VERSION 5.8 ;
BUSBITCHARS "[]" ;
DIVIDERCHAR "/" ;
UNITS
    DATABASE MICRONS 1000 ;
END UNITS

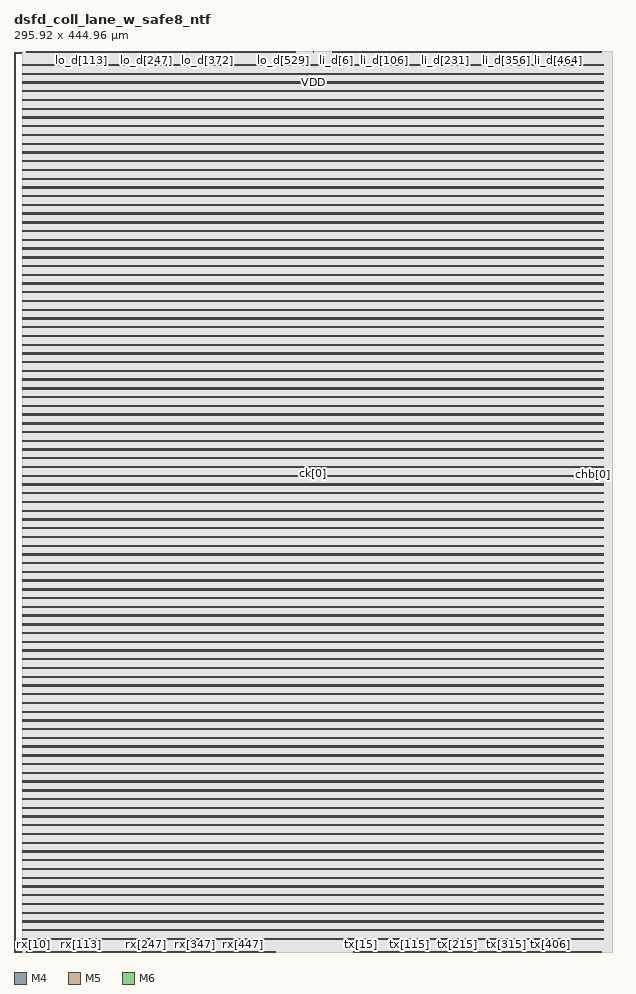
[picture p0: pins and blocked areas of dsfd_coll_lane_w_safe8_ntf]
MACRO dsfd_coll_lane_w_safe8_ntf
  FOREIGN dsfd_coll_lane_w_safe8_ntf 0 0 ;
  CLASS BLOCK ;
  SIZE 295.92 BY 444.96 ;
  PIN chb[0]
    DIRECTION INPUT ;
    USE SIGNAL ;
    PORT
      LAYER M4 ;
        RECT  295.836 236.016 295.92 236.04 ;
    END
  END chb[0]
  PIN ck[0]
    DIRECTION INPUT ;
    USE SIGNAL ;
    PORT
      LAYER M5 ;
        RECT  147.924 236.232 147.972 236.76 ;
    END
  END ck[0]
  PIN flt[0]
    DIRECTION OUTPUT ;
    USE SIGNAL ;
    PORT
      LAYER M4 ;
        RECT  295.836 234.576 295.92 234.6 ;
    END
  END flt[0]
  PIN flt[1]
    DIRECTION OUTPUT ;
    USE SIGNAL ;
    PORT
      LAYER M4 ;
        RECT  295.836 235.056 295.92 235.08 ;
    END
  END flt[1]
  PIN flt[2]
    DIRECTION OUTPUT ;
    USE SIGNAL ;
    PORT
      LAYER M4 ;
        RECT  295.836 235.536 295.92 235.56 ;
    END
  END flt[2]
  PIN li_d[0]
    DIRECTION OUTPUT ;
    USE SIGNAL ;
    PORT
      LAYER M5 ;
        RECT  157.92 444.876 157.944 444.96 ;
    END
  END li_d[0]
  PIN li_d[100]
    DIRECTION OUTPUT ;
    USE SIGNAL ;
    PORT
      LAYER M5 ;
        RECT  181.92 444.876 181.944 444.96 ;
    END
  END li_d[100]
  PIN li_d[101]
    DIRECTION OUTPUT ;
    USE SIGNAL ;
    PORT
      LAYER M5 ;
        RECT  182.16 444.876 182.184 444.96 ;
    END
  END li_d[101]
  PIN li_d[102]
    DIRECTION OUTPUT ;
    USE SIGNAL ;
    PORT
      LAYER M5 ;
        RECT  182.4 444.876 182.424 444.96 ;
    END
  END li_d[102]
  PIN li_d[103]
    DIRECTION OUTPUT ;
    USE SIGNAL ;
    PORT
      LAYER M5 ;
        RECT  182.64 444.876 182.664 444.96 ;
    END
  END li_d[103]
  PIN li_d[104]
    DIRECTION OUTPUT ;
    USE SIGNAL ;
    PORT
      LAYER M5 ;
        RECT  182.88 444.876 182.904 444.96 ;
    END
  END li_d[104]
  PIN li_d[105]
    DIRECTION OUTPUT ;
    USE SIGNAL ;
    PORT
      LAYER M5 ;
        RECT  183.12 444.876 183.144 444.96 ;
    END
  END li_d[105]
  PIN li_d[106]
    DIRECTION OUTPUT ;
    USE SIGNAL ;
    PORT
      LAYER M5 ;
        RECT  183.36 444.876 183.384 444.96 ;
    END
  END li_d[106]
  PIN li_d[107]
    DIRECTION OUTPUT ;
    USE SIGNAL ;
    PORT
      LAYER M5 ;
        RECT  183.6 444.876 183.624 444.96 ;
    END
  END li_d[107]
  PIN li_d[108]
    DIRECTION OUTPUT ;
    USE SIGNAL ;
    PORT
      LAYER M5 ;
        RECT  183.84 444.876 183.864 444.96 ;
    END
  END li_d[108]
  PIN li_d[109]
    DIRECTION OUTPUT ;
    USE SIGNAL ;
    PORT
      LAYER M5 ;
        RECT  184.08 444.876 184.104 444.96 ;
    END
  END li_d[109]
  PIN li_d[10]
    DIRECTION OUTPUT ;
    USE SIGNAL ;
    PORT
      LAYER M5 ;
        RECT  160.32 444.876 160.344 444.96 ;
    END
  END li_d[10]
  PIN li_d[110]
    DIRECTION OUTPUT ;
    USE SIGNAL ;
    PORT
      LAYER M5 ;
        RECT  184.32 444.876 184.344 444.96 ;
    END
  END li_d[110]
  PIN li_d[111]
    DIRECTION OUTPUT ;
    USE SIGNAL ;
    PORT
      LAYER M5 ;
        RECT  184.56 444.876 184.584 444.96 ;
    END
  END li_d[111]
  PIN li_d[112]
    DIRECTION OUTPUT ;
    USE SIGNAL ;
    PORT
      LAYER M5 ;
        RECT  184.8 444.876 184.824 444.96 ;
    END
  END li_d[112]
  PIN li_d[113]
    DIRECTION OUTPUT ;
    USE SIGNAL ;
    PORT
      LAYER M5 ;
        RECT  185.04 444.876 185.064 444.96 ;
    END
  END li_d[113]
  PIN li_d[114]
    DIRECTION OUTPUT ;
    USE SIGNAL ;
    PORT
      LAYER M5 ;
        RECT  185.28 444.876 185.304 444.96 ;
    END
  END li_d[114]
  PIN li_d[115]
    DIRECTION OUTPUT ;
    USE SIGNAL ;
    PORT
      LAYER M5 ;
        RECT  185.52 444.876 185.544 444.96 ;
    END
  END li_d[115]
  PIN li_d[116]
    DIRECTION OUTPUT ;
    USE SIGNAL ;
    PORT
      LAYER M5 ;
        RECT  185.76 444.876 185.784 444.96 ;
    END
  END li_d[116]
  PIN li_d[117]
    DIRECTION OUTPUT ;
    USE SIGNAL ;
    PORT
      LAYER M5 ;
        RECT  186 444.876 186.024 444.96 ;
    END
  END li_d[117]
  PIN li_d[118]
    DIRECTION OUTPUT ;
    USE SIGNAL ;
    PORT
      LAYER M5 ;
        RECT  186.24 444.876 186.264 444.96 ;
    END
  END li_d[118]
  PIN li_d[119]
    DIRECTION OUTPUT ;
    USE SIGNAL ;
    PORT
      LAYER M5 ;
        RECT  186.48 444.876 186.504 444.96 ;
    END
  END li_d[119]
  PIN li_d[11]
    DIRECTION OUTPUT ;
    USE SIGNAL ;
    PORT
      LAYER M5 ;
        RECT  160.56 444.876 160.584 444.96 ;
    END
  END li_d[11]
  PIN li_d[120]
    DIRECTION OUTPUT ;
    USE SIGNAL ;
    PORT
      LAYER M5 ;
        RECT  186.72 444.876 186.744 444.96 ;
    END
  END li_d[120]
  PIN li_d[121]
    DIRECTION OUTPUT ;
    USE SIGNAL ;
    PORT
      LAYER M5 ;
        RECT  186.96 444.876 186.984 444.96 ;
    END
  END li_d[121]
  PIN li_d[122]
    DIRECTION OUTPUT ;
    USE SIGNAL ;
    PORT
      LAYER M5 ;
        RECT  187.2 444.876 187.224 444.96 ;
    END
  END li_d[122]
  PIN li_d[123]
    DIRECTION OUTPUT ;
    USE SIGNAL ;
    PORT
      LAYER M5 ;
        RECT  187.44 444.876 187.464 444.96 ;
    END
  END li_d[123]
  PIN li_d[124]
    DIRECTION OUTPUT ;
    USE SIGNAL ;
    PORT
      LAYER M5 ;
        RECT  187.68 444.876 187.704 444.96 ;
    END
  END li_d[124]
  PIN li_d[125]
    DIRECTION OUTPUT ;
    USE SIGNAL ;
    PORT
      LAYER M5 ;
        RECT  187.92 444.876 187.944 444.96 ;
    END
  END li_d[125]
  PIN li_d[126]
    DIRECTION OUTPUT ;
    USE SIGNAL ;
    PORT
      LAYER M5 ;
        RECT  188.16 444.876 188.184 444.96 ;
    END
  END li_d[126]
  PIN li_d[127]
    DIRECTION OUTPUT ;
    USE SIGNAL ;
    PORT
      LAYER M5 ;
        RECT  188.4 444.876 188.424 444.96 ;
    END
  END li_d[127]
  PIN li_d[128]
    DIRECTION OUTPUT ;
    USE SIGNAL ;
    PORT
      LAYER M5 ;
        RECT  188.64 444.876 188.664 444.96 ;
    END
  END li_d[128]
  PIN li_d[129]
    DIRECTION OUTPUT ;
    USE SIGNAL ;
    PORT
      LAYER M5 ;
        RECT  188.88 444.876 188.904 444.96 ;
    END
  END li_d[129]
  PIN li_d[12]
    DIRECTION OUTPUT ;
    USE SIGNAL ;
    PORT
      LAYER M5 ;
        RECT  160.8 444.876 160.824 444.96 ;
    END
  END li_d[12]
  PIN li_d[130]
    DIRECTION OUTPUT ;
    USE SIGNAL ;
    PORT
      LAYER M5 ;
        RECT  189.12 444.876 189.144 444.96 ;
    END
  END li_d[130]
  PIN li_d[131]
    DIRECTION OUTPUT ;
    USE SIGNAL ;
    PORT
      LAYER M5 ;
        RECT  189.36 444.876 189.384 444.96 ;
    END
  END li_d[131]
  PIN li_d[132]
    DIRECTION OUTPUT ;
    USE SIGNAL ;
    PORT
      LAYER M5 ;
        RECT  189.6 444.876 189.624 444.96 ;
    END
  END li_d[132]
  PIN li_d[133]
    DIRECTION OUTPUT ;
    USE SIGNAL ;
    PORT
      LAYER M5 ;
        RECT  189.84 444.876 189.864 444.96 ;
    END
  END li_d[133]
  PIN li_d[134]
    DIRECTION OUTPUT ;
    USE SIGNAL ;
    PORT
      LAYER M5 ;
        RECT  190.08 444.876 190.104 444.96 ;
    END
  END li_d[134]
  PIN li_d[135]
    DIRECTION OUTPUT ;
    USE SIGNAL ;
    PORT
      LAYER M5 ;
        RECT  190.32 444.876 190.344 444.96 ;
    END
  END li_d[135]
  PIN li_d[136]
    DIRECTION OUTPUT ;
    USE SIGNAL ;
    PORT
      LAYER M5 ;
        RECT  190.56 444.876 190.584 444.96 ;
    END
  END li_d[136]
  PIN li_d[137]
    DIRECTION OUTPUT ;
    USE SIGNAL ;
    PORT
      LAYER M5 ;
        RECT  190.8 444.876 190.824 444.96 ;
    END
  END li_d[137]
  PIN li_d[138]
    DIRECTION OUTPUT ;
    USE SIGNAL ;
    PORT
      LAYER M5 ;
        RECT  191.04 444.876 191.064 444.96 ;
    END
  END li_d[138]
  PIN li_d[139]
    DIRECTION OUTPUT ;
    USE SIGNAL ;
    PORT
      LAYER M5 ;
        RECT  191.28 444.876 191.304 444.96 ;
    END
  END li_d[139]
  PIN li_d[13]
    DIRECTION OUTPUT ;
    USE SIGNAL ;
    PORT
      LAYER M5 ;
        RECT  161.04 444.876 161.064 444.96 ;
    END
  END li_d[13]
  PIN li_d[140]
    DIRECTION OUTPUT ;
    USE SIGNAL ;
    PORT
      LAYER M5 ;
        RECT  191.52 444.876 191.544 444.96 ;
    END
  END li_d[140]
  PIN li_d[141]
    DIRECTION OUTPUT ;
    USE SIGNAL ;
    PORT
      LAYER M5 ;
        RECT  191.76 444.876 191.784 444.96 ;
    END
  END li_d[141]
  PIN li_d[142]
    DIRECTION OUTPUT ;
    USE SIGNAL ;
    PORT
      LAYER M5 ;
        RECT  192 444.876 192.024 444.96 ;
    END
  END li_d[142]
  PIN li_d[143]
    DIRECTION OUTPUT ;
    USE SIGNAL ;
    PORT
      LAYER M5 ;
        RECT  192.24 444.876 192.264 444.96 ;
    END
  END li_d[143]
  PIN li_d[144]
    DIRECTION OUTPUT ;
    USE SIGNAL ;
    PORT
      LAYER M5 ;
        RECT  192.48 444.876 192.504 444.96 ;
    END
  END li_d[144]
  PIN li_d[145]
    DIRECTION OUTPUT ;
    USE SIGNAL ;
    PORT
      LAYER M5 ;
        RECT  192.72 444.876 192.744 444.96 ;
    END
  END li_d[145]
  PIN li_d[146]
    DIRECTION OUTPUT ;
    USE SIGNAL ;
    PORT
      LAYER M5 ;
        RECT  192.96 444.876 192.984 444.96 ;
    END
  END li_d[146]
  PIN li_d[147]
    DIRECTION OUTPUT ;
    USE SIGNAL ;
    PORT
      LAYER M5 ;
        RECT  193.2 444.876 193.224 444.96 ;
    END
  END li_d[147]
  PIN li_d[148]
    DIRECTION OUTPUT ;
    USE SIGNAL ;
    PORT
      LAYER M5 ;
        RECT  193.44 444.876 193.464 444.96 ;
    END
  END li_d[148]
  PIN li_d[149]
    DIRECTION OUTPUT ;
    USE SIGNAL ;
    PORT
      LAYER M5 ;
        RECT  193.68 444.876 193.704 444.96 ;
    END
  END li_d[149]
  PIN li_d[14]
    DIRECTION OUTPUT ;
    USE SIGNAL ;
    PORT
      LAYER M5 ;
        RECT  161.28 444.876 161.304 444.96 ;
    END
  END li_d[14]
  PIN li_d[150]
    DIRECTION OUTPUT ;
    USE SIGNAL ;
    PORT
      LAYER M5 ;
        RECT  193.92 444.876 193.944 444.96 ;
    END
  END li_d[150]
  PIN li_d[151]
    DIRECTION OUTPUT ;
    USE SIGNAL ;
    PORT
      LAYER M5 ;
        RECT  194.16 444.876 194.184 444.96 ;
    END
  END li_d[151]
  PIN li_d[152]
    DIRECTION OUTPUT ;
    USE SIGNAL ;
    PORT
      LAYER M5 ;
        RECT  194.4 444.876 194.424 444.96 ;
    END
  END li_d[152]
  PIN li_d[153]
    DIRECTION OUTPUT ;
    USE SIGNAL ;
    PORT
      LAYER M5 ;
        RECT  194.64 444.876 194.664 444.96 ;
    END
  END li_d[153]
  PIN li_d[154]
    DIRECTION OUTPUT ;
    USE SIGNAL ;
    PORT
      LAYER M5 ;
        RECT  194.88 444.876 194.904 444.96 ;
    END
  END li_d[154]
  PIN li_d[155]
    DIRECTION OUTPUT ;
    USE SIGNAL ;
    PORT
      LAYER M5 ;
        RECT  195.12 444.876 195.144 444.96 ;
    END
  END li_d[155]
  PIN li_d[156]
    DIRECTION OUTPUT ;
    USE SIGNAL ;
    PORT
      LAYER M5 ;
        RECT  195.36 444.876 195.384 444.96 ;
    END
  END li_d[156]
  PIN li_d[157]
    DIRECTION OUTPUT ;
    USE SIGNAL ;
    PORT
      LAYER M5 ;
        RECT  195.6 444.876 195.624 444.96 ;
    END
  END li_d[157]
  PIN li_d[158]
    DIRECTION OUTPUT ;
    USE SIGNAL ;
    PORT
      LAYER M5 ;
        RECT  195.84 444.876 195.864 444.96 ;
    END
  END li_d[158]
  PIN li_d[159]
    DIRECTION OUTPUT ;
    USE SIGNAL ;
    PORT
      LAYER M5 ;
        RECT  196.08 444.876 196.104 444.96 ;
    END
  END li_d[159]
  PIN li_d[15]
    DIRECTION OUTPUT ;
    USE SIGNAL ;
    PORT
      LAYER M5 ;
        RECT  161.52 444.876 161.544 444.96 ;
    END
  END li_d[15]
  PIN li_d[160]
    DIRECTION OUTPUT ;
    USE SIGNAL ;
    PORT
      LAYER M5 ;
        RECT  196.32 444.876 196.344 444.96 ;
    END
  END li_d[160]
  PIN li_d[161]
    DIRECTION OUTPUT ;
    USE SIGNAL ;
    PORT
      LAYER M5 ;
        RECT  196.56 444.876 196.584 444.96 ;
    END
  END li_d[161]
  PIN li_d[162]
    DIRECTION OUTPUT ;
    USE SIGNAL ;
    PORT
      LAYER M5 ;
        RECT  196.8 444.876 196.824 444.96 ;
    END
  END li_d[162]
  PIN li_d[163]
    DIRECTION OUTPUT ;
    USE SIGNAL ;
    PORT
      LAYER M5 ;
        RECT  197.04 444.876 197.064 444.96 ;
    END
  END li_d[163]
  PIN li_d[164]
    DIRECTION OUTPUT ;
    USE SIGNAL ;
    PORT
      LAYER M5 ;
        RECT  197.28 444.876 197.304 444.96 ;
    END
  END li_d[164]
  PIN li_d[165]
    DIRECTION OUTPUT ;
    USE SIGNAL ;
    PORT
      LAYER M5 ;
        RECT  197.52 444.876 197.544 444.96 ;
    END
  END li_d[165]
  PIN li_d[166]
    DIRECTION OUTPUT ;
    USE SIGNAL ;
    PORT
      LAYER M5 ;
        RECT  197.76 444.876 197.784 444.96 ;
    END
  END li_d[166]
  PIN li_d[167]
    DIRECTION OUTPUT ;
    USE SIGNAL ;
    PORT
      LAYER M5 ;
        RECT  198 444.876 198.024 444.96 ;
    END
  END li_d[167]
  PIN li_d[168]
    DIRECTION OUTPUT ;
    USE SIGNAL ;
    PORT
      LAYER M5 ;
        RECT  198.24 444.876 198.264 444.96 ;
    END
  END li_d[168]
  PIN li_d[169]
    DIRECTION OUTPUT ;
    USE SIGNAL ;
    PORT
      LAYER M5 ;
        RECT  198.48 444.876 198.504 444.96 ;
    END
  END li_d[169]
  PIN li_d[16]
    DIRECTION OUTPUT ;
    USE SIGNAL ;
    PORT
      LAYER M5 ;
        RECT  161.76 444.876 161.784 444.96 ;
    END
  END li_d[16]
  PIN li_d[170]
    DIRECTION OUTPUT ;
    USE SIGNAL ;
    PORT
      LAYER M5 ;
        RECT  198.72 444.876 198.744 444.96 ;
    END
  END li_d[170]
  PIN li_d[171]
    DIRECTION OUTPUT ;
    USE SIGNAL ;
    PORT
      LAYER M5 ;
        RECT  198.96 444.876 198.984 444.96 ;
    END
  END li_d[171]
  PIN li_d[172]
    DIRECTION OUTPUT ;
    USE SIGNAL ;
    PORT
      LAYER M5 ;
        RECT  199.2 444.876 199.224 444.96 ;
    END
  END li_d[172]
  PIN li_d[173]
    DIRECTION OUTPUT ;
    USE SIGNAL ;
    PORT
      LAYER M5 ;
        RECT  199.44 444.876 199.464 444.96 ;
    END
  END li_d[173]
  PIN li_d[174]
    DIRECTION OUTPUT ;
    USE SIGNAL ;
    PORT
      LAYER M5 ;
        RECT  199.68 444.876 199.704 444.96 ;
    END
  END li_d[174]
  PIN li_d[175]
    DIRECTION OUTPUT ;
    USE SIGNAL ;
    PORT
      LAYER M5 ;
        RECT  199.92 444.876 199.944 444.96 ;
    END
  END li_d[175]
  PIN li_d[176]
    DIRECTION OUTPUT ;
    USE SIGNAL ;
    PORT
      LAYER M5 ;
        RECT  200.16 444.876 200.184 444.96 ;
    END
  END li_d[176]
  PIN li_d[177]
    DIRECTION OUTPUT ;
    USE SIGNAL ;
    PORT
      LAYER M5 ;
        RECT  200.4 444.876 200.424 444.96 ;
    END
  END li_d[177]
  PIN li_d[178]
    DIRECTION OUTPUT ;
    USE SIGNAL ;
    PORT
      LAYER M5 ;
        RECT  200.64 444.876 200.664 444.96 ;
    END
  END li_d[178]
  PIN li_d[179]
    DIRECTION OUTPUT ;
    USE SIGNAL ;
    PORT
      LAYER M5 ;
        RECT  200.88 444.876 200.904 444.96 ;
    END
  END li_d[179]
  PIN li_d[17]
    DIRECTION OUTPUT ;
    USE SIGNAL ;
    PORT
      LAYER M5 ;
        RECT  162 444.876 162.024 444.96 ;
    END
  END li_d[17]
  PIN li_d[180]
    DIRECTION OUTPUT ;
    USE SIGNAL ;
    PORT
      LAYER M5 ;
        RECT  201.12 444.876 201.144 444.96 ;
    END
  END li_d[180]
  PIN li_d[181]
    DIRECTION OUTPUT ;
    USE SIGNAL ;
    PORT
      LAYER M5 ;
        RECT  201.36 444.876 201.384 444.96 ;
    END
  END li_d[181]
  PIN li_d[182]
    DIRECTION OUTPUT ;
    USE SIGNAL ;
    PORT
      LAYER M5 ;
        RECT  201.6 444.876 201.624 444.96 ;
    END
  END li_d[182]
  PIN li_d[183]
    DIRECTION OUTPUT ;
    USE SIGNAL ;
    PORT
      LAYER M5 ;
        RECT  201.84 444.876 201.864 444.96 ;
    END
  END li_d[183]
  PIN li_d[184]
    DIRECTION OUTPUT ;
    USE SIGNAL ;
    PORT
      LAYER M5 ;
        RECT  202.08 444.876 202.104 444.96 ;
    END
  END li_d[184]
  PIN li_d[185]
    DIRECTION OUTPUT ;
    USE SIGNAL ;
    PORT
      LAYER M5 ;
        RECT  202.32 444.876 202.344 444.96 ;
    END
  END li_d[185]
  PIN li_d[186]
    DIRECTION OUTPUT ;
    USE SIGNAL ;
    PORT
      LAYER M5 ;
        RECT  202.56 444.876 202.584 444.96 ;
    END
  END li_d[186]
  PIN li_d[187]
    DIRECTION OUTPUT ;
    USE SIGNAL ;
    PORT
      LAYER M5 ;
        RECT  202.8 444.876 202.824 444.96 ;
    END
  END li_d[187]
  PIN li_d[188]
    DIRECTION OUTPUT ;
    USE SIGNAL ;
    PORT
      LAYER M5 ;
        RECT  203.04 444.876 203.064 444.96 ;
    END
  END li_d[188]
  PIN li_d[189]
    DIRECTION OUTPUT ;
    USE SIGNAL ;
    PORT
      LAYER M5 ;
        RECT  203.28 444.876 203.304 444.96 ;
    END
  END li_d[189]
  PIN li_d[18]
    DIRECTION OUTPUT ;
    USE SIGNAL ;
    PORT
      LAYER M5 ;
        RECT  162.24 444.876 162.264 444.96 ;
    END
  END li_d[18]
  PIN li_d[190]
    DIRECTION OUTPUT ;
    USE SIGNAL ;
    PORT
      LAYER M5 ;
        RECT  203.52 444.876 203.544 444.96 ;
    END
  END li_d[190]
  PIN li_d[191]
    DIRECTION OUTPUT ;
    USE SIGNAL ;
    PORT
      LAYER M5 ;
        RECT  203.76 444.876 203.784 444.96 ;
    END
  END li_d[191]
  PIN li_d[192]
    DIRECTION OUTPUT ;
    USE SIGNAL ;
    PORT
      LAYER M5 ;
        RECT  204 444.876 204.024 444.96 ;
    END
  END li_d[192]
  PIN li_d[193]
    DIRECTION OUTPUT ;
    USE SIGNAL ;
    PORT
      LAYER M5 ;
        RECT  204.24 444.876 204.264 444.96 ;
    END
  END li_d[193]
  PIN li_d[194]
    DIRECTION OUTPUT ;
    USE SIGNAL ;
    PORT
      LAYER M5 ;
        RECT  204.48 444.876 204.504 444.96 ;
    END
  END li_d[194]
  PIN li_d[195]
    DIRECTION OUTPUT ;
    USE SIGNAL ;
    PORT
      LAYER M5 ;
        RECT  204.72 444.876 204.744 444.96 ;
    END
  END li_d[195]
  PIN li_d[196]
    DIRECTION OUTPUT ;
    USE SIGNAL ;
    PORT
      LAYER M5 ;
        RECT  204.96 444.876 204.984 444.96 ;
    END
  END li_d[196]
  PIN li_d[197]
    DIRECTION OUTPUT ;
    USE SIGNAL ;
    PORT
      LAYER M5 ;
        RECT  205.2 444.876 205.224 444.96 ;
    END
  END li_d[197]
  PIN li_d[198]
    DIRECTION OUTPUT ;
    USE SIGNAL ;
    PORT
      LAYER M5 ;
        RECT  205.44 444.876 205.464 444.96 ;
    END
  END li_d[198]
  PIN li_d[199]
    DIRECTION OUTPUT ;
    USE SIGNAL ;
    PORT
      LAYER M5 ;
        RECT  205.68 444.876 205.704 444.96 ;
    END
  END li_d[199]
  PIN li_d[19]
    DIRECTION OUTPUT ;
    USE SIGNAL ;
    PORT
      LAYER M5 ;
        RECT  162.48 444.876 162.504 444.96 ;
    END
  END li_d[19]
  PIN li_d[1]
    DIRECTION OUTPUT ;
    USE SIGNAL ;
    PORT
      LAYER M5 ;
        RECT  158.16 444.876 158.184 444.96 ;
    END
  END li_d[1]
  PIN li_d[200]
    DIRECTION OUTPUT ;
    USE SIGNAL ;
    PORT
      LAYER M5 ;
        RECT  205.92 444.876 205.944 444.96 ;
    END
  END li_d[200]
  PIN li_d[201]
    DIRECTION OUTPUT ;
    USE SIGNAL ;
    PORT
      LAYER M5 ;
        RECT  206.16 444.876 206.184 444.96 ;
    END
  END li_d[201]
  PIN li_d[202]
    DIRECTION OUTPUT ;
    USE SIGNAL ;
    PORT
      LAYER M5 ;
        RECT  206.4 444.876 206.424 444.96 ;
    END
  END li_d[202]
  PIN li_d[203]
    DIRECTION OUTPUT ;
    USE SIGNAL ;
    PORT
      LAYER M5 ;
        RECT  206.64 444.876 206.664 444.96 ;
    END
  END li_d[203]
  PIN li_d[204]
    DIRECTION OUTPUT ;
    USE SIGNAL ;
    PORT
      LAYER M5 ;
        RECT  206.88 444.876 206.904 444.96 ;
    END
  END li_d[204]
  PIN li_d[205]
    DIRECTION OUTPUT ;
    USE SIGNAL ;
    PORT
      LAYER M5 ;
        RECT  207.12 444.876 207.144 444.96 ;
    END
  END li_d[205]
  PIN li_d[206]
    DIRECTION OUTPUT ;
    USE SIGNAL ;
    PORT
      LAYER M5 ;
        RECT  207.36 444.876 207.384 444.96 ;
    END
  END li_d[206]
  PIN li_d[207]
    DIRECTION OUTPUT ;
    USE SIGNAL ;
    PORT
      LAYER M5 ;
        RECT  207.6 444.876 207.624 444.96 ;
    END
  END li_d[207]
  PIN li_d[208]
    DIRECTION OUTPUT ;
    USE SIGNAL ;
    PORT
      LAYER M5 ;
        RECT  207.84 444.876 207.864 444.96 ;
    END
  END li_d[208]
  PIN li_d[209]
    DIRECTION OUTPUT ;
    USE SIGNAL ;
    PORT
      LAYER M5 ;
        RECT  208.08 444.876 208.104 444.96 ;
    END
  END li_d[209]
  PIN li_d[20]
    DIRECTION OUTPUT ;
    USE SIGNAL ;
    PORT
      LAYER M5 ;
        RECT  162.72 444.876 162.744 444.96 ;
    END
  END li_d[20]
  PIN li_d[210]
    DIRECTION OUTPUT ;
    USE SIGNAL ;
    PORT
      LAYER M5 ;
        RECT  208.32 444.876 208.344 444.96 ;
    END
  END li_d[210]
  PIN li_d[211]
    DIRECTION OUTPUT ;
    USE SIGNAL ;
    PORT
      LAYER M5 ;
        RECT  208.56 444.876 208.584 444.96 ;
    END
  END li_d[211]
  PIN li_d[212]
    DIRECTION OUTPUT ;
    USE SIGNAL ;
    PORT
      LAYER M5 ;
        RECT  208.8 444.876 208.824 444.96 ;
    END
  END li_d[212]
  PIN li_d[213]
    DIRECTION OUTPUT ;
    USE SIGNAL ;
    PORT
      LAYER M5 ;
        RECT  209.04 444.876 209.064 444.96 ;
    END
  END li_d[213]
  PIN li_d[214]
    DIRECTION OUTPUT ;
    USE SIGNAL ;
    PORT
      LAYER M5 ;
        RECT  209.28 444.876 209.304 444.96 ;
    END
  END li_d[214]
  PIN li_d[215]
    DIRECTION OUTPUT ;
    USE SIGNAL ;
    PORT
      LAYER M5 ;
        RECT  209.52 444.876 209.544 444.96 ;
    END
  END li_d[215]
  PIN li_d[216]
    DIRECTION OUTPUT ;
    USE SIGNAL ;
    PORT
      LAYER M5 ;
        RECT  209.76 444.876 209.784 444.96 ;
    END
  END li_d[216]
  PIN li_d[217]
    DIRECTION OUTPUT ;
    USE SIGNAL ;
    PORT
      LAYER M5 ;
        RECT  210 444.876 210.024 444.96 ;
    END
  END li_d[217]
  PIN li_d[218]
    DIRECTION OUTPUT ;
    USE SIGNAL ;
    PORT
      LAYER M5 ;
        RECT  210.24 444.876 210.264 444.96 ;
    END
  END li_d[218]
  PIN li_d[219]
    DIRECTION OUTPUT ;
    USE SIGNAL ;
    PORT
      LAYER M5 ;
        RECT  210.48 444.876 210.504 444.96 ;
    END
  END li_d[219]
  PIN li_d[21]
    DIRECTION OUTPUT ;
    USE SIGNAL ;
    PORT
      LAYER M5 ;
        RECT  162.96 444.876 162.984 444.96 ;
    END
  END li_d[21]
  PIN li_d[220]
    DIRECTION OUTPUT ;
    USE SIGNAL ;
    PORT
      LAYER M5 ;
        RECT  210.72 444.876 210.744 444.96 ;
    END
  END li_d[220]
  PIN li_d[221]
    DIRECTION OUTPUT ;
    USE SIGNAL ;
    PORT
      LAYER M5 ;
        RECT  210.96 444.876 210.984 444.96 ;
    END
  END li_d[221]
  PIN li_d[222]
    DIRECTION OUTPUT ;
    USE SIGNAL ;
    PORT
      LAYER M5 ;
        RECT  211.2 444.876 211.224 444.96 ;
    END
  END li_d[222]
  PIN li_d[223]
    DIRECTION OUTPUT ;
    USE SIGNAL ;
    PORT
      LAYER M5 ;
        RECT  211.44 444.876 211.464 444.96 ;
    END
  END li_d[223]
  PIN li_d[224]
    DIRECTION OUTPUT ;
    USE SIGNAL ;
    PORT
      LAYER M5 ;
        RECT  211.68 444.876 211.704 444.96 ;
    END
  END li_d[224]
  PIN li_d[225]
    DIRECTION OUTPUT ;
    USE SIGNAL ;
    PORT
      LAYER M5 ;
        RECT  211.92 444.876 211.944 444.96 ;
    END
  END li_d[225]
  PIN li_d[226]
    DIRECTION OUTPUT ;
    USE SIGNAL ;
    PORT
      LAYER M5 ;
        RECT  212.16 444.876 212.184 444.96 ;
    END
  END li_d[226]
  PIN li_d[227]
    DIRECTION OUTPUT ;
    USE SIGNAL ;
    PORT
      LAYER M5 ;
        RECT  212.4 444.876 212.424 444.96 ;
    END
  END li_d[227]
  PIN li_d[228]
    DIRECTION OUTPUT ;
    USE SIGNAL ;
    PORT
      LAYER M5 ;
        RECT  212.64 444.876 212.664 444.96 ;
    END
  END li_d[228]
  PIN li_d[229]
    DIRECTION OUTPUT ;
    USE SIGNAL ;
    PORT
      LAYER M5 ;
        RECT  212.88 444.876 212.904 444.96 ;
    END
  END li_d[229]
  PIN li_d[22]
    DIRECTION OUTPUT ;
    USE SIGNAL ;
    PORT
      LAYER M5 ;
        RECT  163.2 444.876 163.224 444.96 ;
    END
  END li_d[22]
  PIN li_d[230]
    DIRECTION OUTPUT ;
    USE SIGNAL ;
    PORT
      LAYER M5 ;
        RECT  213.12 444.876 213.144 444.96 ;
    END
  END li_d[230]
  PIN li_d[231]
    DIRECTION OUTPUT ;
    USE SIGNAL ;
    PORT
      LAYER M5 ;
        RECT  213.36 444.876 213.384 444.96 ;
    END
  END li_d[231]
  PIN li_d[232]
    DIRECTION OUTPUT ;
    USE SIGNAL ;
    PORT
      LAYER M5 ;
        RECT  213.6 444.876 213.624 444.96 ;
    END
  END li_d[232]
  PIN li_d[233]
    DIRECTION OUTPUT ;
    USE SIGNAL ;
    PORT
      LAYER M5 ;
        RECT  213.84 444.876 213.864 444.96 ;
    END
  END li_d[233]
  PIN li_d[234]
    DIRECTION OUTPUT ;
    USE SIGNAL ;
    PORT
      LAYER M5 ;
        RECT  214.08 444.876 214.104 444.96 ;
    END
  END li_d[234]
  PIN li_d[235]
    DIRECTION OUTPUT ;
    USE SIGNAL ;
    PORT
      LAYER M5 ;
        RECT  214.32 444.876 214.344 444.96 ;
    END
  END li_d[235]
  PIN li_d[236]
    DIRECTION OUTPUT ;
    USE SIGNAL ;
    PORT
      LAYER M5 ;
        RECT  214.56 444.876 214.584 444.96 ;
    END
  END li_d[236]
  PIN li_d[237]
    DIRECTION OUTPUT ;
    USE SIGNAL ;
    PORT
      LAYER M5 ;
        RECT  214.8 444.876 214.824 444.96 ;
    END
  END li_d[237]
  PIN li_d[238]
    DIRECTION OUTPUT ;
    USE SIGNAL ;
    PORT
      LAYER M5 ;
        RECT  215.04 444.876 215.064 444.96 ;
    END
  END li_d[238]
  PIN li_d[239]
    DIRECTION OUTPUT ;
    USE SIGNAL ;
    PORT
      LAYER M5 ;
        RECT  215.28 444.876 215.304 444.96 ;
    END
  END li_d[239]
  PIN li_d[23]
    DIRECTION OUTPUT ;
    USE SIGNAL ;
    PORT
      LAYER M5 ;
        RECT  163.44 444.876 163.464 444.96 ;
    END
  END li_d[23]
  PIN li_d[240]
    DIRECTION OUTPUT ;
    USE SIGNAL ;
    PORT
      LAYER M5 ;
        RECT  215.52 444.876 215.544 444.96 ;
    END
  END li_d[240]
  PIN li_d[241]
    DIRECTION OUTPUT ;
    USE SIGNAL ;
    PORT
      LAYER M5 ;
        RECT  215.76 444.876 215.784 444.96 ;
    END
  END li_d[241]
  PIN li_d[242]
    DIRECTION OUTPUT ;
    USE SIGNAL ;
    PORT
      LAYER M5 ;
        RECT  216 444.876 216.024 444.96 ;
    END
  END li_d[242]
  PIN li_d[243]
    DIRECTION OUTPUT ;
    USE SIGNAL ;
    PORT
      LAYER M5 ;
        RECT  216.24 444.876 216.264 444.96 ;
    END
  END li_d[243]
  PIN li_d[244]
    DIRECTION OUTPUT ;
    USE SIGNAL ;
    PORT
      LAYER M5 ;
        RECT  216.48 444.876 216.504 444.96 ;
    END
  END li_d[244]
  PIN li_d[245]
    DIRECTION OUTPUT ;
    USE SIGNAL ;
    PORT
      LAYER M5 ;
        RECT  216.72 444.876 216.744 444.96 ;
    END
  END li_d[245]
  PIN li_d[246]
    DIRECTION OUTPUT ;
    USE SIGNAL ;
    PORT
      LAYER M5 ;
        RECT  216.96 444.876 216.984 444.96 ;
    END
  END li_d[246]
  PIN li_d[247]
    DIRECTION OUTPUT ;
    USE SIGNAL ;
    PORT
      LAYER M5 ;
        RECT  217.2 444.876 217.224 444.96 ;
    END
  END li_d[247]
  PIN li_d[248]
    DIRECTION OUTPUT ;
    USE SIGNAL ;
    PORT
      LAYER M5 ;
        RECT  217.44 444.876 217.464 444.96 ;
    END
  END li_d[248]
  PIN li_d[249]
    DIRECTION OUTPUT ;
    USE SIGNAL ;
    PORT
      LAYER M5 ;
        RECT  217.68 444.876 217.704 444.96 ;
    END
  END li_d[249]
  PIN li_d[24]
    DIRECTION OUTPUT ;
    USE SIGNAL ;
    PORT
      LAYER M5 ;
        RECT  163.68 444.876 163.704 444.96 ;
    END
  END li_d[24]
  PIN li_d[250]
    DIRECTION OUTPUT ;
    USE SIGNAL ;
    PORT
      LAYER M5 ;
        RECT  217.92 444.876 217.944 444.96 ;
    END
  END li_d[250]
  PIN li_d[251]
    DIRECTION OUTPUT ;
    USE SIGNAL ;
    PORT
      LAYER M5 ;
        RECT  218.16 444.876 218.184 444.96 ;
    END
  END li_d[251]
  PIN li_d[252]
    DIRECTION OUTPUT ;
    USE SIGNAL ;
    PORT
      LAYER M5 ;
        RECT  218.4 444.876 218.424 444.96 ;
    END
  END li_d[252]
  PIN li_d[253]
    DIRECTION OUTPUT ;
    USE SIGNAL ;
    PORT
      LAYER M5 ;
        RECT  218.64 444.876 218.664 444.96 ;
    END
  END li_d[253]
  PIN li_d[254]
    DIRECTION OUTPUT ;
    USE SIGNAL ;
    PORT
      LAYER M5 ;
        RECT  218.88 444.876 218.904 444.96 ;
    END
  END li_d[254]
  PIN li_d[255]
    DIRECTION OUTPUT ;
    USE SIGNAL ;
    PORT
      LAYER M5 ;
        RECT  219.12 444.876 219.144 444.96 ;
    END
  END li_d[255]
  PIN li_d[256]
    DIRECTION OUTPUT ;
    USE SIGNAL ;
    PORT
      LAYER M5 ;
        RECT  219.36 444.876 219.384 444.96 ;
    END
  END li_d[256]
  PIN li_d[257]
    DIRECTION OUTPUT ;
    USE SIGNAL ;
    PORT
      LAYER M5 ;
        RECT  219.6 444.876 219.624 444.96 ;
    END
  END li_d[257]
  PIN li_d[258]
    DIRECTION OUTPUT ;
    USE SIGNAL ;
    PORT
      LAYER M5 ;
        RECT  219.84 444.876 219.864 444.96 ;
    END
  END li_d[258]
  PIN li_d[259]
    DIRECTION OUTPUT ;
    USE SIGNAL ;
    PORT
      LAYER M5 ;
        RECT  220.08 444.876 220.104 444.96 ;
    END
  END li_d[259]
  PIN li_d[25]
    DIRECTION OUTPUT ;
    USE SIGNAL ;
    PORT
      LAYER M5 ;
        RECT  163.92 444.876 163.944 444.96 ;
    END
  END li_d[25]
  PIN li_d[260]
    DIRECTION OUTPUT ;
    USE SIGNAL ;
    PORT
      LAYER M5 ;
        RECT  220.32 444.876 220.344 444.96 ;
    END
  END li_d[260]
  PIN li_d[261]
    DIRECTION OUTPUT ;
    USE SIGNAL ;
    PORT
      LAYER M5 ;
        RECT  220.56 444.876 220.584 444.96 ;
    END
  END li_d[261]
  PIN li_d[262]
    DIRECTION OUTPUT ;
    USE SIGNAL ;
    PORT
      LAYER M5 ;
        RECT  220.8 444.876 220.824 444.96 ;
    END
  END li_d[262]
  PIN li_d[263]
    DIRECTION OUTPUT ;
    USE SIGNAL ;
    PORT
      LAYER M5 ;
        RECT  221.04 444.876 221.064 444.96 ;
    END
  END li_d[263]
  PIN li_d[264]
    DIRECTION OUTPUT ;
    USE SIGNAL ;
    PORT
      LAYER M5 ;
        RECT  221.28 444.876 221.304 444.96 ;
    END
  END li_d[264]
  PIN li_d[265]
    DIRECTION OUTPUT ;
    USE SIGNAL ;
    PORT
      LAYER M5 ;
        RECT  221.52 444.876 221.544 444.96 ;
    END
  END li_d[265]
  PIN li_d[266]
    DIRECTION OUTPUT ;
    USE SIGNAL ;
    PORT
      LAYER M5 ;
        RECT  221.76 444.876 221.784 444.96 ;
    END
  END li_d[266]
  PIN li_d[267]
    DIRECTION OUTPUT ;
    USE SIGNAL ;
    PORT
      LAYER M5 ;
        RECT  222 444.876 222.024 444.96 ;
    END
  END li_d[267]
  PIN li_d[268]
    DIRECTION OUTPUT ;
    USE SIGNAL ;
    PORT
      LAYER M5 ;
        RECT  222.24 444.876 222.264 444.96 ;
    END
  END li_d[268]
  PIN li_d[269]
    DIRECTION OUTPUT ;
    USE SIGNAL ;
    PORT
      LAYER M5 ;
        RECT  222.48 444.876 222.504 444.96 ;
    END
  END li_d[269]
  PIN li_d[26]
    DIRECTION OUTPUT ;
    USE SIGNAL ;
    PORT
      LAYER M5 ;
        RECT  164.16 444.876 164.184 444.96 ;
    END
  END li_d[26]
  PIN li_d[270]
    DIRECTION OUTPUT ;
    USE SIGNAL ;
    PORT
      LAYER M5 ;
        RECT  222.72 444.876 222.744 444.96 ;
    END
  END li_d[270]
  PIN li_d[271]
    DIRECTION OUTPUT ;
    USE SIGNAL ;
    PORT
      LAYER M5 ;
        RECT  222.96 444.876 222.984 444.96 ;
    END
  END li_d[271]
  PIN li_d[272]
    DIRECTION OUTPUT ;
    USE SIGNAL ;
    PORT
      LAYER M5 ;
        RECT  223.2 444.876 223.224 444.96 ;
    END
  END li_d[272]
  PIN li_d[273]
    DIRECTION OUTPUT ;
    USE SIGNAL ;
    PORT
      LAYER M5 ;
        RECT  223.44 444.876 223.464 444.96 ;
    END
  END li_d[273]
  PIN li_d[274]
    DIRECTION OUTPUT ;
    USE SIGNAL ;
    PORT
      LAYER M5 ;
        RECT  223.68 444.876 223.704 444.96 ;
    END
  END li_d[274]
  PIN li_d[275]
    DIRECTION OUTPUT ;
    USE SIGNAL ;
    PORT
      LAYER M5 ;
        RECT  223.92 444.876 223.944 444.96 ;
    END
  END li_d[275]
  PIN li_d[276]
    DIRECTION OUTPUT ;
    USE SIGNAL ;
    PORT
      LAYER M5 ;
        RECT  224.16 444.876 224.184 444.96 ;
    END
  END li_d[276]
  PIN li_d[277]
    DIRECTION OUTPUT ;
    USE SIGNAL ;
    PORT
      LAYER M5 ;
        RECT  224.4 444.876 224.424 444.96 ;
    END
  END li_d[277]
  PIN li_d[278]
    DIRECTION OUTPUT ;
    USE SIGNAL ;
    PORT
      LAYER M5 ;
        RECT  224.64 444.876 224.664 444.96 ;
    END
  END li_d[278]
  PIN li_d[279]
    DIRECTION OUTPUT ;
    USE SIGNAL ;
    PORT
      LAYER M5 ;
        RECT  224.88 444.876 224.904 444.96 ;
    END
  END li_d[279]
  PIN li_d[27]
    DIRECTION OUTPUT ;
    USE SIGNAL ;
    PORT
      LAYER M5 ;
        RECT  164.4 444.876 164.424 444.96 ;
    END
  END li_d[27]
  PIN li_d[280]
    DIRECTION OUTPUT ;
    USE SIGNAL ;
    PORT
      LAYER M5 ;
        RECT  225.12 444.876 225.144 444.96 ;
    END
  END li_d[280]
  PIN li_d[281]
    DIRECTION OUTPUT ;
    USE SIGNAL ;
    PORT
      LAYER M5 ;
        RECT  225.36 444.876 225.384 444.96 ;
    END
  END li_d[281]
  PIN li_d[282]
    DIRECTION OUTPUT ;
    USE SIGNAL ;
    PORT
      LAYER M5 ;
        RECT  225.6 444.876 225.624 444.96 ;
    END
  END li_d[282]
  PIN li_d[283]
    DIRECTION OUTPUT ;
    USE SIGNAL ;
    PORT
      LAYER M5 ;
        RECT  225.84 444.876 225.864 444.96 ;
    END
  END li_d[283]
  PIN li_d[284]
    DIRECTION OUTPUT ;
    USE SIGNAL ;
    PORT
      LAYER M5 ;
        RECT  226.08 444.876 226.104 444.96 ;
    END
  END li_d[284]
  PIN li_d[285]
    DIRECTION OUTPUT ;
    USE SIGNAL ;
    PORT
      LAYER M5 ;
        RECT  226.32 444.876 226.344 444.96 ;
    END
  END li_d[285]
  PIN li_d[286]
    DIRECTION OUTPUT ;
    USE SIGNAL ;
    PORT
      LAYER M5 ;
        RECT  226.56 444.876 226.584 444.96 ;
    END
  END li_d[286]
  PIN li_d[287]
    DIRECTION OUTPUT ;
    USE SIGNAL ;
    PORT
      LAYER M5 ;
        RECT  226.8 444.876 226.824 444.96 ;
    END
  END li_d[287]
  PIN li_d[288]
    DIRECTION OUTPUT ;
    USE SIGNAL ;
    PORT
      LAYER M5 ;
        RECT  227.04 444.876 227.064 444.96 ;
    END
  END li_d[288]
  PIN li_d[289]
    DIRECTION OUTPUT ;
    USE SIGNAL ;
    PORT
      LAYER M5 ;
        RECT  227.28 444.876 227.304 444.96 ;
    END
  END li_d[289]
  PIN li_d[28]
    DIRECTION OUTPUT ;
    USE SIGNAL ;
    PORT
      LAYER M5 ;
        RECT  164.64 444.876 164.664 444.96 ;
    END
  END li_d[28]
  PIN li_d[290]
    DIRECTION OUTPUT ;
    USE SIGNAL ;
    PORT
      LAYER M5 ;
        RECT  227.52 444.876 227.544 444.96 ;
    END
  END li_d[290]
  PIN li_d[291]
    DIRECTION OUTPUT ;
    USE SIGNAL ;
    PORT
      LAYER M5 ;
        RECT  227.76 444.876 227.784 444.96 ;
    END
  END li_d[291]
  PIN li_d[292]
    DIRECTION OUTPUT ;
    USE SIGNAL ;
    PORT
      LAYER M5 ;
        RECT  228 444.876 228.024 444.96 ;
    END
  END li_d[292]
  PIN li_d[293]
    DIRECTION OUTPUT ;
    USE SIGNAL ;
    PORT
      LAYER M5 ;
        RECT  228.24 444.876 228.264 444.96 ;
    END
  END li_d[293]
  PIN li_d[294]
    DIRECTION OUTPUT ;
    USE SIGNAL ;
    PORT
      LAYER M5 ;
        RECT  228.48 444.876 228.504 444.96 ;
    END
  END li_d[294]
  PIN li_d[295]
    DIRECTION OUTPUT ;
    USE SIGNAL ;
    PORT
      LAYER M5 ;
        RECT  228.72 444.876 228.744 444.96 ;
    END
  END li_d[295]
  PIN li_d[296]
    DIRECTION OUTPUT ;
    USE SIGNAL ;
    PORT
      LAYER M5 ;
        RECT  228.96 444.876 228.984 444.96 ;
    END
  END li_d[296]
  PIN li_d[297]
    DIRECTION OUTPUT ;
    USE SIGNAL ;
    PORT
      LAYER M5 ;
        RECT  229.2 444.876 229.224 444.96 ;
    END
  END li_d[297]
  PIN li_d[298]
    DIRECTION OUTPUT ;
    USE SIGNAL ;
    PORT
      LAYER M5 ;
        RECT  229.44 444.876 229.464 444.96 ;
    END
  END li_d[298]
  PIN li_d[299]
    DIRECTION OUTPUT ;
    USE SIGNAL ;
    PORT
      LAYER M5 ;
        RECT  229.68 444.876 229.704 444.96 ;
    END
  END li_d[299]
  PIN li_d[29]
    DIRECTION OUTPUT ;
    USE SIGNAL ;
    PORT
      LAYER M5 ;
        RECT  164.88 444.876 164.904 444.96 ;
    END
  END li_d[29]
  PIN li_d[2]
    DIRECTION OUTPUT ;
    USE SIGNAL ;
    PORT
      LAYER M5 ;
        RECT  158.4 444.876 158.424 444.96 ;
    END
  END li_d[2]
  PIN li_d[300]
    DIRECTION OUTPUT ;
    USE SIGNAL ;
    PORT
      LAYER M5 ;
        RECT  229.92 444.876 229.944 444.96 ;
    END
  END li_d[300]
  PIN li_d[301]
    DIRECTION OUTPUT ;
    USE SIGNAL ;
    PORT
      LAYER M5 ;
        RECT  230.16 444.876 230.184 444.96 ;
    END
  END li_d[301]
  PIN li_d[302]
    DIRECTION OUTPUT ;
    USE SIGNAL ;
    PORT
      LAYER M5 ;
        RECT  230.4 444.876 230.424 444.96 ;
    END
  END li_d[302]
  PIN li_d[303]
    DIRECTION OUTPUT ;
    USE SIGNAL ;
    PORT
      LAYER M5 ;
        RECT  230.64 444.876 230.664 444.96 ;
    END
  END li_d[303]
  PIN li_d[304]
    DIRECTION OUTPUT ;
    USE SIGNAL ;
    PORT
      LAYER M5 ;
        RECT  230.88 444.876 230.904 444.96 ;
    END
  END li_d[304]
  PIN li_d[305]
    DIRECTION OUTPUT ;
    USE SIGNAL ;
    PORT
      LAYER M5 ;
        RECT  231.12 444.876 231.144 444.96 ;
    END
  END li_d[305]
  PIN li_d[306]
    DIRECTION OUTPUT ;
    USE SIGNAL ;
    PORT
      LAYER M5 ;
        RECT  231.36 444.876 231.384 444.96 ;
    END
  END li_d[306]
  PIN li_d[307]
    DIRECTION OUTPUT ;
    USE SIGNAL ;
    PORT
      LAYER M5 ;
        RECT  231.6 444.876 231.624 444.96 ;
    END
  END li_d[307]
  PIN li_d[308]
    DIRECTION OUTPUT ;
    USE SIGNAL ;
    PORT
      LAYER M5 ;
        RECT  231.84 444.876 231.864 444.96 ;
    END
  END li_d[308]
  PIN li_d[309]
    DIRECTION OUTPUT ;
    USE SIGNAL ;
    PORT
      LAYER M5 ;
        RECT  232.08 444.876 232.104 444.96 ;
    END
  END li_d[309]
  PIN li_d[30]
    DIRECTION OUTPUT ;
    USE SIGNAL ;
    PORT
      LAYER M5 ;
        RECT  165.12 444.876 165.144 444.96 ;
    END
  END li_d[30]
  PIN li_d[310]
    DIRECTION OUTPUT ;
    USE SIGNAL ;
    PORT
      LAYER M5 ;
        RECT  232.32 444.876 232.344 444.96 ;
    END
  END li_d[310]
  PIN li_d[311]
    DIRECTION OUTPUT ;
    USE SIGNAL ;
    PORT
      LAYER M5 ;
        RECT  232.56 444.876 232.584 444.96 ;
    END
  END li_d[311]
  PIN li_d[312]
    DIRECTION OUTPUT ;
    USE SIGNAL ;
    PORT
      LAYER M5 ;
        RECT  232.8 444.876 232.824 444.96 ;
    END
  END li_d[312]
  PIN li_d[313]
    DIRECTION OUTPUT ;
    USE SIGNAL ;
    PORT
      LAYER M5 ;
        RECT  233.04 444.876 233.064 444.96 ;
    END
  END li_d[313]
  PIN li_d[314]
    DIRECTION OUTPUT ;
    USE SIGNAL ;
    PORT
      LAYER M5 ;
        RECT  233.28 444.876 233.304 444.96 ;
    END
  END li_d[314]
  PIN li_d[315]
    DIRECTION OUTPUT ;
    USE SIGNAL ;
    PORT
      LAYER M5 ;
        RECT  233.52 444.876 233.544 444.96 ;
    END
  END li_d[315]
  PIN li_d[316]
    DIRECTION OUTPUT ;
    USE SIGNAL ;
    PORT
      LAYER M5 ;
        RECT  233.76 444.876 233.784 444.96 ;
    END
  END li_d[316]
  PIN li_d[317]
    DIRECTION OUTPUT ;
    USE SIGNAL ;
    PORT
      LAYER M5 ;
        RECT  234 444.876 234.024 444.96 ;
    END
  END li_d[317]
  PIN li_d[318]
    DIRECTION OUTPUT ;
    USE SIGNAL ;
    PORT
      LAYER M5 ;
        RECT  234.24 444.876 234.264 444.96 ;
    END
  END li_d[318]
  PIN li_d[319]
    DIRECTION OUTPUT ;
    USE SIGNAL ;
    PORT
      LAYER M5 ;
        RECT  234.48 444.876 234.504 444.96 ;
    END
  END li_d[319]
  PIN li_d[31]
    DIRECTION OUTPUT ;
    USE SIGNAL ;
    PORT
      LAYER M5 ;
        RECT  165.36 444.876 165.384 444.96 ;
    END
  END li_d[31]
  PIN li_d[320]
    DIRECTION OUTPUT ;
    USE SIGNAL ;
    PORT
      LAYER M5 ;
        RECT  234.72 444.876 234.744 444.96 ;
    END
  END li_d[320]
  PIN li_d[321]
    DIRECTION OUTPUT ;
    USE SIGNAL ;
    PORT
      LAYER M5 ;
        RECT  234.96 444.876 234.984 444.96 ;
    END
  END li_d[321]
  PIN li_d[322]
    DIRECTION OUTPUT ;
    USE SIGNAL ;
    PORT
      LAYER M5 ;
        RECT  235.2 444.876 235.224 444.96 ;
    END
  END li_d[322]
  PIN li_d[323]
    DIRECTION OUTPUT ;
    USE SIGNAL ;
    PORT
      LAYER M5 ;
        RECT  235.44 444.876 235.464 444.96 ;
    END
  END li_d[323]
  PIN li_d[324]
    DIRECTION OUTPUT ;
    USE SIGNAL ;
    PORT
      LAYER M5 ;
        RECT  235.68 444.876 235.704 444.96 ;
    END
  END li_d[324]
  PIN li_d[325]
    DIRECTION OUTPUT ;
    USE SIGNAL ;
    PORT
      LAYER M5 ;
        RECT  235.92 444.876 235.944 444.96 ;
    END
  END li_d[325]
  PIN li_d[326]
    DIRECTION OUTPUT ;
    USE SIGNAL ;
    PORT
      LAYER M5 ;
        RECT  236.16 444.876 236.184 444.96 ;
    END
  END li_d[326]
  PIN li_d[327]
    DIRECTION OUTPUT ;
    USE SIGNAL ;
    PORT
      LAYER M5 ;
        RECT  236.4 444.876 236.424 444.96 ;
    END
  END li_d[327]
  PIN li_d[328]
    DIRECTION OUTPUT ;
    USE SIGNAL ;
    PORT
      LAYER M5 ;
        RECT  236.64 444.876 236.664 444.96 ;
    END
  END li_d[328]
  PIN li_d[329]
    DIRECTION OUTPUT ;
    USE SIGNAL ;
    PORT
      LAYER M5 ;
        RECT  236.88 444.876 236.904 444.96 ;
    END
  END li_d[329]
  PIN li_d[32]
    DIRECTION OUTPUT ;
    USE SIGNAL ;
    PORT
      LAYER M5 ;
        RECT  165.6 444.876 165.624 444.96 ;
    END
  END li_d[32]
  PIN li_d[330]
    DIRECTION OUTPUT ;
    USE SIGNAL ;
    PORT
      LAYER M5 ;
        RECT  237.12 444.876 237.144 444.96 ;
    END
  END li_d[330]
  PIN li_d[331]
    DIRECTION OUTPUT ;
    USE SIGNAL ;
    PORT
      LAYER M5 ;
        RECT  237.36 444.876 237.384 444.96 ;
    END
  END li_d[331]
  PIN li_d[332]
    DIRECTION OUTPUT ;
    USE SIGNAL ;
    PORT
      LAYER M5 ;
        RECT  237.6 444.876 237.624 444.96 ;
    END
  END li_d[332]
  PIN li_d[333]
    DIRECTION OUTPUT ;
    USE SIGNAL ;
    PORT
      LAYER M5 ;
        RECT  237.84 444.876 237.864 444.96 ;
    END
  END li_d[333]
  PIN li_d[334]
    DIRECTION OUTPUT ;
    USE SIGNAL ;
    PORT
      LAYER M5 ;
        RECT  238.08 444.876 238.104 444.96 ;
    END
  END li_d[334]
  PIN li_d[335]
    DIRECTION OUTPUT ;
    USE SIGNAL ;
    PORT
      LAYER M5 ;
        RECT  238.32 444.876 238.344 444.96 ;
    END
  END li_d[335]
  PIN li_d[336]
    DIRECTION OUTPUT ;
    USE SIGNAL ;
    PORT
      LAYER M5 ;
        RECT  238.56 444.876 238.584 444.96 ;
    END
  END li_d[336]
  PIN li_d[337]
    DIRECTION OUTPUT ;
    USE SIGNAL ;
    PORT
      LAYER M5 ;
        RECT  238.8 444.876 238.824 444.96 ;
    END
  END li_d[337]
  PIN li_d[338]
    DIRECTION OUTPUT ;
    USE SIGNAL ;
    PORT
      LAYER M5 ;
        RECT  239.04 444.876 239.064 444.96 ;
    END
  END li_d[338]
  PIN li_d[339]
    DIRECTION OUTPUT ;
    USE SIGNAL ;
    PORT
      LAYER M5 ;
        RECT  239.28 444.876 239.304 444.96 ;
    END
  END li_d[339]
  PIN li_d[33]
    DIRECTION OUTPUT ;
    USE SIGNAL ;
    PORT
      LAYER M5 ;
        RECT  165.84 444.876 165.864 444.96 ;
    END
  END li_d[33]
  PIN li_d[340]
    DIRECTION OUTPUT ;
    USE SIGNAL ;
    PORT
      LAYER M5 ;
        RECT  239.52 444.876 239.544 444.96 ;
    END
  END li_d[340]
  PIN li_d[341]
    DIRECTION OUTPUT ;
    USE SIGNAL ;
    PORT
      LAYER M5 ;
        RECT  239.76 444.876 239.784 444.96 ;
    END
  END li_d[341]
  PIN li_d[342]
    DIRECTION OUTPUT ;
    USE SIGNAL ;
    PORT
      LAYER M5 ;
        RECT  240 444.876 240.024 444.96 ;
    END
  END li_d[342]
  PIN li_d[343]
    DIRECTION OUTPUT ;
    USE SIGNAL ;
    PORT
      LAYER M5 ;
        RECT  240.24 444.876 240.264 444.96 ;
    END
  END li_d[343]
  PIN li_d[344]
    DIRECTION OUTPUT ;
    USE SIGNAL ;
    PORT
      LAYER M5 ;
        RECT  240.48 444.876 240.504 444.96 ;
    END
  END li_d[344]
  PIN li_d[345]
    DIRECTION OUTPUT ;
    USE SIGNAL ;
    PORT
      LAYER M5 ;
        RECT  240.72 444.876 240.744 444.96 ;
    END
  END li_d[345]
  PIN li_d[346]
    DIRECTION OUTPUT ;
    USE SIGNAL ;
    PORT
      LAYER M5 ;
        RECT  240.96 444.876 240.984 444.96 ;
    END
  END li_d[346]
  PIN li_d[347]
    DIRECTION OUTPUT ;
    USE SIGNAL ;
    PORT
      LAYER M5 ;
        RECT  241.2 444.876 241.224 444.96 ;
    END
  END li_d[347]
  PIN li_d[348]
    DIRECTION OUTPUT ;
    USE SIGNAL ;
    PORT
      LAYER M5 ;
        RECT  241.44 444.876 241.464 444.96 ;
    END
  END li_d[348]
  PIN li_d[349]
    DIRECTION OUTPUT ;
    USE SIGNAL ;
    PORT
      LAYER M5 ;
        RECT  241.68 444.876 241.704 444.96 ;
    END
  END li_d[349]
  PIN li_d[34]
    DIRECTION OUTPUT ;
    USE SIGNAL ;
    PORT
      LAYER M5 ;
        RECT  166.08 444.876 166.104 444.96 ;
    END
  END li_d[34]
  PIN li_d[350]
    DIRECTION OUTPUT ;
    USE SIGNAL ;
    PORT
      LAYER M5 ;
        RECT  241.92 444.876 241.944 444.96 ;
    END
  END li_d[350]
  PIN li_d[351]
    DIRECTION OUTPUT ;
    USE SIGNAL ;
    PORT
      LAYER M5 ;
        RECT  242.16 444.876 242.184 444.96 ;
    END
  END li_d[351]
  PIN li_d[352]
    DIRECTION OUTPUT ;
    USE SIGNAL ;
    PORT
      LAYER M5 ;
        RECT  242.4 444.876 242.424 444.96 ;
    END
  END li_d[352]
  PIN li_d[353]
    DIRECTION OUTPUT ;
    USE SIGNAL ;
    PORT
      LAYER M5 ;
        RECT  242.64 444.876 242.664 444.96 ;
    END
  END li_d[353]
  PIN li_d[354]
    DIRECTION OUTPUT ;
    USE SIGNAL ;
    PORT
      LAYER M5 ;
        RECT  242.88 444.876 242.904 444.96 ;
    END
  END li_d[354]
  PIN li_d[355]
    DIRECTION OUTPUT ;
    USE SIGNAL ;
    PORT
      LAYER M5 ;
        RECT  243.12 444.876 243.144 444.96 ;
    END
  END li_d[355]
  PIN li_d[356]
    DIRECTION OUTPUT ;
    USE SIGNAL ;
    PORT
      LAYER M5 ;
        RECT  243.36 444.876 243.384 444.96 ;
    END
  END li_d[356]
  PIN li_d[357]
    DIRECTION OUTPUT ;
    USE SIGNAL ;
    PORT
      LAYER M5 ;
        RECT  243.6 444.876 243.624 444.96 ;
    END
  END li_d[357]
  PIN li_d[358]
    DIRECTION OUTPUT ;
    USE SIGNAL ;
    PORT
      LAYER M5 ;
        RECT  243.84 444.876 243.864 444.96 ;
    END
  END li_d[358]
  PIN li_d[359]
    DIRECTION OUTPUT ;
    USE SIGNAL ;
    PORT
      LAYER M5 ;
        RECT  244.08 444.876 244.104 444.96 ;
    END
  END li_d[359]
  PIN li_d[35]
    DIRECTION OUTPUT ;
    USE SIGNAL ;
    PORT
      LAYER M5 ;
        RECT  166.32 444.876 166.344 444.96 ;
    END
  END li_d[35]
  PIN li_d[360]
    DIRECTION OUTPUT ;
    USE SIGNAL ;
    PORT
      LAYER M5 ;
        RECT  244.32 444.876 244.344 444.96 ;
    END
  END li_d[360]
  PIN li_d[361]
    DIRECTION OUTPUT ;
    USE SIGNAL ;
    PORT
      LAYER M5 ;
        RECT  244.56 444.876 244.584 444.96 ;
    END
  END li_d[361]
  PIN li_d[362]
    DIRECTION OUTPUT ;
    USE SIGNAL ;
    PORT
      LAYER M5 ;
        RECT  244.8 444.876 244.824 444.96 ;
    END
  END li_d[362]
  PIN li_d[363]
    DIRECTION OUTPUT ;
    USE SIGNAL ;
    PORT
      LAYER M5 ;
        RECT  245.04 444.876 245.064 444.96 ;
    END
  END li_d[363]
  PIN li_d[364]
    DIRECTION OUTPUT ;
    USE SIGNAL ;
    PORT
      LAYER M5 ;
        RECT  245.28 444.876 245.304 444.96 ;
    END
  END li_d[364]
  PIN li_d[365]
    DIRECTION OUTPUT ;
    USE SIGNAL ;
    PORT
      LAYER M5 ;
        RECT  245.52 444.876 245.544 444.96 ;
    END
  END li_d[365]
  PIN li_d[366]
    DIRECTION OUTPUT ;
    USE SIGNAL ;
    PORT
      LAYER M5 ;
        RECT  245.76 444.876 245.784 444.96 ;
    END
  END li_d[366]
  PIN li_d[367]
    DIRECTION OUTPUT ;
    USE SIGNAL ;
    PORT
      LAYER M5 ;
        RECT  246 444.876 246.024 444.96 ;
    END
  END li_d[367]
  PIN li_d[368]
    DIRECTION OUTPUT ;
    USE SIGNAL ;
    PORT
      LAYER M5 ;
        RECT  246.24 444.876 246.264 444.96 ;
    END
  END li_d[368]
  PIN li_d[369]
    DIRECTION OUTPUT ;
    USE SIGNAL ;
    PORT
      LAYER M5 ;
        RECT  246.48 444.876 246.504 444.96 ;
    END
  END li_d[369]
  PIN li_d[36]
    DIRECTION OUTPUT ;
    USE SIGNAL ;
    PORT
      LAYER M5 ;
        RECT  166.56 444.876 166.584 444.96 ;
    END
  END li_d[36]
  PIN li_d[370]
    DIRECTION OUTPUT ;
    USE SIGNAL ;
    PORT
      LAYER M5 ;
        RECT  246.72 444.876 246.744 444.96 ;
    END
  END li_d[370]
  PIN li_d[371]
    DIRECTION OUTPUT ;
    USE SIGNAL ;
    PORT
      LAYER M5 ;
        RECT  246.96 444.876 246.984 444.96 ;
    END
  END li_d[371]
  PIN li_d[372]
    DIRECTION OUTPUT ;
    USE SIGNAL ;
    PORT
      LAYER M5 ;
        RECT  247.2 444.876 247.224 444.96 ;
    END
  END li_d[372]
  PIN li_d[373]
    DIRECTION OUTPUT ;
    USE SIGNAL ;
    PORT
      LAYER M5 ;
        RECT  247.44 444.876 247.464 444.96 ;
    END
  END li_d[373]
  PIN li_d[374]
    DIRECTION OUTPUT ;
    USE SIGNAL ;
    PORT
      LAYER M5 ;
        RECT  247.68 444.876 247.704 444.96 ;
    END
  END li_d[374]
  PIN li_d[375]
    DIRECTION OUTPUT ;
    USE SIGNAL ;
    PORT
      LAYER M5 ;
        RECT  247.92 444.876 247.944 444.96 ;
    END
  END li_d[375]
  PIN li_d[376]
    DIRECTION OUTPUT ;
    USE SIGNAL ;
    PORT
      LAYER M5 ;
        RECT  248.16 444.876 248.184 444.96 ;
    END
  END li_d[376]
  PIN li_d[377]
    DIRECTION OUTPUT ;
    USE SIGNAL ;
    PORT
      LAYER M5 ;
        RECT  248.4 444.876 248.424 444.96 ;
    END
  END li_d[377]
  PIN li_d[378]
    DIRECTION OUTPUT ;
    USE SIGNAL ;
    PORT
      LAYER M5 ;
        RECT  248.64 444.876 248.664 444.96 ;
    END
  END li_d[378]
  PIN li_d[379]
    DIRECTION OUTPUT ;
    USE SIGNAL ;
    PORT
      LAYER M5 ;
        RECT  248.88 444.876 248.904 444.96 ;
    END
  END li_d[379]
  PIN li_d[37]
    DIRECTION OUTPUT ;
    USE SIGNAL ;
    PORT
      LAYER M5 ;
        RECT  166.8 444.876 166.824 444.96 ;
    END
  END li_d[37]
  PIN li_d[380]
    DIRECTION OUTPUT ;
    USE SIGNAL ;
    PORT
      LAYER M5 ;
        RECT  249.12 444.876 249.144 444.96 ;
    END
  END li_d[380]
  PIN li_d[381]
    DIRECTION OUTPUT ;
    USE SIGNAL ;
    PORT
      LAYER M5 ;
        RECT  249.36 444.876 249.384 444.96 ;
    END
  END li_d[381]
  PIN li_d[382]
    DIRECTION OUTPUT ;
    USE SIGNAL ;
    PORT
      LAYER M5 ;
        RECT  249.6 444.876 249.624 444.96 ;
    END
  END li_d[382]
  PIN li_d[383]
    DIRECTION OUTPUT ;
    USE SIGNAL ;
    PORT
      LAYER M5 ;
        RECT  249.84 444.876 249.864 444.96 ;
    END
  END li_d[383]
  PIN li_d[384]
    DIRECTION OUTPUT ;
    USE SIGNAL ;
    PORT
      LAYER M5 ;
        RECT  250.08 444.876 250.104 444.96 ;
    END
  END li_d[384]
  PIN li_d[385]
    DIRECTION OUTPUT ;
    USE SIGNAL ;
    PORT
      LAYER M5 ;
        RECT  250.32 444.876 250.344 444.96 ;
    END
  END li_d[385]
  PIN li_d[386]
    DIRECTION OUTPUT ;
    USE SIGNAL ;
    PORT
      LAYER M5 ;
        RECT  250.56 444.876 250.584 444.96 ;
    END
  END li_d[386]
  PIN li_d[387]
    DIRECTION OUTPUT ;
    USE SIGNAL ;
    PORT
      LAYER M5 ;
        RECT  250.8 444.876 250.824 444.96 ;
    END
  END li_d[387]
  PIN li_d[388]
    DIRECTION OUTPUT ;
    USE SIGNAL ;
    PORT
      LAYER M5 ;
        RECT  251.04 444.876 251.064 444.96 ;
    END
  END li_d[388]
  PIN li_d[389]
    DIRECTION OUTPUT ;
    USE SIGNAL ;
    PORT
      LAYER M5 ;
        RECT  251.28 444.876 251.304 444.96 ;
    END
  END li_d[389]
  PIN li_d[38]
    DIRECTION OUTPUT ;
    USE SIGNAL ;
    PORT
      LAYER M5 ;
        RECT  167.04 444.876 167.064 444.96 ;
    END
  END li_d[38]
  PIN li_d[390]
    DIRECTION OUTPUT ;
    USE SIGNAL ;
    PORT
      LAYER M5 ;
        RECT  251.52 444.876 251.544 444.96 ;
    END
  END li_d[390]
  PIN li_d[391]
    DIRECTION OUTPUT ;
    USE SIGNAL ;
    PORT
      LAYER M5 ;
        RECT  251.76 444.876 251.784 444.96 ;
    END
  END li_d[391]
  PIN li_d[392]
    DIRECTION OUTPUT ;
    USE SIGNAL ;
    PORT
      LAYER M5 ;
        RECT  252 444.876 252.024 444.96 ;
    END
  END li_d[392]
  PIN li_d[393]
    DIRECTION OUTPUT ;
    USE SIGNAL ;
    PORT
      LAYER M5 ;
        RECT  252.24 444.876 252.264 444.96 ;
    END
  END li_d[393]
  PIN li_d[394]
    DIRECTION OUTPUT ;
    USE SIGNAL ;
    PORT
      LAYER M5 ;
        RECT  252.48 444.876 252.504 444.96 ;
    END
  END li_d[394]
  PIN li_d[395]
    DIRECTION OUTPUT ;
    USE SIGNAL ;
    PORT
      LAYER M5 ;
        RECT  252.72 444.876 252.744 444.96 ;
    END
  END li_d[395]
  PIN li_d[396]
    DIRECTION OUTPUT ;
    USE SIGNAL ;
    PORT
      LAYER M5 ;
        RECT  252.96 444.876 252.984 444.96 ;
    END
  END li_d[396]
  PIN li_d[397]
    DIRECTION OUTPUT ;
    USE SIGNAL ;
    PORT
      LAYER M5 ;
        RECT  253.2 444.876 253.224 444.96 ;
    END
  END li_d[397]
  PIN li_d[398]
    DIRECTION OUTPUT ;
    USE SIGNAL ;
    PORT
      LAYER M5 ;
        RECT  253.44 444.876 253.464 444.96 ;
    END
  END li_d[398]
  PIN li_d[399]
    DIRECTION OUTPUT ;
    USE SIGNAL ;
    PORT
      LAYER M5 ;
        RECT  253.68 444.876 253.704 444.96 ;
    END
  END li_d[399]
  PIN li_d[39]
    DIRECTION OUTPUT ;
    USE SIGNAL ;
    PORT
      LAYER M5 ;
        RECT  167.28 444.876 167.304 444.96 ;
    END
  END li_d[39]
  PIN li_d[3]
    DIRECTION OUTPUT ;
    USE SIGNAL ;
    PORT
      LAYER M5 ;
        RECT  158.64 444.876 158.664 444.96 ;
    END
  END li_d[3]
  PIN li_d[400]
    DIRECTION OUTPUT ;
    USE SIGNAL ;
    PORT
      LAYER M5 ;
        RECT  253.92 444.876 253.944 444.96 ;
    END
  END li_d[400]
  PIN li_d[401]
    DIRECTION OUTPUT ;
    USE SIGNAL ;
    PORT
      LAYER M5 ;
        RECT  254.16 444.876 254.184 444.96 ;
    END
  END li_d[401]
  PIN li_d[402]
    DIRECTION OUTPUT ;
    USE SIGNAL ;
    PORT
      LAYER M5 ;
        RECT  254.4 444.876 254.424 444.96 ;
    END
  END li_d[402]
  PIN li_d[403]
    DIRECTION OUTPUT ;
    USE SIGNAL ;
    PORT
      LAYER M5 ;
        RECT  254.64 444.876 254.664 444.96 ;
    END
  END li_d[403]
  PIN li_d[404]
    DIRECTION OUTPUT ;
    USE SIGNAL ;
    PORT
      LAYER M5 ;
        RECT  254.88 444.876 254.904 444.96 ;
    END
  END li_d[404]
  PIN li_d[405]
    DIRECTION OUTPUT ;
    USE SIGNAL ;
    PORT
      LAYER M5 ;
        RECT  255.12 444.876 255.144 444.96 ;
    END
  END li_d[405]
  PIN li_d[406]
    DIRECTION OUTPUT ;
    USE SIGNAL ;
    PORT
      LAYER M5 ;
        RECT  255.36 444.876 255.384 444.96 ;
    END
  END li_d[406]
  PIN li_d[407]
    DIRECTION OUTPUT ;
    USE SIGNAL ;
    PORT
      LAYER M5 ;
        RECT  255.6 444.876 255.624 444.96 ;
    END
  END li_d[407]
  PIN li_d[408]
    DIRECTION OUTPUT ;
    USE SIGNAL ;
    PORT
      LAYER M5 ;
        RECT  255.84 444.876 255.864 444.96 ;
    END
  END li_d[408]
  PIN li_d[409]
    DIRECTION OUTPUT ;
    USE SIGNAL ;
    PORT
      LAYER M5 ;
        RECT  256.08 444.876 256.104 444.96 ;
    END
  END li_d[409]
  PIN li_d[40]
    DIRECTION OUTPUT ;
    USE SIGNAL ;
    PORT
      LAYER M5 ;
        RECT  167.52 444.876 167.544 444.96 ;
    END
  END li_d[40]
  PIN li_d[410]
    DIRECTION OUTPUT ;
    USE SIGNAL ;
    PORT
      LAYER M5 ;
        RECT  256.32 444.876 256.344 444.96 ;
    END
  END li_d[410]
  PIN li_d[411]
    DIRECTION OUTPUT ;
    USE SIGNAL ;
    PORT
      LAYER M5 ;
        RECT  256.56 444.876 256.584 444.96 ;
    END
  END li_d[411]
  PIN li_d[412]
    DIRECTION OUTPUT ;
    USE SIGNAL ;
    PORT
      LAYER M5 ;
        RECT  256.8 444.876 256.824 444.96 ;
    END
  END li_d[412]
  PIN li_d[413]
    DIRECTION OUTPUT ;
    USE SIGNAL ;
    PORT
      LAYER M5 ;
        RECT  257.04 444.876 257.064 444.96 ;
    END
  END li_d[413]
  PIN li_d[414]
    DIRECTION OUTPUT ;
    USE SIGNAL ;
    PORT
      LAYER M5 ;
        RECT  257.28 444.876 257.304 444.96 ;
    END
  END li_d[414]
  PIN li_d[415]
    DIRECTION OUTPUT ;
    USE SIGNAL ;
    PORT
      LAYER M5 ;
        RECT  257.52 444.876 257.544 444.96 ;
    END
  END li_d[415]
  PIN li_d[416]
    DIRECTION OUTPUT ;
    USE SIGNAL ;
    PORT
      LAYER M5 ;
        RECT  257.76 444.876 257.784 444.96 ;
    END
  END li_d[416]
  PIN li_d[417]
    DIRECTION OUTPUT ;
    USE SIGNAL ;
    PORT
      LAYER M5 ;
        RECT  258 444.876 258.024 444.96 ;
    END
  END li_d[417]
  PIN li_d[418]
    DIRECTION OUTPUT ;
    USE SIGNAL ;
    PORT
      LAYER M5 ;
        RECT  258.24 444.876 258.264 444.96 ;
    END
  END li_d[418]
  PIN li_d[419]
    DIRECTION OUTPUT ;
    USE SIGNAL ;
    PORT
      LAYER M5 ;
        RECT  258.48 444.876 258.504 444.96 ;
    END
  END li_d[419]
  PIN li_d[41]
    DIRECTION OUTPUT ;
    USE SIGNAL ;
    PORT
      LAYER M5 ;
        RECT  167.76 444.876 167.784 444.96 ;
    END
  END li_d[41]
  PIN li_d[420]
    DIRECTION OUTPUT ;
    USE SIGNAL ;
    PORT
      LAYER M5 ;
        RECT  258.72 444.876 258.744 444.96 ;
    END
  END li_d[420]
  PIN li_d[421]
    DIRECTION OUTPUT ;
    USE SIGNAL ;
    PORT
      LAYER M5 ;
        RECT  258.96 444.876 258.984 444.96 ;
    END
  END li_d[421]
  PIN li_d[422]
    DIRECTION OUTPUT ;
    USE SIGNAL ;
    PORT
      LAYER M5 ;
        RECT  259.2 444.876 259.224 444.96 ;
    END
  END li_d[422]
  PIN li_d[423]
    DIRECTION OUTPUT ;
    USE SIGNAL ;
    PORT
      LAYER M5 ;
        RECT  259.44 444.876 259.464 444.96 ;
    END
  END li_d[423]
  PIN li_d[424]
    DIRECTION OUTPUT ;
    USE SIGNAL ;
    PORT
      LAYER M5 ;
        RECT  259.68 444.876 259.704 444.96 ;
    END
  END li_d[424]
  PIN li_d[425]
    DIRECTION OUTPUT ;
    USE SIGNAL ;
    PORT
      LAYER M5 ;
        RECT  259.92 444.876 259.944 444.96 ;
    END
  END li_d[425]
  PIN li_d[426]
    DIRECTION OUTPUT ;
    USE SIGNAL ;
    PORT
      LAYER M5 ;
        RECT  260.16 444.876 260.184 444.96 ;
    END
  END li_d[426]
  PIN li_d[427]
    DIRECTION OUTPUT ;
    USE SIGNAL ;
    PORT
      LAYER M5 ;
        RECT  260.4 444.876 260.424 444.96 ;
    END
  END li_d[427]
  PIN li_d[428]
    DIRECTION OUTPUT ;
    USE SIGNAL ;
    PORT
      LAYER M5 ;
        RECT  260.64 444.876 260.664 444.96 ;
    END
  END li_d[428]
  PIN li_d[429]
    DIRECTION OUTPUT ;
    USE SIGNAL ;
    PORT
      LAYER M5 ;
        RECT  260.88 444.876 260.904 444.96 ;
    END
  END li_d[429]
  PIN li_d[42]
    DIRECTION OUTPUT ;
    USE SIGNAL ;
    PORT
      LAYER M5 ;
        RECT  168 444.876 168.024 444.96 ;
    END
  END li_d[42]
  PIN li_d[430]
    DIRECTION OUTPUT ;
    USE SIGNAL ;
    PORT
      LAYER M5 ;
        RECT  261.12 444.876 261.144 444.96 ;
    END
  END li_d[430]
  PIN li_d[431]
    DIRECTION OUTPUT ;
    USE SIGNAL ;
    PORT
      LAYER M5 ;
        RECT  261.36 444.876 261.384 444.96 ;
    END
  END li_d[431]
  PIN li_d[432]
    DIRECTION OUTPUT ;
    USE SIGNAL ;
    PORT
      LAYER M5 ;
        RECT  261.6 444.876 261.624 444.96 ;
    END
  END li_d[432]
  PIN li_d[433]
    DIRECTION OUTPUT ;
    USE SIGNAL ;
    PORT
      LAYER M5 ;
        RECT  261.84 444.876 261.864 444.96 ;
    END
  END li_d[433]
  PIN li_d[434]
    DIRECTION OUTPUT ;
    USE SIGNAL ;
    PORT
      LAYER M5 ;
        RECT  262.08 444.876 262.104 444.96 ;
    END
  END li_d[434]
  PIN li_d[435]
    DIRECTION OUTPUT ;
    USE SIGNAL ;
    PORT
      LAYER M5 ;
        RECT  262.32 444.876 262.344 444.96 ;
    END
  END li_d[435]
  PIN li_d[436]
    DIRECTION OUTPUT ;
    USE SIGNAL ;
    PORT
      LAYER M5 ;
        RECT  262.56 444.876 262.584 444.96 ;
    END
  END li_d[436]
  PIN li_d[437]
    DIRECTION OUTPUT ;
    USE SIGNAL ;
    PORT
      LAYER M5 ;
        RECT  262.8 444.876 262.824 444.96 ;
    END
  END li_d[437]
  PIN li_d[438]
    DIRECTION OUTPUT ;
    USE SIGNAL ;
    PORT
      LAYER M5 ;
        RECT  263.04 444.876 263.064 444.96 ;
    END
  END li_d[438]
  PIN li_d[439]
    DIRECTION OUTPUT ;
    USE SIGNAL ;
    PORT
      LAYER M5 ;
        RECT  263.28 444.876 263.304 444.96 ;
    END
  END li_d[439]
  PIN li_d[43]
    DIRECTION OUTPUT ;
    USE SIGNAL ;
    PORT
      LAYER M5 ;
        RECT  168.24 444.876 168.264 444.96 ;
    END
  END li_d[43]
  PIN li_d[440]
    DIRECTION OUTPUT ;
    USE SIGNAL ;
    PORT
      LAYER M5 ;
        RECT  263.52 444.876 263.544 444.96 ;
    END
  END li_d[440]
  PIN li_d[441]
    DIRECTION OUTPUT ;
    USE SIGNAL ;
    PORT
      LAYER M5 ;
        RECT  263.76 444.876 263.784 444.96 ;
    END
  END li_d[441]
  PIN li_d[442]
    DIRECTION OUTPUT ;
    USE SIGNAL ;
    PORT
      LAYER M5 ;
        RECT  264 444.876 264.024 444.96 ;
    END
  END li_d[442]
  PIN li_d[443]
    DIRECTION OUTPUT ;
    USE SIGNAL ;
    PORT
      LAYER M5 ;
        RECT  264.24 444.876 264.264 444.96 ;
    END
  END li_d[443]
  PIN li_d[444]
    DIRECTION OUTPUT ;
    USE SIGNAL ;
    PORT
      LAYER M5 ;
        RECT  264.48 444.876 264.504 444.96 ;
    END
  END li_d[444]
  PIN li_d[445]
    DIRECTION OUTPUT ;
    USE SIGNAL ;
    PORT
      LAYER M5 ;
        RECT  264.72 444.876 264.744 444.96 ;
    END
  END li_d[445]
  PIN li_d[446]
    DIRECTION OUTPUT ;
    USE SIGNAL ;
    PORT
      LAYER M5 ;
        RECT  264.96 444.876 264.984 444.96 ;
    END
  END li_d[446]
  PIN li_d[447]
    DIRECTION OUTPUT ;
    USE SIGNAL ;
    PORT
      LAYER M5 ;
        RECT  265.2 444.876 265.224 444.96 ;
    END
  END li_d[447]
  PIN li_d[448]
    DIRECTION OUTPUT ;
    USE SIGNAL ;
    PORT
      LAYER M5 ;
        RECT  265.44 444.876 265.464 444.96 ;
    END
  END li_d[448]
  PIN li_d[449]
    DIRECTION OUTPUT ;
    USE SIGNAL ;
    PORT
      LAYER M5 ;
        RECT  265.68 444.876 265.704 444.96 ;
    END
  END li_d[449]
  PIN li_d[44]
    DIRECTION OUTPUT ;
    USE SIGNAL ;
    PORT
      LAYER M5 ;
        RECT  168.48 444.876 168.504 444.96 ;
    END
  END li_d[44]
  PIN li_d[450]
    DIRECTION OUTPUT ;
    USE SIGNAL ;
    PORT
      LAYER M5 ;
        RECT  265.92 444.876 265.944 444.96 ;
    END
  END li_d[450]
  PIN li_d[451]
    DIRECTION OUTPUT ;
    USE SIGNAL ;
    PORT
      LAYER M5 ;
        RECT  266.16 444.876 266.184 444.96 ;
    END
  END li_d[451]
  PIN li_d[452]
    DIRECTION OUTPUT ;
    USE SIGNAL ;
    PORT
      LAYER M5 ;
        RECT  266.4 444.876 266.424 444.96 ;
    END
  END li_d[452]
  PIN li_d[453]
    DIRECTION OUTPUT ;
    USE SIGNAL ;
    PORT
      LAYER M5 ;
        RECT  266.64 444.876 266.664 444.96 ;
    END
  END li_d[453]
  PIN li_d[454]
    DIRECTION OUTPUT ;
    USE SIGNAL ;
    PORT
      LAYER M5 ;
        RECT  266.88 444.876 266.904 444.96 ;
    END
  END li_d[454]
  PIN li_d[455]
    DIRECTION OUTPUT ;
    USE SIGNAL ;
    PORT
      LAYER M5 ;
        RECT  267.12 444.876 267.144 444.96 ;
    END
  END li_d[455]
  PIN li_d[456]
    DIRECTION OUTPUT ;
    USE SIGNAL ;
    PORT
      LAYER M5 ;
        RECT  267.36 444.876 267.384 444.96 ;
    END
  END li_d[456]
  PIN li_d[457]
    DIRECTION OUTPUT ;
    USE SIGNAL ;
    PORT
      LAYER M5 ;
        RECT  267.6 444.876 267.624 444.96 ;
    END
  END li_d[457]
  PIN li_d[458]
    DIRECTION OUTPUT ;
    USE SIGNAL ;
    PORT
      LAYER M5 ;
        RECT  267.84 444.876 267.864 444.96 ;
    END
  END li_d[458]
  PIN li_d[459]
    DIRECTION OUTPUT ;
    USE SIGNAL ;
    PORT
      LAYER M5 ;
        RECT  268.08 444.876 268.104 444.96 ;
    END
  END li_d[459]
  PIN li_d[45]
    DIRECTION OUTPUT ;
    USE SIGNAL ;
    PORT
      LAYER M5 ;
        RECT  168.72 444.876 168.744 444.96 ;
    END
  END li_d[45]
  PIN li_d[460]
    DIRECTION OUTPUT ;
    USE SIGNAL ;
    PORT
      LAYER M5 ;
        RECT  268.32 444.876 268.344 444.96 ;
    END
  END li_d[460]
  PIN li_d[461]
    DIRECTION OUTPUT ;
    USE SIGNAL ;
    PORT
      LAYER M5 ;
        RECT  268.56 444.876 268.584 444.96 ;
    END
  END li_d[461]
  PIN li_d[462]
    DIRECTION OUTPUT ;
    USE SIGNAL ;
    PORT
      LAYER M5 ;
        RECT  268.8 444.876 268.824 444.96 ;
    END
  END li_d[462]
  PIN li_d[463]
    DIRECTION OUTPUT ;
    USE SIGNAL ;
    PORT
      LAYER M5 ;
        RECT  269.04 444.876 269.064 444.96 ;
    END
  END li_d[463]
  PIN li_d[464]
    DIRECTION OUTPUT ;
    USE SIGNAL ;
    PORT
      LAYER M5 ;
        RECT  269.28 444.876 269.304 444.96 ;
    END
  END li_d[464]
  PIN li_d[465]
    DIRECTION OUTPUT ;
    USE SIGNAL ;
    PORT
      LAYER M5 ;
        RECT  269.52 444.876 269.544 444.96 ;
    END
  END li_d[465]
  PIN li_d[466]
    DIRECTION OUTPUT ;
    USE SIGNAL ;
    PORT
      LAYER M5 ;
        RECT  269.76 444.876 269.784 444.96 ;
    END
  END li_d[466]
  PIN li_d[467]
    DIRECTION OUTPUT ;
    USE SIGNAL ;
    PORT
      LAYER M5 ;
        RECT  270 444.876 270.024 444.96 ;
    END
  END li_d[467]
  PIN li_d[468]
    DIRECTION OUTPUT ;
    USE SIGNAL ;
    PORT
      LAYER M5 ;
        RECT  270.24 444.876 270.264 444.96 ;
    END
  END li_d[468]
  PIN li_d[469]
    DIRECTION OUTPUT ;
    USE SIGNAL ;
    PORT
      LAYER M5 ;
        RECT  270.48 444.876 270.504 444.96 ;
    END
  END li_d[469]
  PIN li_d[46]
    DIRECTION OUTPUT ;
    USE SIGNAL ;
    PORT
      LAYER M5 ;
        RECT  168.96 444.876 168.984 444.96 ;
    END
  END li_d[46]
  PIN li_d[470]
    DIRECTION OUTPUT ;
    USE SIGNAL ;
    PORT
      LAYER M5 ;
        RECT  270.72 444.876 270.744 444.96 ;
    END
  END li_d[470]
  PIN li_d[471]
    DIRECTION OUTPUT ;
    USE SIGNAL ;
    PORT
      LAYER M5 ;
        RECT  270.96 444.876 270.984 444.96 ;
    END
  END li_d[471]
  PIN li_d[472]
    DIRECTION OUTPUT ;
    USE SIGNAL ;
    PORT
      LAYER M5 ;
        RECT  271.2 444.876 271.224 444.96 ;
    END
  END li_d[472]
  PIN li_d[473]
    DIRECTION OUTPUT ;
    USE SIGNAL ;
    PORT
      LAYER M5 ;
        RECT  271.44 444.876 271.464 444.96 ;
    END
  END li_d[473]
  PIN li_d[474]
    DIRECTION OUTPUT ;
    USE SIGNAL ;
    PORT
      LAYER M5 ;
        RECT  271.68 444.876 271.704 444.96 ;
    END
  END li_d[474]
  PIN li_d[475]
    DIRECTION OUTPUT ;
    USE SIGNAL ;
    PORT
      LAYER M5 ;
        RECT  271.92 444.876 271.944 444.96 ;
    END
  END li_d[475]
  PIN li_d[476]
    DIRECTION OUTPUT ;
    USE SIGNAL ;
    PORT
      LAYER M5 ;
        RECT  272.16 444.876 272.184 444.96 ;
    END
  END li_d[476]
  PIN li_d[477]
    DIRECTION OUTPUT ;
    USE SIGNAL ;
    PORT
      LAYER M5 ;
        RECT  272.4 444.876 272.424 444.96 ;
    END
  END li_d[477]
  PIN li_d[478]
    DIRECTION OUTPUT ;
    USE SIGNAL ;
    PORT
      LAYER M5 ;
        RECT  272.64 444.876 272.664 444.96 ;
    END
  END li_d[478]
  PIN li_d[479]
    DIRECTION OUTPUT ;
    USE SIGNAL ;
    PORT
      LAYER M5 ;
        RECT  272.88 444.876 272.904 444.96 ;
    END
  END li_d[479]
  PIN li_d[47]
    DIRECTION OUTPUT ;
    USE SIGNAL ;
    PORT
      LAYER M5 ;
        RECT  169.2 444.876 169.224 444.96 ;
    END
  END li_d[47]
  PIN li_d[480]
    DIRECTION OUTPUT ;
    USE SIGNAL ;
    PORT
      LAYER M5 ;
        RECT  273.12 444.876 273.144 444.96 ;
    END
  END li_d[480]
  PIN li_d[481]
    DIRECTION OUTPUT ;
    USE SIGNAL ;
    PORT
      LAYER M5 ;
        RECT  273.36 444.876 273.384 444.96 ;
    END
  END li_d[481]
  PIN li_d[482]
    DIRECTION OUTPUT ;
    USE SIGNAL ;
    PORT
      LAYER M5 ;
        RECT  273.6 444.876 273.624 444.96 ;
    END
  END li_d[482]
  PIN li_d[483]
    DIRECTION OUTPUT ;
    USE SIGNAL ;
    PORT
      LAYER M5 ;
        RECT  273.84 444.876 273.864 444.96 ;
    END
  END li_d[483]
  PIN li_d[484]
    DIRECTION OUTPUT ;
    USE SIGNAL ;
    PORT
      LAYER M5 ;
        RECT  274.08 444.876 274.104 444.96 ;
    END
  END li_d[484]
  PIN li_d[485]
    DIRECTION OUTPUT ;
    USE SIGNAL ;
    PORT
      LAYER M5 ;
        RECT  274.32 444.876 274.344 444.96 ;
    END
  END li_d[485]
  PIN li_d[486]
    DIRECTION OUTPUT ;
    USE SIGNAL ;
    PORT
      LAYER M5 ;
        RECT  274.56 444.876 274.584 444.96 ;
    END
  END li_d[486]
  PIN li_d[487]
    DIRECTION OUTPUT ;
    USE SIGNAL ;
    PORT
      LAYER M5 ;
        RECT  274.8 444.876 274.824 444.96 ;
    END
  END li_d[487]
  PIN li_d[488]
    DIRECTION OUTPUT ;
    USE SIGNAL ;
    PORT
      LAYER M5 ;
        RECT  275.04 444.876 275.064 444.96 ;
    END
  END li_d[488]
  PIN li_d[489]
    DIRECTION OUTPUT ;
    USE SIGNAL ;
    PORT
      LAYER M5 ;
        RECT  275.28 444.876 275.304 444.96 ;
    END
  END li_d[489]
  PIN li_d[48]
    DIRECTION OUTPUT ;
    USE SIGNAL ;
    PORT
      LAYER M5 ;
        RECT  169.44 444.876 169.464 444.96 ;
    END
  END li_d[48]
  PIN li_d[490]
    DIRECTION OUTPUT ;
    USE SIGNAL ;
    PORT
      LAYER M5 ;
        RECT  275.52 444.876 275.544 444.96 ;
    END
  END li_d[490]
  PIN li_d[491]
    DIRECTION OUTPUT ;
    USE SIGNAL ;
    PORT
      LAYER M5 ;
        RECT  275.76 444.876 275.784 444.96 ;
    END
  END li_d[491]
  PIN li_d[492]
    DIRECTION OUTPUT ;
    USE SIGNAL ;
    PORT
      LAYER M5 ;
        RECT  276 444.876 276.024 444.96 ;
    END
  END li_d[492]
  PIN li_d[493]
    DIRECTION OUTPUT ;
    USE SIGNAL ;
    PORT
      LAYER M5 ;
        RECT  276.24 444.876 276.264 444.96 ;
    END
  END li_d[493]
  PIN li_d[494]
    DIRECTION OUTPUT ;
    USE SIGNAL ;
    PORT
      LAYER M5 ;
        RECT  276.48 444.876 276.504 444.96 ;
    END
  END li_d[494]
  PIN li_d[495]
    DIRECTION OUTPUT ;
    USE SIGNAL ;
    PORT
      LAYER M5 ;
        RECT  276.72 444.876 276.744 444.96 ;
    END
  END li_d[495]
  PIN li_d[496]
    DIRECTION OUTPUT ;
    USE SIGNAL ;
    PORT
      LAYER M5 ;
        RECT  276.96 444.876 276.984 444.96 ;
    END
  END li_d[496]
  PIN li_d[497]
    DIRECTION OUTPUT ;
    USE SIGNAL ;
    PORT
      LAYER M5 ;
        RECT  277.2 444.876 277.224 444.96 ;
    END
  END li_d[497]
  PIN li_d[498]
    DIRECTION OUTPUT ;
    USE SIGNAL ;
    PORT
      LAYER M5 ;
        RECT  277.44 444.876 277.464 444.96 ;
    END
  END li_d[498]
  PIN li_d[499]
    DIRECTION OUTPUT ;
    USE SIGNAL ;
    PORT
      LAYER M5 ;
        RECT  277.68 444.876 277.704 444.96 ;
    END
  END li_d[499]
  PIN li_d[49]
    DIRECTION OUTPUT ;
    USE SIGNAL ;
    PORT
      LAYER M5 ;
        RECT  169.68 444.876 169.704 444.96 ;
    END
  END li_d[49]
  PIN li_d[4]
    DIRECTION OUTPUT ;
    USE SIGNAL ;
    PORT
      LAYER M5 ;
        RECT  158.88 444.876 158.904 444.96 ;
    END
  END li_d[4]
  PIN li_d[500]
    DIRECTION OUTPUT ;
    USE SIGNAL ;
    PORT
      LAYER M5 ;
        RECT  277.92 444.876 277.944 444.96 ;
    END
  END li_d[500]
  PIN li_d[501]
    DIRECTION OUTPUT ;
    USE SIGNAL ;
    PORT
      LAYER M5 ;
        RECT  278.16 444.876 278.184 444.96 ;
    END
  END li_d[501]
  PIN li_d[502]
    DIRECTION OUTPUT ;
    USE SIGNAL ;
    PORT
      LAYER M5 ;
        RECT  278.4 444.876 278.424 444.96 ;
    END
  END li_d[502]
  PIN li_d[503]
    DIRECTION OUTPUT ;
    USE SIGNAL ;
    PORT
      LAYER M5 ;
        RECT  278.64 444.876 278.664 444.96 ;
    END
  END li_d[503]
  PIN li_d[504]
    DIRECTION OUTPUT ;
    USE SIGNAL ;
    PORT
      LAYER M5 ;
        RECT  278.88 444.876 278.904 444.96 ;
    END
  END li_d[504]
  PIN li_d[505]
    DIRECTION OUTPUT ;
    USE SIGNAL ;
    PORT
      LAYER M5 ;
        RECT  279.12 444.876 279.144 444.96 ;
    END
  END li_d[505]
  PIN li_d[506]
    DIRECTION OUTPUT ;
    USE SIGNAL ;
    PORT
      LAYER M5 ;
        RECT  279.36 444.876 279.384 444.96 ;
    END
  END li_d[506]
  PIN li_d[507]
    DIRECTION OUTPUT ;
    USE SIGNAL ;
    PORT
      LAYER M5 ;
        RECT  279.6 444.876 279.624 444.96 ;
    END
  END li_d[507]
  PIN li_d[508]
    DIRECTION OUTPUT ;
    USE SIGNAL ;
    PORT
      LAYER M5 ;
        RECT  279.84 444.876 279.864 444.96 ;
    END
  END li_d[508]
  PIN li_d[509]
    DIRECTION OUTPUT ;
    USE SIGNAL ;
    PORT
      LAYER M5 ;
        RECT  280.08 444.876 280.104 444.96 ;
    END
  END li_d[509]
  PIN li_d[50]
    DIRECTION OUTPUT ;
    USE SIGNAL ;
    PORT
      LAYER M5 ;
        RECT  169.92 444.876 169.944 444.96 ;
    END
  END li_d[50]
  PIN li_d[510]
    DIRECTION OUTPUT ;
    USE SIGNAL ;
    PORT
      LAYER M5 ;
        RECT  280.32 444.876 280.344 444.96 ;
    END
  END li_d[510]
  PIN li_d[511]
    DIRECTION OUTPUT ;
    USE SIGNAL ;
    PORT
      LAYER M5 ;
        RECT  280.56 444.876 280.584 444.96 ;
    END
  END li_d[511]
  PIN li_d[512]
    DIRECTION OUTPUT ;
    USE SIGNAL ;
    PORT
      LAYER M5 ;
        RECT  280.8 444.876 280.824 444.96 ;
    END
  END li_d[512]
  PIN li_d[513]
    DIRECTION OUTPUT ;
    USE SIGNAL ;
    PORT
      LAYER M5 ;
        RECT  281.04 444.876 281.064 444.96 ;
    END
  END li_d[513]
  PIN li_d[514]
    DIRECTION OUTPUT ;
    USE SIGNAL ;
    PORT
      LAYER M5 ;
        RECT  281.28 444.876 281.304 444.96 ;
    END
  END li_d[514]
  PIN li_d[515]
    DIRECTION OUTPUT ;
    USE SIGNAL ;
    PORT
      LAYER M5 ;
        RECT  281.52 444.876 281.544 444.96 ;
    END
  END li_d[515]
  PIN li_d[516]
    DIRECTION OUTPUT ;
    USE SIGNAL ;
    PORT
      LAYER M5 ;
        RECT  281.76 444.876 281.784 444.96 ;
    END
  END li_d[516]
  PIN li_d[517]
    DIRECTION OUTPUT ;
    USE SIGNAL ;
    PORT
      LAYER M5 ;
        RECT  282 444.876 282.024 444.96 ;
    END
  END li_d[517]
  PIN li_d[518]
    DIRECTION OUTPUT ;
    USE SIGNAL ;
    PORT
      LAYER M5 ;
        RECT  282.24 444.876 282.264 444.96 ;
    END
  END li_d[518]
  PIN li_d[519]
    DIRECTION OUTPUT ;
    USE SIGNAL ;
    PORT
      LAYER M5 ;
        RECT  282.48 444.876 282.504 444.96 ;
    END
  END li_d[519]
  PIN li_d[51]
    DIRECTION OUTPUT ;
    USE SIGNAL ;
    PORT
      LAYER M5 ;
        RECT  170.16 444.876 170.184 444.96 ;
    END
  END li_d[51]
  PIN li_d[520]
    DIRECTION OUTPUT ;
    USE SIGNAL ;
    PORT
      LAYER M5 ;
        RECT  282.72 444.876 282.744 444.96 ;
    END
  END li_d[520]
  PIN li_d[521]
    DIRECTION OUTPUT ;
    USE SIGNAL ;
    PORT
      LAYER M5 ;
        RECT  282.96 444.876 282.984 444.96 ;
    END
  END li_d[521]
  PIN li_d[522]
    DIRECTION OUTPUT ;
    USE SIGNAL ;
    PORT
      LAYER M5 ;
        RECT  283.2 444.876 283.224 444.96 ;
    END
  END li_d[522]
  PIN li_d[523]
    DIRECTION OUTPUT ;
    USE SIGNAL ;
    PORT
      LAYER M5 ;
        RECT  283.44 444.876 283.464 444.96 ;
    END
  END li_d[523]
  PIN li_d[524]
    DIRECTION OUTPUT ;
    USE SIGNAL ;
    PORT
      LAYER M5 ;
        RECT  283.68 444.876 283.704 444.96 ;
    END
  END li_d[524]
  PIN li_d[525]
    DIRECTION OUTPUT ;
    USE SIGNAL ;
    PORT
      LAYER M5 ;
        RECT  283.92 444.876 283.944 444.96 ;
    END
  END li_d[525]
  PIN li_d[526]
    DIRECTION OUTPUT ;
    USE SIGNAL ;
    PORT
      LAYER M5 ;
        RECT  284.16 444.876 284.184 444.96 ;
    END
  END li_d[526]
  PIN li_d[527]
    DIRECTION OUTPUT ;
    USE SIGNAL ;
    PORT
      LAYER M5 ;
        RECT  284.4 444.876 284.424 444.96 ;
    END
  END li_d[527]
  PIN li_d[528]
    DIRECTION OUTPUT ;
    USE SIGNAL ;
    PORT
      LAYER M5 ;
        RECT  284.64 444.876 284.664 444.96 ;
    END
  END li_d[528]
  PIN li_d[529]
    DIRECTION OUTPUT ;
    USE SIGNAL ;
    PORT
      LAYER M5 ;
        RECT  284.88 444.876 284.904 444.96 ;
    END
  END li_d[529]
  PIN li_d[52]
    DIRECTION OUTPUT ;
    USE SIGNAL ;
    PORT
      LAYER M5 ;
        RECT  170.4 444.876 170.424 444.96 ;
    END
  END li_d[52]
  PIN li_d[530]
    DIRECTION OUTPUT ;
    USE SIGNAL ;
    PORT
      LAYER M5 ;
        RECT  285.12 444.876 285.144 444.96 ;
    END
  END li_d[530]
  PIN li_d[531]
    DIRECTION OUTPUT ;
    USE SIGNAL ;
    PORT
      LAYER M5 ;
        RECT  285.36 444.876 285.384 444.96 ;
    END
  END li_d[531]
  PIN li_d[532]
    DIRECTION OUTPUT ;
    USE SIGNAL ;
    PORT
      LAYER M5 ;
        RECT  285.6 444.876 285.624 444.96 ;
    END
  END li_d[532]
  PIN li_d[533]
    DIRECTION OUTPUT ;
    USE SIGNAL ;
    PORT
      LAYER M5 ;
        RECT  285.84 444.876 285.864 444.96 ;
    END
  END li_d[533]
  PIN li_d[534]
    DIRECTION OUTPUT ;
    USE SIGNAL ;
    PORT
      LAYER M5 ;
        RECT  286.08 444.876 286.104 444.96 ;
    END
  END li_d[534]
  PIN li_d[535]
    DIRECTION OUTPUT ;
    USE SIGNAL ;
    PORT
      LAYER M5 ;
        RECT  286.32 444.876 286.344 444.96 ;
    END
  END li_d[535]
  PIN li_d[536]
    DIRECTION OUTPUT ;
    USE SIGNAL ;
    PORT
      LAYER M5 ;
        RECT  286.56 444.876 286.584 444.96 ;
    END
  END li_d[536]
  PIN li_d[537]
    DIRECTION OUTPUT ;
    USE SIGNAL ;
    PORT
      LAYER M5 ;
        RECT  286.8 444.876 286.824 444.96 ;
    END
  END li_d[537]
  PIN li_d[538]
    DIRECTION OUTPUT ;
    USE SIGNAL ;
    PORT
      LAYER M5 ;
        RECT  287.04 444.876 287.064 444.96 ;
    END
  END li_d[538]
  PIN li_d[539]
    DIRECTION OUTPUT ;
    USE SIGNAL ;
    PORT
      LAYER M5 ;
        RECT  287.28 444.876 287.304 444.96 ;
    END
  END li_d[539]
  PIN li_d[53]
    DIRECTION OUTPUT ;
    USE SIGNAL ;
    PORT
      LAYER M5 ;
        RECT  170.64 444.876 170.664 444.96 ;
    END
  END li_d[53]
  PIN li_d[540]
    DIRECTION OUTPUT ;
    USE SIGNAL ;
    PORT
      LAYER M5 ;
        RECT  287.52 444.876 287.544 444.96 ;
    END
  END li_d[540]
  PIN li_d[541]
    DIRECTION OUTPUT ;
    USE SIGNAL ;
    PORT
      LAYER M5 ;
        RECT  287.76 444.876 287.784 444.96 ;
    END
  END li_d[541]
  PIN li_d[542]
    DIRECTION OUTPUT ;
    USE SIGNAL ;
    PORT
      LAYER M5 ;
        RECT  288 444.876 288.024 444.96 ;
    END
  END li_d[542]
  PIN li_d[543]
    DIRECTION OUTPUT ;
    USE SIGNAL ;
    PORT
      LAYER M5 ;
        RECT  288.24 444.876 288.264 444.96 ;
    END
  END li_d[543]
  PIN li_d[544]
    DIRECTION OUTPUT ;
    USE SIGNAL ;
    PORT
      LAYER M5 ;
        RECT  288.48 444.876 288.504 444.96 ;
    END
  END li_d[544]
  PIN li_d[545]
    DIRECTION OUTPUT ;
    USE SIGNAL ;
    PORT
      LAYER M5 ;
        RECT  288.72 444.876 288.744 444.96 ;
    END
  END li_d[545]
  PIN li_d[546]
    DIRECTION OUTPUT ;
    USE SIGNAL ;
    PORT
      LAYER M5 ;
        RECT  288.96 444.876 288.984 444.96 ;
    END
  END li_d[546]
  PIN li_d[547]
    DIRECTION OUTPUT ;
    USE SIGNAL ;
    PORT
      LAYER M5 ;
        RECT  289.2 444.876 289.224 444.96 ;
    END
  END li_d[547]
  PIN li_d[548]
    DIRECTION OUTPUT ;
    USE SIGNAL ;
    PORT
      LAYER M5 ;
        RECT  289.44 444.876 289.464 444.96 ;
    END
  END li_d[548]
  PIN li_d[549]
    DIRECTION OUTPUT ;
    USE SIGNAL ;
    PORT
      LAYER M5 ;
        RECT  289.68 444.876 289.704 444.96 ;
    END
  END li_d[549]
  PIN li_d[54]
    DIRECTION OUTPUT ;
    USE SIGNAL ;
    PORT
      LAYER M5 ;
        RECT  170.88 444.876 170.904 444.96 ;
    END
  END li_d[54]
  PIN li_d[550]
    DIRECTION OUTPUT ;
    USE SIGNAL ;
    PORT
      LAYER M5 ;
        RECT  289.92 444.876 289.944 444.96 ;
    END
  END li_d[550]
  PIN li_d[551]
    DIRECTION OUTPUT ;
    USE SIGNAL ;
    PORT
      LAYER M5 ;
        RECT  290.16 444.876 290.184 444.96 ;
    END
  END li_d[551]
  PIN li_d[552]
    DIRECTION OUTPUT ;
    USE SIGNAL ;
    PORT
      LAYER M5 ;
        RECT  290.4 444.876 290.424 444.96 ;
    END
  END li_d[552]
  PIN li_d[55]
    DIRECTION OUTPUT ;
    USE SIGNAL ;
    PORT
      LAYER M5 ;
        RECT  171.12 444.876 171.144 444.96 ;
    END
  END li_d[55]
  PIN li_d[56]
    DIRECTION OUTPUT ;
    USE SIGNAL ;
    PORT
      LAYER M5 ;
        RECT  171.36 444.876 171.384 444.96 ;
    END
  END li_d[56]
  PIN li_d[57]
    DIRECTION OUTPUT ;
    USE SIGNAL ;
    PORT
      LAYER M5 ;
        RECT  171.6 444.876 171.624 444.96 ;
    END
  END li_d[57]
  PIN li_d[58]
    DIRECTION OUTPUT ;
    USE SIGNAL ;
    PORT
      LAYER M5 ;
        RECT  171.84 444.876 171.864 444.96 ;
    END
  END li_d[58]
  PIN li_d[59]
    DIRECTION OUTPUT ;
    USE SIGNAL ;
    PORT
      LAYER M5 ;
        RECT  172.08 444.876 172.104 444.96 ;
    END
  END li_d[59]
  PIN li_d[5]
    DIRECTION OUTPUT ;
    USE SIGNAL ;
    PORT
      LAYER M5 ;
        RECT  159.12 444.876 159.144 444.96 ;
    END
  END li_d[5]
  PIN li_d[60]
    DIRECTION OUTPUT ;
    USE SIGNAL ;
    PORT
      LAYER M5 ;
        RECT  172.32 444.876 172.344 444.96 ;
    END
  END li_d[60]
  PIN li_d[61]
    DIRECTION OUTPUT ;
    USE SIGNAL ;
    PORT
      LAYER M5 ;
        RECT  172.56 444.876 172.584 444.96 ;
    END
  END li_d[61]
  PIN li_d[62]
    DIRECTION OUTPUT ;
    USE SIGNAL ;
    PORT
      LAYER M5 ;
        RECT  172.8 444.876 172.824 444.96 ;
    END
  END li_d[62]
  PIN li_d[63]
    DIRECTION OUTPUT ;
    USE SIGNAL ;
    PORT
      LAYER M5 ;
        RECT  173.04 444.876 173.064 444.96 ;
    END
  END li_d[63]
  PIN li_d[64]
    DIRECTION OUTPUT ;
    USE SIGNAL ;
    PORT
      LAYER M5 ;
        RECT  173.28 444.876 173.304 444.96 ;
    END
  END li_d[64]
  PIN li_d[65]
    DIRECTION OUTPUT ;
    USE SIGNAL ;
    PORT
      LAYER M5 ;
        RECT  173.52 444.876 173.544 444.96 ;
    END
  END li_d[65]
  PIN li_d[66]
    DIRECTION OUTPUT ;
    USE SIGNAL ;
    PORT
      LAYER M5 ;
        RECT  173.76 444.876 173.784 444.96 ;
    END
  END li_d[66]
  PIN li_d[67]
    DIRECTION OUTPUT ;
    USE SIGNAL ;
    PORT
      LAYER M5 ;
        RECT  174 444.876 174.024 444.96 ;
    END
  END li_d[67]
  PIN li_d[68]
    DIRECTION OUTPUT ;
    USE SIGNAL ;
    PORT
      LAYER M5 ;
        RECT  174.24 444.876 174.264 444.96 ;
    END
  END li_d[68]
  PIN li_d[69]
    DIRECTION OUTPUT ;
    USE SIGNAL ;
    PORT
      LAYER M5 ;
        RECT  174.48 444.876 174.504 444.96 ;
    END
  END li_d[69]
  PIN li_d[6]
    DIRECTION OUTPUT ;
    USE SIGNAL ;
    PORT
      LAYER M5 ;
        RECT  159.36 444.876 159.384 444.96 ;
    END
  END li_d[6]
  PIN li_d[70]
    DIRECTION OUTPUT ;
    USE SIGNAL ;
    PORT
      LAYER M5 ;
        RECT  174.72 444.876 174.744 444.96 ;
    END
  END li_d[70]
  PIN li_d[71]
    DIRECTION OUTPUT ;
    USE SIGNAL ;
    PORT
      LAYER M5 ;
        RECT  174.96 444.876 174.984 444.96 ;
    END
  END li_d[71]
  PIN li_d[72]
    DIRECTION OUTPUT ;
    USE SIGNAL ;
    PORT
      LAYER M5 ;
        RECT  175.2 444.876 175.224 444.96 ;
    END
  END li_d[72]
  PIN li_d[73]
    DIRECTION OUTPUT ;
    USE SIGNAL ;
    PORT
      LAYER M5 ;
        RECT  175.44 444.876 175.464 444.96 ;
    END
  END li_d[73]
  PIN li_d[74]
    DIRECTION OUTPUT ;
    USE SIGNAL ;
    PORT
      LAYER M5 ;
        RECT  175.68 444.876 175.704 444.96 ;
    END
  END li_d[74]
  PIN li_d[75]
    DIRECTION OUTPUT ;
    USE SIGNAL ;
    PORT
      LAYER M5 ;
        RECT  175.92 444.876 175.944 444.96 ;
    END
  END li_d[75]
  PIN li_d[76]
    DIRECTION OUTPUT ;
    USE SIGNAL ;
    PORT
      LAYER M5 ;
        RECT  176.16 444.876 176.184 444.96 ;
    END
  END li_d[76]
  PIN li_d[77]
    DIRECTION OUTPUT ;
    USE SIGNAL ;
    PORT
      LAYER M5 ;
        RECT  176.4 444.876 176.424 444.96 ;
    END
  END li_d[77]
  PIN li_d[78]
    DIRECTION OUTPUT ;
    USE SIGNAL ;
    PORT
      LAYER M5 ;
        RECT  176.64 444.876 176.664 444.96 ;
    END
  END li_d[78]
  PIN li_d[79]
    DIRECTION OUTPUT ;
    USE SIGNAL ;
    PORT
      LAYER M5 ;
        RECT  176.88 444.876 176.904 444.96 ;
    END
  END li_d[79]
  PIN li_d[7]
    DIRECTION OUTPUT ;
    USE SIGNAL ;
    PORT
      LAYER M5 ;
        RECT  159.6 444.876 159.624 444.96 ;
    END
  END li_d[7]
  PIN li_d[80]
    DIRECTION OUTPUT ;
    USE SIGNAL ;
    PORT
      LAYER M5 ;
        RECT  177.12 444.876 177.144 444.96 ;
    END
  END li_d[80]
  PIN li_d[81]
    DIRECTION OUTPUT ;
    USE SIGNAL ;
    PORT
      LAYER M5 ;
        RECT  177.36 444.876 177.384 444.96 ;
    END
  END li_d[81]
  PIN li_d[82]
    DIRECTION OUTPUT ;
    USE SIGNAL ;
    PORT
      LAYER M5 ;
        RECT  177.6 444.876 177.624 444.96 ;
    END
  END li_d[82]
  PIN li_d[83]
    DIRECTION OUTPUT ;
    USE SIGNAL ;
    PORT
      LAYER M5 ;
        RECT  177.84 444.876 177.864 444.96 ;
    END
  END li_d[83]
  PIN li_d[84]
    DIRECTION OUTPUT ;
    USE SIGNAL ;
    PORT
      LAYER M5 ;
        RECT  178.08 444.876 178.104 444.96 ;
    END
  END li_d[84]
  PIN li_d[85]
    DIRECTION OUTPUT ;
    USE SIGNAL ;
    PORT
      LAYER M5 ;
        RECT  178.32 444.876 178.344 444.96 ;
    END
  END li_d[85]
  PIN li_d[86]
    DIRECTION OUTPUT ;
    USE SIGNAL ;
    PORT
      LAYER M5 ;
        RECT  178.56 444.876 178.584 444.96 ;
    END
  END li_d[86]
  PIN li_d[87]
    DIRECTION OUTPUT ;
    USE SIGNAL ;
    PORT
      LAYER M5 ;
        RECT  178.8 444.876 178.824 444.96 ;
    END
  END li_d[87]
  PIN li_d[88]
    DIRECTION OUTPUT ;
    USE SIGNAL ;
    PORT
      LAYER M5 ;
        RECT  179.04 444.876 179.064 444.96 ;
    END
  END li_d[88]
  PIN li_d[89]
    DIRECTION OUTPUT ;
    USE SIGNAL ;
    PORT
      LAYER M5 ;
        RECT  179.28 444.876 179.304 444.96 ;
    END
  END li_d[89]
  PIN li_d[8]
    DIRECTION OUTPUT ;
    USE SIGNAL ;
    PORT
      LAYER M5 ;
        RECT  159.84 444.876 159.864 444.96 ;
    END
  END li_d[8]
  PIN li_d[90]
    DIRECTION OUTPUT ;
    USE SIGNAL ;
    PORT
      LAYER M5 ;
        RECT  179.52 444.876 179.544 444.96 ;
    END
  END li_d[90]
  PIN li_d[91]
    DIRECTION OUTPUT ;
    USE SIGNAL ;
    PORT
      LAYER M5 ;
        RECT  179.76 444.876 179.784 444.96 ;
    END
  END li_d[91]
  PIN li_d[92]
    DIRECTION OUTPUT ;
    USE SIGNAL ;
    PORT
      LAYER M5 ;
        RECT  180 444.876 180.024 444.96 ;
    END
  END li_d[92]
  PIN li_d[93]
    DIRECTION OUTPUT ;
    USE SIGNAL ;
    PORT
      LAYER M5 ;
        RECT  180.24 444.876 180.264 444.96 ;
    END
  END li_d[93]
  PIN li_d[94]
    DIRECTION OUTPUT ;
    USE SIGNAL ;
    PORT
      LAYER M5 ;
        RECT  180.48 444.876 180.504 444.96 ;
    END
  END li_d[94]
  PIN li_d[95]
    DIRECTION OUTPUT ;
    USE SIGNAL ;
    PORT
      LAYER M5 ;
        RECT  180.72 444.876 180.744 444.96 ;
    END
  END li_d[95]
  PIN li_d[96]
    DIRECTION OUTPUT ;
    USE SIGNAL ;
    PORT
      LAYER M5 ;
        RECT  180.96 444.876 180.984 444.96 ;
    END
  END li_d[96]
  PIN li_d[97]
    DIRECTION OUTPUT ;
    USE SIGNAL ;
    PORT
      LAYER M5 ;
        RECT  181.2 444.876 181.224 444.96 ;
    END
  END li_d[97]
  PIN li_d[98]
    DIRECTION OUTPUT ;
    USE SIGNAL ;
    PORT
      LAYER M5 ;
        RECT  181.44 444.876 181.464 444.96 ;
    END
  END li_d[98]
  PIN li_d[99]
    DIRECTION OUTPUT ;
    USE SIGNAL ;
    PORT
      LAYER M5 ;
        RECT  181.68 444.876 181.704 444.96 ;
    END
  END li_d[99]
  PIN li_d[9]
    DIRECTION OUTPUT ;
    USE SIGNAL ;
    PORT
      LAYER M5 ;
        RECT  160.08 444.876 160.104 444.96 ;
    END
  END li_d[9]
  PIN li_r[0]
    DIRECTION INPUT ;
    USE SIGNAL ;
    PORT
      LAYER M5 ;
        RECT  157.68 444.876 157.704 444.96 ;
    END
  END li_r[0]
  PIN li_v[0]
    DIRECTION OUTPUT ;
    USE SIGNAL ;
    PORT
      LAYER M5 ;
        RECT  157.44 444.876 157.464 444.96 ;
    END
  END li_v[0]
  PIN lo_d[0]
    DIRECTION INPUT ;
    USE SIGNAL ;
    PORT
      LAYER M5 ;
        RECT  6.144 444.876 6.168 444.96 ;
    END
  END lo_d[0]
  PIN lo_d[100]
    DIRECTION INPUT ;
    USE SIGNAL ;
    PORT
      LAYER M5 ;
        RECT  30.144 444.876 30.168 444.96 ;
    END
  END lo_d[100]
  PIN lo_d[101]
    DIRECTION INPUT ;
    USE SIGNAL ;
    PORT
      LAYER M5 ;
        RECT  30.384 444.876 30.408 444.96 ;
    END
  END lo_d[101]
  PIN lo_d[102]
    DIRECTION INPUT ;
    USE SIGNAL ;
    PORT
      LAYER M5 ;
        RECT  30.624 444.876 30.648 444.96 ;
    END
  END lo_d[102]
  PIN lo_d[103]
    DIRECTION INPUT ;
    USE SIGNAL ;
    PORT
      LAYER M5 ;
        RECT  30.864 444.876 30.888 444.96 ;
    END
  END lo_d[103]
  PIN lo_d[104]
    DIRECTION INPUT ;
    USE SIGNAL ;
    PORT
      LAYER M5 ;
        RECT  31.104 444.876 31.128 444.96 ;
    END
  END lo_d[104]
  PIN lo_d[105]
    DIRECTION INPUT ;
    USE SIGNAL ;
    PORT
      LAYER M5 ;
        RECT  31.344 444.876 31.368 444.96 ;
    END
  END lo_d[105]
  PIN lo_d[106]
    DIRECTION INPUT ;
    USE SIGNAL ;
    PORT
      LAYER M5 ;
        RECT  31.584 444.876 31.608 444.96 ;
    END
  END lo_d[106]
  PIN lo_d[107]
    DIRECTION INPUT ;
    USE SIGNAL ;
    PORT
      LAYER M5 ;
        RECT  31.824 444.876 31.848 444.96 ;
    END
  END lo_d[107]
  PIN lo_d[108]
    DIRECTION INPUT ;
    USE SIGNAL ;
    PORT
      LAYER M5 ;
        RECT  32.064 444.876 32.088 444.96 ;
    END
  END lo_d[108]
  PIN lo_d[109]
    DIRECTION INPUT ;
    USE SIGNAL ;
    PORT
      LAYER M5 ;
        RECT  32.304 444.876 32.328 444.96 ;
    END
  END lo_d[109]
  PIN lo_d[10]
    DIRECTION INPUT ;
    USE SIGNAL ;
    PORT
      LAYER M5 ;
        RECT  8.544 444.876 8.568 444.96 ;
    END
  END lo_d[10]
  PIN lo_d[110]
    DIRECTION INPUT ;
    USE SIGNAL ;
    PORT
      LAYER M5 ;
        RECT  32.544 444.876 32.568 444.96 ;
    END
  END lo_d[110]
  PIN lo_d[111]
    DIRECTION INPUT ;
    USE SIGNAL ;
    PORT
      LAYER M5 ;
        RECT  32.784 444.876 32.808 444.96 ;
    END
  END lo_d[111]
  PIN lo_d[112]
    DIRECTION INPUT ;
    USE SIGNAL ;
    PORT
      LAYER M5 ;
        RECT  33.024 444.876 33.048 444.96 ;
    END
  END lo_d[112]
  PIN lo_d[113]
    DIRECTION INPUT ;
    USE SIGNAL ;
    PORT
      LAYER M5 ;
        RECT  33.264 444.876 33.288 444.96 ;
    END
  END lo_d[113]
  PIN lo_d[114]
    DIRECTION INPUT ;
    USE SIGNAL ;
    PORT
      LAYER M5 ;
        RECT  33.504 444.876 33.528 444.96 ;
    END
  END lo_d[114]
  PIN lo_d[115]
    DIRECTION INPUT ;
    USE SIGNAL ;
    PORT
      LAYER M5 ;
        RECT  33.744 444.876 33.768 444.96 ;
    END
  END lo_d[115]
  PIN lo_d[116]
    DIRECTION INPUT ;
    USE SIGNAL ;
    PORT
      LAYER M5 ;
        RECT  33.984 444.876 34.008 444.96 ;
    END
  END lo_d[116]
  PIN lo_d[117]
    DIRECTION INPUT ;
    USE SIGNAL ;
    PORT
      LAYER M5 ;
        RECT  34.224 444.876 34.248 444.96 ;
    END
  END lo_d[117]
  PIN lo_d[118]
    DIRECTION INPUT ;
    USE SIGNAL ;
    PORT
      LAYER M5 ;
        RECT  34.464 444.876 34.488 444.96 ;
    END
  END lo_d[118]
  PIN lo_d[119]
    DIRECTION INPUT ;
    USE SIGNAL ;
    PORT
      LAYER M5 ;
        RECT  34.704 444.876 34.728 444.96 ;
    END
  END lo_d[119]
  PIN lo_d[11]
    DIRECTION INPUT ;
    USE SIGNAL ;
    PORT
      LAYER M5 ;
        RECT  8.784 444.876 8.808 444.96 ;
    END
  END lo_d[11]
  PIN lo_d[120]
    DIRECTION INPUT ;
    USE SIGNAL ;
    PORT
      LAYER M5 ;
        RECT  34.944 444.876 34.968 444.96 ;
    END
  END lo_d[120]
  PIN lo_d[121]
    DIRECTION INPUT ;
    USE SIGNAL ;
    PORT
      LAYER M5 ;
        RECT  35.184 444.876 35.208 444.96 ;
    END
  END lo_d[121]
  PIN lo_d[122]
    DIRECTION INPUT ;
    USE SIGNAL ;
    PORT
      LAYER M5 ;
        RECT  35.424 444.876 35.448 444.96 ;
    END
  END lo_d[122]
  PIN lo_d[123]
    DIRECTION INPUT ;
    USE SIGNAL ;
    PORT
      LAYER M5 ;
        RECT  35.664 444.876 35.688 444.96 ;
    END
  END lo_d[123]
  PIN lo_d[124]
    DIRECTION INPUT ;
    USE SIGNAL ;
    PORT
      LAYER M5 ;
        RECT  35.904 444.876 35.928 444.96 ;
    END
  END lo_d[124]
  PIN lo_d[125]
    DIRECTION INPUT ;
    USE SIGNAL ;
    PORT
      LAYER M5 ;
        RECT  36.144 444.876 36.168 444.96 ;
    END
  END lo_d[125]
  PIN lo_d[126]
    DIRECTION INPUT ;
    USE SIGNAL ;
    PORT
      LAYER M5 ;
        RECT  36.384 444.876 36.408 444.96 ;
    END
  END lo_d[126]
  PIN lo_d[127]
    DIRECTION INPUT ;
    USE SIGNAL ;
    PORT
      LAYER M5 ;
        RECT  36.624 444.876 36.648 444.96 ;
    END
  END lo_d[127]
  PIN lo_d[128]
    DIRECTION INPUT ;
    USE SIGNAL ;
    PORT
      LAYER M5 ;
        RECT  36.864 444.876 36.888 444.96 ;
    END
  END lo_d[128]
  PIN lo_d[129]
    DIRECTION INPUT ;
    USE SIGNAL ;
    PORT
      LAYER M5 ;
        RECT  37.104 444.876 37.128 444.96 ;
    END
  END lo_d[129]
  PIN lo_d[12]
    DIRECTION INPUT ;
    USE SIGNAL ;
    PORT
      LAYER M5 ;
        RECT  9.024 444.876 9.048 444.96 ;
    END
  END lo_d[12]
  PIN lo_d[130]
    DIRECTION INPUT ;
    USE SIGNAL ;
    PORT
      LAYER M5 ;
        RECT  37.344 444.876 37.368 444.96 ;
    END
  END lo_d[130]
  PIN lo_d[131]
    DIRECTION INPUT ;
    USE SIGNAL ;
    PORT
      LAYER M5 ;
        RECT  37.584 444.876 37.608 444.96 ;
    END
  END lo_d[131]
  PIN lo_d[132]
    DIRECTION INPUT ;
    USE SIGNAL ;
    PORT
      LAYER M5 ;
        RECT  37.824 444.876 37.848 444.96 ;
    END
  END lo_d[132]
  PIN lo_d[133]
    DIRECTION INPUT ;
    USE SIGNAL ;
    PORT
      LAYER M5 ;
        RECT  38.064 444.876 38.088 444.96 ;
    END
  END lo_d[133]
  PIN lo_d[134]
    DIRECTION INPUT ;
    USE SIGNAL ;
    PORT
      LAYER M5 ;
        RECT  38.304 444.876 38.328 444.96 ;
    END
  END lo_d[134]
  PIN lo_d[135]
    DIRECTION INPUT ;
    USE SIGNAL ;
    PORT
      LAYER M5 ;
        RECT  38.544 444.876 38.568 444.96 ;
    END
  END lo_d[135]
  PIN lo_d[136]
    DIRECTION INPUT ;
    USE SIGNAL ;
    PORT
      LAYER M5 ;
        RECT  38.784 444.876 38.808 444.96 ;
    END
  END lo_d[136]
  PIN lo_d[137]
    DIRECTION INPUT ;
    USE SIGNAL ;
    PORT
      LAYER M5 ;
        RECT  39.024 444.876 39.048 444.96 ;
    END
  END lo_d[137]
  PIN lo_d[138]
    DIRECTION INPUT ;
    USE SIGNAL ;
    PORT
      LAYER M5 ;
        RECT  39.264 444.876 39.288 444.96 ;
    END
  END lo_d[138]
  PIN lo_d[139]
    DIRECTION INPUT ;
    USE SIGNAL ;
    PORT
      LAYER M5 ;
        RECT  39.504 444.876 39.528 444.96 ;
    END
  END lo_d[139]
  PIN lo_d[13]
    DIRECTION INPUT ;
    USE SIGNAL ;
    PORT
      LAYER M5 ;
        RECT  9.264 444.876 9.288 444.96 ;
    END
  END lo_d[13]
  PIN lo_d[140]
    DIRECTION INPUT ;
    USE SIGNAL ;
    PORT
      LAYER M5 ;
        RECT  39.744 444.876 39.768 444.96 ;
    END
  END lo_d[140]
  PIN lo_d[141]
    DIRECTION INPUT ;
    USE SIGNAL ;
    PORT
      LAYER M5 ;
        RECT  39.984 444.876 40.008 444.96 ;
    END
  END lo_d[141]
  PIN lo_d[142]
    DIRECTION INPUT ;
    USE SIGNAL ;
    PORT
      LAYER M5 ;
        RECT  40.224 444.876 40.248 444.96 ;
    END
  END lo_d[142]
  PIN lo_d[143]
    DIRECTION INPUT ;
    USE SIGNAL ;
    PORT
      LAYER M5 ;
        RECT  40.464 444.876 40.488 444.96 ;
    END
  END lo_d[143]
  PIN lo_d[144]
    DIRECTION INPUT ;
    USE SIGNAL ;
    PORT
      LAYER M5 ;
        RECT  40.704 444.876 40.728 444.96 ;
    END
  END lo_d[144]
  PIN lo_d[145]
    DIRECTION INPUT ;
    USE SIGNAL ;
    PORT
      LAYER M5 ;
        RECT  40.944 444.876 40.968 444.96 ;
    END
  END lo_d[145]
  PIN lo_d[146]
    DIRECTION INPUT ;
    USE SIGNAL ;
    PORT
      LAYER M5 ;
        RECT  41.184 444.876 41.208 444.96 ;
    END
  END lo_d[146]
  PIN lo_d[147]
    DIRECTION INPUT ;
    USE SIGNAL ;
    PORT
      LAYER M5 ;
        RECT  41.424 444.876 41.448 444.96 ;
    END
  END lo_d[147]
  PIN lo_d[148]
    DIRECTION INPUT ;
    USE SIGNAL ;
    PORT
      LAYER M5 ;
        RECT  41.664 444.876 41.688 444.96 ;
    END
  END lo_d[148]
  PIN lo_d[149]
    DIRECTION INPUT ;
    USE SIGNAL ;
    PORT
      LAYER M5 ;
        RECT  41.904 444.876 41.928 444.96 ;
    END
  END lo_d[149]
  PIN lo_d[14]
    DIRECTION INPUT ;
    USE SIGNAL ;
    PORT
      LAYER M5 ;
        RECT  9.504 444.876 9.528 444.96 ;
    END
  END lo_d[14]
  PIN lo_d[150]
    DIRECTION INPUT ;
    USE SIGNAL ;
    PORT
      LAYER M5 ;
        RECT  42.144 444.876 42.168 444.96 ;
    END
  END lo_d[150]
  PIN lo_d[151]
    DIRECTION INPUT ;
    USE SIGNAL ;
    PORT
      LAYER M5 ;
        RECT  42.384 444.876 42.408 444.96 ;
    END
  END lo_d[151]
  PIN lo_d[152]
    DIRECTION INPUT ;
    USE SIGNAL ;
    PORT
      LAYER M5 ;
        RECT  42.624 444.876 42.648 444.96 ;
    END
  END lo_d[152]
  PIN lo_d[153]
    DIRECTION INPUT ;
    USE SIGNAL ;
    PORT
      LAYER M5 ;
        RECT  42.864 444.876 42.888 444.96 ;
    END
  END lo_d[153]
  PIN lo_d[154]
    DIRECTION INPUT ;
    USE SIGNAL ;
    PORT
      LAYER M5 ;
        RECT  43.104 444.876 43.128 444.96 ;
    END
  END lo_d[154]
  PIN lo_d[155]
    DIRECTION INPUT ;
    USE SIGNAL ;
    PORT
      LAYER M5 ;
        RECT  43.344 444.876 43.368 444.96 ;
    END
  END lo_d[155]
  PIN lo_d[156]
    DIRECTION INPUT ;
    USE SIGNAL ;
    PORT
      LAYER M5 ;
        RECT  43.584 444.876 43.608 444.96 ;
    END
  END lo_d[156]
  PIN lo_d[157]
    DIRECTION INPUT ;
    USE SIGNAL ;
    PORT
      LAYER M5 ;
        RECT  43.824 444.876 43.848 444.96 ;
    END
  END lo_d[157]
  PIN lo_d[158]
    DIRECTION INPUT ;
    USE SIGNAL ;
    PORT
      LAYER M5 ;
        RECT  44.064 444.876 44.088 444.96 ;
    END
  END lo_d[158]
  PIN lo_d[159]
    DIRECTION INPUT ;
    USE SIGNAL ;
    PORT
      LAYER M5 ;
        RECT  44.304 444.876 44.328 444.96 ;
    END
  END lo_d[159]
  PIN lo_d[15]
    DIRECTION INPUT ;
    USE SIGNAL ;
    PORT
      LAYER M5 ;
        RECT  9.744 444.876 9.768 444.96 ;
    END
  END lo_d[15]
  PIN lo_d[160]
    DIRECTION INPUT ;
    USE SIGNAL ;
    PORT
      LAYER M5 ;
        RECT  44.544 444.876 44.568 444.96 ;
    END
  END lo_d[160]
  PIN lo_d[161]
    DIRECTION INPUT ;
    USE SIGNAL ;
    PORT
      LAYER M5 ;
        RECT  44.784 444.876 44.808 444.96 ;
    END
  END lo_d[161]
  PIN lo_d[162]
    DIRECTION INPUT ;
    USE SIGNAL ;
    PORT
      LAYER M5 ;
        RECT  45.024 444.876 45.048 444.96 ;
    END
  END lo_d[162]
  PIN lo_d[163]
    DIRECTION INPUT ;
    USE SIGNAL ;
    PORT
      LAYER M5 ;
        RECT  45.264 444.876 45.288 444.96 ;
    END
  END lo_d[163]
  PIN lo_d[164]
    DIRECTION INPUT ;
    USE SIGNAL ;
    PORT
      LAYER M5 ;
        RECT  45.504 444.876 45.528 444.96 ;
    END
  END lo_d[164]
  PIN lo_d[165]
    DIRECTION INPUT ;
    USE SIGNAL ;
    PORT
      LAYER M5 ;
        RECT  45.744 444.876 45.768 444.96 ;
    END
  END lo_d[165]
  PIN lo_d[166]
    DIRECTION INPUT ;
    USE SIGNAL ;
    PORT
      LAYER M5 ;
        RECT  45.984 444.876 46.008 444.96 ;
    END
  END lo_d[166]
  PIN lo_d[167]
    DIRECTION INPUT ;
    USE SIGNAL ;
    PORT
      LAYER M5 ;
        RECT  46.224 444.876 46.248 444.96 ;
    END
  END lo_d[167]
  PIN lo_d[168]
    DIRECTION INPUT ;
    USE SIGNAL ;
    PORT
      LAYER M5 ;
        RECT  46.464 444.876 46.488 444.96 ;
    END
  END lo_d[168]
  PIN lo_d[169]
    DIRECTION INPUT ;
    USE SIGNAL ;
    PORT
      LAYER M5 ;
        RECT  46.704 444.876 46.728 444.96 ;
    END
  END lo_d[169]
  PIN lo_d[16]
    DIRECTION INPUT ;
    USE SIGNAL ;
    PORT
      LAYER M5 ;
        RECT  9.984 444.876 10.008 444.96 ;
    END
  END lo_d[16]
  PIN lo_d[170]
    DIRECTION INPUT ;
    USE SIGNAL ;
    PORT
      LAYER M5 ;
        RECT  46.944 444.876 46.968 444.96 ;
    END
  END lo_d[170]
  PIN lo_d[171]
    DIRECTION INPUT ;
    USE SIGNAL ;
    PORT
      LAYER M5 ;
        RECT  47.184 444.876 47.208 444.96 ;
    END
  END lo_d[171]
  PIN lo_d[172]
    DIRECTION INPUT ;
    USE SIGNAL ;
    PORT
      LAYER M5 ;
        RECT  47.424 444.876 47.448 444.96 ;
    END
  END lo_d[172]
  PIN lo_d[173]
    DIRECTION INPUT ;
    USE SIGNAL ;
    PORT
      LAYER M5 ;
        RECT  47.664 444.876 47.688 444.96 ;
    END
  END lo_d[173]
  PIN lo_d[174]
    DIRECTION INPUT ;
    USE SIGNAL ;
    PORT
      LAYER M5 ;
        RECT  47.904 444.876 47.928 444.96 ;
    END
  END lo_d[174]
  PIN lo_d[175]
    DIRECTION INPUT ;
    USE SIGNAL ;
    PORT
      LAYER M5 ;
        RECT  48.144 444.876 48.168 444.96 ;
    END
  END lo_d[175]
  PIN lo_d[176]
    DIRECTION INPUT ;
    USE SIGNAL ;
    PORT
      LAYER M5 ;
        RECT  48.384 444.876 48.408 444.96 ;
    END
  END lo_d[176]
  PIN lo_d[177]
    DIRECTION INPUT ;
    USE SIGNAL ;
    PORT
      LAYER M5 ;
        RECT  48.624 444.876 48.648 444.96 ;
    END
  END lo_d[177]
  PIN lo_d[178]
    DIRECTION INPUT ;
    USE SIGNAL ;
    PORT
      LAYER M5 ;
        RECT  48.864 444.876 48.888 444.96 ;
    END
  END lo_d[178]
  PIN lo_d[179]
    DIRECTION INPUT ;
    USE SIGNAL ;
    PORT
      LAYER M5 ;
        RECT  49.104 444.876 49.128 444.96 ;
    END
  END lo_d[179]
  PIN lo_d[17]
    DIRECTION INPUT ;
    USE SIGNAL ;
    PORT
      LAYER M5 ;
        RECT  10.224 444.876 10.248 444.96 ;
    END
  END lo_d[17]
  PIN lo_d[180]
    DIRECTION INPUT ;
    USE SIGNAL ;
    PORT
      LAYER M5 ;
        RECT  49.344 444.876 49.368 444.96 ;
    END
  END lo_d[180]
  PIN lo_d[181]
    DIRECTION INPUT ;
    USE SIGNAL ;
    PORT
      LAYER M5 ;
        RECT  49.584 444.876 49.608 444.96 ;
    END
  END lo_d[181]
  PIN lo_d[182]
    DIRECTION INPUT ;
    USE SIGNAL ;
    PORT
      LAYER M5 ;
        RECT  49.824 444.876 49.848 444.96 ;
    END
  END lo_d[182]
  PIN lo_d[183]
    DIRECTION INPUT ;
    USE SIGNAL ;
    PORT
      LAYER M5 ;
        RECT  50.064 444.876 50.088 444.96 ;
    END
  END lo_d[183]
  PIN lo_d[184]
    DIRECTION INPUT ;
    USE SIGNAL ;
    PORT
      LAYER M5 ;
        RECT  50.304 444.876 50.328 444.96 ;
    END
  END lo_d[184]
  PIN lo_d[185]
    DIRECTION INPUT ;
    USE SIGNAL ;
    PORT
      LAYER M5 ;
        RECT  50.544 444.876 50.568 444.96 ;
    END
  END lo_d[185]
  PIN lo_d[186]
    DIRECTION INPUT ;
    USE SIGNAL ;
    PORT
      LAYER M5 ;
        RECT  50.784 444.876 50.808 444.96 ;
    END
  END lo_d[186]
  PIN lo_d[187]
    DIRECTION INPUT ;
    USE SIGNAL ;
    PORT
      LAYER M5 ;
        RECT  51.024 444.876 51.048 444.96 ;
    END
  END lo_d[187]
  PIN lo_d[188]
    DIRECTION INPUT ;
    USE SIGNAL ;
    PORT
      LAYER M5 ;
        RECT  51.264 444.876 51.288 444.96 ;
    END
  END lo_d[188]
  PIN lo_d[189]
    DIRECTION INPUT ;
    USE SIGNAL ;
    PORT
      LAYER M5 ;
        RECT  51.504 444.876 51.528 444.96 ;
    END
  END lo_d[189]
  PIN lo_d[18]
    DIRECTION INPUT ;
    USE SIGNAL ;
    PORT
      LAYER M5 ;
        RECT  10.464 444.876 10.488 444.96 ;
    END
  END lo_d[18]
  PIN lo_d[190]
    DIRECTION INPUT ;
    USE SIGNAL ;
    PORT
      LAYER M5 ;
        RECT  51.744 444.876 51.768 444.96 ;
    END
  END lo_d[190]
  PIN lo_d[191]
    DIRECTION INPUT ;
    USE SIGNAL ;
    PORT
      LAYER M5 ;
        RECT  51.984 444.876 52.008 444.96 ;
    END
  END lo_d[191]
  PIN lo_d[192]
    DIRECTION INPUT ;
    USE SIGNAL ;
    PORT
      LAYER M5 ;
        RECT  52.224 444.876 52.248 444.96 ;
    END
  END lo_d[192]
  PIN lo_d[193]
    DIRECTION INPUT ;
    USE SIGNAL ;
    PORT
      LAYER M5 ;
        RECT  52.464 444.876 52.488 444.96 ;
    END
  END lo_d[193]
  PIN lo_d[194]
    DIRECTION INPUT ;
    USE SIGNAL ;
    PORT
      LAYER M5 ;
        RECT  52.704 444.876 52.728 444.96 ;
    END
  END lo_d[194]
  PIN lo_d[195]
    DIRECTION INPUT ;
    USE SIGNAL ;
    PORT
      LAYER M5 ;
        RECT  52.944 444.876 52.968 444.96 ;
    END
  END lo_d[195]
  PIN lo_d[196]
    DIRECTION INPUT ;
    USE SIGNAL ;
    PORT
      LAYER M5 ;
        RECT  53.184 444.876 53.208 444.96 ;
    END
  END lo_d[196]
  PIN lo_d[197]
    DIRECTION INPUT ;
    USE SIGNAL ;
    PORT
      LAYER M5 ;
        RECT  53.424 444.876 53.448 444.96 ;
    END
  END lo_d[197]
  PIN lo_d[198]
    DIRECTION INPUT ;
    USE SIGNAL ;
    PORT
      LAYER M5 ;
        RECT  53.664 444.876 53.688 444.96 ;
    END
  END lo_d[198]
  PIN lo_d[199]
    DIRECTION INPUT ;
    USE SIGNAL ;
    PORT
      LAYER M5 ;
        RECT  53.904 444.876 53.928 444.96 ;
    END
  END lo_d[199]
  PIN lo_d[19]
    DIRECTION INPUT ;
    USE SIGNAL ;
    PORT
      LAYER M5 ;
        RECT  10.704 444.876 10.728 444.96 ;
    END
  END lo_d[19]
  PIN lo_d[1]
    DIRECTION INPUT ;
    USE SIGNAL ;
    PORT
      LAYER M5 ;
        RECT  6.384 444.876 6.408 444.96 ;
    END
  END lo_d[1]
  PIN lo_d[200]
    DIRECTION INPUT ;
    USE SIGNAL ;
    PORT
      LAYER M5 ;
        RECT  54.144 444.876 54.168 444.96 ;
    END
  END lo_d[200]
  PIN lo_d[201]
    DIRECTION INPUT ;
    USE SIGNAL ;
    PORT
      LAYER M5 ;
        RECT  54.384 444.876 54.408 444.96 ;
    END
  END lo_d[201]
  PIN lo_d[202]
    DIRECTION INPUT ;
    USE SIGNAL ;
    PORT
      LAYER M5 ;
        RECT  54.624 444.876 54.648 444.96 ;
    END
  END lo_d[202]
  PIN lo_d[203]
    DIRECTION INPUT ;
    USE SIGNAL ;
    PORT
      LAYER M5 ;
        RECT  54.864 444.876 54.888 444.96 ;
    END
  END lo_d[203]
  PIN lo_d[204]
    DIRECTION INPUT ;
    USE SIGNAL ;
    PORT
      LAYER M5 ;
        RECT  55.104 444.876 55.128 444.96 ;
    END
  END lo_d[204]
  PIN lo_d[205]
    DIRECTION INPUT ;
    USE SIGNAL ;
    PORT
      LAYER M5 ;
        RECT  55.344 444.876 55.368 444.96 ;
    END
  END lo_d[205]
  PIN lo_d[206]
    DIRECTION INPUT ;
    USE SIGNAL ;
    PORT
      LAYER M5 ;
        RECT  55.584 444.876 55.608 444.96 ;
    END
  END lo_d[206]
  PIN lo_d[207]
    DIRECTION INPUT ;
    USE SIGNAL ;
    PORT
      LAYER M5 ;
        RECT  55.824 444.876 55.848 444.96 ;
    END
  END lo_d[207]
  PIN lo_d[208]
    DIRECTION INPUT ;
    USE SIGNAL ;
    PORT
      LAYER M5 ;
        RECT  56.064 444.876 56.088 444.96 ;
    END
  END lo_d[208]
  PIN lo_d[209]
    DIRECTION INPUT ;
    USE SIGNAL ;
    PORT
      LAYER M5 ;
        RECT  56.304 444.876 56.328 444.96 ;
    END
  END lo_d[209]
  PIN lo_d[20]
    DIRECTION INPUT ;
    USE SIGNAL ;
    PORT
      LAYER M5 ;
        RECT  10.944 444.876 10.968 444.96 ;
    END
  END lo_d[20]
  PIN lo_d[210]
    DIRECTION INPUT ;
    USE SIGNAL ;
    PORT
      LAYER M5 ;
        RECT  56.544 444.876 56.568 444.96 ;
    END
  END lo_d[210]
  PIN lo_d[211]
    DIRECTION INPUT ;
    USE SIGNAL ;
    PORT
      LAYER M5 ;
        RECT  56.784 444.876 56.808 444.96 ;
    END
  END lo_d[211]
  PIN lo_d[212]
    DIRECTION INPUT ;
    USE SIGNAL ;
    PORT
      LAYER M5 ;
        RECT  57.024 444.876 57.048 444.96 ;
    END
  END lo_d[212]
  PIN lo_d[213]
    DIRECTION INPUT ;
    USE SIGNAL ;
    PORT
      LAYER M5 ;
        RECT  57.264 444.876 57.288 444.96 ;
    END
  END lo_d[213]
  PIN lo_d[214]
    DIRECTION INPUT ;
    USE SIGNAL ;
    PORT
      LAYER M5 ;
        RECT  57.504 444.876 57.528 444.96 ;
    END
  END lo_d[214]
  PIN lo_d[215]
    DIRECTION INPUT ;
    USE SIGNAL ;
    PORT
      LAYER M5 ;
        RECT  57.744 444.876 57.768 444.96 ;
    END
  END lo_d[215]
  PIN lo_d[216]
    DIRECTION INPUT ;
    USE SIGNAL ;
    PORT
      LAYER M5 ;
        RECT  57.984 444.876 58.008 444.96 ;
    END
  END lo_d[216]
  PIN lo_d[217]
    DIRECTION INPUT ;
    USE SIGNAL ;
    PORT
      LAYER M5 ;
        RECT  58.224 444.876 58.248 444.96 ;
    END
  END lo_d[217]
  PIN lo_d[218]
    DIRECTION INPUT ;
    USE SIGNAL ;
    PORT
      LAYER M5 ;
        RECT  58.464 444.876 58.488 444.96 ;
    END
  END lo_d[218]
  PIN lo_d[219]
    DIRECTION INPUT ;
    USE SIGNAL ;
    PORT
      LAYER M5 ;
        RECT  58.704 444.876 58.728 444.96 ;
    END
  END lo_d[219]
  PIN lo_d[21]
    DIRECTION INPUT ;
    USE SIGNAL ;
    PORT
      LAYER M5 ;
        RECT  11.184 444.876 11.208 444.96 ;
    END
  END lo_d[21]
  PIN lo_d[220]
    DIRECTION INPUT ;
    USE SIGNAL ;
    PORT
      LAYER M5 ;
        RECT  58.944 444.876 58.968 444.96 ;
    END
  END lo_d[220]
  PIN lo_d[221]
    DIRECTION INPUT ;
    USE SIGNAL ;
    PORT
      LAYER M5 ;
        RECT  59.184 444.876 59.208 444.96 ;
    END
  END lo_d[221]
  PIN lo_d[222]
    DIRECTION INPUT ;
    USE SIGNAL ;
    PORT
      LAYER M5 ;
        RECT  59.424 444.876 59.448 444.96 ;
    END
  END lo_d[222]
  PIN lo_d[223]
    DIRECTION INPUT ;
    USE SIGNAL ;
    PORT
      LAYER M5 ;
        RECT  59.664 444.876 59.688 444.96 ;
    END
  END lo_d[223]
  PIN lo_d[224]
    DIRECTION INPUT ;
    USE SIGNAL ;
    PORT
      LAYER M5 ;
        RECT  59.904 444.876 59.928 444.96 ;
    END
  END lo_d[224]
  PIN lo_d[225]
    DIRECTION INPUT ;
    USE SIGNAL ;
    PORT
      LAYER M5 ;
        RECT  60.144 444.876 60.168 444.96 ;
    END
  END lo_d[225]
  PIN lo_d[226]
    DIRECTION INPUT ;
    USE SIGNAL ;
    PORT
      LAYER M5 ;
        RECT  60.384 444.876 60.408 444.96 ;
    END
  END lo_d[226]
  PIN lo_d[227]
    DIRECTION INPUT ;
    USE SIGNAL ;
    PORT
      LAYER M5 ;
        RECT  60.624 444.876 60.648 444.96 ;
    END
  END lo_d[227]
  PIN lo_d[228]
    DIRECTION INPUT ;
    USE SIGNAL ;
    PORT
      LAYER M5 ;
        RECT  60.864 444.876 60.888 444.96 ;
    END
  END lo_d[228]
  PIN lo_d[229]
    DIRECTION INPUT ;
    USE SIGNAL ;
    PORT
      LAYER M5 ;
        RECT  61.104 444.876 61.128 444.96 ;
    END
  END lo_d[229]
  PIN lo_d[22]
    DIRECTION INPUT ;
    USE SIGNAL ;
    PORT
      LAYER M5 ;
        RECT  11.424 444.876 11.448 444.96 ;
    END
  END lo_d[22]
  PIN lo_d[230]
    DIRECTION INPUT ;
    USE SIGNAL ;
    PORT
      LAYER M5 ;
        RECT  61.344 444.876 61.368 444.96 ;
    END
  END lo_d[230]
  PIN lo_d[231]
    DIRECTION INPUT ;
    USE SIGNAL ;
    PORT
      LAYER M5 ;
        RECT  61.584 444.876 61.608 444.96 ;
    END
  END lo_d[231]
  PIN lo_d[232]
    DIRECTION INPUT ;
    USE SIGNAL ;
    PORT
      LAYER M5 ;
        RECT  61.824 444.876 61.848 444.96 ;
    END
  END lo_d[232]
  PIN lo_d[233]
    DIRECTION INPUT ;
    USE SIGNAL ;
    PORT
      LAYER M5 ;
        RECT  62.064 444.876 62.088 444.96 ;
    END
  END lo_d[233]
  PIN lo_d[234]
    DIRECTION INPUT ;
    USE SIGNAL ;
    PORT
      LAYER M5 ;
        RECT  62.304 444.876 62.328 444.96 ;
    END
  END lo_d[234]
  PIN lo_d[235]
    DIRECTION INPUT ;
    USE SIGNAL ;
    PORT
      LAYER M5 ;
        RECT  62.544 444.876 62.568 444.96 ;
    END
  END lo_d[235]
  PIN lo_d[236]
    DIRECTION INPUT ;
    USE SIGNAL ;
    PORT
      LAYER M5 ;
        RECT  62.784 444.876 62.808 444.96 ;
    END
  END lo_d[236]
  PIN lo_d[237]
    DIRECTION INPUT ;
    USE SIGNAL ;
    PORT
      LAYER M5 ;
        RECT  63.024 444.876 63.048 444.96 ;
    END
  END lo_d[237]
  PIN lo_d[238]
    DIRECTION INPUT ;
    USE SIGNAL ;
    PORT
      LAYER M5 ;
        RECT  63.264 444.876 63.288 444.96 ;
    END
  END lo_d[238]
  PIN lo_d[239]
    DIRECTION INPUT ;
    USE SIGNAL ;
    PORT
      LAYER M5 ;
        RECT  63.504 444.876 63.528 444.96 ;
    END
  END lo_d[239]
  PIN lo_d[23]
    DIRECTION INPUT ;
    USE SIGNAL ;
    PORT
      LAYER M5 ;
        RECT  11.664 444.876 11.688 444.96 ;
    END
  END lo_d[23]
  PIN lo_d[240]
    DIRECTION INPUT ;
    USE SIGNAL ;
    PORT
      LAYER M5 ;
        RECT  63.744 444.876 63.768 444.96 ;
    END
  END lo_d[240]
  PIN lo_d[241]
    DIRECTION INPUT ;
    USE SIGNAL ;
    PORT
      LAYER M5 ;
        RECT  63.984 444.876 64.008 444.96 ;
    END
  END lo_d[241]
  PIN lo_d[242]
    DIRECTION INPUT ;
    USE SIGNAL ;
    PORT
      LAYER M5 ;
        RECT  64.224 444.876 64.248 444.96 ;
    END
  END lo_d[242]
  PIN lo_d[243]
    DIRECTION INPUT ;
    USE SIGNAL ;
    PORT
      LAYER M5 ;
        RECT  64.464 444.876 64.488 444.96 ;
    END
  END lo_d[243]
  PIN lo_d[244]
    DIRECTION INPUT ;
    USE SIGNAL ;
    PORT
      LAYER M5 ;
        RECT  64.704 444.876 64.728 444.96 ;
    END
  END lo_d[244]
  PIN lo_d[245]
    DIRECTION INPUT ;
    USE SIGNAL ;
    PORT
      LAYER M5 ;
        RECT  64.944 444.876 64.968 444.96 ;
    END
  END lo_d[245]
  PIN lo_d[246]
    DIRECTION INPUT ;
    USE SIGNAL ;
    PORT
      LAYER M5 ;
        RECT  65.184 444.876 65.208 444.96 ;
    END
  END lo_d[246]
  PIN lo_d[247]
    DIRECTION INPUT ;
    USE SIGNAL ;
    PORT
      LAYER M5 ;
        RECT  65.424 444.876 65.448 444.96 ;
    END
  END lo_d[247]
  PIN lo_d[248]
    DIRECTION INPUT ;
    USE SIGNAL ;
    PORT
      LAYER M5 ;
        RECT  65.664 444.876 65.688 444.96 ;
    END
  END lo_d[248]
  PIN lo_d[249]
    DIRECTION INPUT ;
    USE SIGNAL ;
    PORT
      LAYER M5 ;
        RECT  65.904 444.876 65.928 444.96 ;
    END
  END lo_d[249]
  PIN lo_d[24]
    DIRECTION INPUT ;
    USE SIGNAL ;
    PORT
      LAYER M5 ;
        RECT  11.904 444.876 11.928 444.96 ;
    END
  END lo_d[24]
  PIN lo_d[250]
    DIRECTION INPUT ;
    USE SIGNAL ;
    PORT
      LAYER M5 ;
        RECT  66.144 444.876 66.168 444.96 ;
    END
  END lo_d[250]
  PIN lo_d[251]
    DIRECTION INPUT ;
    USE SIGNAL ;
    PORT
      LAYER M5 ;
        RECT  66.384 444.876 66.408 444.96 ;
    END
  END lo_d[251]
  PIN lo_d[252]
    DIRECTION INPUT ;
    USE SIGNAL ;
    PORT
      LAYER M5 ;
        RECT  66.624 444.876 66.648 444.96 ;
    END
  END lo_d[252]
  PIN lo_d[253]
    DIRECTION INPUT ;
    USE SIGNAL ;
    PORT
      LAYER M5 ;
        RECT  66.864 444.876 66.888 444.96 ;
    END
  END lo_d[253]
  PIN lo_d[254]
    DIRECTION INPUT ;
    USE SIGNAL ;
    PORT
      LAYER M5 ;
        RECT  67.104 444.876 67.128 444.96 ;
    END
  END lo_d[254]
  PIN lo_d[255]
    DIRECTION INPUT ;
    USE SIGNAL ;
    PORT
      LAYER M5 ;
        RECT  67.344 444.876 67.368 444.96 ;
    END
  END lo_d[255]
  PIN lo_d[256]
    DIRECTION INPUT ;
    USE SIGNAL ;
    PORT
      LAYER M5 ;
        RECT  67.584 444.876 67.608 444.96 ;
    END
  END lo_d[256]
  PIN lo_d[257]
    DIRECTION INPUT ;
    USE SIGNAL ;
    PORT
      LAYER M5 ;
        RECT  67.824 444.876 67.848 444.96 ;
    END
  END lo_d[257]
  PIN lo_d[258]
    DIRECTION INPUT ;
    USE SIGNAL ;
    PORT
      LAYER M5 ;
        RECT  68.064 444.876 68.088 444.96 ;
    END
  END lo_d[258]
  PIN lo_d[259]
    DIRECTION INPUT ;
    USE SIGNAL ;
    PORT
      LAYER M5 ;
        RECT  68.304 444.876 68.328 444.96 ;
    END
  END lo_d[259]
  PIN lo_d[25]
    DIRECTION INPUT ;
    USE SIGNAL ;
    PORT
      LAYER M5 ;
        RECT  12.144 444.876 12.168 444.96 ;
    END
  END lo_d[25]
  PIN lo_d[260]
    DIRECTION INPUT ;
    USE SIGNAL ;
    PORT
      LAYER M5 ;
        RECT  68.544 444.876 68.568 444.96 ;
    END
  END lo_d[260]
  PIN lo_d[261]
    DIRECTION INPUT ;
    USE SIGNAL ;
    PORT
      LAYER M5 ;
        RECT  68.784 444.876 68.808 444.96 ;
    END
  END lo_d[261]
  PIN lo_d[262]
    DIRECTION INPUT ;
    USE SIGNAL ;
    PORT
      LAYER M5 ;
        RECT  69.024 444.876 69.048 444.96 ;
    END
  END lo_d[262]
  PIN lo_d[263]
    DIRECTION INPUT ;
    USE SIGNAL ;
    PORT
      LAYER M5 ;
        RECT  69.264 444.876 69.288 444.96 ;
    END
  END lo_d[263]
  PIN lo_d[264]
    DIRECTION INPUT ;
    USE SIGNAL ;
    PORT
      LAYER M5 ;
        RECT  69.504 444.876 69.528 444.96 ;
    END
  END lo_d[264]
  PIN lo_d[265]
    DIRECTION INPUT ;
    USE SIGNAL ;
    PORT
      LAYER M5 ;
        RECT  69.744 444.876 69.768 444.96 ;
    END
  END lo_d[265]
  PIN lo_d[266]
    DIRECTION INPUT ;
    USE SIGNAL ;
    PORT
      LAYER M5 ;
        RECT  69.984 444.876 70.008 444.96 ;
    END
  END lo_d[266]
  PIN lo_d[267]
    DIRECTION INPUT ;
    USE SIGNAL ;
    PORT
      LAYER M5 ;
        RECT  70.224 444.876 70.248 444.96 ;
    END
  END lo_d[267]
  PIN lo_d[268]
    DIRECTION INPUT ;
    USE SIGNAL ;
    PORT
      LAYER M5 ;
        RECT  70.464 444.876 70.488 444.96 ;
    END
  END lo_d[268]
  PIN lo_d[269]
    DIRECTION INPUT ;
    USE SIGNAL ;
    PORT
      LAYER M5 ;
        RECT  70.704 444.876 70.728 444.96 ;
    END
  END lo_d[269]
  PIN lo_d[26]
    DIRECTION INPUT ;
    USE SIGNAL ;
    PORT
      LAYER M5 ;
        RECT  12.384 444.876 12.408 444.96 ;
    END
  END lo_d[26]
  PIN lo_d[270]
    DIRECTION INPUT ;
    USE SIGNAL ;
    PORT
      LAYER M5 ;
        RECT  70.944 444.876 70.968 444.96 ;
    END
  END lo_d[270]
  PIN lo_d[271]
    DIRECTION INPUT ;
    USE SIGNAL ;
    PORT
      LAYER M5 ;
        RECT  71.184 444.876 71.208 444.96 ;
    END
  END lo_d[271]
  PIN lo_d[272]
    DIRECTION INPUT ;
    USE SIGNAL ;
    PORT
      LAYER M5 ;
        RECT  71.424 444.876 71.448 444.96 ;
    END
  END lo_d[272]
  PIN lo_d[273]
    DIRECTION INPUT ;
    USE SIGNAL ;
    PORT
      LAYER M5 ;
        RECT  71.664 444.876 71.688 444.96 ;
    END
  END lo_d[273]
  PIN lo_d[274]
    DIRECTION INPUT ;
    USE SIGNAL ;
    PORT
      LAYER M5 ;
        RECT  71.904 444.876 71.928 444.96 ;
    END
  END lo_d[274]
  PIN lo_d[275]
    DIRECTION INPUT ;
    USE SIGNAL ;
    PORT
      LAYER M5 ;
        RECT  72.144 444.876 72.168 444.96 ;
    END
  END lo_d[275]
  PIN lo_d[276]
    DIRECTION INPUT ;
    USE SIGNAL ;
    PORT
      LAYER M5 ;
        RECT  72.384 444.876 72.408 444.96 ;
    END
  END lo_d[276]
  PIN lo_d[277]
    DIRECTION INPUT ;
    USE SIGNAL ;
    PORT
      LAYER M5 ;
        RECT  72.624 444.876 72.648 444.96 ;
    END
  END lo_d[277]
  PIN lo_d[278]
    DIRECTION INPUT ;
    USE SIGNAL ;
    PORT
      LAYER M5 ;
        RECT  72.864 444.876 72.888 444.96 ;
    END
  END lo_d[278]
  PIN lo_d[279]
    DIRECTION INPUT ;
    USE SIGNAL ;
    PORT
      LAYER M5 ;
        RECT  73.104 444.876 73.128 444.96 ;
    END
  END lo_d[279]
  PIN lo_d[27]
    DIRECTION INPUT ;
    USE SIGNAL ;
    PORT
      LAYER M5 ;
        RECT  12.624 444.876 12.648 444.96 ;
    END
  END lo_d[27]
  PIN lo_d[280]
    DIRECTION INPUT ;
    USE SIGNAL ;
    PORT
      LAYER M5 ;
        RECT  73.344 444.876 73.368 444.96 ;
    END
  END lo_d[280]
  PIN lo_d[281]
    DIRECTION INPUT ;
    USE SIGNAL ;
    PORT
      LAYER M5 ;
        RECT  73.584 444.876 73.608 444.96 ;
    END
  END lo_d[281]
  PIN lo_d[282]
    DIRECTION INPUT ;
    USE SIGNAL ;
    PORT
      LAYER M5 ;
        RECT  73.824 444.876 73.848 444.96 ;
    END
  END lo_d[282]
  PIN lo_d[283]
    DIRECTION INPUT ;
    USE SIGNAL ;
    PORT
      LAYER M5 ;
        RECT  74.064 444.876 74.088 444.96 ;
    END
  END lo_d[283]
  PIN lo_d[284]
    DIRECTION INPUT ;
    USE SIGNAL ;
    PORT
      LAYER M5 ;
        RECT  74.304 444.876 74.328 444.96 ;
    END
  END lo_d[284]
  PIN lo_d[285]
    DIRECTION INPUT ;
    USE SIGNAL ;
    PORT
      LAYER M5 ;
        RECT  74.544 444.876 74.568 444.96 ;
    END
  END lo_d[285]
  PIN lo_d[286]
    DIRECTION INPUT ;
    USE SIGNAL ;
    PORT
      LAYER M5 ;
        RECT  74.784 444.876 74.808 444.96 ;
    END
  END lo_d[286]
  PIN lo_d[287]
    DIRECTION INPUT ;
    USE SIGNAL ;
    PORT
      LAYER M5 ;
        RECT  75.024 444.876 75.048 444.96 ;
    END
  END lo_d[287]
  PIN lo_d[288]
    DIRECTION INPUT ;
    USE SIGNAL ;
    PORT
      LAYER M5 ;
        RECT  75.264 444.876 75.288 444.96 ;
    END
  END lo_d[288]
  PIN lo_d[289]
    DIRECTION INPUT ;
    USE SIGNAL ;
    PORT
      LAYER M5 ;
        RECT  75.504 444.876 75.528 444.96 ;
    END
  END lo_d[289]
  PIN lo_d[28]
    DIRECTION INPUT ;
    USE SIGNAL ;
    PORT
      LAYER M5 ;
        RECT  12.864 444.876 12.888 444.96 ;
    END
  END lo_d[28]
  PIN lo_d[290]
    DIRECTION INPUT ;
    USE SIGNAL ;
    PORT
      LAYER M5 ;
        RECT  75.744 444.876 75.768 444.96 ;
    END
  END lo_d[290]
  PIN lo_d[291]
    DIRECTION INPUT ;
    USE SIGNAL ;
    PORT
      LAYER M5 ;
        RECT  75.984 444.876 76.008 444.96 ;
    END
  END lo_d[291]
  PIN lo_d[292]
    DIRECTION INPUT ;
    USE SIGNAL ;
    PORT
      LAYER M5 ;
        RECT  76.224 444.876 76.248 444.96 ;
    END
  END lo_d[292]
  PIN lo_d[293]
    DIRECTION INPUT ;
    USE SIGNAL ;
    PORT
      LAYER M5 ;
        RECT  76.464 444.876 76.488 444.96 ;
    END
  END lo_d[293]
  PIN lo_d[294]
    DIRECTION INPUT ;
    USE SIGNAL ;
    PORT
      LAYER M5 ;
        RECT  76.704 444.876 76.728 444.96 ;
    END
  END lo_d[294]
  PIN lo_d[295]
    DIRECTION INPUT ;
    USE SIGNAL ;
    PORT
      LAYER M5 ;
        RECT  76.944 444.876 76.968 444.96 ;
    END
  END lo_d[295]
  PIN lo_d[296]
    DIRECTION INPUT ;
    USE SIGNAL ;
    PORT
      LAYER M5 ;
        RECT  77.184 444.876 77.208 444.96 ;
    END
  END lo_d[296]
  PIN lo_d[297]
    DIRECTION INPUT ;
    USE SIGNAL ;
    PORT
      LAYER M5 ;
        RECT  77.424 444.876 77.448 444.96 ;
    END
  END lo_d[297]
  PIN lo_d[298]
    DIRECTION INPUT ;
    USE SIGNAL ;
    PORT
      LAYER M5 ;
        RECT  77.664 444.876 77.688 444.96 ;
    END
  END lo_d[298]
  PIN lo_d[299]
    DIRECTION INPUT ;
    USE SIGNAL ;
    PORT
      LAYER M5 ;
        RECT  77.904 444.876 77.928 444.96 ;
    END
  END lo_d[299]
  PIN lo_d[29]
    DIRECTION INPUT ;
    USE SIGNAL ;
    PORT
      LAYER M5 ;
        RECT  13.104 444.876 13.128 444.96 ;
    END
  END lo_d[29]
  PIN lo_d[2]
    DIRECTION INPUT ;
    USE SIGNAL ;
    PORT
      LAYER M5 ;
        RECT  6.624 444.876 6.648 444.96 ;
    END
  END lo_d[2]
  PIN lo_d[300]
    DIRECTION INPUT ;
    USE SIGNAL ;
    PORT
      LAYER M5 ;
        RECT  78.144 444.876 78.168 444.96 ;
    END
  END lo_d[300]
  PIN lo_d[301]
    DIRECTION INPUT ;
    USE SIGNAL ;
    PORT
      LAYER M5 ;
        RECT  78.384 444.876 78.408 444.96 ;
    END
  END lo_d[301]
  PIN lo_d[302]
    DIRECTION INPUT ;
    USE SIGNAL ;
    PORT
      LAYER M5 ;
        RECT  78.624 444.876 78.648 444.96 ;
    END
  END lo_d[302]
  PIN lo_d[303]
    DIRECTION INPUT ;
    USE SIGNAL ;
    PORT
      LAYER M5 ;
        RECT  78.864 444.876 78.888 444.96 ;
    END
  END lo_d[303]
  PIN lo_d[304]
    DIRECTION INPUT ;
    USE SIGNAL ;
    PORT
      LAYER M5 ;
        RECT  79.104 444.876 79.128 444.96 ;
    END
  END lo_d[304]
  PIN lo_d[305]
    DIRECTION INPUT ;
    USE SIGNAL ;
    PORT
      LAYER M5 ;
        RECT  79.344 444.876 79.368 444.96 ;
    END
  END lo_d[305]
  PIN lo_d[306]
    DIRECTION INPUT ;
    USE SIGNAL ;
    PORT
      LAYER M5 ;
        RECT  79.584 444.876 79.608 444.96 ;
    END
  END lo_d[306]
  PIN lo_d[307]
    DIRECTION INPUT ;
    USE SIGNAL ;
    PORT
      LAYER M5 ;
        RECT  79.824 444.876 79.848 444.96 ;
    END
  END lo_d[307]
  PIN lo_d[308]
    DIRECTION INPUT ;
    USE SIGNAL ;
    PORT
      LAYER M5 ;
        RECT  80.064 444.876 80.088 444.96 ;
    END
  END lo_d[308]
  PIN lo_d[309]
    DIRECTION INPUT ;
    USE SIGNAL ;
    PORT
      LAYER M5 ;
        RECT  80.304 444.876 80.328 444.96 ;
    END
  END lo_d[309]
  PIN lo_d[30]
    DIRECTION INPUT ;
    USE SIGNAL ;
    PORT
      LAYER M5 ;
        RECT  13.344 444.876 13.368 444.96 ;
    END
  END lo_d[30]
  PIN lo_d[310]
    DIRECTION INPUT ;
    USE SIGNAL ;
    PORT
      LAYER M5 ;
        RECT  80.544 444.876 80.568 444.96 ;
    END
  END lo_d[310]
  PIN lo_d[311]
    DIRECTION INPUT ;
    USE SIGNAL ;
    PORT
      LAYER M5 ;
        RECT  80.784 444.876 80.808 444.96 ;
    END
  END lo_d[311]
  PIN lo_d[312]
    DIRECTION INPUT ;
    USE SIGNAL ;
    PORT
      LAYER M5 ;
        RECT  81.024 444.876 81.048 444.96 ;
    END
  END lo_d[312]
  PIN lo_d[313]
    DIRECTION INPUT ;
    USE SIGNAL ;
    PORT
      LAYER M5 ;
        RECT  81.264 444.876 81.288 444.96 ;
    END
  END lo_d[313]
  PIN lo_d[314]
    DIRECTION INPUT ;
    USE SIGNAL ;
    PORT
      LAYER M5 ;
        RECT  81.504 444.876 81.528 444.96 ;
    END
  END lo_d[314]
  PIN lo_d[315]
    DIRECTION INPUT ;
    USE SIGNAL ;
    PORT
      LAYER M5 ;
        RECT  81.744 444.876 81.768 444.96 ;
    END
  END lo_d[315]
  PIN lo_d[316]
    DIRECTION INPUT ;
    USE SIGNAL ;
    PORT
      LAYER M5 ;
        RECT  81.984 444.876 82.008 444.96 ;
    END
  END lo_d[316]
  PIN lo_d[317]
    DIRECTION INPUT ;
    USE SIGNAL ;
    PORT
      LAYER M5 ;
        RECT  82.224 444.876 82.248 444.96 ;
    END
  END lo_d[317]
  PIN lo_d[318]
    DIRECTION INPUT ;
    USE SIGNAL ;
    PORT
      LAYER M5 ;
        RECT  82.464 444.876 82.488 444.96 ;
    END
  END lo_d[318]
  PIN lo_d[319]
    DIRECTION INPUT ;
    USE SIGNAL ;
    PORT
      LAYER M5 ;
        RECT  82.704 444.876 82.728 444.96 ;
    END
  END lo_d[319]
  PIN lo_d[31]
    DIRECTION INPUT ;
    USE SIGNAL ;
    PORT
      LAYER M5 ;
        RECT  13.584 444.876 13.608 444.96 ;
    END
  END lo_d[31]
  PIN lo_d[320]
    DIRECTION INPUT ;
    USE SIGNAL ;
    PORT
      LAYER M5 ;
        RECT  82.944 444.876 82.968 444.96 ;
    END
  END lo_d[320]
  PIN lo_d[321]
    DIRECTION INPUT ;
    USE SIGNAL ;
    PORT
      LAYER M5 ;
        RECT  83.184 444.876 83.208 444.96 ;
    END
  END lo_d[321]
  PIN lo_d[322]
    DIRECTION INPUT ;
    USE SIGNAL ;
    PORT
      LAYER M5 ;
        RECT  83.424 444.876 83.448 444.96 ;
    END
  END lo_d[322]
  PIN lo_d[323]
    DIRECTION INPUT ;
    USE SIGNAL ;
    PORT
      LAYER M5 ;
        RECT  83.664 444.876 83.688 444.96 ;
    END
  END lo_d[323]
  PIN lo_d[324]
    DIRECTION INPUT ;
    USE SIGNAL ;
    PORT
      LAYER M5 ;
        RECT  83.904 444.876 83.928 444.96 ;
    END
  END lo_d[324]
  PIN lo_d[325]
    DIRECTION INPUT ;
    USE SIGNAL ;
    PORT
      LAYER M5 ;
        RECT  84.144 444.876 84.168 444.96 ;
    END
  END lo_d[325]
  PIN lo_d[326]
    DIRECTION INPUT ;
    USE SIGNAL ;
    PORT
      LAYER M5 ;
        RECT  84.384 444.876 84.408 444.96 ;
    END
  END lo_d[326]
  PIN lo_d[327]
    DIRECTION INPUT ;
    USE SIGNAL ;
    PORT
      LAYER M5 ;
        RECT  84.624 444.876 84.648 444.96 ;
    END
  END lo_d[327]
  PIN lo_d[328]
    DIRECTION INPUT ;
    USE SIGNAL ;
    PORT
      LAYER M5 ;
        RECT  84.864 444.876 84.888 444.96 ;
    END
  END lo_d[328]
  PIN lo_d[329]
    DIRECTION INPUT ;
    USE SIGNAL ;
    PORT
      LAYER M5 ;
        RECT  85.104 444.876 85.128 444.96 ;
    END
  END lo_d[329]
  PIN lo_d[32]
    DIRECTION INPUT ;
    USE SIGNAL ;
    PORT
      LAYER M5 ;
        RECT  13.824 444.876 13.848 444.96 ;
    END
  END lo_d[32]
  PIN lo_d[330]
    DIRECTION INPUT ;
    USE SIGNAL ;
    PORT
      LAYER M5 ;
        RECT  85.344 444.876 85.368 444.96 ;
    END
  END lo_d[330]
  PIN lo_d[331]
    DIRECTION INPUT ;
    USE SIGNAL ;
    PORT
      LAYER M5 ;
        RECT  85.584 444.876 85.608 444.96 ;
    END
  END lo_d[331]
  PIN lo_d[332]
    DIRECTION INPUT ;
    USE SIGNAL ;
    PORT
      LAYER M5 ;
        RECT  85.824 444.876 85.848 444.96 ;
    END
  END lo_d[332]
  PIN lo_d[333]
    DIRECTION INPUT ;
    USE SIGNAL ;
    PORT
      LAYER M5 ;
        RECT  86.064 444.876 86.088 444.96 ;
    END
  END lo_d[333]
  PIN lo_d[334]
    DIRECTION INPUT ;
    USE SIGNAL ;
    PORT
      LAYER M5 ;
        RECT  86.304 444.876 86.328 444.96 ;
    END
  END lo_d[334]
  PIN lo_d[335]
    DIRECTION INPUT ;
    USE SIGNAL ;
    PORT
      LAYER M5 ;
        RECT  86.544 444.876 86.568 444.96 ;
    END
  END lo_d[335]
  PIN lo_d[336]
    DIRECTION INPUT ;
    USE SIGNAL ;
    PORT
      LAYER M5 ;
        RECT  86.784 444.876 86.808 444.96 ;
    END
  END lo_d[336]
  PIN lo_d[337]
    DIRECTION INPUT ;
    USE SIGNAL ;
    PORT
      LAYER M5 ;
        RECT  87.024 444.876 87.048 444.96 ;
    END
  END lo_d[337]
  PIN lo_d[338]
    DIRECTION INPUT ;
    USE SIGNAL ;
    PORT
      LAYER M5 ;
        RECT  87.264 444.876 87.288 444.96 ;
    END
  END lo_d[338]
  PIN lo_d[339]
    DIRECTION INPUT ;
    USE SIGNAL ;
    PORT
      LAYER M5 ;
        RECT  87.504 444.876 87.528 444.96 ;
    END
  END lo_d[339]
  PIN lo_d[33]
    DIRECTION INPUT ;
    USE SIGNAL ;
    PORT
      LAYER M5 ;
        RECT  14.064 444.876 14.088 444.96 ;
    END
  END lo_d[33]
  PIN lo_d[340]
    DIRECTION INPUT ;
    USE SIGNAL ;
    PORT
      LAYER M5 ;
        RECT  87.744 444.876 87.768 444.96 ;
    END
  END lo_d[340]
  PIN lo_d[341]
    DIRECTION INPUT ;
    USE SIGNAL ;
    PORT
      LAYER M5 ;
        RECT  87.984 444.876 88.008 444.96 ;
    END
  END lo_d[341]
  PIN lo_d[342]
    DIRECTION INPUT ;
    USE SIGNAL ;
    PORT
      LAYER M5 ;
        RECT  88.224 444.876 88.248 444.96 ;
    END
  END lo_d[342]
  PIN lo_d[343]
    DIRECTION INPUT ;
    USE SIGNAL ;
    PORT
      LAYER M5 ;
        RECT  88.464 444.876 88.488 444.96 ;
    END
  END lo_d[343]
  PIN lo_d[344]
    DIRECTION INPUT ;
    USE SIGNAL ;
    PORT
      LAYER M5 ;
        RECT  88.704 444.876 88.728 444.96 ;
    END
  END lo_d[344]
  PIN lo_d[345]
    DIRECTION INPUT ;
    USE SIGNAL ;
    PORT
      LAYER M5 ;
        RECT  88.944 444.876 88.968 444.96 ;
    END
  END lo_d[345]
  PIN lo_d[346]
    DIRECTION INPUT ;
    USE SIGNAL ;
    PORT
      LAYER M5 ;
        RECT  89.184 444.876 89.208 444.96 ;
    END
  END lo_d[346]
  PIN lo_d[347]
    DIRECTION INPUT ;
    USE SIGNAL ;
    PORT
      LAYER M5 ;
        RECT  89.424 444.876 89.448 444.96 ;
    END
  END lo_d[347]
  PIN lo_d[348]
    DIRECTION INPUT ;
    USE SIGNAL ;
    PORT
      LAYER M5 ;
        RECT  89.664 444.876 89.688 444.96 ;
    END
  END lo_d[348]
  PIN lo_d[349]
    DIRECTION INPUT ;
    USE SIGNAL ;
    PORT
      LAYER M5 ;
        RECT  89.904 444.876 89.928 444.96 ;
    END
  END lo_d[349]
  PIN lo_d[34]
    DIRECTION INPUT ;
    USE SIGNAL ;
    PORT
      LAYER M5 ;
        RECT  14.304 444.876 14.328 444.96 ;
    END
  END lo_d[34]
  PIN lo_d[350]
    DIRECTION INPUT ;
    USE SIGNAL ;
    PORT
      LAYER M5 ;
        RECT  90.144 444.876 90.168 444.96 ;
    END
  END lo_d[350]
  PIN lo_d[351]
    DIRECTION INPUT ;
    USE SIGNAL ;
    PORT
      LAYER M5 ;
        RECT  90.384 444.876 90.408 444.96 ;
    END
  END lo_d[351]
  PIN lo_d[352]
    DIRECTION INPUT ;
    USE SIGNAL ;
    PORT
      LAYER M5 ;
        RECT  90.624 444.876 90.648 444.96 ;
    END
  END lo_d[352]
  PIN lo_d[353]
    DIRECTION INPUT ;
    USE SIGNAL ;
    PORT
      LAYER M5 ;
        RECT  90.864 444.876 90.888 444.96 ;
    END
  END lo_d[353]
  PIN lo_d[354]
    DIRECTION INPUT ;
    USE SIGNAL ;
    PORT
      LAYER M5 ;
        RECT  91.104 444.876 91.128 444.96 ;
    END
  END lo_d[354]
  PIN lo_d[355]
    DIRECTION INPUT ;
    USE SIGNAL ;
    PORT
      LAYER M5 ;
        RECT  91.344 444.876 91.368 444.96 ;
    END
  END lo_d[355]
  PIN lo_d[356]
    DIRECTION INPUT ;
    USE SIGNAL ;
    PORT
      LAYER M5 ;
        RECT  91.584 444.876 91.608 444.96 ;
    END
  END lo_d[356]
  PIN lo_d[357]
    DIRECTION INPUT ;
    USE SIGNAL ;
    PORT
      LAYER M5 ;
        RECT  91.824 444.876 91.848 444.96 ;
    END
  END lo_d[357]
  PIN lo_d[358]
    DIRECTION INPUT ;
    USE SIGNAL ;
    PORT
      LAYER M5 ;
        RECT  92.064 444.876 92.088 444.96 ;
    END
  END lo_d[358]
  PIN lo_d[359]
    DIRECTION INPUT ;
    USE SIGNAL ;
    PORT
      LAYER M5 ;
        RECT  92.304 444.876 92.328 444.96 ;
    END
  END lo_d[359]
  PIN lo_d[35]
    DIRECTION INPUT ;
    USE SIGNAL ;
    PORT
      LAYER M5 ;
        RECT  14.544 444.876 14.568 444.96 ;
    END
  END lo_d[35]
  PIN lo_d[360]
    DIRECTION INPUT ;
    USE SIGNAL ;
    PORT
      LAYER M5 ;
        RECT  92.544 444.876 92.568 444.96 ;
    END
  END lo_d[360]
  PIN lo_d[361]
    DIRECTION INPUT ;
    USE SIGNAL ;
    PORT
      LAYER M5 ;
        RECT  92.784 444.876 92.808 444.96 ;
    END
  END lo_d[361]
  PIN lo_d[362]
    DIRECTION INPUT ;
    USE SIGNAL ;
    PORT
      LAYER M5 ;
        RECT  93.024 444.876 93.048 444.96 ;
    END
  END lo_d[362]
  PIN lo_d[363]
    DIRECTION INPUT ;
    USE SIGNAL ;
    PORT
      LAYER M5 ;
        RECT  93.264 444.876 93.288 444.96 ;
    END
  END lo_d[363]
  PIN lo_d[364]
    DIRECTION INPUT ;
    USE SIGNAL ;
    PORT
      LAYER M5 ;
        RECT  93.504 444.876 93.528 444.96 ;
    END
  END lo_d[364]
  PIN lo_d[365]
    DIRECTION INPUT ;
    USE SIGNAL ;
    PORT
      LAYER M5 ;
        RECT  93.744 444.876 93.768 444.96 ;
    END
  END lo_d[365]
  PIN lo_d[366]
    DIRECTION INPUT ;
    USE SIGNAL ;
    PORT
      LAYER M5 ;
        RECT  93.984 444.876 94.008 444.96 ;
    END
  END lo_d[366]
  PIN lo_d[367]
    DIRECTION INPUT ;
    USE SIGNAL ;
    PORT
      LAYER M5 ;
        RECT  94.224 444.876 94.248 444.96 ;
    END
  END lo_d[367]
  PIN lo_d[368]
    DIRECTION INPUT ;
    USE SIGNAL ;
    PORT
      LAYER M5 ;
        RECT  94.464 444.876 94.488 444.96 ;
    END
  END lo_d[368]
  PIN lo_d[369]
    DIRECTION INPUT ;
    USE SIGNAL ;
    PORT
      LAYER M5 ;
        RECT  94.704 444.876 94.728 444.96 ;
    END
  END lo_d[369]
  PIN lo_d[36]
    DIRECTION INPUT ;
    USE SIGNAL ;
    PORT
      LAYER M5 ;
        RECT  14.784 444.876 14.808 444.96 ;
    END
  END lo_d[36]
  PIN lo_d[370]
    DIRECTION INPUT ;
    USE SIGNAL ;
    PORT
      LAYER M5 ;
        RECT  94.944 444.876 94.968 444.96 ;
    END
  END lo_d[370]
  PIN lo_d[371]
    DIRECTION INPUT ;
    USE SIGNAL ;
    PORT
      LAYER M5 ;
        RECT  95.184 444.876 95.208 444.96 ;
    END
  END lo_d[371]
  PIN lo_d[372]
    DIRECTION INPUT ;
    USE SIGNAL ;
    PORT
      LAYER M5 ;
        RECT  95.424 444.876 95.448 444.96 ;
    END
  END lo_d[372]
  PIN lo_d[373]
    DIRECTION INPUT ;
    USE SIGNAL ;
    PORT
      LAYER M5 ;
        RECT  95.664 444.876 95.688 444.96 ;
    END
  END lo_d[373]
  PIN lo_d[374]
    DIRECTION INPUT ;
    USE SIGNAL ;
    PORT
      LAYER M5 ;
        RECT  95.904 444.876 95.928 444.96 ;
    END
  END lo_d[374]
  PIN lo_d[375]
    DIRECTION INPUT ;
    USE SIGNAL ;
    PORT
      LAYER M5 ;
        RECT  96.144 444.876 96.168 444.96 ;
    END
  END lo_d[375]
  PIN lo_d[376]
    DIRECTION INPUT ;
    USE SIGNAL ;
    PORT
      LAYER M5 ;
        RECT  96.384 444.876 96.408 444.96 ;
    END
  END lo_d[376]
  PIN lo_d[377]
    DIRECTION INPUT ;
    USE SIGNAL ;
    PORT
      LAYER M5 ;
        RECT  96.624 444.876 96.648 444.96 ;
    END
  END lo_d[377]
  PIN lo_d[378]
    DIRECTION INPUT ;
    USE SIGNAL ;
    PORT
      LAYER M5 ;
        RECT  96.864 444.876 96.888 444.96 ;
    END
  END lo_d[378]
  PIN lo_d[379]
    DIRECTION INPUT ;
    USE SIGNAL ;
    PORT
      LAYER M5 ;
        RECT  97.104 444.876 97.128 444.96 ;
    END
  END lo_d[379]
  PIN lo_d[37]
    DIRECTION INPUT ;
    USE SIGNAL ;
    PORT
      LAYER M5 ;
        RECT  15.024 444.876 15.048 444.96 ;
    END
  END lo_d[37]
  PIN lo_d[380]
    DIRECTION INPUT ;
    USE SIGNAL ;
    PORT
      LAYER M5 ;
        RECT  97.344 444.876 97.368 444.96 ;
    END
  END lo_d[380]
  PIN lo_d[381]
    DIRECTION INPUT ;
    USE SIGNAL ;
    PORT
      LAYER M5 ;
        RECT  97.584 444.876 97.608 444.96 ;
    END
  END lo_d[381]
  PIN lo_d[382]
    DIRECTION INPUT ;
    USE SIGNAL ;
    PORT
      LAYER M5 ;
        RECT  97.824 444.876 97.848 444.96 ;
    END
  END lo_d[382]
  PIN lo_d[383]
    DIRECTION INPUT ;
    USE SIGNAL ;
    PORT
      LAYER M5 ;
        RECT  98.064 444.876 98.088 444.96 ;
    END
  END lo_d[383]
  PIN lo_d[384]
    DIRECTION INPUT ;
    USE SIGNAL ;
    PORT
      LAYER M5 ;
        RECT  98.304 444.876 98.328 444.96 ;
    END
  END lo_d[384]
  PIN lo_d[385]
    DIRECTION INPUT ;
    USE SIGNAL ;
    PORT
      LAYER M5 ;
        RECT  98.544 444.876 98.568 444.96 ;
    END
  END lo_d[385]
  PIN lo_d[386]
    DIRECTION INPUT ;
    USE SIGNAL ;
    PORT
      LAYER M5 ;
        RECT  98.784 444.876 98.808 444.96 ;
    END
  END lo_d[386]
  PIN lo_d[387]
    DIRECTION INPUT ;
    USE SIGNAL ;
    PORT
      LAYER M5 ;
        RECT  99.024 444.876 99.048 444.96 ;
    END
  END lo_d[387]
  PIN lo_d[388]
    DIRECTION INPUT ;
    USE SIGNAL ;
    PORT
      LAYER M5 ;
        RECT  99.264 444.876 99.288 444.96 ;
    END
  END lo_d[388]
  PIN lo_d[389]
    DIRECTION INPUT ;
    USE SIGNAL ;
    PORT
      LAYER M5 ;
        RECT  99.504 444.876 99.528 444.96 ;
    END
  END lo_d[389]
  PIN lo_d[38]
    DIRECTION INPUT ;
    USE SIGNAL ;
    PORT
      LAYER M5 ;
        RECT  15.264 444.876 15.288 444.96 ;
    END
  END lo_d[38]
  PIN lo_d[390]
    DIRECTION INPUT ;
    USE SIGNAL ;
    PORT
      LAYER M5 ;
        RECT  99.744 444.876 99.768 444.96 ;
    END
  END lo_d[390]
  PIN lo_d[391]
    DIRECTION INPUT ;
    USE SIGNAL ;
    PORT
      LAYER M5 ;
        RECT  99.984 444.876 100.008 444.96 ;
    END
  END lo_d[391]
  PIN lo_d[392]
    DIRECTION INPUT ;
    USE SIGNAL ;
    PORT
      LAYER M5 ;
        RECT  100.224 444.876 100.248 444.96 ;
    END
  END lo_d[392]
  PIN lo_d[393]
    DIRECTION INPUT ;
    USE SIGNAL ;
    PORT
      LAYER M5 ;
        RECT  100.464 444.876 100.488 444.96 ;
    END
  END lo_d[393]
  PIN lo_d[394]
    DIRECTION INPUT ;
    USE SIGNAL ;
    PORT
      LAYER M5 ;
        RECT  100.704 444.876 100.728 444.96 ;
    END
  END lo_d[394]
  PIN lo_d[395]
    DIRECTION INPUT ;
    USE SIGNAL ;
    PORT
      LAYER M5 ;
        RECT  100.944 444.876 100.968 444.96 ;
    END
  END lo_d[395]
  PIN lo_d[396]
    DIRECTION INPUT ;
    USE SIGNAL ;
    PORT
      LAYER M5 ;
        RECT  101.184 444.876 101.208 444.96 ;
    END
  END lo_d[396]
  PIN lo_d[397]
    DIRECTION INPUT ;
    USE SIGNAL ;
    PORT
      LAYER M5 ;
        RECT  101.424 444.876 101.448 444.96 ;
    END
  END lo_d[397]
  PIN lo_d[398]
    DIRECTION INPUT ;
    USE SIGNAL ;
    PORT
      LAYER M5 ;
        RECT  101.664 444.876 101.688 444.96 ;
    END
  END lo_d[398]
  PIN lo_d[399]
    DIRECTION INPUT ;
    USE SIGNAL ;
    PORT
      LAYER M5 ;
        RECT  101.904 444.876 101.928 444.96 ;
    END
  END lo_d[399]
  PIN lo_d[39]
    DIRECTION INPUT ;
    USE SIGNAL ;
    PORT
      LAYER M5 ;
        RECT  15.504 444.876 15.528 444.96 ;
    END
  END lo_d[39]
  PIN lo_d[3]
    DIRECTION INPUT ;
    USE SIGNAL ;
    PORT
      LAYER M5 ;
        RECT  6.864 444.876 6.888 444.96 ;
    END
  END lo_d[3]
  PIN lo_d[400]
    DIRECTION INPUT ;
    USE SIGNAL ;
    PORT
      LAYER M5 ;
        RECT  102.144 444.876 102.168 444.96 ;
    END
  END lo_d[400]
  PIN lo_d[401]
    DIRECTION INPUT ;
    USE SIGNAL ;
    PORT
      LAYER M5 ;
        RECT  102.384 444.876 102.408 444.96 ;
    END
  END lo_d[401]
  PIN lo_d[402]
    DIRECTION INPUT ;
    USE SIGNAL ;
    PORT
      LAYER M5 ;
        RECT  102.624 444.876 102.648 444.96 ;
    END
  END lo_d[402]
  PIN lo_d[403]
    DIRECTION INPUT ;
    USE SIGNAL ;
    PORT
      LAYER M5 ;
        RECT  102.864 444.876 102.888 444.96 ;
    END
  END lo_d[403]
  PIN lo_d[404]
    DIRECTION INPUT ;
    USE SIGNAL ;
    PORT
      LAYER M5 ;
        RECT  103.104 444.876 103.128 444.96 ;
    END
  END lo_d[404]
  PIN lo_d[405]
    DIRECTION INPUT ;
    USE SIGNAL ;
    PORT
      LAYER M5 ;
        RECT  103.344 444.876 103.368 444.96 ;
    END
  END lo_d[405]
  PIN lo_d[406]
    DIRECTION INPUT ;
    USE SIGNAL ;
    PORT
      LAYER M5 ;
        RECT  103.584 444.876 103.608 444.96 ;
    END
  END lo_d[406]
  PIN lo_d[407]
    DIRECTION INPUT ;
    USE SIGNAL ;
    PORT
      LAYER M5 ;
        RECT  103.824 444.876 103.848 444.96 ;
    END
  END lo_d[407]
  PIN lo_d[408]
    DIRECTION INPUT ;
    USE SIGNAL ;
    PORT
      LAYER M5 ;
        RECT  104.064 444.876 104.088 444.96 ;
    END
  END lo_d[408]
  PIN lo_d[409]
    DIRECTION INPUT ;
    USE SIGNAL ;
    PORT
      LAYER M5 ;
        RECT  104.304 444.876 104.328 444.96 ;
    END
  END lo_d[409]
  PIN lo_d[40]
    DIRECTION INPUT ;
    USE SIGNAL ;
    PORT
      LAYER M5 ;
        RECT  15.744 444.876 15.768 444.96 ;
    END
  END lo_d[40]
  PIN lo_d[410]
    DIRECTION INPUT ;
    USE SIGNAL ;
    PORT
      LAYER M5 ;
        RECT  104.544 444.876 104.568 444.96 ;
    END
  END lo_d[410]
  PIN lo_d[411]
    DIRECTION INPUT ;
    USE SIGNAL ;
    PORT
      LAYER M5 ;
        RECT  104.784 444.876 104.808 444.96 ;
    END
  END lo_d[411]
  PIN lo_d[412]
    DIRECTION INPUT ;
    USE SIGNAL ;
    PORT
      LAYER M5 ;
        RECT  105.024 444.876 105.048 444.96 ;
    END
  END lo_d[412]
  PIN lo_d[413]
    DIRECTION INPUT ;
    USE SIGNAL ;
    PORT
      LAYER M5 ;
        RECT  105.264 444.876 105.288 444.96 ;
    END
  END lo_d[413]
  PIN lo_d[414]
    DIRECTION INPUT ;
    USE SIGNAL ;
    PORT
      LAYER M5 ;
        RECT  105.504 444.876 105.528 444.96 ;
    END
  END lo_d[414]
  PIN lo_d[415]
    DIRECTION INPUT ;
    USE SIGNAL ;
    PORT
      LAYER M5 ;
        RECT  105.744 444.876 105.768 444.96 ;
    END
  END lo_d[415]
  PIN lo_d[416]
    DIRECTION INPUT ;
    USE SIGNAL ;
    PORT
      LAYER M5 ;
        RECT  105.984 444.876 106.008 444.96 ;
    END
  END lo_d[416]
  PIN lo_d[417]
    DIRECTION INPUT ;
    USE SIGNAL ;
    PORT
      LAYER M5 ;
        RECT  106.224 444.876 106.248 444.96 ;
    END
  END lo_d[417]
  PIN lo_d[418]
    DIRECTION INPUT ;
    USE SIGNAL ;
    PORT
      LAYER M5 ;
        RECT  106.464 444.876 106.488 444.96 ;
    END
  END lo_d[418]
  PIN lo_d[419]
    DIRECTION INPUT ;
    USE SIGNAL ;
    PORT
      LAYER M5 ;
        RECT  106.704 444.876 106.728 444.96 ;
    END
  END lo_d[419]
  PIN lo_d[41]
    DIRECTION INPUT ;
    USE SIGNAL ;
    PORT
      LAYER M5 ;
        RECT  15.984 444.876 16.008 444.96 ;
    END
  END lo_d[41]
  PIN lo_d[420]
    DIRECTION INPUT ;
    USE SIGNAL ;
    PORT
      LAYER M5 ;
        RECT  106.944 444.876 106.968 444.96 ;
    END
  END lo_d[420]
  PIN lo_d[421]
    DIRECTION INPUT ;
    USE SIGNAL ;
    PORT
      LAYER M5 ;
        RECT  107.184 444.876 107.208 444.96 ;
    END
  END lo_d[421]
  PIN lo_d[422]
    DIRECTION INPUT ;
    USE SIGNAL ;
    PORT
      LAYER M5 ;
        RECT  107.424 444.876 107.448 444.96 ;
    END
  END lo_d[422]
  PIN lo_d[423]
    DIRECTION INPUT ;
    USE SIGNAL ;
    PORT
      LAYER M5 ;
        RECT  107.664 444.876 107.688 444.96 ;
    END
  END lo_d[423]
  PIN lo_d[424]
    DIRECTION INPUT ;
    USE SIGNAL ;
    PORT
      LAYER M5 ;
        RECT  107.904 444.876 107.928 444.96 ;
    END
  END lo_d[424]
  PIN lo_d[425]
    DIRECTION INPUT ;
    USE SIGNAL ;
    PORT
      LAYER M5 ;
        RECT  108.144 444.876 108.168 444.96 ;
    END
  END lo_d[425]
  PIN lo_d[426]
    DIRECTION INPUT ;
    USE SIGNAL ;
    PORT
      LAYER M5 ;
        RECT  108.384 444.876 108.408 444.96 ;
    END
  END lo_d[426]
  PIN lo_d[427]
    DIRECTION INPUT ;
    USE SIGNAL ;
    PORT
      LAYER M5 ;
        RECT  108.624 444.876 108.648 444.96 ;
    END
  END lo_d[427]
  PIN lo_d[428]
    DIRECTION INPUT ;
    USE SIGNAL ;
    PORT
      LAYER M5 ;
        RECT  108.864 444.876 108.888 444.96 ;
    END
  END lo_d[428]
  PIN lo_d[429]
    DIRECTION INPUT ;
    USE SIGNAL ;
    PORT
      LAYER M5 ;
        RECT  109.104 444.876 109.128 444.96 ;
    END
  END lo_d[429]
  PIN lo_d[42]
    DIRECTION INPUT ;
    USE SIGNAL ;
    PORT
      LAYER M5 ;
        RECT  16.224 444.876 16.248 444.96 ;
    END
  END lo_d[42]
  PIN lo_d[430]
    DIRECTION INPUT ;
    USE SIGNAL ;
    PORT
      LAYER M5 ;
        RECT  109.344 444.876 109.368 444.96 ;
    END
  END lo_d[430]
  PIN lo_d[431]
    DIRECTION INPUT ;
    USE SIGNAL ;
    PORT
      LAYER M5 ;
        RECT  109.584 444.876 109.608 444.96 ;
    END
  END lo_d[431]
  PIN lo_d[432]
    DIRECTION INPUT ;
    USE SIGNAL ;
    PORT
      LAYER M5 ;
        RECT  109.824 444.876 109.848 444.96 ;
    END
  END lo_d[432]
  PIN lo_d[433]
    DIRECTION INPUT ;
    USE SIGNAL ;
    PORT
      LAYER M5 ;
        RECT  110.064 444.876 110.088 444.96 ;
    END
  END lo_d[433]
  PIN lo_d[434]
    DIRECTION INPUT ;
    USE SIGNAL ;
    PORT
      LAYER M5 ;
        RECT  110.304 444.876 110.328 444.96 ;
    END
  END lo_d[434]
  PIN lo_d[435]
    DIRECTION INPUT ;
    USE SIGNAL ;
    PORT
      LAYER M5 ;
        RECT  110.544 444.876 110.568 444.96 ;
    END
  END lo_d[435]
  PIN lo_d[436]
    DIRECTION INPUT ;
    USE SIGNAL ;
    PORT
      LAYER M5 ;
        RECT  110.784 444.876 110.808 444.96 ;
    END
  END lo_d[436]
  PIN lo_d[437]
    DIRECTION INPUT ;
    USE SIGNAL ;
    PORT
      LAYER M5 ;
        RECT  111.024 444.876 111.048 444.96 ;
    END
  END lo_d[437]
  PIN lo_d[438]
    DIRECTION INPUT ;
    USE SIGNAL ;
    PORT
      LAYER M5 ;
        RECT  111.264 444.876 111.288 444.96 ;
    END
  END lo_d[438]
  PIN lo_d[439]
    DIRECTION INPUT ;
    USE SIGNAL ;
    PORT
      LAYER M5 ;
        RECT  111.504 444.876 111.528 444.96 ;
    END
  END lo_d[439]
  PIN lo_d[43]
    DIRECTION INPUT ;
    USE SIGNAL ;
    PORT
      LAYER M5 ;
        RECT  16.464 444.876 16.488 444.96 ;
    END
  END lo_d[43]
  PIN lo_d[440]
    DIRECTION INPUT ;
    USE SIGNAL ;
    PORT
      LAYER M5 ;
        RECT  111.744 444.876 111.768 444.96 ;
    END
  END lo_d[440]
  PIN lo_d[441]
    DIRECTION INPUT ;
    USE SIGNAL ;
    PORT
      LAYER M5 ;
        RECT  111.984 444.876 112.008 444.96 ;
    END
  END lo_d[441]
  PIN lo_d[442]
    DIRECTION INPUT ;
    USE SIGNAL ;
    PORT
      LAYER M5 ;
        RECT  112.224 444.876 112.248 444.96 ;
    END
  END lo_d[442]
  PIN lo_d[443]
    DIRECTION INPUT ;
    USE SIGNAL ;
    PORT
      LAYER M5 ;
        RECT  112.464 444.876 112.488 444.96 ;
    END
  END lo_d[443]
  PIN lo_d[444]
    DIRECTION INPUT ;
    USE SIGNAL ;
    PORT
      LAYER M5 ;
        RECT  112.704 444.876 112.728 444.96 ;
    END
  END lo_d[444]
  PIN lo_d[445]
    DIRECTION INPUT ;
    USE SIGNAL ;
    PORT
      LAYER M5 ;
        RECT  112.944 444.876 112.968 444.96 ;
    END
  END lo_d[445]
  PIN lo_d[446]
    DIRECTION INPUT ;
    USE SIGNAL ;
    PORT
      LAYER M5 ;
        RECT  113.184 444.876 113.208 444.96 ;
    END
  END lo_d[446]
  PIN lo_d[447]
    DIRECTION INPUT ;
    USE SIGNAL ;
    PORT
      LAYER M5 ;
        RECT  113.424 444.876 113.448 444.96 ;
    END
  END lo_d[447]
  PIN lo_d[448]
    DIRECTION INPUT ;
    USE SIGNAL ;
    PORT
      LAYER M5 ;
        RECT  113.664 444.876 113.688 444.96 ;
    END
  END lo_d[448]
  PIN lo_d[449]
    DIRECTION INPUT ;
    USE SIGNAL ;
    PORT
      LAYER M5 ;
        RECT  113.904 444.876 113.928 444.96 ;
    END
  END lo_d[449]
  PIN lo_d[44]
    DIRECTION INPUT ;
    USE SIGNAL ;
    PORT
      LAYER M5 ;
        RECT  16.704 444.876 16.728 444.96 ;
    END
  END lo_d[44]
  PIN lo_d[450]
    DIRECTION INPUT ;
    USE SIGNAL ;
    PORT
      LAYER M5 ;
        RECT  114.144 444.876 114.168 444.96 ;
    END
  END lo_d[450]
  PIN lo_d[451]
    DIRECTION INPUT ;
    USE SIGNAL ;
    PORT
      LAYER M5 ;
        RECT  114.384 444.876 114.408 444.96 ;
    END
  END lo_d[451]
  PIN lo_d[452]
    DIRECTION INPUT ;
    USE SIGNAL ;
    PORT
      LAYER M5 ;
        RECT  114.624 444.876 114.648 444.96 ;
    END
  END lo_d[452]
  PIN lo_d[453]
    DIRECTION INPUT ;
    USE SIGNAL ;
    PORT
      LAYER M5 ;
        RECT  114.864 444.876 114.888 444.96 ;
    END
  END lo_d[453]
  PIN lo_d[454]
    DIRECTION INPUT ;
    USE SIGNAL ;
    PORT
      LAYER M5 ;
        RECT  115.104 444.876 115.128 444.96 ;
    END
  END lo_d[454]
  PIN lo_d[455]
    DIRECTION INPUT ;
    USE SIGNAL ;
    PORT
      LAYER M5 ;
        RECT  115.344 444.876 115.368 444.96 ;
    END
  END lo_d[455]
  PIN lo_d[456]
    DIRECTION INPUT ;
    USE SIGNAL ;
    PORT
      LAYER M5 ;
        RECT  115.584 444.876 115.608 444.96 ;
    END
  END lo_d[456]
  PIN lo_d[457]
    DIRECTION INPUT ;
    USE SIGNAL ;
    PORT
      LAYER M5 ;
        RECT  115.824 444.876 115.848 444.96 ;
    END
  END lo_d[457]
  PIN lo_d[458]
    DIRECTION INPUT ;
    USE SIGNAL ;
    PORT
      LAYER M5 ;
        RECT  116.064 444.876 116.088 444.96 ;
    END
  END lo_d[458]
  PIN lo_d[459]
    DIRECTION INPUT ;
    USE SIGNAL ;
    PORT
      LAYER M5 ;
        RECT  116.304 444.876 116.328 444.96 ;
    END
  END lo_d[459]
  PIN lo_d[45]
    DIRECTION INPUT ;
    USE SIGNAL ;
    PORT
      LAYER M5 ;
        RECT  16.944 444.876 16.968 444.96 ;
    END
  END lo_d[45]
  PIN lo_d[460]
    DIRECTION INPUT ;
    USE SIGNAL ;
    PORT
      LAYER M5 ;
        RECT  116.544 444.876 116.568 444.96 ;
    END
  END lo_d[460]
  PIN lo_d[461]
    DIRECTION INPUT ;
    USE SIGNAL ;
    PORT
      LAYER M5 ;
        RECT  116.784 444.876 116.808 444.96 ;
    END
  END lo_d[461]
  PIN lo_d[462]
    DIRECTION INPUT ;
    USE SIGNAL ;
    PORT
      LAYER M5 ;
        RECT  117.024 444.876 117.048 444.96 ;
    END
  END lo_d[462]
  PIN lo_d[463]
    DIRECTION INPUT ;
    USE SIGNAL ;
    PORT
      LAYER M5 ;
        RECT  117.264 444.876 117.288 444.96 ;
    END
  END lo_d[463]
  PIN lo_d[464]
    DIRECTION INPUT ;
    USE SIGNAL ;
    PORT
      LAYER M5 ;
        RECT  117.504 444.876 117.528 444.96 ;
    END
  END lo_d[464]
  PIN lo_d[465]
    DIRECTION INPUT ;
    USE SIGNAL ;
    PORT
      LAYER M5 ;
        RECT  117.744 444.876 117.768 444.96 ;
    END
  END lo_d[465]
  PIN lo_d[466]
    DIRECTION INPUT ;
    USE SIGNAL ;
    PORT
      LAYER M5 ;
        RECT  117.984 444.876 118.008 444.96 ;
    END
  END lo_d[466]
  PIN lo_d[467]
    DIRECTION INPUT ;
    USE SIGNAL ;
    PORT
      LAYER M5 ;
        RECT  118.224 444.876 118.248 444.96 ;
    END
  END lo_d[467]
  PIN lo_d[468]
    DIRECTION INPUT ;
    USE SIGNAL ;
    PORT
      LAYER M5 ;
        RECT  118.464 444.876 118.488 444.96 ;
    END
  END lo_d[468]
  PIN lo_d[469]
    DIRECTION INPUT ;
    USE SIGNAL ;
    PORT
      LAYER M5 ;
        RECT  118.704 444.876 118.728 444.96 ;
    END
  END lo_d[469]
  PIN lo_d[46]
    DIRECTION INPUT ;
    USE SIGNAL ;
    PORT
      LAYER M5 ;
        RECT  17.184 444.876 17.208 444.96 ;
    END
  END lo_d[46]
  PIN lo_d[470]
    DIRECTION INPUT ;
    USE SIGNAL ;
    PORT
      LAYER M5 ;
        RECT  118.944 444.876 118.968 444.96 ;
    END
  END lo_d[470]
  PIN lo_d[471]
    DIRECTION INPUT ;
    USE SIGNAL ;
    PORT
      LAYER M5 ;
        RECT  119.184 444.876 119.208 444.96 ;
    END
  END lo_d[471]
  PIN lo_d[472]
    DIRECTION INPUT ;
    USE SIGNAL ;
    PORT
      LAYER M5 ;
        RECT  119.424 444.876 119.448 444.96 ;
    END
  END lo_d[472]
  PIN lo_d[473]
    DIRECTION INPUT ;
    USE SIGNAL ;
    PORT
      LAYER M5 ;
        RECT  119.664 444.876 119.688 444.96 ;
    END
  END lo_d[473]
  PIN lo_d[474]
    DIRECTION INPUT ;
    USE SIGNAL ;
    PORT
      LAYER M5 ;
        RECT  119.904 444.876 119.928 444.96 ;
    END
  END lo_d[474]
  PIN lo_d[475]
    DIRECTION INPUT ;
    USE SIGNAL ;
    PORT
      LAYER M5 ;
        RECT  120.144 444.876 120.168 444.96 ;
    END
  END lo_d[475]
  PIN lo_d[476]
    DIRECTION INPUT ;
    USE SIGNAL ;
    PORT
      LAYER M5 ;
        RECT  120.384 444.876 120.408 444.96 ;
    END
  END lo_d[476]
  PIN lo_d[477]
    DIRECTION INPUT ;
    USE SIGNAL ;
    PORT
      LAYER M5 ;
        RECT  120.624 444.876 120.648 444.96 ;
    END
  END lo_d[477]
  PIN lo_d[478]
    DIRECTION INPUT ;
    USE SIGNAL ;
    PORT
      LAYER M5 ;
        RECT  120.864 444.876 120.888 444.96 ;
    END
  END lo_d[478]
  PIN lo_d[479]
    DIRECTION INPUT ;
    USE SIGNAL ;
    PORT
      LAYER M5 ;
        RECT  121.104 444.876 121.128 444.96 ;
    END
  END lo_d[479]
  PIN lo_d[47]
    DIRECTION INPUT ;
    USE SIGNAL ;
    PORT
      LAYER M5 ;
        RECT  17.424 444.876 17.448 444.96 ;
    END
  END lo_d[47]
  PIN lo_d[480]
    DIRECTION INPUT ;
    USE SIGNAL ;
    PORT
      LAYER M5 ;
        RECT  121.344 444.876 121.368 444.96 ;
    END
  END lo_d[480]
  PIN lo_d[481]
    DIRECTION INPUT ;
    USE SIGNAL ;
    PORT
      LAYER M5 ;
        RECT  121.584 444.876 121.608 444.96 ;
    END
  END lo_d[481]
  PIN lo_d[482]
    DIRECTION INPUT ;
    USE SIGNAL ;
    PORT
      LAYER M5 ;
        RECT  121.824 444.876 121.848 444.96 ;
    END
  END lo_d[482]
  PIN lo_d[483]
    DIRECTION INPUT ;
    USE SIGNAL ;
    PORT
      LAYER M5 ;
        RECT  122.064 444.876 122.088 444.96 ;
    END
  END lo_d[483]
  PIN lo_d[484]
    DIRECTION INPUT ;
    USE SIGNAL ;
    PORT
      LAYER M5 ;
        RECT  122.304 444.876 122.328 444.96 ;
    END
  END lo_d[484]
  PIN lo_d[485]
    DIRECTION INPUT ;
    USE SIGNAL ;
    PORT
      LAYER M5 ;
        RECT  122.544 444.876 122.568 444.96 ;
    END
  END lo_d[485]
  PIN lo_d[486]
    DIRECTION INPUT ;
    USE SIGNAL ;
    PORT
      LAYER M5 ;
        RECT  122.784 444.876 122.808 444.96 ;
    END
  END lo_d[486]
  PIN lo_d[487]
    DIRECTION INPUT ;
    USE SIGNAL ;
    PORT
      LAYER M5 ;
        RECT  123.024 444.876 123.048 444.96 ;
    END
  END lo_d[487]
  PIN lo_d[488]
    DIRECTION INPUT ;
    USE SIGNAL ;
    PORT
      LAYER M5 ;
        RECT  123.264 444.876 123.288 444.96 ;
    END
  END lo_d[488]
  PIN lo_d[489]
    DIRECTION INPUT ;
    USE SIGNAL ;
    PORT
      LAYER M5 ;
        RECT  123.504 444.876 123.528 444.96 ;
    END
  END lo_d[489]
  PIN lo_d[48]
    DIRECTION INPUT ;
    USE SIGNAL ;
    PORT
      LAYER M5 ;
        RECT  17.664 444.876 17.688 444.96 ;
    END
  END lo_d[48]
  PIN lo_d[490]
    DIRECTION INPUT ;
    USE SIGNAL ;
    PORT
      LAYER M5 ;
        RECT  123.744 444.876 123.768 444.96 ;
    END
  END lo_d[490]
  PIN lo_d[491]
    DIRECTION INPUT ;
    USE SIGNAL ;
    PORT
      LAYER M5 ;
        RECT  123.984 444.876 124.008 444.96 ;
    END
  END lo_d[491]
  PIN lo_d[492]
    DIRECTION INPUT ;
    USE SIGNAL ;
    PORT
      LAYER M5 ;
        RECT  124.224 444.876 124.248 444.96 ;
    END
  END lo_d[492]
  PIN lo_d[493]
    DIRECTION INPUT ;
    USE SIGNAL ;
    PORT
      LAYER M5 ;
        RECT  124.464 444.876 124.488 444.96 ;
    END
  END lo_d[493]
  PIN lo_d[494]
    DIRECTION INPUT ;
    USE SIGNAL ;
    PORT
      LAYER M5 ;
        RECT  124.704 444.876 124.728 444.96 ;
    END
  END lo_d[494]
  PIN lo_d[495]
    DIRECTION INPUT ;
    USE SIGNAL ;
    PORT
      LAYER M5 ;
        RECT  124.944 444.876 124.968 444.96 ;
    END
  END lo_d[495]
  PIN lo_d[496]
    DIRECTION INPUT ;
    USE SIGNAL ;
    PORT
      LAYER M5 ;
        RECT  125.184 444.876 125.208 444.96 ;
    END
  END lo_d[496]
  PIN lo_d[497]
    DIRECTION INPUT ;
    USE SIGNAL ;
    PORT
      LAYER M5 ;
        RECT  125.424 444.876 125.448 444.96 ;
    END
  END lo_d[497]
  PIN lo_d[498]
    DIRECTION INPUT ;
    USE SIGNAL ;
    PORT
      LAYER M5 ;
        RECT  125.664 444.876 125.688 444.96 ;
    END
  END lo_d[498]
  PIN lo_d[499]
    DIRECTION INPUT ;
    USE SIGNAL ;
    PORT
      LAYER M5 ;
        RECT  125.904 444.876 125.928 444.96 ;
    END
  END lo_d[499]
  PIN lo_d[49]
    DIRECTION INPUT ;
    USE SIGNAL ;
    PORT
      LAYER M5 ;
        RECT  17.904 444.876 17.928 444.96 ;
    END
  END lo_d[49]
  PIN lo_d[4]
    DIRECTION INPUT ;
    USE SIGNAL ;
    PORT
      LAYER M5 ;
        RECT  7.104 444.876 7.128 444.96 ;
    END
  END lo_d[4]
  PIN lo_d[500]
    DIRECTION INPUT ;
    USE SIGNAL ;
    PORT
      LAYER M5 ;
        RECT  126.144 444.876 126.168 444.96 ;
    END
  END lo_d[500]
  PIN lo_d[501]
    DIRECTION INPUT ;
    USE SIGNAL ;
    PORT
      LAYER M5 ;
        RECT  126.384 444.876 126.408 444.96 ;
    END
  END lo_d[501]
  PIN lo_d[502]
    DIRECTION INPUT ;
    USE SIGNAL ;
    PORT
      LAYER M5 ;
        RECT  126.624 444.876 126.648 444.96 ;
    END
  END lo_d[502]
  PIN lo_d[503]
    DIRECTION INPUT ;
    USE SIGNAL ;
    PORT
      LAYER M5 ;
        RECT  126.864 444.876 126.888 444.96 ;
    END
  END lo_d[503]
  PIN lo_d[504]
    DIRECTION INPUT ;
    USE SIGNAL ;
    PORT
      LAYER M5 ;
        RECT  127.104 444.876 127.128 444.96 ;
    END
  END lo_d[504]
  PIN lo_d[505]
    DIRECTION INPUT ;
    USE SIGNAL ;
    PORT
      LAYER M5 ;
        RECT  127.344 444.876 127.368 444.96 ;
    END
  END lo_d[505]
  PIN lo_d[506]
    DIRECTION INPUT ;
    USE SIGNAL ;
    PORT
      LAYER M5 ;
        RECT  127.584 444.876 127.608 444.96 ;
    END
  END lo_d[506]
  PIN lo_d[507]
    DIRECTION INPUT ;
    USE SIGNAL ;
    PORT
      LAYER M5 ;
        RECT  127.824 444.876 127.848 444.96 ;
    END
  END lo_d[507]
  PIN lo_d[508]
    DIRECTION INPUT ;
    USE SIGNAL ;
    PORT
      LAYER M5 ;
        RECT  128.064 444.876 128.088 444.96 ;
    END
  END lo_d[508]
  PIN lo_d[509]
    DIRECTION INPUT ;
    USE SIGNAL ;
    PORT
      LAYER M5 ;
        RECT  128.304 444.876 128.328 444.96 ;
    END
  END lo_d[509]
  PIN lo_d[50]
    DIRECTION INPUT ;
    USE SIGNAL ;
    PORT
      LAYER M5 ;
        RECT  18.144 444.876 18.168 444.96 ;
    END
  END lo_d[50]
  PIN lo_d[510]
    DIRECTION INPUT ;
    USE SIGNAL ;
    PORT
      LAYER M5 ;
        RECT  128.544 444.876 128.568 444.96 ;
    END
  END lo_d[510]
  PIN lo_d[511]
    DIRECTION INPUT ;
    USE SIGNAL ;
    PORT
      LAYER M5 ;
        RECT  128.784 444.876 128.808 444.96 ;
    END
  END lo_d[511]
  PIN lo_d[512]
    DIRECTION INPUT ;
    USE SIGNAL ;
    PORT
      LAYER M5 ;
        RECT  129.024 444.876 129.048 444.96 ;
    END
  END lo_d[512]
  PIN lo_d[513]
    DIRECTION INPUT ;
    USE SIGNAL ;
    PORT
      LAYER M5 ;
        RECT  129.264 444.876 129.288 444.96 ;
    END
  END lo_d[513]
  PIN lo_d[514]
    DIRECTION INPUT ;
    USE SIGNAL ;
    PORT
      LAYER M5 ;
        RECT  129.504 444.876 129.528 444.96 ;
    END
  END lo_d[514]
  PIN lo_d[515]
    DIRECTION INPUT ;
    USE SIGNAL ;
    PORT
      LAYER M5 ;
        RECT  129.744 444.876 129.768 444.96 ;
    END
  END lo_d[515]
  PIN lo_d[516]
    DIRECTION INPUT ;
    USE SIGNAL ;
    PORT
      LAYER M5 ;
        RECT  129.984 444.876 130.008 444.96 ;
    END
  END lo_d[516]
  PIN lo_d[517]
    DIRECTION INPUT ;
    USE SIGNAL ;
    PORT
      LAYER M5 ;
        RECT  130.224 444.876 130.248 444.96 ;
    END
  END lo_d[517]
  PIN lo_d[518]
    DIRECTION INPUT ;
    USE SIGNAL ;
    PORT
      LAYER M5 ;
        RECT  130.464 444.876 130.488 444.96 ;
    END
  END lo_d[518]
  PIN lo_d[519]
    DIRECTION INPUT ;
    USE SIGNAL ;
    PORT
      LAYER M5 ;
        RECT  130.704 444.876 130.728 444.96 ;
    END
  END lo_d[519]
  PIN lo_d[51]
    DIRECTION INPUT ;
    USE SIGNAL ;
    PORT
      LAYER M5 ;
        RECT  18.384 444.876 18.408 444.96 ;
    END
  END lo_d[51]
  PIN lo_d[520]
    DIRECTION INPUT ;
    USE SIGNAL ;
    PORT
      LAYER M5 ;
        RECT  130.944 444.876 130.968 444.96 ;
    END
  END lo_d[520]
  PIN lo_d[521]
    DIRECTION INPUT ;
    USE SIGNAL ;
    PORT
      LAYER M5 ;
        RECT  131.184 444.876 131.208 444.96 ;
    END
  END lo_d[521]
  PIN lo_d[522]
    DIRECTION INPUT ;
    USE SIGNAL ;
    PORT
      LAYER M5 ;
        RECT  131.424 444.876 131.448 444.96 ;
    END
  END lo_d[522]
  PIN lo_d[523]
    DIRECTION INPUT ;
    USE SIGNAL ;
    PORT
      LAYER M5 ;
        RECT  131.664 444.876 131.688 444.96 ;
    END
  END lo_d[523]
  PIN lo_d[524]
    DIRECTION INPUT ;
    USE SIGNAL ;
    PORT
      LAYER M5 ;
        RECT  131.904 444.876 131.928 444.96 ;
    END
  END lo_d[524]
  PIN lo_d[525]
    DIRECTION INPUT ;
    USE SIGNAL ;
    PORT
      LAYER M5 ;
        RECT  132.144 444.876 132.168 444.96 ;
    END
  END lo_d[525]
  PIN lo_d[526]
    DIRECTION INPUT ;
    USE SIGNAL ;
    PORT
      LAYER M5 ;
        RECT  132.384 444.876 132.408 444.96 ;
    END
  END lo_d[526]
  PIN lo_d[527]
    DIRECTION INPUT ;
    USE SIGNAL ;
    PORT
      LAYER M5 ;
        RECT  132.624 444.876 132.648 444.96 ;
    END
  END lo_d[527]
  PIN lo_d[528]
    DIRECTION INPUT ;
    USE SIGNAL ;
    PORT
      LAYER M5 ;
        RECT  132.864 444.876 132.888 444.96 ;
    END
  END lo_d[528]
  PIN lo_d[529]
    DIRECTION INPUT ;
    USE SIGNAL ;
    PORT
      LAYER M5 ;
        RECT  133.104 444.876 133.128 444.96 ;
    END
  END lo_d[529]
  PIN lo_d[52]
    DIRECTION INPUT ;
    USE SIGNAL ;
    PORT
      LAYER M5 ;
        RECT  18.624 444.876 18.648 444.96 ;
    END
  END lo_d[52]
  PIN lo_d[530]
    DIRECTION INPUT ;
    USE SIGNAL ;
    PORT
      LAYER M5 ;
        RECT  133.344 444.876 133.368 444.96 ;
    END
  END lo_d[530]
  PIN lo_d[531]
    DIRECTION INPUT ;
    USE SIGNAL ;
    PORT
      LAYER M5 ;
        RECT  133.584 444.876 133.608 444.96 ;
    END
  END lo_d[531]
  PIN lo_d[532]
    DIRECTION INPUT ;
    USE SIGNAL ;
    PORT
      LAYER M5 ;
        RECT  133.824 444.876 133.848 444.96 ;
    END
  END lo_d[532]
  PIN lo_d[533]
    DIRECTION INPUT ;
    USE SIGNAL ;
    PORT
      LAYER M5 ;
        RECT  134.064 444.876 134.088 444.96 ;
    END
  END lo_d[533]
  PIN lo_d[534]
    DIRECTION INPUT ;
    USE SIGNAL ;
    PORT
      LAYER M5 ;
        RECT  134.304 444.876 134.328 444.96 ;
    END
  END lo_d[534]
  PIN lo_d[535]
    DIRECTION INPUT ;
    USE SIGNAL ;
    PORT
      LAYER M5 ;
        RECT  134.544 444.876 134.568 444.96 ;
    END
  END lo_d[535]
  PIN lo_d[536]
    DIRECTION INPUT ;
    USE SIGNAL ;
    PORT
      LAYER M5 ;
        RECT  134.784 444.876 134.808 444.96 ;
    END
  END lo_d[536]
  PIN lo_d[537]
    DIRECTION INPUT ;
    USE SIGNAL ;
    PORT
      LAYER M5 ;
        RECT  135.024 444.876 135.048 444.96 ;
    END
  END lo_d[537]
  PIN lo_d[538]
    DIRECTION INPUT ;
    USE SIGNAL ;
    PORT
      LAYER M5 ;
        RECT  135.264 444.876 135.288 444.96 ;
    END
  END lo_d[538]
  PIN lo_d[539]
    DIRECTION INPUT ;
    USE SIGNAL ;
    PORT
      LAYER M5 ;
        RECT  135.504 444.876 135.528 444.96 ;
    END
  END lo_d[539]
  PIN lo_d[53]
    DIRECTION INPUT ;
    USE SIGNAL ;
    PORT
      LAYER M5 ;
        RECT  18.864 444.876 18.888 444.96 ;
    END
  END lo_d[53]
  PIN lo_d[540]
    DIRECTION INPUT ;
    USE SIGNAL ;
    PORT
      LAYER M5 ;
        RECT  135.744 444.876 135.768 444.96 ;
    END
  END lo_d[540]
  PIN lo_d[541]
    DIRECTION INPUT ;
    USE SIGNAL ;
    PORT
      LAYER M5 ;
        RECT  135.984 444.876 136.008 444.96 ;
    END
  END lo_d[541]
  PIN lo_d[542]
    DIRECTION INPUT ;
    USE SIGNAL ;
    PORT
      LAYER M5 ;
        RECT  136.224 444.876 136.248 444.96 ;
    END
  END lo_d[542]
  PIN lo_d[543]
    DIRECTION INPUT ;
    USE SIGNAL ;
    PORT
      LAYER M5 ;
        RECT  136.464 444.876 136.488 444.96 ;
    END
  END lo_d[543]
  PIN lo_d[544]
    DIRECTION INPUT ;
    USE SIGNAL ;
    PORT
      LAYER M5 ;
        RECT  136.704 444.876 136.728 444.96 ;
    END
  END lo_d[544]
  PIN lo_d[545]
    DIRECTION INPUT ;
    USE SIGNAL ;
    PORT
      LAYER M5 ;
        RECT  136.944 444.876 136.968 444.96 ;
    END
  END lo_d[545]
  PIN lo_d[546]
    DIRECTION INPUT ;
    USE SIGNAL ;
    PORT
      LAYER M5 ;
        RECT  137.184 444.876 137.208 444.96 ;
    END
  END lo_d[546]
  PIN lo_d[547]
    DIRECTION INPUT ;
    USE SIGNAL ;
    PORT
      LAYER M5 ;
        RECT  137.424 444.876 137.448 444.96 ;
    END
  END lo_d[547]
  PIN lo_d[548]
    DIRECTION INPUT ;
    USE SIGNAL ;
    PORT
      LAYER M5 ;
        RECT  137.664 444.876 137.688 444.96 ;
    END
  END lo_d[548]
  PIN lo_d[549]
    DIRECTION INPUT ;
    USE SIGNAL ;
    PORT
      LAYER M5 ;
        RECT  137.904 444.876 137.928 444.96 ;
    END
  END lo_d[549]
  PIN lo_d[54]
    DIRECTION INPUT ;
    USE SIGNAL ;
    PORT
      LAYER M5 ;
        RECT  19.104 444.876 19.128 444.96 ;
    END
  END lo_d[54]
  PIN lo_d[550]
    DIRECTION INPUT ;
    USE SIGNAL ;
    PORT
      LAYER M5 ;
        RECT  138.144 444.876 138.168 444.96 ;
    END
  END lo_d[550]
  PIN lo_d[551]
    DIRECTION INPUT ;
    USE SIGNAL ;
    PORT
      LAYER M5 ;
        RECT  138.384 444.876 138.408 444.96 ;
    END
  END lo_d[551]
  PIN lo_d[552]
    DIRECTION INPUT ;
    USE SIGNAL ;
    PORT
      LAYER M5 ;
        RECT  138.624 444.876 138.648 444.96 ;
    END
  END lo_d[552]
  PIN lo_d[55]
    DIRECTION INPUT ;
    USE SIGNAL ;
    PORT
      LAYER M5 ;
        RECT  19.344 444.876 19.368 444.96 ;
    END
  END lo_d[55]
  PIN lo_d[56]
    DIRECTION INPUT ;
    USE SIGNAL ;
    PORT
      LAYER M5 ;
        RECT  19.584 444.876 19.608 444.96 ;
    END
  END lo_d[56]
  PIN lo_d[57]
    DIRECTION INPUT ;
    USE SIGNAL ;
    PORT
      LAYER M5 ;
        RECT  19.824 444.876 19.848 444.96 ;
    END
  END lo_d[57]
  PIN lo_d[58]
    DIRECTION INPUT ;
    USE SIGNAL ;
    PORT
      LAYER M5 ;
        RECT  20.064 444.876 20.088 444.96 ;
    END
  END lo_d[58]
  PIN lo_d[59]
    DIRECTION INPUT ;
    USE SIGNAL ;
    PORT
      LAYER M5 ;
        RECT  20.304 444.876 20.328 444.96 ;
    END
  END lo_d[59]
  PIN lo_d[5]
    DIRECTION INPUT ;
    USE SIGNAL ;
    PORT
      LAYER M5 ;
        RECT  7.344 444.876 7.368 444.96 ;
    END
  END lo_d[5]
  PIN lo_d[60]
    DIRECTION INPUT ;
    USE SIGNAL ;
    PORT
      LAYER M5 ;
        RECT  20.544 444.876 20.568 444.96 ;
    END
  END lo_d[60]
  PIN lo_d[61]
    DIRECTION INPUT ;
    USE SIGNAL ;
    PORT
      LAYER M5 ;
        RECT  20.784 444.876 20.808 444.96 ;
    END
  END lo_d[61]
  PIN lo_d[62]
    DIRECTION INPUT ;
    USE SIGNAL ;
    PORT
      LAYER M5 ;
        RECT  21.024 444.876 21.048 444.96 ;
    END
  END lo_d[62]
  PIN lo_d[63]
    DIRECTION INPUT ;
    USE SIGNAL ;
    PORT
      LAYER M5 ;
        RECT  21.264 444.876 21.288 444.96 ;
    END
  END lo_d[63]
  PIN lo_d[64]
    DIRECTION INPUT ;
    USE SIGNAL ;
    PORT
      LAYER M5 ;
        RECT  21.504 444.876 21.528 444.96 ;
    END
  END lo_d[64]
  PIN lo_d[65]
    DIRECTION INPUT ;
    USE SIGNAL ;
    PORT
      LAYER M5 ;
        RECT  21.744 444.876 21.768 444.96 ;
    END
  END lo_d[65]
  PIN lo_d[66]
    DIRECTION INPUT ;
    USE SIGNAL ;
    PORT
      LAYER M5 ;
        RECT  21.984 444.876 22.008 444.96 ;
    END
  END lo_d[66]
  PIN lo_d[67]
    DIRECTION INPUT ;
    USE SIGNAL ;
    PORT
      LAYER M5 ;
        RECT  22.224 444.876 22.248 444.96 ;
    END
  END lo_d[67]
  PIN lo_d[68]
    DIRECTION INPUT ;
    USE SIGNAL ;
    PORT
      LAYER M5 ;
        RECT  22.464 444.876 22.488 444.96 ;
    END
  END lo_d[68]
  PIN lo_d[69]
    DIRECTION INPUT ;
    USE SIGNAL ;
    PORT
      LAYER M5 ;
        RECT  22.704 444.876 22.728 444.96 ;
    END
  END lo_d[69]
  PIN lo_d[6]
    DIRECTION INPUT ;
    USE SIGNAL ;
    PORT
      LAYER M5 ;
        RECT  7.584 444.876 7.608 444.96 ;
    END
  END lo_d[6]
  PIN lo_d[70]
    DIRECTION INPUT ;
    USE SIGNAL ;
    PORT
      LAYER M5 ;
        RECT  22.944 444.876 22.968 444.96 ;
    END
  END lo_d[70]
  PIN lo_d[71]
    DIRECTION INPUT ;
    USE SIGNAL ;
    PORT
      LAYER M5 ;
        RECT  23.184 444.876 23.208 444.96 ;
    END
  END lo_d[71]
  PIN lo_d[72]
    DIRECTION INPUT ;
    USE SIGNAL ;
    PORT
      LAYER M5 ;
        RECT  23.424 444.876 23.448 444.96 ;
    END
  END lo_d[72]
  PIN lo_d[73]
    DIRECTION INPUT ;
    USE SIGNAL ;
    PORT
      LAYER M5 ;
        RECT  23.664 444.876 23.688 444.96 ;
    END
  END lo_d[73]
  PIN lo_d[74]
    DIRECTION INPUT ;
    USE SIGNAL ;
    PORT
      LAYER M5 ;
        RECT  23.904 444.876 23.928 444.96 ;
    END
  END lo_d[74]
  PIN lo_d[75]
    DIRECTION INPUT ;
    USE SIGNAL ;
    PORT
      LAYER M5 ;
        RECT  24.144 444.876 24.168 444.96 ;
    END
  END lo_d[75]
  PIN lo_d[76]
    DIRECTION INPUT ;
    USE SIGNAL ;
    PORT
      LAYER M5 ;
        RECT  24.384 444.876 24.408 444.96 ;
    END
  END lo_d[76]
  PIN lo_d[77]
    DIRECTION INPUT ;
    USE SIGNAL ;
    PORT
      LAYER M5 ;
        RECT  24.624 444.876 24.648 444.96 ;
    END
  END lo_d[77]
  PIN lo_d[78]
    DIRECTION INPUT ;
    USE SIGNAL ;
    PORT
      LAYER M5 ;
        RECT  24.864 444.876 24.888 444.96 ;
    END
  END lo_d[78]
  PIN lo_d[79]
    DIRECTION INPUT ;
    USE SIGNAL ;
    PORT
      LAYER M5 ;
        RECT  25.104 444.876 25.128 444.96 ;
    END
  END lo_d[79]
  PIN lo_d[7]
    DIRECTION INPUT ;
    USE SIGNAL ;
    PORT
      LAYER M5 ;
        RECT  7.824 444.876 7.848 444.96 ;
    END
  END lo_d[7]
  PIN lo_d[80]
    DIRECTION INPUT ;
    USE SIGNAL ;
    PORT
      LAYER M5 ;
        RECT  25.344 444.876 25.368 444.96 ;
    END
  END lo_d[80]
  PIN lo_d[81]
    DIRECTION INPUT ;
    USE SIGNAL ;
    PORT
      LAYER M5 ;
        RECT  25.584 444.876 25.608 444.96 ;
    END
  END lo_d[81]
  PIN lo_d[82]
    DIRECTION INPUT ;
    USE SIGNAL ;
    PORT
      LAYER M5 ;
        RECT  25.824 444.876 25.848 444.96 ;
    END
  END lo_d[82]
  PIN lo_d[83]
    DIRECTION INPUT ;
    USE SIGNAL ;
    PORT
      LAYER M5 ;
        RECT  26.064 444.876 26.088 444.96 ;
    END
  END lo_d[83]
  PIN lo_d[84]
    DIRECTION INPUT ;
    USE SIGNAL ;
    PORT
      LAYER M5 ;
        RECT  26.304 444.876 26.328 444.96 ;
    END
  END lo_d[84]
  PIN lo_d[85]
    DIRECTION INPUT ;
    USE SIGNAL ;
    PORT
      LAYER M5 ;
        RECT  26.544 444.876 26.568 444.96 ;
    END
  END lo_d[85]
  PIN lo_d[86]
    DIRECTION INPUT ;
    USE SIGNAL ;
    PORT
      LAYER M5 ;
        RECT  26.784 444.876 26.808 444.96 ;
    END
  END lo_d[86]
  PIN lo_d[87]
    DIRECTION INPUT ;
    USE SIGNAL ;
    PORT
      LAYER M5 ;
        RECT  27.024 444.876 27.048 444.96 ;
    END
  END lo_d[87]
  PIN lo_d[88]
    DIRECTION INPUT ;
    USE SIGNAL ;
    PORT
      LAYER M5 ;
        RECT  27.264 444.876 27.288 444.96 ;
    END
  END lo_d[88]
  PIN lo_d[89]
    DIRECTION INPUT ;
    USE SIGNAL ;
    PORT
      LAYER M5 ;
        RECT  27.504 444.876 27.528 444.96 ;
    END
  END lo_d[89]
  PIN lo_d[8]
    DIRECTION INPUT ;
    USE SIGNAL ;
    PORT
      LAYER M5 ;
        RECT  8.064 444.876 8.088 444.96 ;
    END
  END lo_d[8]
  PIN lo_d[90]
    DIRECTION INPUT ;
    USE SIGNAL ;
    PORT
      LAYER M5 ;
        RECT  27.744 444.876 27.768 444.96 ;
    END
  END lo_d[90]
  PIN lo_d[91]
    DIRECTION INPUT ;
    USE SIGNAL ;
    PORT
      LAYER M5 ;
        RECT  27.984 444.876 28.008 444.96 ;
    END
  END lo_d[91]
  PIN lo_d[92]
    DIRECTION INPUT ;
    USE SIGNAL ;
    PORT
      LAYER M5 ;
        RECT  28.224 444.876 28.248 444.96 ;
    END
  END lo_d[92]
  PIN lo_d[93]
    DIRECTION INPUT ;
    USE SIGNAL ;
    PORT
      LAYER M5 ;
        RECT  28.464 444.876 28.488 444.96 ;
    END
  END lo_d[93]
  PIN lo_d[94]
    DIRECTION INPUT ;
    USE SIGNAL ;
    PORT
      LAYER M5 ;
        RECT  28.704 444.876 28.728 444.96 ;
    END
  END lo_d[94]
  PIN lo_d[95]
    DIRECTION INPUT ;
    USE SIGNAL ;
    PORT
      LAYER M5 ;
        RECT  28.944 444.876 28.968 444.96 ;
    END
  END lo_d[95]
  PIN lo_d[96]
    DIRECTION INPUT ;
    USE SIGNAL ;
    PORT
      LAYER M5 ;
        RECT  29.184 444.876 29.208 444.96 ;
    END
  END lo_d[96]
  PIN lo_d[97]
    DIRECTION INPUT ;
    USE SIGNAL ;
    PORT
      LAYER M5 ;
        RECT  29.424 444.876 29.448 444.96 ;
    END
  END lo_d[97]
  PIN lo_d[98]
    DIRECTION INPUT ;
    USE SIGNAL ;
    PORT
      LAYER M5 ;
        RECT  29.664 444.876 29.688 444.96 ;
    END
  END lo_d[98]
  PIN lo_d[99]
    DIRECTION INPUT ;
    USE SIGNAL ;
    PORT
      LAYER M5 ;
        RECT  29.904 444.876 29.928 444.96 ;
    END
  END lo_d[99]
  PIN lo_d[9]
    DIRECTION INPUT ;
    USE SIGNAL ;
    PORT
      LAYER M5 ;
        RECT  8.304 444.876 8.328 444.96 ;
    END
  END lo_d[9]
  PIN lo_r[0]
    DIRECTION OUTPUT ;
    USE SIGNAL ;
    PORT
      LAYER M5 ;
        RECT  139.104 444.876 139.128 444.96 ;
    END
  END lo_r[0]
  PIN lo_v[0]
    DIRECTION INPUT ;
    USE SIGNAL ;
    PORT
      LAYER M5 ;
        RECT  138.864 444.876 138.888 444.96 ;
    END
  END lo_v[0]
  PIN rs[0]
    DIRECTION INPUT ;
    USE SIGNAL ;
    PORT
      LAYER M4 ;
        RECT  295.836 236.496 295.92 236.52 ;
    END
  END rs[0]
  PIN rx[0]
    DIRECTION INPUT ;
    USE SIGNAL ;
    PORT
      LAYER M5 ;
        RECT  147.936 444.876 147.96 444.96 ;
    END
  END rx[0]
  PIN rx[100]
    DIRECTION INPUT ;
    USE SIGNAL ;
    PORT
      LAYER M5 ;
        RECT  30.144 0 30.168 0.084 ;
    END
  END rx[100]
  PIN rx[101]
    DIRECTION INPUT ;
    USE SIGNAL ;
    PORT
      LAYER M5 ;
        RECT  30.384 0 30.408 0.084 ;
    END
  END rx[101]
  PIN rx[102]
    DIRECTION INPUT ;
    USE SIGNAL ;
    PORT
      LAYER M5 ;
        RECT  30.624 0 30.648 0.084 ;
    END
  END rx[102]
  PIN rx[103]
    DIRECTION INPUT ;
    USE SIGNAL ;
    PORT
      LAYER M5 ;
        RECT  30.864 0 30.888 0.084 ;
    END
  END rx[103]
  PIN rx[104]
    DIRECTION INPUT ;
    USE SIGNAL ;
    PORT
      LAYER M5 ;
        RECT  31.104 0 31.128 0.084 ;
    END
  END rx[104]
  PIN rx[105]
    DIRECTION INPUT ;
    USE SIGNAL ;
    PORT
      LAYER M5 ;
        RECT  31.344 0 31.368 0.084 ;
    END
  END rx[105]
  PIN rx[106]
    DIRECTION INPUT ;
    USE SIGNAL ;
    PORT
      LAYER M5 ;
        RECT  31.584 0 31.608 0.084 ;
    END
  END rx[106]
  PIN rx[107]
    DIRECTION INPUT ;
    USE SIGNAL ;
    PORT
      LAYER M5 ;
        RECT  31.824 0 31.848 0.084 ;
    END
  END rx[107]
  PIN rx[108]
    DIRECTION INPUT ;
    USE SIGNAL ;
    PORT
      LAYER M5 ;
        RECT  32.064 0 32.088 0.084 ;
    END
  END rx[108]
  PIN rx[109]
    DIRECTION INPUT ;
    USE SIGNAL ;
    PORT
      LAYER M5 ;
        RECT  32.304 0 32.328 0.084 ;
    END
  END rx[109]
  PIN rx[10]
    DIRECTION INPUT ;
    USE SIGNAL ;
    PORT
      LAYER M5 ;
        RECT  8.544 0 8.568 0.084 ;
    END
  END rx[10]
  PIN rx[110]
    DIRECTION INPUT ;
    USE SIGNAL ;
    PORT
      LAYER M5 ;
        RECT  32.544 0 32.568 0.084 ;
    END
  END rx[110]
  PIN rx[111]
    DIRECTION INPUT ;
    USE SIGNAL ;
    PORT
      LAYER M5 ;
        RECT  32.784 0 32.808 0.084 ;
    END
  END rx[111]
  PIN rx[112]
    DIRECTION INPUT ;
    USE SIGNAL ;
    PORT
      LAYER M5 ;
        RECT  33.024 0 33.048 0.084 ;
    END
  END rx[112]
  PIN rx[113]
    DIRECTION INPUT ;
    USE SIGNAL ;
    PORT
      LAYER M5 ;
        RECT  33.264 0 33.288 0.084 ;
    END
  END rx[113]
  PIN rx[114]
    DIRECTION INPUT ;
    USE SIGNAL ;
    PORT
      LAYER M5 ;
        RECT  33.504 0 33.528 0.084 ;
    END
  END rx[114]
  PIN rx[115]
    DIRECTION INPUT ;
    USE SIGNAL ;
    PORT
      LAYER M5 ;
        RECT  33.744 0 33.768 0.084 ;
    END
  END rx[115]
  PIN rx[116]
    DIRECTION INPUT ;
    USE SIGNAL ;
    PORT
      LAYER M5 ;
        RECT  33.984 0 34.008 0.084 ;
    END
  END rx[116]
  PIN rx[117]
    DIRECTION INPUT ;
    USE SIGNAL ;
    PORT
      LAYER M5 ;
        RECT  34.224 0 34.248 0.084 ;
    END
  END rx[117]
  PIN rx[118]
    DIRECTION INPUT ;
    USE SIGNAL ;
    PORT
      LAYER M5 ;
        RECT  34.464 0 34.488 0.084 ;
    END
  END rx[118]
  PIN rx[119]
    DIRECTION INPUT ;
    USE SIGNAL ;
    PORT
      LAYER M5 ;
        RECT  34.704 0 34.728 0.084 ;
    END
  END rx[119]
  PIN rx[11]
    DIRECTION INPUT ;
    USE SIGNAL ;
    PORT
      LAYER M5 ;
        RECT  8.784 0 8.808 0.084 ;
    END
  END rx[11]
  PIN rx[120]
    DIRECTION INPUT ;
    USE SIGNAL ;
    PORT
      LAYER M5 ;
        RECT  34.944 0 34.968 0.084 ;
    END
  END rx[120]
  PIN rx[121]
    DIRECTION INPUT ;
    USE SIGNAL ;
    PORT
      LAYER M5 ;
        RECT  35.184 0 35.208 0.084 ;
    END
  END rx[121]
  PIN rx[122]
    DIRECTION INPUT ;
    USE SIGNAL ;
    PORT
      LAYER M5 ;
        RECT  35.424 0 35.448 0.084 ;
    END
  END rx[122]
  PIN rx[123]
    DIRECTION INPUT ;
    USE SIGNAL ;
    PORT
      LAYER M5 ;
        RECT  35.664 0 35.688 0.084 ;
    END
  END rx[123]
  PIN rx[124]
    DIRECTION INPUT ;
    USE SIGNAL ;
    PORT
      LAYER M5 ;
        RECT  35.904 0 35.928 0.084 ;
    END
  END rx[124]
  PIN rx[125]
    DIRECTION INPUT ;
    USE SIGNAL ;
    PORT
      LAYER M5 ;
        RECT  36.144 0 36.168 0.084 ;
    END
  END rx[125]
  PIN rx[126]
    DIRECTION INPUT ;
    USE SIGNAL ;
    PORT
      LAYER M5 ;
        RECT  36.384 0 36.408 0.084 ;
    END
  END rx[126]
  PIN rx[127]
    DIRECTION INPUT ;
    USE SIGNAL ;
    PORT
      LAYER M5 ;
        RECT  36.624 0 36.648 0.084 ;
    END
  END rx[127]
  PIN rx[128]
    DIRECTION INPUT ;
    USE SIGNAL ;
    PORT
      LAYER M5 ;
        RECT  36.864 0 36.888 0.084 ;
    END
  END rx[128]
  PIN rx[129]
    DIRECTION INPUT ;
    USE SIGNAL ;
    PORT
      LAYER M5 ;
        RECT  37.104 0 37.128 0.084 ;
    END
  END rx[129]
  PIN rx[12]
    DIRECTION INPUT ;
    USE SIGNAL ;
    PORT
      LAYER M5 ;
        RECT  9.024 0 9.048 0.084 ;
    END
  END rx[12]
  PIN rx[130]
    DIRECTION INPUT ;
    USE SIGNAL ;
    PORT
      LAYER M5 ;
        RECT  37.344 0 37.368 0.084 ;
    END
  END rx[130]
  PIN rx[131]
    DIRECTION INPUT ;
    USE SIGNAL ;
    PORT
      LAYER M5 ;
        RECT  37.584 0 37.608 0.084 ;
    END
  END rx[131]
  PIN rx[132]
    DIRECTION INPUT ;
    USE SIGNAL ;
    PORT
      LAYER M5 ;
        RECT  37.824 0 37.848 0.084 ;
    END
  END rx[132]
  PIN rx[133]
    DIRECTION INPUT ;
    USE SIGNAL ;
    PORT
      LAYER M5 ;
        RECT  38.064 0 38.088 0.084 ;
    END
  END rx[133]
  PIN rx[134]
    DIRECTION INPUT ;
    USE SIGNAL ;
    PORT
      LAYER M5 ;
        RECT  38.304 0 38.328 0.084 ;
    END
  END rx[134]
  PIN rx[135]
    DIRECTION INPUT ;
    USE SIGNAL ;
    PORT
      LAYER M5 ;
        RECT  38.544 0 38.568 0.084 ;
    END
  END rx[135]
  PIN rx[136]
    DIRECTION INPUT ;
    USE SIGNAL ;
    PORT
      LAYER M5 ;
        RECT  38.784 0 38.808 0.084 ;
    END
  END rx[136]
  PIN rx[137]
    DIRECTION INPUT ;
    USE SIGNAL ;
    PORT
      LAYER M5 ;
        RECT  39.024 0 39.048 0.084 ;
    END
  END rx[137]
  PIN rx[138]
    DIRECTION INPUT ;
    USE SIGNAL ;
    PORT
      LAYER M5 ;
        RECT  39.264 0 39.288 0.084 ;
    END
  END rx[138]
  PIN rx[139]
    DIRECTION INPUT ;
    USE SIGNAL ;
    PORT
      LAYER M5 ;
        RECT  39.504 0 39.528 0.084 ;
    END
  END rx[139]
  PIN rx[13]
    DIRECTION INPUT ;
    USE SIGNAL ;
    PORT
      LAYER M5 ;
        RECT  9.264 0 9.288 0.084 ;
    END
  END rx[13]
  PIN rx[140]
    DIRECTION INPUT ;
    USE SIGNAL ;
    PORT
      LAYER M5 ;
        RECT  39.744 0 39.768 0.084 ;
    END
  END rx[140]
  PIN rx[141]
    DIRECTION INPUT ;
    USE SIGNAL ;
    PORT
      LAYER M5 ;
        RECT  39.984 0 40.008 0.084 ;
    END
  END rx[141]
  PIN rx[142]
    DIRECTION INPUT ;
    USE SIGNAL ;
    PORT
      LAYER M5 ;
        RECT  40.224 0 40.248 0.084 ;
    END
  END rx[142]
  PIN rx[143]
    DIRECTION INPUT ;
    USE SIGNAL ;
    PORT
      LAYER M5 ;
        RECT  40.464 0 40.488 0.084 ;
    END
  END rx[143]
  PIN rx[144]
    DIRECTION INPUT ;
    USE SIGNAL ;
    PORT
      LAYER M5 ;
        RECT  40.704 0 40.728 0.084 ;
    END
  END rx[144]
  PIN rx[145]
    DIRECTION INPUT ;
    USE SIGNAL ;
    PORT
      LAYER M5 ;
        RECT  40.944 0 40.968 0.084 ;
    END
  END rx[145]
  PIN rx[146]
    DIRECTION INPUT ;
    USE SIGNAL ;
    PORT
      LAYER M5 ;
        RECT  41.184 0 41.208 0.084 ;
    END
  END rx[146]
  PIN rx[147]
    DIRECTION INPUT ;
    USE SIGNAL ;
    PORT
      LAYER M5 ;
        RECT  41.424 0 41.448 0.084 ;
    END
  END rx[147]
  PIN rx[148]
    DIRECTION INPUT ;
    USE SIGNAL ;
    PORT
      LAYER M5 ;
        RECT  41.664 0 41.688 0.084 ;
    END
  END rx[148]
  PIN rx[149]
    DIRECTION INPUT ;
    USE SIGNAL ;
    PORT
      LAYER M5 ;
        RECT  41.904 0 41.928 0.084 ;
    END
  END rx[149]
  PIN rx[14]
    DIRECTION INPUT ;
    USE SIGNAL ;
    PORT
      LAYER M5 ;
        RECT  9.504 0 9.528 0.084 ;
    END
  END rx[14]
  PIN rx[150]
    DIRECTION INPUT ;
    USE SIGNAL ;
    PORT
      LAYER M5 ;
        RECT  42.144 0 42.168 0.084 ;
    END
  END rx[150]
  PIN rx[151]
    DIRECTION INPUT ;
    USE SIGNAL ;
    PORT
      LAYER M5 ;
        RECT  42.384 0 42.408 0.084 ;
    END
  END rx[151]
  PIN rx[152]
    DIRECTION INPUT ;
    USE SIGNAL ;
    PORT
      LAYER M5 ;
        RECT  42.624 0 42.648 0.084 ;
    END
  END rx[152]
  PIN rx[153]
    DIRECTION INPUT ;
    USE SIGNAL ;
    PORT
      LAYER M5 ;
        RECT  42.864 0 42.888 0.084 ;
    END
  END rx[153]
  PIN rx[154]
    DIRECTION INPUT ;
    USE SIGNAL ;
    PORT
      LAYER M5 ;
        RECT  43.104 0 43.128 0.084 ;
    END
  END rx[154]
  PIN rx[155]
    DIRECTION INPUT ;
    USE SIGNAL ;
    PORT
      LAYER M5 ;
        RECT  43.344 0 43.368 0.084 ;
    END
  END rx[155]
  PIN rx[156]
    DIRECTION INPUT ;
    USE SIGNAL ;
    PORT
      LAYER M5 ;
        RECT  43.584 0 43.608 0.084 ;
    END
  END rx[156]
  PIN rx[157]
    DIRECTION INPUT ;
    USE SIGNAL ;
    PORT
      LAYER M5 ;
        RECT  43.824 0 43.848 0.084 ;
    END
  END rx[157]
  PIN rx[158]
    DIRECTION INPUT ;
    USE SIGNAL ;
    PORT
      LAYER M5 ;
        RECT  44.064 0 44.088 0.084 ;
    END
  END rx[158]
  PIN rx[159]
    DIRECTION INPUT ;
    USE SIGNAL ;
    PORT
      LAYER M5 ;
        RECT  44.304 0 44.328 0.084 ;
    END
  END rx[159]
  PIN rx[15]
    DIRECTION INPUT ;
    USE SIGNAL ;
    PORT
      LAYER M5 ;
        RECT  9.744 0 9.768 0.084 ;
    END
  END rx[15]
  PIN rx[160]
    DIRECTION INPUT ;
    USE SIGNAL ;
    PORT
      LAYER M5 ;
        RECT  44.544 0 44.568 0.084 ;
    END
  END rx[160]
  PIN rx[161]
    DIRECTION INPUT ;
    USE SIGNAL ;
    PORT
      LAYER M5 ;
        RECT  44.784 0 44.808 0.084 ;
    END
  END rx[161]
  PIN rx[162]
    DIRECTION INPUT ;
    USE SIGNAL ;
    PORT
      LAYER M5 ;
        RECT  45.024 0 45.048 0.084 ;
    END
  END rx[162]
  PIN rx[163]
    DIRECTION INPUT ;
    USE SIGNAL ;
    PORT
      LAYER M5 ;
        RECT  45.264 0 45.288 0.084 ;
    END
  END rx[163]
  PIN rx[164]
    DIRECTION INPUT ;
    USE SIGNAL ;
    PORT
      LAYER M5 ;
        RECT  45.504 0 45.528 0.084 ;
    END
  END rx[164]
  PIN rx[165]
    DIRECTION INPUT ;
    USE SIGNAL ;
    PORT
      LAYER M5 ;
        RECT  45.744 0 45.768 0.084 ;
    END
  END rx[165]
  PIN rx[166]
    DIRECTION INPUT ;
    USE SIGNAL ;
    PORT
      LAYER M5 ;
        RECT  45.984 0 46.008 0.084 ;
    END
  END rx[166]
  PIN rx[167]
    DIRECTION INPUT ;
    USE SIGNAL ;
    PORT
      LAYER M5 ;
        RECT  46.224 0 46.248 0.084 ;
    END
  END rx[167]
  PIN rx[168]
    DIRECTION INPUT ;
    USE SIGNAL ;
    PORT
      LAYER M5 ;
        RECT  46.464 0 46.488 0.084 ;
    END
  END rx[168]
  PIN rx[169]
    DIRECTION INPUT ;
    USE SIGNAL ;
    PORT
      LAYER M5 ;
        RECT  46.704 0 46.728 0.084 ;
    END
  END rx[169]
  PIN rx[16]
    DIRECTION INPUT ;
    USE SIGNAL ;
    PORT
      LAYER M5 ;
        RECT  9.984 0 10.008 0.084 ;
    END
  END rx[16]
  PIN rx[170]
    DIRECTION INPUT ;
    USE SIGNAL ;
    PORT
      LAYER M5 ;
        RECT  46.944 0 46.968 0.084 ;
    END
  END rx[170]
  PIN rx[171]
    DIRECTION INPUT ;
    USE SIGNAL ;
    PORT
      LAYER M5 ;
        RECT  47.184 0 47.208 0.084 ;
    END
  END rx[171]
  PIN rx[172]
    DIRECTION INPUT ;
    USE SIGNAL ;
    PORT
      LAYER M5 ;
        RECT  47.424 0 47.448 0.084 ;
    END
  END rx[172]
  PIN rx[173]
    DIRECTION INPUT ;
    USE SIGNAL ;
    PORT
      LAYER M5 ;
        RECT  47.664 0 47.688 0.084 ;
    END
  END rx[173]
  PIN rx[174]
    DIRECTION INPUT ;
    USE SIGNAL ;
    PORT
      LAYER M5 ;
        RECT  47.904 0 47.928 0.084 ;
    END
  END rx[174]
  PIN rx[175]
    DIRECTION INPUT ;
    USE SIGNAL ;
    PORT
      LAYER M5 ;
        RECT  48.144 0 48.168 0.084 ;
    END
  END rx[175]
  PIN rx[176]
    DIRECTION INPUT ;
    USE SIGNAL ;
    PORT
      LAYER M5 ;
        RECT  48.384 0 48.408 0.084 ;
    END
  END rx[176]
  PIN rx[177]
    DIRECTION INPUT ;
    USE SIGNAL ;
    PORT
      LAYER M5 ;
        RECT  48.624 0 48.648 0.084 ;
    END
  END rx[177]
  PIN rx[178]
    DIRECTION INPUT ;
    USE SIGNAL ;
    PORT
      LAYER M5 ;
        RECT  48.864 0 48.888 0.084 ;
    END
  END rx[178]
  PIN rx[179]
    DIRECTION INPUT ;
    USE SIGNAL ;
    PORT
      LAYER M5 ;
        RECT  49.104 0 49.128 0.084 ;
    END
  END rx[179]
  PIN rx[17]
    DIRECTION INPUT ;
    USE SIGNAL ;
    PORT
      LAYER M5 ;
        RECT  10.224 0 10.248 0.084 ;
    END
  END rx[17]
  PIN rx[180]
    DIRECTION INPUT ;
    USE SIGNAL ;
    PORT
      LAYER M5 ;
        RECT  49.344 0 49.368 0.084 ;
    END
  END rx[180]
  PIN rx[181]
    DIRECTION INPUT ;
    USE SIGNAL ;
    PORT
      LAYER M5 ;
        RECT  49.584 0 49.608 0.084 ;
    END
  END rx[181]
  PIN rx[182]
    DIRECTION INPUT ;
    USE SIGNAL ;
    PORT
      LAYER M5 ;
        RECT  49.824 0 49.848 0.084 ;
    END
  END rx[182]
  PIN rx[183]
    DIRECTION INPUT ;
    USE SIGNAL ;
    PORT
      LAYER M5 ;
        RECT  50.064 0 50.088 0.084 ;
    END
  END rx[183]
  PIN rx[184]
    DIRECTION INPUT ;
    USE SIGNAL ;
    PORT
      LAYER M5 ;
        RECT  50.304 0 50.328 0.084 ;
    END
  END rx[184]
  PIN rx[185]
    DIRECTION INPUT ;
    USE SIGNAL ;
    PORT
      LAYER M5 ;
        RECT  50.544 0 50.568 0.084 ;
    END
  END rx[185]
  PIN rx[186]
    DIRECTION INPUT ;
    USE SIGNAL ;
    PORT
      LAYER M5 ;
        RECT  50.784 0 50.808 0.084 ;
    END
  END rx[186]
  PIN rx[187]
    DIRECTION INPUT ;
    USE SIGNAL ;
    PORT
      LAYER M5 ;
        RECT  51.024 0 51.048 0.084 ;
    END
  END rx[187]
  PIN rx[188]
    DIRECTION INPUT ;
    USE SIGNAL ;
    PORT
      LAYER M5 ;
        RECT  51.264 0 51.288 0.084 ;
    END
  END rx[188]
  PIN rx[189]
    DIRECTION INPUT ;
    USE SIGNAL ;
    PORT
      LAYER M5 ;
        RECT  51.504 0 51.528 0.084 ;
    END
  END rx[189]
  PIN rx[18]
    DIRECTION INPUT ;
    USE SIGNAL ;
    PORT
      LAYER M5 ;
        RECT  10.464 0 10.488 0.084 ;
    END
  END rx[18]
  PIN rx[190]
    DIRECTION INPUT ;
    USE SIGNAL ;
    PORT
      LAYER M5 ;
        RECT  51.744 0 51.768 0.084 ;
    END
  END rx[190]
  PIN rx[191]
    DIRECTION INPUT ;
    USE SIGNAL ;
    PORT
      LAYER M5 ;
        RECT  51.984 0 52.008 0.084 ;
    END
  END rx[191]
  PIN rx[192]
    DIRECTION INPUT ;
    USE SIGNAL ;
    PORT
      LAYER M5 ;
        RECT  52.224 0 52.248 0.084 ;
    END
  END rx[192]
  PIN rx[193]
    DIRECTION INPUT ;
    USE SIGNAL ;
    PORT
      LAYER M5 ;
        RECT  52.464 0 52.488 0.084 ;
    END
  END rx[193]
  PIN rx[194]
    DIRECTION INPUT ;
    USE SIGNAL ;
    PORT
      LAYER M5 ;
        RECT  52.704 0 52.728 0.084 ;
    END
  END rx[194]
  PIN rx[195]
    DIRECTION INPUT ;
    USE SIGNAL ;
    PORT
      LAYER M5 ;
        RECT  52.944 0 52.968 0.084 ;
    END
  END rx[195]
  PIN rx[196]
    DIRECTION INPUT ;
    USE SIGNAL ;
    PORT
      LAYER M5 ;
        RECT  53.184 0 53.208 0.084 ;
    END
  END rx[196]
  PIN rx[197]
    DIRECTION INPUT ;
    USE SIGNAL ;
    PORT
      LAYER M5 ;
        RECT  53.424 0 53.448 0.084 ;
    END
  END rx[197]
  PIN rx[198]
    DIRECTION INPUT ;
    USE SIGNAL ;
    PORT
      LAYER M5 ;
        RECT  53.664 0 53.688 0.084 ;
    END
  END rx[198]
  PIN rx[199]
    DIRECTION INPUT ;
    USE SIGNAL ;
    PORT
      LAYER M5 ;
        RECT  53.904 0 53.928 0.084 ;
    END
  END rx[199]
  PIN rx[19]
    DIRECTION INPUT ;
    USE SIGNAL ;
    PORT
      LAYER M5 ;
        RECT  10.704 0 10.728 0.084 ;
    END
  END rx[19]
  PIN rx[1]
    DIRECTION INPUT ;
    USE SIGNAL ;
    PORT
      LAYER M5 ;
        RECT  6.384 0 6.408 0.084 ;
    END
  END rx[1]
  PIN rx[200]
    DIRECTION INPUT ;
    USE SIGNAL ;
    PORT
      LAYER M5 ;
        RECT  54.144 0 54.168 0.084 ;
    END
  END rx[200]
  PIN rx[201]
    DIRECTION INPUT ;
    USE SIGNAL ;
    PORT
      LAYER M5 ;
        RECT  54.384 0 54.408 0.084 ;
    END
  END rx[201]
  PIN rx[202]
    DIRECTION INPUT ;
    USE SIGNAL ;
    PORT
      LAYER M5 ;
        RECT  54.624 0 54.648 0.084 ;
    END
  END rx[202]
  PIN rx[203]
    DIRECTION INPUT ;
    USE SIGNAL ;
    PORT
      LAYER M5 ;
        RECT  54.864 0 54.888 0.084 ;
    END
  END rx[203]
  PIN rx[204]
    DIRECTION INPUT ;
    USE SIGNAL ;
    PORT
      LAYER M5 ;
        RECT  55.104 0 55.128 0.084 ;
    END
  END rx[204]
  PIN rx[205]
    DIRECTION INPUT ;
    USE SIGNAL ;
    PORT
      LAYER M5 ;
        RECT  55.344 0 55.368 0.084 ;
    END
  END rx[205]
  PIN rx[206]
    DIRECTION INPUT ;
    USE SIGNAL ;
    PORT
      LAYER M5 ;
        RECT  55.584 0 55.608 0.084 ;
    END
  END rx[206]
  PIN rx[207]
    DIRECTION INPUT ;
    USE SIGNAL ;
    PORT
      LAYER M5 ;
        RECT  55.824 0 55.848 0.084 ;
    END
  END rx[207]
  PIN rx[208]
    DIRECTION INPUT ;
    USE SIGNAL ;
    PORT
      LAYER M5 ;
        RECT  56.064 0 56.088 0.084 ;
    END
  END rx[208]
  PIN rx[209]
    DIRECTION INPUT ;
    USE SIGNAL ;
    PORT
      LAYER M5 ;
        RECT  56.304 0 56.328 0.084 ;
    END
  END rx[209]
  PIN rx[20]
    DIRECTION INPUT ;
    USE SIGNAL ;
    PORT
      LAYER M5 ;
        RECT  10.944 0 10.968 0.084 ;
    END
  END rx[20]
  PIN rx[210]
    DIRECTION INPUT ;
    USE SIGNAL ;
    PORT
      LAYER M5 ;
        RECT  56.544 0 56.568 0.084 ;
    END
  END rx[210]
  PIN rx[211]
    DIRECTION INPUT ;
    USE SIGNAL ;
    PORT
      LAYER M5 ;
        RECT  56.784 0 56.808 0.084 ;
    END
  END rx[211]
  PIN rx[212]
    DIRECTION INPUT ;
    USE SIGNAL ;
    PORT
      LAYER M5 ;
        RECT  57.024 0 57.048 0.084 ;
    END
  END rx[212]
  PIN rx[213]
    DIRECTION INPUT ;
    USE SIGNAL ;
    PORT
      LAYER M5 ;
        RECT  57.264 0 57.288 0.084 ;
    END
  END rx[213]
  PIN rx[214]
    DIRECTION INPUT ;
    USE SIGNAL ;
    PORT
      LAYER M5 ;
        RECT  57.504 0 57.528 0.084 ;
    END
  END rx[214]
  PIN rx[215]
    DIRECTION INPUT ;
    USE SIGNAL ;
    PORT
      LAYER M5 ;
        RECT  57.744 0 57.768 0.084 ;
    END
  END rx[215]
  PIN rx[216]
    DIRECTION INPUT ;
    USE SIGNAL ;
    PORT
      LAYER M5 ;
        RECT  57.984 0 58.008 0.084 ;
    END
  END rx[216]
  PIN rx[217]
    DIRECTION INPUT ;
    USE SIGNAL ;
    PORT
      LAYER M5 ;
        RECT  58.224 0 58.248 0.084 ;
    END
  END rx[217]
  PIN rx[218]
    DIRECTION INPUT ;
    USE SIGNAL ;
    PORT
      LAYER M5 ;
        RECT  58.464 0 58.488 0.084 ;
    END
  END rx[218]
  PIN rx[219]
    DIRECTION INPUT ;
    USE SIGNAL ;
    PORT
      LAYER M5 ;
        RECT  58.704 0 58.728 0.084 ;
    END
  END rx[219]
  PIN rx[21]
    DIRECTION INPUT ;
    USE SIGNAL ;
    PORT
      LAYER M5 ;
        RECT  11.184 0 11.208 0.084 ;
    END
  END rx[21]
  PIN rx[220]
    DIRECTION INPUT ;
    USE SIGNAL ;
    PORT
      LAYER M5 ;
        RECT  58.944 0 58.968 0.084 ;
    END
  END rx[220]
  PIN rx[221]
    DIRECTION INPUT ;
    USE SIGNAL ;
    PORT
      LAYER M5 ;
        RECT  59.184 0 59.208 0.084 ;
    END
  END rx[221]
  PIN rx[222]
    DIRECTION INPUT ;
    USE SIGNAL ;
    PORT
      LAYER M5 ;
        RECT  59.424 0 59.448 0.084 ;
    END
  END rx[222]
  PIN rx[223]
    DIRECTION INPUT ;
    USE SIGNAL ;
    PORT
      LAYER M5 ;
        RECT  59.664 0 59.688 0.084 ;
    END
  END rx[223]
  PIN rx[224]
    DIRECTION INPUT ;
    USE SIGNAL ;
    PORT
      LAYER M5 ;
        RECT  59.904 0 59.928 0.084 ;
    END
  END rx[224]
  PIN rx[225]
    DIRECTION INPUT ;
    USE SIGNAL ;
    PORT
      LAYER M5 ;
        RECT  60.144 0 60.168 0.084 ;
    END
  END rx[225]
  PIN rx[226]
    DIRECTION INPUT ;
    USE SIGNAL ;
    PORT
      LAYER M5 ;
        RECT  60.384 0 60.408 0.084 ;
    END
  END rx[226]
  PIN rx[227]
    DIRECTION INPUT ;
    USE SIGNAL ;
    PORT
      LAYER M5 ;
        RECT  60.624 0 60.648 0.084 ;
    END
  END rx[227]
  PIN rx[228]
    DIRECTION INPUT ;
    USE SIGNAL ;
    PORT
      LAYER M5 ;
        RECT  60.864 0 60.888 0.084 ;
    END
  END rx[228]
  PIN rx[229]
    DIRECTION INPUT ;
    USE SIGNAL ;
    PORT
      LAYER M5 ;
        RECT  61.104 0 61.128 0.084 ;
    END
  END rx[229]
  PIN rx[22]
    DIRECTION INPUT ;
    USE SIGNAL ;
    PORT
      LAYER M5 ;
        RECT  11.424 0 11.448 0.084 ;
    END
  END rx[22]
  PIN rx[230]
    DIRECTION INPUT ;
    USE SIGNAL ;
    PORT
      LAYER M5 ;
        RECT  61.344 0 61.368 0.084 ;
    END
  END rx[230]
  PIN rx[231]
    DIRECTION INPUT ;
    USE SIGNAL ;
    PORT
      LAYER M5 ;
        RECT  61.584 0 61.608 0.084 ;
    END
  END rx[231]
  PIN rx[232]
    DIRECTION INPUT ;
    USE SIGNAL ;
    PORT
      LAYER M5 ;
        RECT  61.824 0 61.848 0.084 ;
    END
  END rx[232]
  PIN rx[233]
    DIRECTION INPUT ;
    USE SIGNAL ;
    PORT
      LAYER M5 ;
        RECT  62.064 0 62.088 0.084 ;
    END
  END rx[233]
  PIN rx[234]
    DIRECTION INPUT ;
    USE SIGNAL ;
    PORT
      LAYER M5 ;
        RECT  62.304 0 62.328 0.084 ;
    END
  END rx[234]
  PIN rx[235]
    DIRECTION INPUT ;
    USE SIGNAL ;
    PORT
      LAYER M5 ;
        RECT  62.544 0 62.568 0.084 ;
    END
  END rx[235]
  PIN rx[236]
    DIRECTION INPUT ;
    USE SIGNAL ;
    PORT
      LAYER M5 ;
        RECT  62.784 0 62.808 0.084 ;
    END
  END rx[236]
  PIN rx[237]
    DIRECTION INPUT ;
    USE SIGNAL ;
    PORT
      LAYER M5 ;
        RECT  63.024 0 63.048 0.084 ;
    END
  END rx[237]
  PIN rx[238]
    DIRECTION INPUT ;
    USE SIGNAL ;
    PORT
      LAYER M5 ;
        RECT  63.264 0 63.288 0.084 ;
    END
  END rx[238]
  PIN rx[239]
    DIRECTION INPUT ;
    USE SIGNAL ;
    PORT
      LAYER M5 ;
        RECT  63.504 0 63.528 0.084 ;
    END
  END rx[239]
  PIN rx[23]
    DIRECTION INPUT ;
    USE SIGNAL ;
    PORT
      LAYER M5 ;
        RECT  11.664 0 11.688 0.084 ;
    END
  END rx[23]
  PIN rx[240]
    DIRECTION INPUT ;
    USE SIGNAL ;
    PORT
      LAYER M5 ;
        RECT  63.744 0 63.768 0.084 ;
    END
  END rx[240]
  PIN rx[241]
    DIRECTION INPUT ;
    USE SIGNAL ;
    PORT
      LAYER M5 ;
        RECT  63.984 0 64.008 0.084 ;
    END
  END rx[241]
  PIN rx[242]
    DIRECTION INPUT ;
    USE SIGNAL ;
    PORT
      LAYER M5 ;
        RECT  64.224 0 64.248 0.084 ;
    END
  END rx[242]
  PIN rx[243]
    DIRECTION INPUT ;
    USE SIGNAL ;
    PORT
      LAYER M5 ;
        RECT  64.464 0 64.488 0.084 ;
    END
  END rx[243]
  PIN rx[244]
    DIRECTION INPUT ;
    USE SIGNAL ;
    PORT
      LAYER M5 ;
        RECT  64.704 0 64.728 0.084 ;
    END
  END rx[244]
  PIN rx[245]
    DIRECTION INPUT ;
    USE SIGNAL ;
    PORT
      LAYER M5 ;
        RECT  64.944 0 64.968 0.084 ;
    END
  END rx[245]
  PIN rx[246]
    DIRECTION INPUT ;
    USE SIGNAL ;
    PORT
      LAYER M5 ;
        RECT  65.184 0 65.208 0.084 ;
    END
  END rx[246]
  PIN rx[247]
    DIRECTION INPUT ;
    USE SIGNAL ;
    PORT
      LAYER M5 ;
        RECT  65.424 0 65.448 0.084 ;
    END
  END rx[247]
  PIN rx[248]
    DIRECTION INPUT ;
    USE SIGNAL ;
    PORT
      LAYER M5 ;
        RECT  65.664 0 65.688 0.084 ;
    END
  END rx[248]
  PIN rx[249]
    DIRECTION INPUT ;
    USE SIGNAL ;
    PORT
      LAYER M5 ;
        RECT  65.904 0 65.928 0.084 ;
    END
  END rx[249]
  PIN rx[24]
    DIRECTION INPUT ;
    USE SIGNAL ;
    PORT
      LAYER M5 ;
        RECT  11.904 0 11.928 0.084 ;
    END
  END rx[24]
  PIN rx[250]
    DIRECTION INPUT ;
    USE SIGNAL ;
    PORT
      LAYER M5 ;
        RECT  66.144 0 66.168 0.084 ;
    END
  END rx[250]
  PIN rx[251]
    DIRECTION INPUT ;
    USE SIGNAL ;
    PORT
      LAYER M5 ;
        RECT  66.384 0 66.408 0.084 ;
    END
  END rx[251]
  PIN rx[252]
    DIRECTION INPUT ;
    USE SIGNAL ;
    PORT
      LAYER M5 ;
        RECT  66.624 0 66.648 0.084 ;
    END
  END rx[252]
  PIN rx[253]
    DIRECTION INPUT ;
    USE SIGNAL ;
    PORT
      LAYER M5 ;
        RECT  66.864 0 66.888 0.084 ;
    END
  END rx[253]
  PIN rx[254]
    DIRECTION INPUT ;
    USE SIGNAL ;
    PORT
      LAYER M5 ;
        RECT  67.104 0 67.128 0.084 ;
    END
  END rx[254]
  PIN rx[255]
    DIRECTION INPUT ;
    USE SIGNAL ;
    PORT
      LAYER M5 ;
        RECT  67.344 0 67.368 0.084 ;
    END
  END rx[255]
  PIN rx[256]
    DIRECTION INPUT ;
    USE SIGNAL ;
    PORT
      LAYER M5 ;
        RECT  67.584 0 67.608 0.084 ;
    END
  END rx[256]
  PIN rx[257]
    DIRECTION INPUT ;
    USE SIGNAL ;
    PORT
      LAYER M5 ;
        RECT  67.824 0 67.848 0.084 ;
    END
  END rx[257]
  PIN rx[258]
    DIRECTION INPUT ;
    USE SIGNAL ;
    PORT
      LAYER M5 ;
        RECT  68.064 0 68.088 0.084 ;
    END
  END rx[258]
  PIN rx[259]
    DIRECTION INPUT ;
    USE SIGNAL ;
    PORT
      LAYER M5 ;
        RECT  68.304 0 68.328 0.084 ;
    END
  END rx[259]
  PIN rx[25]
    DIRECTION INPUT ;
    USE SIGNAL ;
    PORT
      LAYER M5 ;
        RECT  12.144 0 12.168 0.084 ;
    END
  END rx[25]
  PIN rx[260]
    DIRECTION INPUT ;
    USE SIGNAL ;
    PORT
      LAYER M5 ;
        RECT  68.544 0 68.568 0.084 ;
    END
  END rx[260]
  PIN rx[261]
    DIRECTION INPUT ;
    USE SIGNAL ;
    PORT
      LAYER M5 ;
        RECT  68.784 0 68.808 0.084 ;
    END
  END rx[261]
  PIN rx[262]
    DIRECTION INPUT ;
    USE SIGNAL ;
    PORT
      LAYER M5 ;
        RECT  69.024 0 69.048 0.084 ;
    END
  END rx[262]
  PIN rx[263]
    DIRECTION INPUT ;
    USE SIGNAL ;
    PORT
      LAYER M5 ;
        RECT  69.264 0 69.288 0.084 ;
    END
  END rx[263]
  PIN rx[264]
    DIRECTION INPUT ;
    USE SIGNAL ;
    PORT
      LAYER M5 ;
        RECT  69.504 0 69.528 0.084 ;
    END
  END rx[264]
  PIN rx[265]
    DIRECTION INPUT ;
    USE SIGNAL ;
    PORT
      LAYER M5 ;
        RECT  69.744 0 69.768 0.084 ;
    END
  END rx[265]
  PIN rx[266]
    DIRECTION INPUT ;
    USE SIGNAL ;
    PORT
      LAYER M5 ;
        RECT  69.984 0 70.008 0.084 ;
    END
  END rx[266]
  PIN rx[267]
    DIRECTION INPUT ;
    USE SIGNAL ;
    PORT
      LAYER M5 ;
        RECT  70.224 0 70.248 0.084 ;
    END
  END rx[267]
  PIN rx[268]
    DIRECTION INPUT ;
    USE SIGNAL ;
    PORT
      LAYER M5 ;
        RECT  70.464 0 70.488 0.084 ;
    END
  END rx[268]
  PIN rx[269]
    DIRECTION INPUT ;
    USE SIGNAL ;
    PORT
      LAYER M5 ;
        RECT  70.704 0 70.728 0.084 ;
    END
  END rx[269]
  PIN rx[26]
    DIRECTION INPUT ;
    USE SIGNAL ;
    PORT
      LAYER M5 ;
        RECT  12.384 0 12.408 0.084 ;
    END
  END rx[26]
  PIN rx[270]
    DIRECTION INPUT ;
    USE SIGNAL ;
    PORT
      LAYER M5 ;
        RECT  70.944 0 70.968 0.084 ;
    END
  END rx[270]
  PIN rx[271]
    DIRECTION INPUT ;
    USE SIGNAL ;
    PORT
      LAYER M5 ;
        RECT  71.184 0 71.208 0.084 ;
    END
  END rx[271]
  PIN rx[272]
    DIRECTION INPUT ;
    USE SIGNAL ;
    PORT
      LAYER M5 ;
        RECT  71.424 0 71.448 0.084 ;
    END
  END rx[272]
  PIN rx[273]
    DIRECTION INPUT ;
    USE SIGNAL ;
    PORT
      LAYER M5 ;
        RECT  71.664 0 71.688 0.084 ;
    END
  END rx[273]
  PIN rx[274]
    DIRECTION INPUT ;
    USE SIGNAL ;
    PORT
      LAYER M5 ;
        RECT  71.904 0 71.928 0.084 ;
    END
  END rx[274]
  PIN rx[275]
    DIRECTION INPUT ;
    USE SIGNAL ;
    PORT
      LAYER M5 ;
        RECT  72.144 0 72.168 0.084 ;
    END
  END rx[275]
  PIN rx[276]
    DIRECTION INPUT ;
    USE SIGNAL ;
    PORT
      LAYER M5 ;
        RECT  72.384 0 72.408 0.084 ;
    END
  END rx[276]
  PIN rx[277]
    DIRECTION INPUT ;
    USE SIGNAL ;
    PORT
      LAYER M5 ;
        RECT  72.624 0 72.648 0.084 ;
    END
  END rx[277]
  PIN rx[278]
    DIRECTION INPUT ;
    USE SIGNAL ;
    PORT
      LAYER M5 ;
        RECT  72.864 0 72.888 0.084 ;
    END
  END rx[278]
  PIN rx[279]
    DIRECTION INPUT ;
    USE SIGNAL ;
    PORT
      LAYER M5 ;
        RECT  73.104 0 73.128 0.084 ;
    END
  END rx[279]
  PIN rx[27]
    DIRECTION INPUT ;
    USE SIGNAL ;
    PORT
      LAYER M5 ;
        RECT  12.624 0 12.648 0.084 ;
    END
  END rx[27]
  PIN rx[280]
    DIRECTION INPUT ;
    USE SIGNAL ;
    PORT
      LAYER M5 ;
        RECT  73.344 0 73.368 0.084 ;
    END
  END rx[280]
  PIN rx[281]
    DIRECTION INPUT ;
    USE SIGNAL ;
    PORT
      LAYER M5 ;
        RECT  73.584 0 73.608 0.084 ;
    END
  END rx[281]
  PIN rx[282]
    DIRECTION INPUT ;
    USE SIGNAL ;
    PORT
      LAYER M5 ;
        RECT  73.824 0 73.848 0.084 ;
    END
  END rx[282]
  PIN rx[283]
    DIRECTION INPUT ;
    USE SIGNAL ;
    PORT
      LAYER M5 ;
        RECT  74.064 0 74.088 0.084 ;
    END
  END rx[283]
  PIN rx[284]
    DIRECTION INPUT ;
    USE SIGNAL ;
    PORT
      LAYER M5 ;
        RECT  74.304 0 74.328 0.084 ;
    END
  END rx[284]
  PIN rx[285]
    DIRECTION INPUT ;
    USE SIGNAL ;
    PORT
      LAYER M5 ;
        RECT  74.544 0 74.568 0.084 ;
    END
  END rx[285]
  PIN rx[286]
    DIRECTION INPUT ;
    USE SIGNAL ;
    PORT
      LAYER M5 ;
        RECT  74.784 0 74.808 0.084 ;
    END
  END rx[286]
  PIN rx[287]
    DIRECTION INPUT ;
    USE SIGNAL ;
    PORT
      LAYER M5 ;
        RECT  75.024 0 75.048 0.084 ;
    END
  END rx[287]
  PIN rx[288]
    DIRECTION INPUT ;
    USE SIGNAL ;
    PORT
      LAYER M5 ;
        RECT  75.264 0 75.288 0.084 ;
    END
  END rx[288]
  PIN rx[289]
    DIRECTION INPUT ;
    USE SIGNAL ;
    PORT
      LAYER M5 ;
        RECT  75.504 0 75.528 0.084 ;
    END
  END rx[289]
  PIN rx[28]
    DIRECTION INPUT ;
    USE SIGNAL ;
    PORT
      LAYER M5 ;
        RECT  12.864 0 12.888 0.084 ;
    END
  END rx[28]
  PIN rx[290]
    DIRECTION INPUT ;
    USE SIGNAL ;
    PORT
      LAYER M5 ;
        RECT  75.744 0 75.768 0.084 ;
    END
  END rx[290]
  PIN rx[291]
    DIRECTION INPUT ;
    USE SIGNAL ;
    PORT
      LAYER M5 ;
        RECT  75.984 0 76.008 0.084 ;
    END
  END rx[291]
  PIN rx[292]
    DIRECTION INPUT ;
    USE SIGNAL ;
    PORT
      LAYER M5 ;
        RECT  76.224 0 76.248 0.084 ;
    END
  END rx[292]
  PIN rx[293]
    DIRECTION INPUT ;
    USE SIGNAL ;
    PORT
      LAYER M5 ;
        RECT  76.464 0 76.488 0.084 ;
    END
  END rx[293]
  PIN rx[294]
    DIRECTION INPUT ;
    USE SIGNAL ;
    PORT
      LAYER M5 ;
        RECT  76.704 0 76.728 0.084 ;
    END
  END rx[294]
  PIN rx[295]
    DIRECTION INPUT ;
    USE SIGNAL ;
    PORT
      LAYER M5 ;
        RECT  76.944 0 76.968 0.084 ;
    END
  END rx[295]
  PIN rx[296]
    DIRECTION INPUT ;
    USE SIGNAL ;
    PORT
      LAYER M5 ;
        RECT  77.184 0 77.208 0.084 ;
    END
  END rx[296]
  PIN rx[297]
    DIRECTION INPUT ;
    USE SIGNAL ;
    PORT
      LAYER M5 ;
        RECT  77.424 0 77.448 0.084 ;
    END
  END rx[297]
  PIN rx[298]
    DIRECTION INPUT ;
    USE SIGNAL ;
    PORT
      LAYER M5 ;
        RECT  77.664 0 77.688 0.084 ;
    END
  END rx[298]
  PIN rx[299]
    DIRECTION INPUT ;
    USE SIGNAL ;
    PORT
      LAYER M5 ;
        RECT  77.904 0 77.928 0.084 ;
    END
  END rx[299]
  PIN rx[29]
    DIRECTION INPUT ;
    USE SIGNAL ;
    PORT
      LAYER M5 ;
        RECT  13.104 0 13.128 0.084 ;
    END
  END rx[29]
  PIN rx[2]
    DIRECTION INPUT ;
    USE SIGNAL ;
    PORT
      LAYER M5 ;
        RECT  6.624 0 6.648 0.084 ;
    END
  END rx[2]
  PIN rx[300]
    DIRECTION INPUT ;
    USE SIGNAL ;
    PORT
      LAYER M5 ;
        RECT  78.144 0 78.168 0.084 ;
    END
  END rx[300]
  PIN rx[301]
    DIRECTION INPUT ;
    USE SIGNAL ;
    PORT
      LAYER M5 ;
        RECT  78.384 0 78.408 0.084 ;
    END
  END rx[301]
  PIN rx[302]
    DIRECTION INPUT ;
    USE SIGNAL ;
    PORT
      LAYER M5 ;
        RECT  78.624 0 78.648 0.084 ;
    END
  END rx[302]
  PIN rx[303]
    DIRECTION INPUT ;
    USE SIGNAL ;
    PORT
      LAYER M5 ;
        RECT  78.864 0 78.888 0.084 ;
    END
  END rx[303]
  PIN rx[304]
    DIRECTION INPUT ;
    USE SIGNAL ;
    PORT
      LAYER M5 ;
        RECT  79.104 0 79.128 0.084 ;
    END
  END rx[304]
  PIN rx[305]
    DIRECTION INPUT ;
    USE SIGNAL ;
    PORT
      LAYER M5 ;
        RECT  79.344 0 79.368 0.084 ;
    END
  END rx[305]
  PIN rx[306]
    DIRECTION INPUT ;
    USE SIGNAL ;
    PORT
      LAYER M5 ;
        RECT  79.584 0 79.608 0.084 ;
    END
  END rx[306]
  PIN rx[307]
    DIRECTION INPUT ;
    USE SIGNAL ;
    PORT
      LAYER M5 ;
        RECT  79.824 0 79.848 0.084 ;
    END
  END rx[307]
  PIN rx[308]
    DIRECTION INPUT ;
    USE SIGNAL ;
    PORT
      LAYER M5 ;
        RECT  80.064 0 80.088 0.084 ;
    END
  END rx[308]
  PIN rx[309]
    DIRECTION INPUT ;
    USE SIGNAL ;
    PORT
      LAYER M5 ;
        RECT  80.304 0 80.328 0.084 ;
    END
  END rx[309]
  PIN rx[30]
    DIRECTION INPUT ;
    USE SIGNAL ;
    PORT
      LAYER M5 ;
        RECT  13.344 0 13.368 0.084 ;
    END
  END rx[30]
  PIN rx[310]
    DIRECTION INPUT ;
    USE SIGNAL ;
    PORT
      LAYER M5 ;
        RECT  80.544 0 80.568 0.084 ;
    END
  END rx[310]
  PIN rx[311]
    DIRECTION INPUT ;
    USE SIGNAL ;
    PORT
      LAYER M5 ;
        RECT  80.784 0 80.808 0.084 ;
    END
  END rx[311]
  PIN rx[312]
    DIRECTION INPUT ;
    USE SIGNAL ;
    PORT
      LAYER M5 ;
        RECT  81.024 0 81.048 0.084 ;
    END
  END rx[312]
  PIN rx[313]
    DIRECTION INPUT ;
    USE SIGNAL ;
    PORT
      LAYER M5 ;
        RECT  81.264 0 81.288 0.084 ;
    END
  END rx[313]
  PIN rx[314]
    DIRECTION INPUT ;
    USE SIGNAL ;
    PORT
      LAYER M5 ;
        RECT  81.504 0 81.528 0.084 ;
    END
  END rx[314]
  PIN rx[315]
    DIRECTION INPUT ;
    USE SIGNAL ;
    PORT
      LAYER M5 ;
        RECT  81.744 0 81.768 0.084 ;
    END
  END rx[315]
  PIN rx[316]
    DIRECTION INPUT ;
    USE SIGNAL ;
    PORT
      LAYER M5 ;
        RECT  81.984 0 82.008 0.084 ;
    END
  END rx[316]
  PIN rx[317]
    DIRECTION INPUT ;
    USE SIGNAL ;
    PORT
      LAYER M5 ;
        RECT  82.224 0 82.248 0.084 ;
    END
  END rx[317]
  PIN rx[318]
    DIRECTION INPUT ;
    USE SIGNAL ;
    PORT
      LAYER M5 ;
        RECT  82.464 0 82.488 0.084 ;
    END
  END rx[318]
  PIN rx[319]
    DIRECTION INPUT ;
    USE SIGNAL ;
    PORT
      LAYER M5 ;
        RECT  82.704 0 82.728 0.084 ;
    END
  END rx[319]
  PIN rx[31]
    DIRECTION INPUT ;
    USE SIGNAL ;
    PORT
      LAYER M5 ;
        RECT  13.584 0 13.608 0.084 ;
    END
  END rx[31]
  PIN rx[320]
    DIRECTION INPUT ;
    USE SIGNAL ;
    PORT
      LAYER M5 ;
        RECT  82.944 0 82.968 0.084 ;
    END
  END rx[320]
  PIN rx[321]
    DIRECTION INPUT ;
    USE SIGNAL ;
    PORT
      LAYER M5 ;
        RECT  83.184 0 83.208 0.084 ;
    END
  END rx[321]
  PIN rx[322]
    DIRECTION INPUT ;
    USE SIGNAL ;
    PORT
      LAYER M5 ;
        RECT  83.424 0 83.448 0.084 ;
    END
  END rx[322]
  PIN rx[323]
    DIRECTION INPUT ;
    USE SIGNAL ;
    PORT
      LAYER M5 ;
        RECT  83.664 0 83.688 0.084 ;
    END
  END rx[323]
  PIN rx[324]
    DIRECTION INPUT ;
    USE SIGNAL ;
    PORT
      LAYER M5 ;
        RECT  83.904 0 83.928 0.084 ;
    END
  END rx[324]
  PIN rx[325]
    DIRECTION INPUT ;
    USE SIGNAL ;
    PORT
      LAYER M5 ;
        RECT  84.144 0 84.168 0.084 ;
    END
  END rx[325]
  PIN rx[326]
    DIRECTION INPUT ;
    USE SIGNAL ;
    PORT
      LAYER M5 ;
        RECT  84.384 0 84.408 0.084 ;
    END
  END rx[326]
  PIN rx[327]
    DIRECTION INPUT ;
    USE SIGNAL ;
    PORT
      LAYER M5 ;
        RECT  84.624 0 84.648 0.084 ;
    END
  END rx[327]
  PIN rx[328]
    DIRECTION INPUT ;
    USE SIGNAL ;
    PORT
      LAYER M5 ;
        RECT  84.864 0 84.888 0.084 ;
    END
  END rx[328]
  PIN rx[329]
    DIRECTION INPUT ;
    USE SIGNAL ;
    PORT
      LAYER M5 ;
        RECT  85.104 0 85.128 0.084 ;
    END
  END rx[329]
  PIN rx[32]
    DIRECTION INPUT ;
    USE SIGNAL ;
    PORT
      LAYER M5 ;
        RECT  13.824 0 13.848 0.084 ;
    END
  END rx[32]
  PIN rx[330]
    DIRECTION INPUT ;
    USE SIGNAL ;
    PORT
      LAYER M5 ;
        RECT  85.344 0 85.368 0.084 ;
    END
  END rx[330]
  PIN rx[331]
    DIRECTION INPUT ;
    USE SIGNAL ;
    PORT
      LAYER M5 ;
        RECT  85.584 0 85.608 0.084 ;
    END
  END rx[331]
  PIN rx[332]
    DIRECTION INPUT ;
    USE SIGNAL ;
    PORT
      LAYER M5 ;
        RECT  85.824 0 85.848 0.084 ;
    END
  END rx[332]
  PIN rx[333]
    DIRECTION INPUT ;
    USE SIGNAL ;
    PORT
      LAYER M5 ;
        RECT  86.064 0 86.088 0.084 ;
    END
  END rx[333]
  PIN rx[334]
    DIRECTION INPUT ;
    USE SIGNAL ;
    PORT
      LAYER M5 ;
        RECT  86.304 0 86.328 0.084 ;
    END
  END rx[334]
  PIN rx[335]
    DIRECTION INPUT ;
    USE SIGNAL ;
    PORT
      LAYER M5 ;
        RECT  86.544 0 86.568 0.084 ;
    END
  END rx[335]
  PIN rx[336]
    DIRECTION INPUT ;
    USE SIGNAL ;
    PORT
      LAYER M5 ;
        RECT  86.784 0 86.808 0.084 ;
    END
  END rx[336]
  PIN rx[337]
    DIRECTION INPUT ;
    USE SIGNAL ;
    PORT
      LAYER M5 ;
        RECT  87.024 0 87.048 0.084 ;
    END
  END rx[337]
  PIN rx[338]
    DIRECTION INPUT ;
    USE SIGNAL ;
    PORT
      LAYER M5 ;
        RECT  87.264 0 87.288 0.084 ;
    END
  END rx[338]
  PIN rx[339]
    DIRECTION INPUT ;
    USE SIGNAL ;
    PORT
      LAYER M5 ;
        RECT  87.504 0 87.528 0.084 ;
    END
  END rx[339]
  PIN rx[33]
    DIRECTION INPUT ;
    USE SIGNAL ;
    PORT
      LAYER M5 ;
        RECT  14.064 0 14.088 0.084 ;
    END
  END rx[33]
  PIN rx[340]
    DIRECTION INPUT ;
    USE SIGNAL ;
    PORT
      LAYER M5 ;
        RECT  87.744 0 87.768 0.084 ;
    END
  END rx[340]
  PIN rx[341]
    DIRECTION INPUT ;
    USE SIGNAL ;
    PORT
      LAYER M5 ;
        RECT  87.984 0 88.008 0.084 ;
    END
  END rx[341]
  PIN rx[342]
    DIRECTION INPUT ;
    USE SIGNAL ;
    PORT
      LAYER M5 ;
        RECT  88.224 0 88.248 0.084 ;
    END
  END rx[342]
  PIN rx[343]
    DIRECTION INPUT ;
    USE SIGNAL ;
    PORT
      LAYER M5 ;
        RECT  88.464 0 88.488 0.084 ;
    END
  END rx[343]
  PIN rx[344]
    DIRECTION INPUT ;
    USE SIGNAL ;
    PORT
      LAYER M5 ;
        RECT  88.704 0 88.728 0.084 ;
    END
  END rx[344]
  PIN rx[345]
    DIRECTION INPUT ;
    USE SIGNAL ;
    PORT
      LAYER M5 ;
        RECT  88.944 0 88.968 0.084 ;
    END
  END rx[345]
  PIN rx[346]
    DIRECTION INPUT ;
    USE SIGNAL ;
    PORT
      LAYER M5 ;
        RECT  89.184 0 89.208 0.084 ;
    END
  END rx[346]
  PIN rx[347]
    DIRECTION INPUT ;
    USE SIGNAL ;
    PORT
      LAYER M5 ;
        RECT  89.424 0 89.448 0.084 ;
    END
  END rx[347]
  PIN rx[348]
    DIRECTION INPUT ;
    USE SIGNAL ;
    PORT
      LAYER M5 ;
        RECT  89.664 0 89.688 0.084 ;
    END
  END rx[348]
  PIN rx[349]
    DIRECTION INPUT ;
    USE SIGNAL ;
    PORT
      LAYER M5 ;
        RECT  89.904 0 89.928 0.084 ;
    END
  END rx[349]
  PIN rx[34]
    DIRECTION INPUT ;
    USE SIGNAL ;
    PORT
      LAYER M5 ;
        RECT  14.304 0 14.328 0.084 ;
    END
  END rx[34]
  PIN rx[350]
    DIRECTION INPUT ;
    USE SIGNAL ;
    PORT
      LAYER M5 ;
        RECT  90.144 0 90.168 0.084 ;
    END
  END rx[350]
  PIN rx[351]
    DIRECTION INPUT ;
    USE SIGNAL ;
    PORT
      LAYER M5 ;
        RECT  90.384 0 90.408 0.084 ;
    END
  END rx[351]
  PIN rx[352]
    DIRECTION INPUT ;
    USE SIGNAL ;
    PORT
      LAYER M5 ;
        RECT  90.624 0 90.648 0.084 ;
    END
  END rx[352]
  PIN rx[353]
    DIRECTION INPUT ;
    USE SIGNAL ;
    PORT
      LAYER M5 ;
        RECT  90.864 0 90.888 0.084 ;
    END
  END rx[353]
  PIN rx[354]
    DIRECTION INPUT ;
    USE SIGNAL ;
    PORT
      LAYER M5 ;
        RECT  91.104 0 91.128 0.084 ;
    END
  END rx[354]
  PIN rx[355]
    DIRECTION INPUT ;
    USE SIGNAL ;
    PORT
      LAYER M5 ;
        RECT  91.344 0 91.368 0.084 ;
    END
  END rx[355]
  PIN rx[356]
    DIRECTION INPUT ;
    USE SIGNAL ;
    PORT
      LAYER M5 ;
        RECT  91.584 0 91.608 0.084 ;
    END
  END rx[356]
  PIN rx[357]
    DIRECTION INPUT ;
    USE SIGNAL ;
    PORT
      LAYER M5 ;
        RECT  91.824 0 91.848 0.084 ;
    END
  END rx[357]
  PIN rx[358]
    DIRECTION INPUT ;
    USE SIGNAL ;
    PORT
      LAYER M5 ;
        RECT  92.064 0 92.088 0.084 ;
    END
  END rx[358]
  PIN rx[359]
    DIRECTION INPUT ;
    USE SIGNAL ;
    PORT
      LAYER M5 ;
        RECT  92.304 0 92.328 0.084 ;
    END
  END rx[359]
  PIN rx[35]
    DIRECTION INPUT ;
    USE SIGNAL ;
    PORT
      LAYER M5 ;
        RECT  14.544 0 14.568 0.084 ;
    END
  END rx[35]
  PIN rx[360]
    DIRECTION INPUT ;
    USE SIGNAL ;
    PORT
      LAYER M5 ;
        RECT  92.544 0 92.568 0.084 ;
    END
  END rx[360]
  PIN rx[361]
    DIRECTION INPUT ;
    USE SIGNAL ;
    PORT
      LAYER M5 ;
        RECT  92.784 0 92.808 0.084 ;
    END
  END rx[361]
  PIN rx[362]
    DIRECTION INPUT ;
    USE SIGNAL ;
    PORT
      LAYER M5 ;
        RECT  93.024 0 93.048 0.084 ;
    END
  END rx[362]
  PIN rx[363]
    DIRECTION INPUT ;
    USE SIGNAL ;
    PORT
      LAYER M5 ;
        RECT  93.264 0 93.288 0.084 ;
    END
  END rx[363]
  PIN rx[364]
    DIRECTION INPUT ;
    USE SIGNAL ;
    PORT
      LAYER M5 ;
        RECT  93.504 0 93.528 0.084 ;
    END
  END rx[364]
  PIN rx[365]
    DIRECTION INPUT ;
    USE SIGNAL ;
    PORT
      LAYER M5 ;
        RECT  93.744 0 93.768 0.084 ;
    END
  END rx[365]
  PIN rx[366]
    DIRECTION INPUT ;
    USE SIGNAL ;
    PORT
      LAYER M5 ;
        RECT  93.984 0 94.008 0.084 ;
    END
  END rx[366]
  PIN rx[367]
    DIRECTION INPUT ;
    USE SIGNAL ;
    PORT
      LAYER M5 ;
        RECT  94.224 0 94.248 0.084 ;
    END
  END rx[367]
  PIN rx[368]
    DIRECTION INPUT ;
    USE SIGNAL ;
    PORT
      LAYER M5 ;
        RECT  94.464 0 94.488 0.084 ;
    END
  END rx[368]
  PIN rx[369]
    DIRECTION INPUT ;
    USE SIGNAL ;
    PORT
      LAYER M5 ;
        RECT  94.704 0 94.728 0.084 ;
    END
  END rx[369]
  PIN rx[36]
    DIRECTION INPUT ;
    USE SIGNAL ;
    PORT
      LAYER M5 ;
        RECT  14.784 0 14.808 0.084 ;
    END
  END rx[36]
  PIN rx[370]
    DIRECTION INPUT ;
    USE SIGNAL ;
    PORT
      LAYER M5 ;
        RECT  94.944 0 94.968 0.084 ;
    END
  END rx[370]
  PIN rx[371]
    DIRECTION INPUT ;
    USE SIGNAL ;
    PORT
      LAYER M5 ;
        RECT  95.184 0 95.208 0.084 ;
    END
  END rx[371]
  PIN rx[372]
    DIRECTION INPUT ;
    USE SIGNAL ;
    PORT
      LAYER M5 ;
        RECT  95.424 0 95.448 0.084 ;
    END
  END rx[372]
  PIN rx[373]
    DIRECTION INPUT ;
    USE SIGNAL ;
    PORT
      LAYER M5 ;
        RECT  95.664 0 95.688 0.084 ;
    END
  END rx[373]
  PIN rx[374]
    DIRECTION INPUT ;
    USE SIGNAL ;
    PORT
      LAYER M5 ;
        RECT  95.904 0 95.928 0.084 ;
    END
  END rx[374]
  PIN rx[375]
    DIRECTION INPUT ;
    USE SIGNAL ;
    PORT
      LAYER M5 ;
        RECT  96.144 0 96.168 0.084 ;
    END
  END rx[375]
  PIN rx[376]
    DIRECTION INPUT ;
    USE SIGNAL ;
    PORT
      LAYER M5 ;
        RECT  96.384 0 96.408 0.084 ;
    END
  END rx[376]
  PIN rx[377]
    DIRECTION INPUT ;
    USE SIGNAL ;
    PORT
      LAYER M5 ;
        RECT  96.624 0 96.648 0.084 ;
    END
  END rx[377]
  PIN rx[378]
    DIRECTION INPUT ;
    USE SIGNAL ;
    PORT
      LAYER M5 ;
        RECT  96.864 0 96.888 0.084 ;
    END
  END rx[378]
  PIN rx[379]
    DIRECTION INPUT ;
    USE SIGNAL ;
    PORT
      LAYER M5 ;
        RECT  97.104 0 97.128 0.084 ;
    END
  END rx[379]
  PIN rx[37]
    DIRECTION INPUT ;
    USE SIGNAL ;
    PORT
      LAYER M5 ;
        RECT  15.024 0 15.048 0.084 ;
    END
  END rx[37]
  PIN rx[380]
    DIRECTION INPUT ;
    USE SIGNAL ;
    PORT
      LAYER M5 ;
        RECT  97.344 0 97.368 0.084 ;
    END
  END rx[380]
  PIN rx[381]
    DIRECTION INPUT ;
    USE SIGNAL ;
    PORT
      LAYER M5 ;
        RECT  97.584 0 97.608 0.084 ;
    END
  END rx[381]
  PIN rx[382]
    DIRECTION INPUT ;
    USE SIGNAL ;
    PORT
      LAYER M5 ;
        RECT  97.824 0 97.848 0.084 ;
    END
  END rx[382]
  PIN rx[383]
    DIRECTION INPUT ;
    USE SIGNAL ;
    PORT
      LAYER M5 ;
        RECT  98.064 0 98.088 0.084 ;
    END
  END rx[383]
  PIN rx[384]
    DIRECTION INPUT ;
    USE SIGNAL ;
    PORT
      LAYER M5 ;
        RECT  98.304 0 98.328 0.084 ;
    END
  END rx[384]
  PIN rx[385]
    DIRECTION INPUT ;
    USE SIGNAL ;
    PORT
      LAYER M5 ;
        RECT  98.544 0 98.568 0.084 ;
    END
  END rx[385]
  PIN rx[386]
    DIRECTION INPUT ;
    USE SIGNAL ;
    PORT
      LAYER M5 ;
        RECT  98.784 0 98.808 0.084 ;
    END
  END rx[386]
  PIN rx[387]
    DIRECTION INPUT ;
    USE SIGNAL ;
    PORT
      LAYER M5 ;
        RECT  99.024 0 99.048 0.084 ;
    END
  END rx[387]
  PIN rx[388]
    DIRECTION INPUT ;
    USE SIGNAL ;
    PORT
      LAYER M5 ;
        RECT  99.264 0 99.288 0.084 ;
    END
  END rx[388]
  PIN rx[389]
    DIRECTION INPUT ;
    USE SIGNAL ;
    PORT
      LAYER M5 ;
        RECT  99.504 0 99.528 0.084 ;
    END
  END rx[389]
  PIN rx[38]
    DIRECTION INPUT ;
    USE SIGNAL ;
    PORT
      LAYER M5 ;
        RECT  15.264 0 15.288 0.084 ;
    END
  END rx[38]
  PIN rx[390]
    DIRECTION INPUT ;
    USE SIGNAL ;
    PORT
      LAYER M5 ;
        RECT  99.744 0 99.768 0.084 ;
    END
  END rx[390]
  PIN rx[391]
    DIRECTION INPUT ;
    USE SIGNAL ;
    PORT
      LAYER M5 ;
        RECT  99.984 0 100.008 0.084 ;
    END
  END rx[391]
  PIN rx[392]
    DIRECTION INPUT ;
    USE SIGNAL ;
    PORT
      LAYER M5 ;
        RECT  100.224 0 100.248 0.084 ;
    END
  END rx[392]
  PIN rx[393]
    DIRECTION INPUT ;
    USE SIGNAL ;
    PORT
      LAYER M5 ;
        RECT  100.464 0 100.488 0.084 ;
    END
  END rx[393]
  PIN rx[394]
    DIRECTION INPUT ;
    USE SIGNAL ;
    PORT
      LAYER M5 ;
        RECT  100.704 0 100.728 0.084 ;
    END
  END rx[394]
  PIN rx[395]
    DIRECTION INPUT ;
    USE SIGNAL ;
    PORT
      LAYER M5 ;
        RECT  100.944 0 100.968 0.084 ;
    END
  END rx[395]
  PIN rx[396]
    DIRECTION INPUT ;
    USE SIGNAL ;
    PORT
      LAYER M5 ;
        RECT  101.184 0 101.208 0.084 ;
    END
  END rx[396]
  PIN rx[397]
    DIRECTION INPUT ;
    USE SIGNAL ;
    PORT
      LAYER M5 ;
        RECT  101.424 0 101.448 0.084 ;
    END
  END rx[397]
  PIN rx[398]
    DIRECTION INPUT ;
    USE SIGNAL ;
    PORT
      LAYER M5 ;
        RECT  101.664 0 101.688 0.084 ;
    END
  END rx[398]
  PIN rx[399]
    DIRECTION INPUT ;
    USE SIGNAL ;
    PORT
      LAYER M5 ;
        RECT  101.904 0 101.928 0.084 ;
    END
  END rx[399]
  PIN rx[39]
    DIRECTION INPUT ;
    USE SIGNAL ;
    PORT
      LAYER M5 ;
        RECT  15.504 0 15.528 0.084 ;
    END
  END rx[39]
  PIN rx[3]
    DIRECTION INPUT ;
    USE SIGNAL ;
    PORT
      LAYER M5 ;
        RECT  6.864 0 6.888 0.084 ;
    END
  END rx[3]
  PIN rx[400]
    DIRECTION INPUT ;
    USE SIGNAL ;
    PORT
      LAYER M5 ;
        RECT  102.144 0 102.168 0.084 ;
    END
  END rx[400]
  PIN rx[401]
    DIRECTION INPUT ;
    USE SIGNAL ;
    PORT
      LAYER M5 ;
        RECT  102.384 0 102.408 0.084 ;
    END
  END rx[401]
  PIN rx[402]
    DIRECTION INPUT ;
    USE SIGNAL ;
    PORT
      LAYER M5 ;
        RECT  102.624 0 102.648 0.084 ;
    END
  END rx[402]
  PIN rx[403]
    DIRECTION INPUT ;
    USE SIGNAL ;
    PORT
      LAYER M5 ;
        RECT  102.864 0 102.888 0.084 ;
    END
  END rx[403]
  PIN rx[404]
    DIRECTION INPUT ;
    USE SIGNAL ;
    PORT
      LAYER M5 ;
        RECT  103.104 0 103.128 0.084 ;
    END
  END rx[404]
  PIN rx[405]
    DIRECTION INPUT ;
    USE SIGNAL ;
    PORT
      LAYER M5 ;
        RECT  103.344 0 103.368 0.084 ;
    END
  END rx[405]
  PIN rx[406]
    DIRECTION INPUT ;
    USE SIGNAL ;
    PORT
      LAYER M5 ;
        RECT  103.584 0 103.608 0.084 ;
    END
  END rx[406]
  PIN rx[407]
    DIRECTION INPUT ;
    USE SIGNAL ;
    PORT
      LAYER M5 ;
        RECT  103.824 0 103.848 0.084 ;
    END
  END rx[407]
  PIN rx[408]
    DIRECTION INPUT ;
    USE SIGNAL ;
    PORT
      LAYER M5 ;
        RECT  104.064 0 104.088 0.084 ;
    END
  END rx[408]
  PIN rx[409]
    DIRECTION INPUT ;
    USE SIGNAL ;
    PORT
      LAYER M5 ;
        RECT  104.304 0 104.328 0.084 ;
    END
  END rx[409]
  PIN rx[40]
    DIRECTION INPUT ;
    USE SIGNAL ;
    PORT
      LAYER M5 ;
        RECT  15.744 0 15.768 0.084 ;
    END
  END rx[40]
  PIN rx[410]
    DIRECTION INPUT ;
    USE SIGNAL ;
    PORT
      LAYER M5 ;
        RECT  104.544 0 104.568 0.084 ;
    END
  END rx[410]
  PIN rx[411]
    DIRECTION INPUT ;
    USE SIGNAL ;
    PORT
      LAYER M5 ;
        RECT  104.784 0 104.808 0.084 ;
    END
  END rx[411]
  PIN rx[412]
    DIRECTION INPUT ;
    USE SIGNAL ;
    PORT
      LAYER M5 ;
        RECT  105.024 0 105.048 0.084 ;
    END
  END rx[412]
  PIN rx[413]
    DIRECTION INPUT ;
    USE SIGNAL ;
    PORT
      LAYER M5 ;
        RECT  105.264 0 105.288 0.084 ;
    END
  END rx[413]
  PIN rx[414]
    DIRECTION INPUT ;
    USE SIGNAL ;
    PORT
      LAYER M5 ;
        RECT  105.504 0 105.528 0.084 ;
    END
  END rx[414]
  PIN rx[415]
    DIRECTION INPUT ;
    USE SIGNAL ;
    PORT
      LAYER M5 ;
        RECT  105.744 0 105.768 0.084 ;
    END
  END rx[415]
  PIN rx[416]
    DIRECTION INPUT ;
    USE SIGNAL ;
    PORT
      LAYER M5 ;
        RECT  105.984 0 106.008 0.084 ;
    END
  END rx[416]
  PIN rx[417]
    DIRECTION INPUT ;
    USE SIGNAL ;
    PORT
      LAYER M5 ;
        RECT  106.224 0 106.248 0.084 ;
    END
  END rx[417]
  PIN rx[418]
    DIRECTION INPUT ;
    USE SIGNAL ;
    PORT
      LAYER M5 ;
        RECT  106.464 0 106.488 0.084 ;
    END
  END rx[418]
  PIN rx[419]
    DIRECTION INPUT ;
    USE SIGNAL ;
    PORT
      LAYER M5 ;
        RECT  106.704 0 106.728 0.084 ;
    END
  END rx[419]
  PIN rx[41]
    DIRECTION INPUT ;
    USE SIGNAL ;
    PORT
      LAYER M5 ;
        RECT  15.984 0 16.008 0.084 ;
    END
  END rx[41]
  PIN rx[420]
    DIRECTION INPUT ;
    USE SIGNAL ;
    PORT
      LAYER M5 ;
        RECT  106.944 0 106.968 0.084 ;
    END
  END rx[420]
  PIN rx[421]
    DIRECTION INPUT ;
    USE SIGNAL ;
    PORT
      LAYER M5 ;
        RECT  107.184 0 107.208 0.084 ;
    END
  END rx[421]
  PIN rx[422]
    DIRECTION INPUT ;
    USE SIGNAL ;
    PORT
      LAYER M5 ;
        RECT  107.424 0 107.448 0.084 ;
    END
  END rx[422]
  PIN rx[423]
    DIRECTION INPUT ;
    USE SIGNAL ;
    PORT
      LAYER M5 ;
        RECT  107.664 0 107.688 0.084 ;
    END
  END rx[423]
  PIN rx[424]
    DIRECTION INPUT ;
    USE SIGNAL ;
    PORT
      LAYER M5 ;
        RECT  107.904 0 107.928 0.084 ;
    END
  END rx[424]
  PIN rx[425]
    DIRECTION INPUT ;
    USE SIGNAL ;
    PORT
      LAYER M5 ;
        RECT  108.144 0 108.168 0.084 ;
    END
  END rx[425]
  PIN rx[426]
    DIRECTION INPUT ;
    USE SIGNAL ;
    PORT
      LAYER M5 ;
        RECT  108.384 0 108.408 0.084 ;
    END
  END rx[426]
  PIN rx[427]
    DIRECTION INPUT ;
    USE SIGNAL ;
    PORT
      LAYER M5 ;
        RECT  108.624 0 108.648 0.084 ;
    END
  END rx[427]
  PIN rx[428]
    DIRECTION INPUT ;
    USE SIGNAL ;
    PORT
      LAYER M5 ;
        RECT  108.864 0 108.888 0.084 ;
    END
  END rx[428]
  PIN rx[429]
    DIRECTION INPUT ;
    USE SIGNAL ;
    PORT
      LAYER M5 ;
        RECT  109.104 0 109.128 0.084 ;
    END
  END rx[429]
  PIN rx[42]
    DIRECTION INPUT ;
    USE SIGNAL ;
    PORT
      LAYER M5 ;
        RECT  16.224 0 16.248 0.084 ;
    END
  END rx[42]
  PIN rx[430]
    DIRECTION INPUT ;
    USE SIGNAL ;
    PORT
      LAYER M5 ;
        RECT  109.344 0 109.368 0.084 ;
    END
  END rx[430]
  PIN rx[431]
    DIRECTION INPUT ;
    USE SIGNAL ;
    PORT
      LAYER M5 ;
        RECT  109.584 0 109.608 0.084 ;
    END
  END rx[431]
  PIN rx[432]
    DIRECTION INPUT ;
    USE SIGNAL ;
    PORT
      LAYER M5 ;
        RECT  109.824 0 109.848 0.084 ;
    END
  END rx[432]
  PIN rx[433]
    DIRECTION INPUT ;
    USE SIGNAL ;
    PORT
      LAYER M5 ;
        RECT  110.064 0 110.088 0.084 ;
    END
  END rx[433]
  PIN rx[434]
    DIRECTION INPUT ;
    USE SIGNAL ;
    PORT
      LAYER M5 ;
        RECT  110.304 0 110.328 0.084 ;
    END
  END rx[434]
  PIN rx[435]
    DIRECTION INPUT ;
    USE SIGNAL ;
    PORT
      LAYER M5 ;
        RECT  110.544 0 110.568 0.084 ;
    END
  END rx[435]
  PIN rx[436]
    DIRECTION INPUT ;
    USE SIGNAL ;
    PORT
      LAYER M5 ;
        RECT  110.784 0 110.808 0.084 ;
    END
  END rx[436]
  PIN rx[437]
    DIRECTION INPUT ;
    USE SIGNAL ;
    PORT
      LAYER M5 ;
        RECT  111.024 0 111.048 0.084 ;
    END
  END rx[437]
  PIN rx[438]
    DIRECTION INPUT ;
    USE SIGNAL ;
    PORT
      LAYER M5 ;
        RECT  111.264 0 111.288 0.084 ;
    END
  END rx[438]
  PIN rx[439]
    DIRECTION INPUT ;
    USE SIGNAL ;
    PORT
      LAYER M5 ;
        RECT  111.504 0 111.528 0.084 ;
    END
  END rx[439]
  PIN rx[43]
    DIRECTION INPUT ;
    USE SIGNAL ;
    PORT
      LAYER M5 ;
        RECT  16.464 0 16.488 0.084 ;
    END
  END rx[43]
  PIN rx[440]
    DIRECTION INPUT ;
    USE SIGNAL ;
    PORT
      LAYER M5 ;
        RECT  111.744 0 111.768 0.084 ;
    END
  END rx[440]
  PIN rx[441]
    DIRECTION INPUT ;
    USE SIGNAL ;
    PORT
      LAYER M5 ;
        RECT  111.984 0 112.008 0.084 ;
    END
  END rx[441]
  PIN rx[442]
    DIRECTION INPUT ;
    USE SIGNAL ;
    PORT
      LAYER M5 ;
        RECT  112.224 0 112.248 0.084 ;
    END
  END rx[442]
  PIN rx[443]
    DIRECTION INPUT ;
    USE SIGNAL ;
    PORT
      LAYER M5 ;
        RECT  112.464 0 112.488 0.084 ;
    END
  END rx[443]
  PIN rx[444]
    DIRECTION INPUT ;
    USE SIGNAL ;
    PORT
      LAYER M5 ;
        RECT  112.704 0 112.728 0.084 ;
    END
  END rx[444]
  PIN rx[445]
    DIRECTION INPUT ;
    USE SIGNAL ;
    PORT
      LAYER M5 ;
        RECT  112.944 0 112.968 0.084 ;
    END
  END rx[445]
  PIN rx[446]
    DIRECTION INPUT ;
    USE SIGNAL ;
    PORT
      LAYER M5 ;
        RECT  113.184 0 113.208 0.084 ;
    END
  END rx[446]
  PIN rx[447]
    DIRECTION INPUT ;
    USE SIGNAL ;
    PORT
      LAYER M5 ;
        RECT  113.424 0 113.448 0.084 ;
    END
  END rx[447]
  PIN rx[448]
    DIRECTION INPUT ;
    USE SIGNAL ;
    PORT
      LAYER M5 ;
        RECT  113.664 0 113.688 0.084 ;
    END
  END rx[448]
  PIN rx[449]
    DIRECTION INPUT ;
    USE SIGNAL ;
    PORT
      LAYER M5 ;
        RECT  113.904 0 113.928 0.084 ;
    END
  END rx[449]
  PIN rx[44]
    DIRECTION INPUT ;
    USE SIGNAL ;
    PORT
      LAYER M5 ;
        RECT  16.704 0 16.728 0.084 ;
    END
  END rx[44]
  PIN rx[450]
    DIRECTION INPUT ;
    USE SIGNAL ;
    PORT
      LAYER M5 ;
        RECT  114.144 0 114.168 0.084 ;
    END
  END rx[450]
  PIN rx[451]
    DIRECTION INPUT ;
    USE SIGNAL ;
    PORT
      LAYER M5 ;
        RECT  114.384 0 114.408 0.084 ;
    END
  END rx[451]
  PIN rx[452]
    DIRECTION INPUT ;
    USE SIGNAL ;
    PORT
      LAYER M5 ;
        RECT  114.624 0 114.648 0.084 ;
    END
  END rx[452]
  PIN rx[453]
    DIRECTION INPUT ;
    USE SIGNAL ;
    PORT
      LAYER M5 ;
        RECT  114.864 0 114.888 0.084 ;
    END
  END rx[453]
  PIN rx[454]
    DIRECTION INPUT ;
    USE SIGNAL ;
    PORT
      LAYER M5 ;
        RECT  115.104 0 115.128 0.084 ;
    END
  END rx[454]
  PIN rx[455]
    DIRECTION INPUT ;
    USE SIGNAL ;
    PORT
      LAYER M5 ;
        RECT  115.344 0 115.368 0.084 ;
    END
  END rx[455]
  PIN rx[456]
    DIRECTION INPUT ;
    USE SIGNAL ;
    PORT
      LAYER M5 ;
        RECT  115.584 0 115.608 0.084 ;
    END
  END rx[456]
  PIN rx[457]
    DIRECTION INPUT ;
    USE SIGNAL ;
    PORT
      LAYER M5 ;
        RECT  115.824 0 115.848 0.084 ;
    END
  END rx[457]
  PIN rx[458]
    DIRECTION INPUT ;
    USE SIGNAL ;
    PORT
      LAYER M5 ;
        RECT  116.064 0 116.088 0.084 ;
    END
  END rx[458]
  PIN rx[459]
    DIRECTION INPUT ;
    USE SIGNAL ;
    PORT
      LAYER M5 ;
        RECT  116.304 0 116.328 0.084 ;
    END
  END rx[459]
  PIN rx[45]
    DIRECTION INPUT ;
    USE SIGNAL ;
    PORT
      LAYER M5 ;
        RECT  16.944 0 16.968 0.084 ;
    END
  END rx[45]
  PIN rx[460]
    DIRECTION INPUT ;
    USE SIGNAL ;
    PORT
      LAYER M5 ;
        RECT  116.544 0 116.568 0.084 ;
    END
  END rx[460]
  PIN rx[461]
    DIRECTION INPUT ;
    USE SIGNAL ;
    PORT
      LAYER M5 ;
        RECT  116.784 0 116.808 0.084 ;
    END
  END rx[461]
  PIN rx[462]
    DIRECTION INPUT ;
    USE SIGNAL ;
    PORT
      LAYER M5 ;
        RECT  117.024 0 117.048 0.084 ;
    END
  END rx[462]
  PIN rx[463]
    DIRECTION INPUT ;
    USE SIGNAL ;
    PORT
      LAYER M5 ;
        RECT  117.264 0 117.288 0.084 ;
    END
  END rx[463]
  PIN rx[464]
    DIRECTION INPUT ;
    USE SIGNAL ;
    PORT
      LAYER M5 ;
        RECT  117.504 0 117.528 0.084 ;
    END
  END rx[464]
  PIN rx[465]
    DIRECTION INPUT ;
    USE SIGNAL ;
    PORT
      LAYER M5 ;
        RECT  117.744 0 117.768 0.084 ;
    END
  END rx[465]
  PIN rx[466]
    DIRECTION INPUT ;
    USE SIGNAL ;
    PORT
      LAYER M5 ;
        RECT  117.984 0 118.008 0.084 ;
    END
  END rx[466]
  PIN rx[467]
    DIRECTION INPUT ;
    USE SIGNAL ;
    PORT
      LAYER M5 ;
        RECT  118.224 0 118.248 0.084 ;
    END
  END rx[467]
  PIN rx[468]
    DIRECTION INPUT ;
    USE SIGNAL ;
    PORT
      LAYER M5 ;
        RECT  118.464 0 118.488 0.084 ;
    END
  END rx[468]
  PIN rx[469]
    DIRECTION INPUT ;
    USE SIGNAL ;
    PORT
      LAYER M5 ;
        RECT  118.704 0 118.728 0.084 ;
    END
  END rx[469]
  PIN rx[46]
    DIRECTION INPUT ;
    USE SIGNAL ;
    PORT
      LAYER M5 ;
        RECT  17.184 0 17.208 0.084 ;
    END
  END rx[46]
  PIN rx[470]
    DIRECTION INPUT ;
    USE SIGNAL ;
    PORT
      LAYER M5 ;
        RECT  118.944 0 118.968 0.084 ;
    END
  END rx[470]
  PIN rx[471]
    DIRECTION INPUT ;
    USE SIGNAL ;
    PORT
      LAYER M5 ;
        RECT  119.184 0 119.208 0.084 ;
    END
  END rx[471]
  PIN rx[472]
    DIRECTION INPUT ;
    USE SIGNAL ;
    PORT
      LAYER M5 ;
        RECT  119.424 0 119.448 0.084 ;
    END
  END rx[472]
  PIN rx[473]
    DIRECTION INPUT ;
    USE SIGNAL ;
    PORT
      LAYER M5 ;
        RECT  119.664 0 119.688 0.084 ;
    END
  END rx[473]
  PIN rx[474]
    DIRECTION INPUT ;
    USE SIGNAL ;
    PORT
      LAYER M5 ;
        RECT  119.904 0 119.928 0.084 ;
    END
  END rx[474]
  PIN rx[475]
    DIRECTION INPUT ;
    USE SIGNAL ;
    PORT
      LAYER M5 ;
        RECT  120.144 0 120.168 0.084 ;
    END
  END rx[475]
  PIN rx[476]
    DIRECTION INPUT ;
    USE SIGNAL ;
    PORT
      LAYER M5 ;
        RECT  120.384 0 120.408 0.084 ;
    END
  END rx[476]
  PIN rx[477]
    DIRECTION INPUT ;
    USE SIGNAL ;
    PORT
      LAYER M5 ;
        RECT  120.624 0 120.648 0.084 ;
    END
  END rx[477]
  PIN rx[478]
    DIRECTION INPUT ;
    USE SIGNAL ;
    PORT
      LAYER M5 ;
        RECT  120.864 0 120.888 0.084 ;
    END
  END rx[478]
  PIN rx[479]
    DIRECTION INPUT ;
    USE SIGNAL ;
    PORT
      LAYER M5 ;
        RECT  121.104 0 121.128 0.084 ;
    END
  END rx[479]
  PIN rx[47]
    DIRECTION INPUT ;
    USE SIGNAL ;
    PORT
      LAYER M5 ;
        RECT  17.424 0 17.448 0.084 ;
    END
  END rx[47]
  PIN rx[480]
    DIRECTION INPUT ;
    USE SIGNAL ;
    PORT
      LAYER M5 ;
        RECT  121.344 0 121.368 0.084 ;
    END
  END rx[480]
  PIN rx[481]
    DIRECTION INPUT ;
    USE SIGNAL ;
    PORT
      LAYER M5 ;
        RECT  121.584 0 121.608 0.084 ;
    END
  END rx[481]
  PIN rx[482]
    DIRECTION INPUT ;
    USE SIGNAL ;
    PORT
      LAYER M5 ;
        RECT  121.824 0 121.848 0.084 ;
    END
  END rx[482]
  PIN rx[483]
    DIRECTION INPUT ;
    USE SIGNAL ;
    PORT
      LAYER M5 ;
        RECT  122.064 0 122.088 0.084 ;
    END
  END rx[483]
  PIN rx[484]
    DIRECTION INPUT ;
    USE SIGNAL ;
    PORT
      LAYER M5 ;
        RECT  122.304 0 122.328 0.084 ;
    END
  END rx[484]
  PIN rx[485]
    DIRECTION INPUT ;
    USE SIGNAL ;
    PORT
      LAYER M5 ;
        RECT  122.544 0 122.568 0.084 ;
    END
  END rx[485]
  PIN rx[486]
    DIRECTION INPUT ;
    USE SIGNAL ;
    PORT
      LAYER M5 ;
        RECT  122.784 0 122.808 0.084 ;
    END
  END rx[486]
  PIN rx[487]
    DIRECTION INPUT ;
    USE SIGNAL ;
    PORT
      LAYER M5 ;
        RECT  123.024 0 123.048 0.084 ;
    END
  END rx[487]
  PIN rx[488]
    DIRECTION INPUT ;
    USE SIGNAL ;
    PORT
      LAYER M5 ;
        RECT  123.264 0 123.288 0.084 ;
    END
  END rx[488]
  PIN rx[489]
    DIRECTION INPUT ;
    USE SIGNAL ;
    PORT
      LAYER M5 ;
        RECT  123.504 0 123.528 0.084 ;
    END
  END rx[489]
  PIN rx[48]
    DIRECTION INPUT ;
    USE SIGNAL ;
    PORT
      LAYER M5 ;
        RECT  17.664 0 17.688 0.084 ;
    END
  END rx[48]
  PIN rx[490]
    DIRECTION INPUT ;
    USE SIGNAL ;
    PORT
      LAYER M5 ;
        RECT  123.744 0 123.768 0.084 ;
    END
  END rx[490]
  PIN rx[491]
    DIRECTION INPUT ;
    USE SIGNAL ;
    PORT
      LAYER M5 ;
        RECT  123.984 0 124.008 0.084 ;
    END
  END rx[491]
  PIN rx[492]
    DIRECTION INPUT ;
    USE SIGNAL ;
    PORT
      LAYER M5 ;
        RECT  124.224 0 124.248 0.084 ;
    END
  END rx[492]
  PIN rx[493]
    DIRECTION INPUT ;
    USE SIGNAL ;
    PORT
      LAYER M5 ;
        RECT  124.464 0 124.488 0.084 ;
    END
  END rx[493]
  PIN rx[494]
    DIRECTION INPUT ;
    USE SIGNAL ;
    PORT
      LAYER M5 ;
        RECT  124.704 0 124.728 0.084 ;
    END
  END rx[494]
  PIN rx[495]
    DIRECTION INPUT ;
    USE SIGNAL ;
    PORT
      LAYER M5 ;
        RECT  124.944 0 124.968 0.084 ;
    END
  END rx[495]
  PIN rx[496]
    DIRECTION INPUT ;
    USE SIGNAL ;
    PORT
      LAYER M5 ;
        RECT  125.184 0 125.208 0.084 ;
    END
  END rx[496]
  PIN rx[497]
    DIRECTION INPUT ;
    USE SIGNAL ;
    PORT
      LAYER M5 ;
        RECT  125.424 0 125.448 0.084 ;
    END
  END rx[497]
  PIN rx[498]
    DIRECTION INPUT ;
    USE SIGNAL ;
    PORT
      LAYER M5 ;
        RECT  125.664 0 125.688 0.084 ;
    END
  END rx[498]
  PIN rx[499]
    DIRECTION INPUT ;
    USE SIGNAL ;
    PORT
      LAYER M5 ;
        RECT  125.904 0 125.928 0.084 ;
    END
  END rx[499]
  PIN rx[49]
    DIRECTION INPUT ;
    USE SIGNAL ;
    PORT
      LAYER M5 ;
        RECT  17.904 0 17.928 0.084 ;
    END
  END rx[49]
  PIN rx[4]
    DIRECTION INPUT ;
    USE SIGNAL ;
    PORT
      LAYER M5 ;
        RECT  7.104 0 7.128 0.084 ;
    END
  END rx[4]
  PIN rx[500]
    DIRECTION INPUT ;
    USE SIGNAL ;
    PORT
      LAYER M5 ;
        RECT  126.144 0 126.168 0.084 ;
    END
  END rx[500]
  PIN rx[501]
    DIRECTION INPUT ;
    USE SIGNAL ;
    PORT
      LAYER M5 ;
        RECT  126.384 0 126.408 0.084 ;
    END
  END rx[501]
  PIN rx[502]
    DIRECTION INPUT ;
    USE SIGNAL ;
    PORT
      LAYER M5 ;
        RECT  126.624 0 126.648 0.084 ;
    END
  END rx[502]
  PIN rx[503]
    DIRECTION INPUT ;
    USE SIGNAL ;
    PORT
      LAYER M5 ;
        RECT  126.864 0 126.888 0.084 ;
    END
  END rx[503]
  PIN rx[504]
    DIRECTION INPUT ;
    USE SIGNAL ;
    PORT
      LAYER M5 ;
        RECT  127.104 0 127.128 0.084 ;
    END
  END rx[504]
  PIN rx[505]
    DIRECTION INPUT ;
    USE SIGNAL ;
    PORT
      LAYER M5 ;
        RECT  127.344 0 127.368 0.084 ;
    END
  END rx[505]
  PIN rx[506]
    DIRECTION INPUT ;
    USE SIGNAL ;
    PORT
      LAYER M5 ;
        RECT  127.584 0 127.608 0.084 ;
    END
  END rx[506]
  PIN rx[507]
    DIRECTION INPUT ;
    USE SIGNAL ;
    PORT
      LAYER M5 ;
        RECT  127.824 0 127.848 0.084 ;
    END
  END rx[507]
  PIN rx[508]
    DIRECTION INPUT ;
    USE SIGNAL ;
    PORT
      LAYER M5 ;
        RECT  128.064 0 128.088 0.084 ;
    END
  END rx[508]
  PIN rx[509]
    DIRECTION INPUT ;
    USE SIGNAL ;
    PORT
      LAYER M5 ;
        RECT  128.304 0 128.328 0.084 ;
    END
  END rx[509]
  PIN rx[50]
    DIRECTION INPUT ;
    USE SIGNAL ;
    PORT
      LAYER M5 ;
        RECT  18.144 0 18.168 0.084 ;
    END
  END rx[50]
  PIN rx[510]
    DIRECTION INPUT ;
    USE SIGNAL ;
    PORT
      LAYER M5 ;
        RECT  128.544 0 128.568 0.084 ;
    END
  END rx[510]
  PIN rx[511]
    DIRECTION INPUT ;
    USE SIGNAL ;
    PORT
      LAYER M5 ;
        RECT  128.784 0 128.808 0.084 ;
    END
  END rx[511]
  PIN rx[512]
    DIRECTION INPUT ;
    USE SIGNAL ;
    PORT
      LAYER M5 ;
        RECT  129.024 0 129.048 0.084 ;
    END
  END rx[512]
  PIN rx[513]
    DIRECTION INPUT ;
    USE SIGNAL ;
    PORT
      LAYER M5 ;
        RECT  129.504 0 129.528 0.084 ;
    END
  END rx[513]
  PIN rx[514]
    DIRECTION INPUT ;
    USE SIGNAL ;
    PORT
      LAYER M5 ;
        RECT  129.264 0 129.288 0.084 ;
    END
  END rx[514]
  PIN rx[51]
    DIRECTION INPUT ;
    USE SIGNAL ;
    PORT
      LAYER M5 ;
        RECT  18.384 0 18.408 0.084 ;
    END
  END rx[51]
  PIN rx[52]
    DIRECTION INPUT ;
    USE SIGNAL ;
    PORT
      LAYER M5 ;
        RECT  18.624 0 18.648 0.084 ;
    END
  END rx[52]
  PIN rx[53]
    DIRECTION INPUT ;
    USE SIGNAL ;
    PORT
      LAYER M5 ;
        RECT  18.864 0 18.888 0.084 ;
    END
  END rx[53]
  PIN rx[54]
    DIRECTION INPUT ;
    USE SIGNAL ;
    PORT
      LAYER M5 ;
        RECT  19.104 0 19.128 0.084 ;
    END
  END rx[54]
  PIN rx[55]
    DIRECTION INPUT ;
    USE SIGNAL ;
    PORT
      LAYER M5 ;
        RECT  19.344 0 19.368 0.084 ;
    END
  END rx[55]
  PIN rx[56]
    DIRECTION INPUT ;
    USE SIGNAL ;
    PORT
      LAYER M5 ;
        RECT  19.584 0 19.608 0.084 ;
    END
  END rx[56]
  PIN rx[57]
    DIRECTION INPUT ;
    USE SIGNAL ;
    PORT
      LAYER M5 ;
        RECT  19.824 0 19.848 0.084 ;
    END
  END rx[57]
  PIN rx[58]
    DIRECTION INPUT ;
    USE SIGNAL ;
    PORT
      LAYER M5 ;
        RECT  20.064 0 20.088 0.084 ;
    END
  END rx[58]
  PIN rx[59]
    DIRECTION INPUT ;
    USE SIGNAL ;
    PORT
      LAYER M5 ;
        RECT  20.304 0 20.328 0.084 ;
    END
  END rx[59]
  PIN rx[5]
    DIRECTION INPUT ;
    USE SIGNAL ;
    PORT
      LAYER M5 ;
        RECT  7.344 0 7.368 0.084 ;
    END
  END rx[5]
  PIN rx[60]
    DIRECTION INPUT ;
    USE SIGNAL ;
    PORT
      LAYER M5 ;
        RECT  20.544 0 20.568 0.084 ;
    END
  END rx[60]
  PIN rx[61]
    DIRECTION INPUT ;
    USE SIGNAL ;
    PORT
      LAYER M5 ;
        RECT  20.784 0 20.808 0.084 ;
    END
  END rx[61]
  PIN rx[62]
    DIRECTION INPUT ;
    USE SIGNAL ;
    PORT
      LAYER M5 ;
        RECT  21.024 0 21.048 0.084 ;
    END
  END rx[62]
  PIN rx[63]
    DIRECTION INPUT ;
    USE SIGNAL ;
    PORT
      LAYER M5 ;
        RECT  21.264 0 21.288 0.084 ;
    END
  END rx[63]
  PIN rx[64]
    DIRECTION INPUT ;
    USE SIGNAL ;
    PORT
      LAYER M5 ;
        RECT  21.504 0 21.528 0.084 ;
    END
  END rx[64]
  PIN rx[65]
    DIRECTION INPUT ;
    USE SIGNAL ;
    PORT
      LAYER M5 ;
        RECT  21.744 0 21.768 0.084 ;
    END
  END rx[65]
  PIN rx[66]
    DIRECTION INPUT ;
    USE SIGNAL ;
    PORT
      LAYER M5 ;
        RECT  21.984 0 22.008 0.084 ;
    END
  END rx[66]
  PIN rx[67]
    DIRECTION INPUT ;
    USE SIGNAL ;
    PORT
      LAYER M5 ;
        RECT  22.224 0 22.248 0.084 ;
    END
  END rx[67]
  PIN rx[68]
    DIRECTION INPUT ;
    USE SIGNAL ;
    PORT
      LAYER M5 ;
        RECT  22.464 0 22.488 0.084 ;
    END
  END rx[68]
  PIN rx[69]
    DIRECTION INPUT ;
    USE SIGNAL ;
    PORT
      LAYER M5 ;
        RECT  22.704 0 22.728 0.084 ;
    END
  END rx[69]
  PIN rx[6]
    DIRECTION INPUT ;
    USE SIGNAL ;
    PORT
      LAYER M5 ;
        RECT  7.584 0 7.608 0.084 ;
    END
  END rx[6]
  PIN rx[70]
    DIRECTION INPUT ;
    USE SIGNAL ;
    PORT
      LAYER M5 ;
        RECT  22.944 0 22.968 0.084 ;
    END
  END rx[70]
  PIN rx[71]
    DIRECTION INPUT ;
    USE SIGNAL ;
    PORT
      LAYER M5 ;
        RECT  23.184 0 23.208 0.084 ;
    END
  END rx[71]
  PIN rx[72]
    DIRECTION INPUT ;
    USE SIGNAL ;
    PORT
      LAYER M5 ;
        RECT  23.424 0 23.448 0.084 ;
    END
  END rx[72]
  PIN rx[73]
    DIRECTION INPUT ;
    USE SIGNAL ;
    PORT
      LAYER M5 ;
        RECT  23.664 0 23.688 0.084 ;
    END
  END rx[73]
  PIN rx[74]
    DIRECTION INPUT ;
    USE SIGNAL ;
    PORT
      LAYER M5 ;
        RECT  23.904 0 23.928 0.084 ;
    END
  END rx[74]
  PIN rx[75]
    DIRECTION INPUT ;
    USE SIGNAL ;
    PORT
      LAYER M5 ;
        RECT  24.144 0 24.168 0.084 ;
    END
  END rx[75]
  PIN rx[76]
    DIRECTION INPUT ;
    USE SIGNAL ;
    PORT
      LAYER M5 ;
        RECT  24.384 0 24.408 0.084 ;
    END
  END rx[76]
  PIN rx[77]
    DIRECTION INPUT ;
    USE SIGNAL ;
    PORT
      LAYER M5 ;
        RECT  24.624 0 24.648 0.084 ;
    END
  END rx[77]
  PIN rx[78]
    DIRECTION INPUT ;
    USE SIGNAL ;
    PORT
      LAYER M5 ;
        RECT  24.864 0 24.888 0.084 ;
    END
  END rx[78]
  PIN rx[79]
    DIRECTION INPUT ;
    USE SIGNAL ;
    PORT
      LAYER M5 ;
        RECT  25.104 0 25.128 0.084 ;
    END
  END rx[79]
  PIN rx[7]
    DIRECTION INPUT ;
    USE SIGNAL ;
    PORT
      LAYER M5 ;
        RECT  7.824 0 7.848 0.084 ;
    END
  END rx[7]
  PIN rx[80]
    DIRECTION INPUT ;
    USE SIGNAL ;
    PORT
      LAYER M5 ;
        RECT  25.344 0 25.368 0.084 ;
    END
  END rx[80]
  PIN rx[81]
    DIRECTION INPUT ;
    USE SIGNAL ;
    PORT
      LAYER M5 ;
        RECT  25.584 0 25.608 0.084 ;
    END
  END rx[81]
  PIN rx[82]
    DIRECTION INPUT ;
    USE SIGNAL ;
    PORT
      LAYER M5 ;
        RECT  25.824 0 25.848 0.084 ;
    END
  END rx[82]
  PIN rx[83]
    DIRECTION INPUT ;
    USE SIGNAL ;
    PORT
      LAYER M5 ;
        RECT  26.064 0 26.088 0.084 ;
    END
  END rx[83]
  PIN rx[84]
    DIRECTION INPUT ;
    USE SIGNAL ;
    PORT
      LAYER M5 ;
        RECT  26.304 0 26.328 0.084 ;
    END
  END rx[84]
  PIN rx[85]
    DIRECTION INPUT ;
    USE SIGNAL ;
    PORT
      LAYER M5 ;
        RECT  26.544 0 26.568 0.084 ;
    END
  END rx[85]
  PIN rx[86]
    DIRECTION INPUT ;
    USE SIGNAL ;
    PORT
      LAYER M5 ;
        RECT  26.784 0 26.808 0.084 ;
    END
  END rx[86]
  PIN rx[87]
    DIRECTION INPUT ;
    USE SIGNAL ;
    PORT
      LAYER M5 ;
        RECT  27.024 0 27.048 0.084 ;
    END
  END rx[87]
  PIN rx[88]
    DIRECTION INPUT ;
    USE SIGNAL ;
    PORT
      LAYER M5 ;
        RECT  27.264 0 27.288 0.084 ;
    END
  END rx[88]
  PIN rx[89]
    DIRECTION INPUT ;
    USE SIGNAL ;
    PORT
      LAYER M5 ;
        RECT  27.504 0 27.528 0.084 ;
    END
  END rx[89]
  PIN rx[8]
    DIRECTION INPUT ;
    USE SIGNAL ;
    PORT
      LAYER M5 ;
        RECT  8.064 0 8.088 0.084 ;
    END
  END rx[8]
  PIN rx[90]
    DIRECTION INPUT ;
    USE SIGNAL ;
    PORT
      LAYER M5 ;
        RECT  27.744 0 27.768 0.084 ;
    END
  END rx[90]
  PIN rx[91]
    DIRECTION INPUT ;
    USE SIGNAL ;
    PORT
      LAYER M5 ;
        RECT  27.984 0 28.008 0.084 ;
    END
  END rx[91]
  PIN rx[92]
    DIRECTION INPUT ;
    USE SIGNAL ;
    PORT
      LAYER M5 ;
        RECT  28.224 0 28.248 0.084 ;
    END
  END rx[92]
  PIN rx[93]
    DIRECTION INPUT ;
    USE SIGNAL ;
    PORT
      LAYER M5 ;
        RECT  28.464 0 28.488 0.084 ;
    END
  END rx[93]
  PIN rx[94]
    DIRECTION INPUT ;
    USE SIGNAL ;
    PORT
      LAYER M5 ;
        RECT  28.704 0 28.728 0.084 ;
    END
  END rx[94]
  PIN rx[95]
    DIRECTION INPUT ;
    USE SIGNAL ;
    PORT
      LAYER M5 ;
        RECT  28.944 0 28.968 0.084 ;
    END
  END rx[95]
  PIN rx[96]
    DIRECTION INPUT ;
    USE SIGNAL ;
    PORT
      LAYER M5 ;
        RECT  29.184 0 29.208 0.084 ;
    END
  END rx[96]
  PIN rx[97]
    DIRECTION INPUT ;
    USE SIGNAL ;
    PORT
      LAYER M5 ;
        RECT  29.424 0 29.448 0.084 ;
    END
  END rx[97]
  PIN rx[98]
    DIRECTION INPUT ;
    USE SIGNAL ;
    PORT
      LAYER M5 ;
        RECT  29.664 0 29.688 0.084 ;
    END
  END rx[98]
  PIN rx[99]
    DIRECTION INPUT ;
    USE SIGNAL ;
    PORT
      LAYER M5 ;
        RECT  29.904 0 29.928 0.084 ;
    END
  END rx[99]
  PIN rx[9]
    DIRECTION INPUT ;
    USE SIGNAL ;
    PORT
      LAYER M5 ;
        RECT  8.304 0 8.328 0.084 ;
    END
  END rx[9]
  PIN tx[0]
    DIRECTION OUTPUT ;
    USE SIGNAL ;
    PORT
      LAYER M5 ;
        RECT  167.76 0 167.784 0.084 ;
    END
  END tx[0]
  PIN tx[100]
    DIRECTION OUTPUT ;
    USE SIGNAL ;
    PORT
      LAYER M5 ;
        RECT  191.76 0 191.784 0.084 ;
    END
  END tx[100]
  PIN tx[101]
    DIRECTION OUTPUT ;
    USE SIGNAL ;
    PORT
      LAYER M5 ;
        RECT  192 0 192.024 0.084 ;
    END
  END tx[101]
  PIN tx[102]
    DIRECTION OUTPUT ;
    USE SIGNAL ;
    PORT
      LAYER M5 ;
        RECT  192.24 0 192.264 0.084 ;
    END
  END tx[102]
  PIN tx[103]
    DIRECTION OUTPUT ;
    USE SIGNAL ;
    PORT
      LAYER M5 ;
        RECT  192.48 0 192.504 0.084 ;
    END
  END tx[103]
  PIN tx[104]
    DIRECTION OUTPUT ;
    USE SIGNAL ;
    PORT
      LAYER M5 ;
        RECT  192.72 0 192.744 0.084 ;
    END
  END tx[104]
  PIN tx[105]
    DIRECTION OUTPUT ;
    USE SIGNAL ;
    PORT
      LAYER M5 ;
        RECT  192.96 0 192.984 0.084 ;
    END
  END tx[105]
  PIN tx[106]
    DIRECTION OUTPUT ;
    USE SIGNAL ;
    PORT
      LAYER M5 ;
        RECT  193.2 0 193.224 0.084 ;
    END
  END tx[106]
  PIN tx[107]
    DIRECTION OUTPUT ;
    USE SIGNAL ;
    PORT
      LAYER M5 ;
        RECT  193.44 0 193.464 0.084 ;
    END
  END tx[107]
  PIN tx[108]
    DIRECTION OUTPUT ;
    USE SIGNAL ;
    PORT
      LAYER M5 ;
        RECT  193.68 0 193.704 0.084 ;
    END
  END tx[108]
  PIN tx[109]
    DIRECTION OUTPUT ;
    USE SIGNAL ;
    PORT
      LAYER M5 ;
        RECT  193.92 0 193.944 0.084 ;
    END
  END tx[109]
  PIN tx[10]
    DIRECTION OUTPUT ;
    USE SIGNAL ;
    PORT
      LAYER M5 ;
        RECT  170.16 0 170.184 0.084 ;
    END
  END tx[10]
  PIN tx[110]
    DIRECTION OUTPUT ;
    USE SIGNAL ;
    PORT
      LAYER M5 ;
        RECT  194.16 0 194.184 0.084 ;
    END
  END tx[110]
  PIN tx[111]
    DIRECTION OUTPUT ;
    USE SIGNAL ;
    PORT
      LAYER M5 ;
        RECT  194.4 0 194.424 0.084 ;
    END
  END tx[111]
  PIN tx[112]
    DIRECTION OUTPUT ;
    USE SIGNAL ;
    PORT
      LAYER M5 ;
        RECT  194.64 0 194.664 0.084 ;
    END
  END tx[112]
  PIN tx[113]
    DIRECTION OUTPUT ;
    USE SIGNAL ;
    PORT
      LAYER M5 ;
        RECT  194.88 0 194.904 0.084 ;
    END
  END tx[113]
  PIN tx[114]
    DIRECTION OUTPUT ;
    USE SIGNAL ;
    PORT
      LAYER M5 ;
        RECT  195.12 0 195.144 0.084 ;
    END
  END tx[114]
  PIN tx[115]
    DIRECTION OUTPUT ;
    USE SIGNAL ;
    PORT
      LAYER M5 ;
        RECT  195.36 0 195.384 0.084 ;
    END
  END tx[115]
  PIN tx[116]
    DIRECTION OUTPUT ;
    USE SIGNAL ;
    PORT
      LAYER M5 ;
        RECT  195.6 0 195.624 0.084 ;
    END
  END tx[116]
  PIN tx[117]
    DIRECTION OUTPUT ;
    USE SIGNAL ;
    PORT
      LAYER M5 ;
        RECT  195.84 0 195.864 0.084 ;
    END
  END tx[117]
  PIN tx[118]
    DIRECTION OUTPUT ;
    USE SIGNAL ;
    PORT
      LAYER M5 ;
        RECT  196.08 0 196.104 0.084 ;
    END
  END tx[118]
  PIN tx[119]
    DIRECTION OUTPUT ;
    USE SIGNAL ;
    PORT
      LAYER M5 ;
        RECT  196.32 0 196.344 0.084 ;
    END
  END tx[119]
  PIN tx[11]
    DIRECTION OUTPUT ;
    USE SIGNAL ;
    PORT
      LAYER M5 ;
        RECT  170.4 0 170.424 0.084 ;
    END
  END tx[11]
  PIN tx[120]
    DIRECTION OUTPUT ;
    USE SIGNAL ;
    PORT
      LAYER M5 ;
        RECT  196.56 0 196.584 0.084 ;
    END
  END tx[120]
  PIN tx[121]
    DIRECTION OUTPUT ;
    USE SIGNAL ;
    PORT
      LAYER M5 ;
        RECT  196.8 0 196.824 0.084 ;
    END
  END tx[121]
  PIN tx[122]
    DIRECTION OUTPUT ;
    USE SIGNAL ;
    PORT
      LAYER M5 ;
        RECT  197.04 0 197.064 0.084 ;
    END
  END tx[122]
  PIN tx[123]
    DIRECTION OUTPUT ;
    USE SIGNAL ;
    PORT
      LAYER M5 ;
        RECT  197.28 0 197.304 0.084 ;
    END
  END tx[123]
  PIN tx[124]
    DIRECTION OUTPUT ;
    USE SIGNAL ;
    PORT
      LAYER M5 ;
        RECT  197.52 0 197.544 0.084 ;
    END
  END tx[124]
  PIN tx[125]
    DIRECTION OUTPUT ;
    USE SIGNAL ;
    PORT
      LAYER M5 ;
        RECT  197.76 0 197.784 0.084 ;
    END
  END tx[125]
  PIN tx[126]
    DIRECTION OUTPUT ;
    USE SIGNAL ;
    PORT
      LAYER M5 ;
        RECT  198 0 198.024 0.084 ;
    END
  END tx[126]
  PIN tx[127]
    DIRECTION OUTPUT ;
    USE SIGNAL ;
    PORT
      LAYER M5 ;
        RECT  198.24 0 198.264 0.084 ;
    END
  END tx[127]
  PIN tx[128]
    DIRECTION OUTPUT ;
    USE SIGNAL ;
    PORT
      LAYER M5 ;
        RECT  198.48 0 198.504 0.084 ;
    END
  END tx[128]
  PIN tx[129]
    DIRECTION OUTPUT ;
    USE SIGNAL ;
    PORT
      LAYER M5 ;
        RECT  198.72 0 198.744 0.084 ;
    END
  END tx[129]
  PIN tx[12]
    DIRECTION OUTPUT ;
    USE SIGNAL ;
    PORT
      LAYER M5 ;
        RECT  170.64 0 170.664 0.084 ;
    END
  END tx[12]
  PIN tx[130]
    DIRECTION OUTPUT ;
    USE SIGNAL ;
    PORT
      LAYER M5 ;
        RECT  198.96 0 198.984 0.084 ;
    END
  END tx[130]
  PIN tx[131]
    DIRECTION OUTPUT ;
    USE SIGNAL ;
    PORT
      LAYER M5 ;
        RECT  199.2 0 199.224 0.084 ;
    END
  END tx[131]
  PIN tx[132]
    DIRECTION OUTPUT ;
    USE SIGNAL ;
    PORT
      LAYER M5 ;
        RECT  199.44 0 199.464 0.084 ;
    END
  END tx[132]
  PIN tx[133]
    DIRECTION OUTPUT ;
    USE SIGNAL ;
    PORT
      LAYER M5 ;
        RECT  199.68 0 199.704 0.084 ;
    END
  END tx[133]
  PIN tx[134]
    DIRECTION OUTPUT ;
    USE SIGNAL ;
    PORT
      LAYER M5 ;
        RECT  199.92 0 199.944 0.084 ;
    END
  END tx[134]
  PIN tx[135]
    DIRECTION OUTPUT ;
    USE SIGNAL ;
    PORT
      LAYER M5 ;
        RECT  200.16 0 200.184 0.084 ;
    END
  END tx[135]
  PIN tx[136]
    DIRECTION OUTPUT ;
    USE SIGNAL ;
    PORT
      LAYER M5 ;
        RECT  200.4 0 200.424 0.084 ;
    END
  END tx[136]
  PIN tx[137]
    DIRECTION OUTPUT ;
    USE SIGNAL ;
    PORT
      LAYER M5 ;
        RECT  200.64 0 200.664 0.084 ;
    END
  END tx[137]
  PIN tx[138]
    DIRECTION OUTPUT ;
    USE SIGNAL ;
    PORT
      LAYER M5 ;
        RECT  200.88 0 200.904 0.084 ;
    END
  END tx[138]
  PIN tx[139]
    DIRECTION OUTPUT ;
    USE SIGNAL ;
    PORT
      LAYER M5 ;
        RECT  201.12 0 201.144 0.084 ;
    END
  END tx[139]
  PIN tx[13]
    DIRECTION OUTPUT ;
    USE SIGNAL ;
    PORT
      LAYER M5 ;
        RECT  170.88 0 170.904 0.084 ;
    END
  END tx[13]
  PIN tx[140]
    DIRECTION OUTPUT ;
    USE SIGNAL ;
    PORT
      LAYER M5 ;
        RECT  201.36 0 201.384 0.084 ;
    END
  END tx[140]
  PIN tx[141]
    DIRECTION OUTPUT ;
    USE SIGNAL ;
    PORT
      LAYER M5 ;
        RECT  201.6 0 201.624 0.084 ;
    END
  END tx[141]
  PIN tx[142]
    DIRECTION OUTPUT ;
    USE SIGNAL ;
    PORT
      LAYER M5 ;
        RECT  201.84 0 201.864 0.084 ;
    END
  END tx[142]
  PIN tx[143]
    DIRECTION OUTPUT ;
    USE SIGNAL ;
    PORT
      LAYER M5 ;
        RECT  202.08 0 202.104 0.084 ;
    END
  END tx[143]
  PIN tx[144]
    DIRECTION OUTPUT ;
    USE SIGNAL ;
    PORT
      LAYER M5 ;
        RECT  202.32 0 202.344 0.084 ;
    END
  END tx[144]
  PIN tx[145]
    DIRECTION OUTPUT ;
    USE SIGNAL ;
    PORT
      LAYER M5 ;
        RECT  202.56 0 202.584 0.084 ;
    END
  END tx[145]
  PIN tx[146]
    DIRECTION OUTPUT ;
    USE SIGNAL ;
    PORT
      LAYER M5 ;
        RECT  202.8 0 202.824 0.084 ;
    END
  END tx[146]
  PIN tx[147]
    DIRECTION OUTPUT ;
    USE SIGNAL ;
    PORT
      LAYER M5 ;
        RECT  203.04 0 203.064 0.084 ;
    END
  END tx[147]
  PIN tx[148]
    DIRECTION OUTPUT ;
    USE SIGNAL ;
    PORT
      LAYER M5 ;
        RECT  203.28 0 203.304 0.084 ;
    END
  END tx[148]
  PIN tx[149]
    DIRECTION OUTPUT ;
    USE SIGNAL ;
    PORT
      LAYER M5 ;
        RECT  203.52 0 203.544 0.084 ;
    END
  END tx[149]
  PIN tx[14]
    DIRECTION OUTPUT ;
    USE SIGNAL ;
    PORT
      LAYER M5 ;
        RECT  171.12 0 171.144 0.084 ;
    END
  END tx[14]
  PIN tx[150]
    DIRECTION OUTPUT ;
    USE SIGNAL ;
    PORT
      LAYER M5 ;
        RECT  203.76 0 203.784 0.084 ;
    END
  END tx[150]
  PIN tx[151]
    DIRECTION OUTPUT ;
    USE SIGNAL ;
    PORT
      LAYER M5 ;
        RECT  204 0 204.024 0.084 ;
    END
  END tx[151]
  PIN tx[152]
    DIRECTION OUTPUT ;
    USE SIGNAL ;
    PORT
      LAYER M5 ;
        RECT  204.24 0 204.264 0.084 ;
    END
  END tx[152]
  PIN tx[153]
    DIRECTION OUTPUT ;
    USE SIGNAL ;
    PORT
      LAYER M5 ;
        RECT  204.48 0 204.504 0.084 ;
    END
  END tx[153]
  PIN tx[154]
    DIRECTION OUTPUT ;
    USE SIGNAL ;
    PORT
      LAYER M5 ;
        RECT  204.72 0 204.744 0.084 ;
    END
  END tx[154]
  PIN tx[155]
    DIRECTION OUTPUT ;
    USE SIGNAL ;
    PORT
      LAYER M5 ;
        RECT  204.96 0 204.984 0.084 ;
    END
  END tx[155]
  PIN tx[156]
    DIRECTION OUTPUT ;
    USE SIGNAL ;
    PORT
      LAYER M5 ;
        RECT  205.2 0 205.224 0.084 ;
    END
  END tx[156]
  PIN tx[157]
    DIRECTION OUTPUT ;
    USE SIGNAL ;
    PORT
      LAYER M5 ;
        RECT  205.44 0 205.464 0.084 ;
    END
  END tx[157]
  PIN tx[158]
    DIRECTION OUTPUT ;
    USE SIGNAL ;
    PORT
      LAYER M5 ;
        RECT  205.68 0 205.704 0.084 ;
    END
  END tx[158]
  PIN tx[159]
    DIRECTION OUTPUT ;
    USE SIGNAL ;
    PORT
      LAYER M5 ;
        RECT  205.92 0 205.944 0.084 ;
    END
  END tx[159]
  PIN tx[15]
    DIRECTION OUTPUT ;
    USE SIGNAL ;
    PORT
      LAYER M5 ;
        RECT  171.36 0 171.384 0.084 ;
    END
  END tx[15]
  PIN tx[160]
    DIRECTION OUTPUT ;
    USE SIGNAL ;
    PORT
      LAYER M5 ;
        RECT  206.16 0 206.184 0.084 ;
    END
  END tx[160]
  PIN tx[161]
    DIRECTION OUTPUT ;
    USE SIGNAL ;
    PORT
      LAYER M5 ;
        RECT  206.4 0 206.424 0.084 ;
    END
  END tx[161]
  PIN tx[162]
    DIRECTION OUTPUT ;
    USE SIGNAL ;
    PORT
      LAYER M5 ;
        RECT  206.64 0 206.664 0.084 ;
    END
  END tx[162]
  PIN tx[163]
    DIRECTION OUTPUT ;
    USE SIGNAL ;
    PORT
      LAYER M5 ;
        RECT  206.88 0 206.904 0.084 ;
    END
  END tx[163]
  PIN tx[164]
    DIRECTION OUTPUT ;
    USE SIGNAL ;
    PORT
      LAYER M5 ;
        RECT  207.12 0 207.144 0.084 ;
    END
  END tx[164]
  PIN tx[165]
    DIRECTION OUTPUT ;
    USE SIGNAL ;
    PORT
      LAYER M5 ;
        RECT  207.36 0 207.384 0.084 ;
    END
  END tx[165]
  PIN tx[166]
    DIRECTION OUTPUT ;
    USE SIGNAL ;
    PORT
      LAYER M5 ;
        RECT  207.6 0 207.624 0.084 ;
    END
  END tx[166]
  PIN tx[167]
    DIRECTION OUTPUT ;
    USE SIGNAL ;
    PORT
      LAYER M5 ;
        RECT  207.84 0 207.864 0.084 ;
    END
  END tx[167]
  PIN tx[168]
    DIRECTION OUTPUT ;
    USE SIGNAL ;
    PORT
      LAYER M5 ;
        RECT  208.08 0 208.104 0.084 ;
    END
  END tx[168]
  PIN tx[169]
    DIRECTION OUTPUT ;
    USE SIGNAL ;
    PORT
      LAYER M5 ;
        RECT  208.32 0 208.344 0.084 ;
    END
  END tx[169]
  PIN tx[16]
    DIRECTION OUTPUT ;
    USE SIGNAL ;
    PORT
      LAYER M5 ;
        RECT  171.6 0 171.624 0.084 ;
    END
  END tx[16]
  PIN tx[170]
    DIRECTION OUTPUT ;
    USE SIGNAL ;
    PORT
      LAYER M5 ;
        RECT  208.56 0 208.584 0.084 ;
    END
  END tx[170]
  PIN tx[171]
    DIRECTION OUTPUT ;
    USE SIGNAL ;
    PORT
      LAYER M5 ;
        RECT  208.8 0 208.824 0.084 ;
    END
  END tx[171]
  PIN tx[172]
    DIRECTION OUTPUT ;
    USE SIGNAL ;
    PORT
      LAYER M5 ;
        RECT  209.04 0 209.064 0.084 ;
    END
  END tx[172]
  PIN tx[173]
    DIRECTION OUTPUT ;
    USE SIGNAL ;
    PORT
      LAYER M5 ;
        RECT  209.28 0 209.304 0.084 ;
    END
  END tx[173]
  PIN tx[174]
    DIRECTION OUTPUT ;
    USE SIGNAL ;
    PORT
      LAYER M5 ;
        RECT  209.52 0 209.544 0.084 ;
    END
  END tx[174]
  PIN tx[175]
    DIRECTION OUTPUT ;
    USE SIGNAL ;
    PORT
      LAYER M5 ;
        RECT  209.76 0 209.784 0.084 ;
    END
  END tx[175]
  PIN tx[176]
    DIRECTION OUTPUT ;
    USE SIGNAL ;
    PORT
      LAYER M5 ;
        RECT  210 0 210.024 0.084 ;
    END
  END tx[176]
  PIN tx[177]
    DIRECTION OUTPUT ;
    USE SIGNAL ;
    PORT
      LAYER M5 ;
        RECT  210.24 0 210.264 0.084 ;
    END
  END tx[177]
  PIN tx[178]
    DIRECTION OUTPUT ;
    USE SIGNAL ;
    PORT
      LAYER M5 ;
        RECT  210.48 0 210.504 0.084 ;
    END
  END tx[178]
  PIN tx[179]
    DIRECTION OUTPUT ;
    USE SIGNAL ;
    PORT
      LAYER M5 ;
        RECT  210.72 0 210.744 0.084 ;
    END
  END tx[179]
  PIN tx[17]
    DIRECTION OUTPUT ;
    USE SIGNAL ;
    PORT
      LAYER M5 ;
        RECT  171.84 0 171.864 0.084 ;
    END
  END tx[17]
  PIN tx[180]
    DIRECTION OUTPUT ;
    USE SIGNAL ;
    PORT
      LAYER M5 ;
        RECT  210.96 0 210.984 0.084 ;
    END
  END tx[180]
  PIN tx[181]
    DIRECTION OUTPUT ;
    USE SIGNAL ;
    PORT
      LAYER M5 ;
        RECT  211.2 0 211.224 0.084 ;
    END
  END tx[181]
  PIN tx[182]
    DIRECTION OUTPUT ;
    USE SIGNAL ;
    PORT
      LAYER M5 ;
        RECT  211.44 0 211.464 0.084 ;
    END
  END tx[182]
  PIN tx[183]
    DIRECTION OUTPUT ;
    USE SIGNAL ;
    PORT
      LAYER M5 ;
        RECT  211.68 0 211.704 0.084 ;
    END
  END tx[183]
  PIN tx[184]
    DIRECTION OUTPUT ;
    USE SIGNAL ;
    PORT
      LAYER M5 ;
        RECT  211.92 0 211.944 0.084 ;
    END
  END tx[184]
  PIN tx[185]
    DIRECTION OUTPUT ;
    USE SIGNAL ;
    PORT
      LAYER M5 ;
        RECT  212.16 0 212.184 0.084 ;
    END
  END tx[185]
  PIN tx[186]
    DIRECTION OUTPUT ;
    USE SIGNAL ;
    PORT
      LAYER M5 ;
        RECT  212.4 0 212.424 0.084 ;
    END
  END tx[186]
  PIN tx[187]
    DIRECTION OUTPUT ;
    USE SIGNAL ;
    PORT
      LAYER M5 ;
        RECT  212.64 0 212.664 0.084 ;
    END
  END tx[187]
  PIN tx[188]
    DIRECTION OUTPUT ;
    USE SIGNAL ;
    PORT
      LAYER M5 ;
        RECT  212.88 0 212.904 0.084 ;
    END
  END tx[188]
  PIN tx[189]
    DIRECTION OUTPUT ;
    USE SIGNAL ;
    PORT
      LAYER M5 ;
        RECT  213.12 0 213.144 0.084 ;
    END
  END tx[189]
  PIN tx[18]
    DIRECTION OUTPUT ;
    USE SIGNAL ;
    PORT
      LAYER M5 ;
        RECT  172.08 0 172.104 0.084 ;
    END
  END tx[18]
  PIN tx[190]
    DIRECTION OUTPUT ;
    USE SIGNAL ;
    PORT
      LAYER M5 ;
        RECT  213.36 0 213.384 0.084 ;
    END
  END tx[190]
  PIN tx[191]
    DIRECTION OUTPUT ;
    USE SIGNAL ;
    PORT
      LAYER M5 ;
        RECT  213.6 0 213.624 0.084 ;
    END
  END tx[191]
  PIN tx[192]
    DIRECTION OUTPUT ;
    USE SIGNAL ;
    PORT
      LAYER M5 ;
        RECT  213.84 0 213.864 0.084 ;
    END
  END tx[192]
  PIN tx[193]
    DIRECTION OUTPUT ;
    USE SIGNAL ;
    PORT
      LAYER M5 ;
        RECT  214.08 0 214.104 0.084 ;
    END
  END tx[193]
  PIN tx[194]
    DIRECTION OUTPUT ;
    USE SIGNAL ;
    PORT
      LAYER M5 ;
        RECT  214.32 0 214.344 0.084 ;
    END
  END tx[194]
  PIN tx[195]
    DIRECTION OUTPUT ;
    USE SIGNAL ;
    PORT
      LAYER M5 ;
        RECT  214.56 0 214.584 0.084 ;
    END
  END tx[195]
  PIN tx[196]
    DIRECTION OUTPUT ;
    USE SIGNAL ;
    PORT
      LAYER M5 ;
        RECT  214.8 0 214.824 0.084 ;
    END
  END tx[196]
  PIN tx[197]
    DIRECTION OUTPUT ;
    USE SIGNAL ;
    PORT
      LAYER M5 ;
        RECT  215.04 0 215.064 0.084 ;
    END
  END tx[197]
  PIN tx[198]
    DIRECTION OUTPUT ;
    USE SIGNAL ;
    PORT
      LAYER M5 ;
        RECT  215.28 0 215.304 0.084 ;
    END
  END tx[198]
  PIN tx[199]
    DIRECTION OUTPUT ;
    USE SIGNAL ;
    PORT
      LAYER M5 ;
        RECT  215.52 0 215.544 0.084 ;
    END
  END tx[199]
  PIN tx[19]
    DIRECTION OUTPUT ;
    USE SIGNAL ;
    PORT
      LAYER M5 ;
        RECT  172.32 0 172.344 0.084 ;
    END
  END tx[19]
  PIN tx[1]
    DIRECTION OUTPUT ;
    USE SIGNAL ;
    PORT
      LAYER M5 ;
        RECT  168 0 168.024 0.084 ;
    END
  END tx[1]
  PIN tx[200]
    DIRECTION OUTPUT ;
    USE SIGNAL ;
    PORT
      LAYER M5 ;
        RECT  215.76 0 215.784 0.084 ;
    END
  END tx[200]
  PIN tx[201]
    DIRECTION OUTPUT ;
    USE SIGNAL ;
    PORT
      LAYER M5 ;
        RECT  216 0 216.024 0.084 ;
    END
  END tx[201]
  PIN tx[202]
    DIRECTION OUTPUT ;
    USE SIGNAL ;
    PORT
      LAYER M5 ;
        RECT  216.24 0 216.264 0.084 ;
    END
  END tx[202]
  PIN tx[203]
    DIRECTION OUTPUT ;
    USE SIGNAL ;
    PORT
      LAYER M5 ;
        RECT  216.48 0 216.504 0.084 ;
    END
  END tx[203]
  PIN tx[204]
    DIRECTION OUTPUT ;
    USE SIGNAL ;
    PORT
      LAYER M5 ;
        RECT  216.72 0 216.744 0.084 ;
    END
  END tx[204]
  PIN tx[205]
    DIRECTION OUTPUT ;
    USE SIGNAL ;
    PORT
      LAYER M5 ;
        RECT  216.96 0 216.984 0.084 ;
    END
  END tx[205]
  PIN tx[206]
    DIRECTION OUTPUT ;
    USE SIGNAL ;
    PORT
      LAYER M5 ;
        RECT  217.2 0 217.224 0.084 ;
    END
  END tx[206]
  PIN tx[207]
    DIRECTION OUTPUT ;
    USE SIGNAL ;
    PORT
      LAYER M5 ;
        RECT  217.44 0 217.464 0.084 ;
    END
  END tx[207]
  PIN tx[208]
    DIRECTION OUTPUT ;
    USE SIGNAL ;
    PORT
      LAYER M5 ;
        RECT  217.68 0 217.704 0.084 ;
    END
  END tx[208]
  PIN tx[209]
    DIRECTION OUTPUT ;
    USE SIGNAL ;
    PORT
      LAYER M5 ;
        RECT  217.92 0 217.944 0.084 ;
    END
  END tx[209]
  PIN tx[20]
    DIRECTION OUTPUT ;
    USE SIGNAL ;
    PORT
      LAYER M5 ;
        RECT  172.56 0 172.584 0.084 ;
    END
  END tx[20]
  PIN tx[210]
    DIRECTION OUTPUT ;
    USE SIGNAL ;
    PORT
      LAYER M5 ;
        RECT  218.16 0 218.184 0.084 ;
    END
  END tx[210]
  PIN tx[211]
    DIRECTION OUTPUT ;
    USE SIGNAL ;
    PORT
      LAYER M5 ;
        RECT  218.4 0 218.424 0.084 ;
    END
  END tx[211]
  PIN tx[212]
    DIRECTION OUTPUT ;
    USE SIGNAL ;
    PORT
      LAYER M5 ;
        RECT  218.64 0 218.664 0.084 ;
    END
  END tx[212]
  PIN tx[213]
    DIRECTION OUTPUT ;
    USE SIGNAL ;
    PORT
      LAYER M5 ;
        RECT  218.88 0 218.904 0.084 ;
    END
  END tx[213]
  PIN tx[214]
    DIRECTION OUTPUT ;
    USE SIGNAL ;
    PORT
      LAYER M5 ;
        RECT  219.12 0 219.144 0.084 ;
    END
  END tx[214]
  PIN tx[215]
    DIRECTION OUTPUT ;
    USE SIGNAL ;
    PORT
      LAYER M5 ;
        RECT  219.36 0 219.384 0.084 ;
    END
  END tx[215]
  PIN tx[216]
    DIRECTION OUTPUT ;
    USE SIGNAL ;
    PORT
      LAYER M5 ;
        RECT  219.6 0 219.624 0.084 ;
    END
  END tx[216]
  PIN tx[217]
    DIRECTION OUTPUT ;
    USE SIGNAL ;
    PORT
      LAYER M5 ;
        RECT  219.84 0 219.864 0.084 ;
    END
  END tx[217]
  PIN tx[218]
    DIRECTION OUTPUT ;
    USE SIGNAL ;
    PORT
      LAYER M5 ;
        RECT  220.08 0 220.104 0.084 ;
    END
  END tx[218]
  PIN tx[219]
    DIRECTION OUTPUT ;
    USE SIGNAL ;
    PORT
      LAYER M5 ;
        RECT  220.32 0 220.344 0.084 ;
    END
  END tx[219]
  PIN tx[21]
    DIRECTION OUTPUT ;
    USE SIGNAL ;
    PORT
      LAYER M5 ;
        RECT  172.8 0 172.824 0.084 ;
    END
  END tx[21]
  PIN tx[220]
    DIRECTION OUTPUT ;
    USE SIGNAL ;
    PORT
      LAYER M5 ;
        RECT  220.56 0 220.584 0.084 ;
    END
  END tx[220]
  PIN tx[221]
    DIRECTION OUTPUT ;
    USE SIGNAL ;
    PORT
      LAYER M5 ;
        RECT  220.8 0 220.824 0.084 ;
    END
  END tx[221]
  PIN tx[222]
    DIRECTION OUTPUT ;
    USE SIGNAL ;
    PORT
      LAYER M5 ;
        RECT  221.04 0 221.064 0.084 ;
    END
  END tx[222]
  PIN tx[223]
    DIRECTION OUTPUT ;
    USE SIGNAL ;
    PORT
      LAYER M5 ;
        RECT  221.28 0 221.304 0.084 ;
    END
  END tx[223]
  PIN tx[224]
    DIRECTION OUTPUT ;
    USE SIGNAL ;
    PORT
      LAYER M5 ;
        RECT  221.52 0 221.544 0.084 ;
    END
  END tx[224]
  PIN tx[225]
    DIRECTION OUTPUT ;
    USE SIGNAL ;
    PORT
      LAYER M5 ;
        RECT  221.76 0 221.784 0.084 ;
    END
  END tx[225]
  PIN tx[226]
    DIRECTION OUTPUT ;
    USE SIGNAL ;
    PORT
      LAYER M5 ;
        RECT  222 0 222.024 0.084 ;
    END
  END tx[226]
  PIN tx[227]
    DIRECTION OUTPUT ;
    USE SIGNAL ;
    PORT
      LAYER M5 ;
        RECT  222.24 0 222.264 0.084 ;
    END
  END tx[227]
  PIN tx[228]
    DIRECTION OUTPUT ;
    USE SIGNAL ;
    PORT
      LAYER M5 ;
        RECT  222.48 0 222.504 0.084 ;
    END
  END tx[228]
  PIN tx[229]
    DIRECTION OUTPUT ;
    USE SIGNAL ;
    PORT
      LAYER M5 ;
        RECT  222.72 0 222.744 0.084 ;
    END
  END tx[229]
  PIN tx[22]
    DIRECTION OUTPUT ;
    USE SIGNAL ;
    PORT
      LAYER M5 ;
        RECT  173.04 0 173.064 0.084 ;
    END
  END tx[22]
  PIN tx[230]
    DIRECTION OUTPUT ;
    USE SIGNAL ;
    PORT
      LAYER M5 ;
        RECT  222.96 0 222.984 0.084 ;
    END
  END tx[230]
  PIN tx[231]
    DIRECTION OUTPUT ;
    USE SIGNAL ;
    PORT
      LAYER M5 ;
        RECT  223.2 0 223.224 0.084 ;
    END
  END tx[231]
  PIN tx[232]
    DIRECTION OUTPUT ;
    USE SIGNAL ;
    PORT
      LAYER M5 ;
        RECT  223.44 0 223.464 0.084 ;
    END
  END tx[232]
  PIN tx[233]
    DIRECTION OUTPUT ;
    USE SIGNAL ;
    PORT
      LAYER M5 ;
        RECT  223.68 0 223.704 0.084 ;
    END
  END tx[233]
  PIN tx[234]
    DIRECTION OUTPUT ;
    USE SIGNAL ;
    PORT
      LAYER M5 ;
        RECT  223.92 0 223.944 0.084 ;
    END
  END tx[234]
  PIN tx[235]
    DIRECTION OUTPUT ;
    USE SIGNAL ;
    PORT
      LAYER M5 ;
        RECT  224.16 0 224.184 0.084 ;
    END
  END tx[235]
  PIN tx[236]
    DIRECTION OUTPUT ;
    USE SIGNAL ;
    PORT
      LAYER M5 ;
        RECT  224.4 0 224.424 0.084 ;
    END
  END tx[236]
  PIN tx[237]
    DIRECTION OUTPUT ;
    USE SIGNAL ;
    PORT
      LAYER M5 ;
        RECT  224.64 0 224.664 0.084 ;
    END
  END tx[237]
  PIN tx[238]
    DIRECTION OUTPUT ;
    USE SIGNAL ;
    PORT
      LAYER M5 ;
        RECT  224.88 0 224.904 0.084 ;
    END
  END tx[238]
  PIN tx[239]
    DIRECTION OUTPUT ;
    USE SIGNAL ;
    PORT
      LAYER M5 ;
        RECT  225.12 0 225.144 0.084 ;
    END
  END tx[239]
  PIN tx[23]
    DIRECTION OUTPUT ;
    USE SIGNAL ;
    PORT
      LAYER M5 ;
        RECT  173.28 0 173.304 0.084 ;
    END
  END tx[23]
  PIN tx[240]
    DIRECTION OUTPUT ;
    USE SIGNAL ;
    PORT
      LAYER M5 ;
        RECT  225.36 0 225.384 0.084 ;
    END
  END tx[240]
  PIN tx[241]
    DIRECTION OUTPUT ;
    USE SIGNAL ;
    PORT
      LAYER M5 ;
        RECT  225.6 0 225.624 0.084 ;
    END
  END tx[241]
  PIN tx[242]
    DIRECTION OUTPUT ;
    USE SIGNAL ;
    PORT
      LAYER M5 ;
        RECT  225.84 0 225.864 0.084 ;
    END
  END tx[242]
  PIN tx[243]
    DIRECTION OUTPUT ;
    USE SIGNAL ;
    PORT
      LAYER M5 ;
        RECT  226.08 0 226.104 0.084 ;
    END
  END tx[243]
  PIN tx[244]
    DIRECTION OUTPUT ;
    USE SIGNAL ;
    PORT
      LAYER M5 ;
        RECT  226.32 0 226.344 0.084 ;
    END
  END tx[244]
  PIN tx[245]
    DIRECTION OUTPUT ;
    USE SIGNAL ;
    PORT
      LAYER M5 ;
        RECT  226.56 0 226.584 0.084 ;
    END
  END tx[245]
  PIN tx[246]
    DIRECTION OUTPUT ;
    USE SIGNAL ;
    PORT
      LAYER M5 ;
        RECT  226.8 0 226.824 0.084 ;
    END
  END tx[246]
  PIN tx[247]
    DIRECTION OUTPUT ;
    USE SIGNAL ;
    PORT
      LAYER M5 ;
        RECT  227.04 0 227.064 0.084 ;
    END
  END tx[247]
  PIN tx[248]
    DIRECTION OUTPUT ;
    USE SIGNAL ;
    PORT
      LAYER M5 ;
        RECT  227.28 0 227.304 0.084 ;
    END
  END tx[248]
  PIN tx[249]
    DIRECTION OUTPUT ;
    USE SIGNAL ;
    PORT
      LAYER M5 ;
        RECT  227.52 0 227.544 0.084 ;
    END
  END tx[249]
  PIN tx[24]
    DIRECTION OUTPUT ;
    USE SIGNAL ;
    PORT
      LAYER M5 ;
        RECT  173.52 0 173.544 0.084 ;
    END
  END tx[24]
  PIN tx[250]
    DIRECTION OUTPUT ;
    USE SIGNAL ;
    PORT
      LAYER M5 ;
        RECT  227.76 0 227.784 0.084 ;
    END
  END tx[250]
  PIN tx[251]
    DIRECTION OUTPUT ;
    USE SIGNAL ;
    PORT
      LAYER M5 ;
        RECT  228 0 228.024 0.084 ;
    END
  END tx[251]
  PIN tx[252]
    DIRECTION OUTPUT ;
    USE SIGNAL ;
    PORT
      LAYER M5 ;
        RECT  228.24 0 228.264 0.084 ;
    END
  END tx[252]
  PIN tx[253]
    DIRECTION OUTPUT ;
    USE SIGNAL ;
    PORT
      LAYER M5 ;
        RECT  228.48 0 228.504 0.084 ;
    END
  END tx[253]
  PIN tx[254]
    DIRECTION OUTPUT ;
    USE SIGNAL ;
    PORT
      LAYER M5 ;
        RECT  228.72 0 228.744 0.084 ;
    END
  END tx[254]
  PIN tx[255]
    DIRECTION OUTPUT ;
    USE SIGNAL ;
    PORT
      LAYER M5 ;
        RECT  228.96 0 228.984 0.084 ;
    END
  END tx[255]
  PIN tx[256]
    DIRECTION OUTPUT ;
    USE SIGNAL ;
    PORT
      LAYER M5 ;
        RECT  229.2 0 229.224 0.084 ;
    END
  END tx[256]
  PIN tx[257]
    DIRECTION OUTPUT ;
    USE SIGNAL ;
    PORT
      LAYER M5 ;
        RECT  229.44 0 229.464 0.084 ;
    END
  END tx[257]
  PIN tx[258]
    DIRECTION OUTPUT ;
    USE SIGNAL ;
    PORT
      LAYER M5 ;
        RECT  229.68 0 229.704 0.084 ;
    END
  END tx[258]
  PIN tx[259]
    DIRECTION OUTPUT ;
    USE SIGNAL ;
    PORT
      LAYER M5 ;
        RECT  229.92 0 229.944 0.084 ;
    END
  END tx[259]
  PIN tx[25]
    DIRECTION OUTPUT ;
    USE SIGNAL ;
    PORT
      LAYER M5 ;
        RECT  173.76 0 173.784 0.084 ;
    END
  END tx[25]
  PIN tx[260]
    DIRECTION OUTPUT ;
    USE SIGNAL ;
    PORT
      LAYER M5 ;
        RECT  230.16 0 230.184 0.084 ;
    END
  END tx[260]
  PIN tx[261]
    DIRECTION OUTPUT ;
    USE SIGNAL ;
    PORT
      LAYER M5 ;
        RECT  230.4 0 230.424 0.084 ;
    END
  END tx[261]
  PIN tx[262]
    DIRECTION OUTPUT ;
    USE SIGNAL ;
    PORT
      LAYER M5 ;
        RECT  230.64 0 230.664 0.084 ;
    END
  END tx[262]
  PIN tx[263]
    DIRECTION OUTPUT ;
    USE SIGNAL ;
    PORT
      LAYER M5 ;
        RECT  230.88 0 230.904 0.084 ;
    END
  END tx[263]
  PIN tx[264]
    DIRECTION OUTPUT ;
    USE SIGNAL ;
    PORT
      LAYER M5 ;
        RECT  231.12 0 231.144 0.084 ;
    END
  END tx[264]
  PIN tx[265]
    DIRECTION OUTPUT ;
    USE SIGNAL ;
    PORT
      LAYER M5 ;
        RECT  231.36 0 231.384 0.084 ;
    END
  END tx[265]
  PIN tx[266]
    DIRECTION OUTPUT ;
    USE SIGNAL ;
    PORT
      LAYER M5 ;
        RECT  231.6 0 231.624 0.084 ;
    END
  END tx[266]
  PIN tx[267]
    DIRECTION OUTPUT ;
    USE SIGNAL ;
    PORT
      LAYER M5 ;
        RECT  231.84 0 231.864 0.084 ;
    END
  END tx[267]
  PIN tx[268]
    DIRECTION OUTPUT ;
    USE SIGNAL ;
    PORT
      LAYER M5 ;
        RECT  232.08 0 232.104 0.084 ;
    END
  END tx[268]
  PIN tx[269]
    DIRECTION OUTPUT ;
    USE SIGNAL ;
    PORT
      LAYER M5 ;
        RECT  232.32 0 232.344 0.084 ;
    END
  END tx[269]
  PIN tx[26]
    DIRECTION OUTPUT ;
    USE SIGNAL ;
    PORT
      LAYER M5 ;
        RECT  174 0 174.024 0.084 ;
    END
  END tx[26]
  PIN tx[270]
    DIRECTION OUTPUT ;
    USE SIGNAL ;
    PORT
      LAYER M5 ;
        RECT  232.56 0 232.584 0.084 ;
    END
  END tx[270]
  PIN tx[271]
    DIRECTION OUTPUT ;
    USE SIGNAL ;
    PORT
      LAYER M5 ;
        RECT  232.8 0 232.824 0.084 ;
    END
  END tx[271]
  PIN tx[272]
    DIRECTION OUTPUT ;
    USE SIGNAL ;
    PORT
      LAYER M5 ;
        RECT  233.04 0 233.064 0.084 ;
    END
  END tx[272]
  PIN tx[273]
    DIRECTION OUTPUT ;
    USE SIGNAL ;
    PORT
      LAYER M5 ;
        RECT  233.28 0 233.304 0.084 ;
    END
  END tx[273]
  PIN tx[274]
    DIRECTION OUTPUT ;
    USE SIGNAL ;
    PORT
      LAYER M5 ;
        RECT  233.52 0 233.544 0.084 ;
    END
  END tx[274]
  PIN tx[275]
    DIRECTION OUTPUT ;
    USE SIGNAL ;
    PORT
      LAYER M5 ;
        RECT  233.76 0 233.784 0.084 ;
    END
  END tx[275]
  PIN tx[276]
    DIRECTION OUTPUT ;
    USE SIGNAL ;
    PORT
      LAYER M5 ;
        RECT  234 0 234.024 0.084 ;
    END
  END tx[276]
  PIN tx[277]
    DIRECTION OUTPUT ;
    USE SIGNAL ;
    PORT
      LAYER M5 ;
        RECT  234.24 0 234.264 0.084 ;
    END
  END tx[277]
  PIN tx[278]
    DIRECTION OUTPUT ;
    USE SIGNAL ;
    PORT
      LAYER M5 ;
        RECT  234.48 0 234.504 0.084 ;
    END
  END tx[278]
  PIN tx[279]
    DIRECTION OUTPUT ;
    USE SIGNAL ;
    PORT
      LAYER M5 ;
        RECT  234.72 0 234.744 0.084 ;
    END
  END tx[279]
  PIN tx[27]
    DIRECTION OUTPUT ;
    USE SIGNAL ;
    PORT
      LAYER M5 ;
        RECT  174.24 0 174.264 0.084 ;
    END
  END tx[27]
  PIN tx[280]
    DIRECTION OUTPUT ;
    USE SIGNAL ;
    PORT
      LAYER M5 ;
        RECT  234.96 0 234.984 0.084 ;
    END
  END tx[280]
  PIN tx[281]
    DIRECTION OUTPUT ;
    USE SIGNAL ;
    PORT
      LAYER M5 ;
        RECT  235.2 0 235.224 0.084 ;
    END
  END tx[281]
  PIN tx[282]
    DIRECTION OUTPUT ;
    USE SIGNAL ;
    PORT
      LAYER M5 ;
        RECT  235.44 0 235.464 0.084 ;
    END
  END tx[282]
  PIN tx[283]
    DIRECTION OUTPUT ;
    USE SIGNAL ;
    PORT
      LAYER M5 ;
        RECT  235.68 0 235.704 0.084 ;
    END
  END tx[283]
  PIN tx[284]
    DIRECTION OUTPUT ;
    USE SIGNAL ;
    PORT
      LAYER M5 ;
        RECT  235.92 0 235.944 0.084 ;
    END
  END tx[284]
  PIN tx[285]
    DIRECTION OUTPUT ;
    USE SIGNAL ;
    PORT
      LAYER M5 ;
        RECT  236.16 0 236.184 0.084 ;
    END
  END tx[285]
  PIN tx[286]
    DIRECTION OUTPUT ;
    USE SIGNAL ;
    PORT
      LAYER M5 ;
        RECT  236.4 0 236.424 0.084 ;
    END
  END tx[286]
  PIN tx[287]
    DIRECTION OUTPUT ;
    USE SIGNAL ;
    PORT
      LAYER M5 ;
        RECT  236.64 0 236.664 0.084 ;
    END
  END tx[287]
  PIN tx[288]
    DIRECTION OUTPUT ;
    USE SIGNAL ;
    PORT
      LAYER M5 ;
        RECT  236.88 0 236.904 0.084 ;
    END
  END tx[288]
  PIN tx[289]
    DIRECTION OUTPUT ;
    USE SIGNAL ;
    PORT
      LAYER M5 ;
        RECT  237.12 0 237.144 0.084 ;
    END
  END tx[289]
  PIN tx[28]
    DIRECTION OUTPUT ;
    USE SIGNAL ;
    PORT
      LAYER M5 ;
        RECT  174.48 0 174.504 0.084 ;
    END
  END tx[28]
  PIN tx[290]
    DIRECTION OUTPUT ;
    USE SIGNAL ;
    PORT
      LAYER M5 ;
        RECT  237.36 0 237.384 0.084 ;
    END
  END tx[290]
  PIN tx[291]
    DIRECTION OUTPUT ;
    USE SIGNAL ;
    PORT
      LAYER M5 ;
        RECT  237.6 0 237.624 0.084 ;
    END
  END tx[291]
  PIN tx[292]
    DIRECTION OUTPUT ;
    USE SIGNAL ;
    PORT
      LAYER M5 ;
        RECT  237.84 0 237.864 0.084 ;
    END
  END tx[292]
  PIN tx[293]
    DIRECTION OUTPUT ;
    USE SIGNAL ;
    PORT
      LAYER M5 ;
        RECT  238.08 0 238.104 0.084 ;
    END
  END tx[293]
  PIN tx[294]
    DIRECTION OUTPUT ;
    USE SIGNAL ;
    PORT
      LAYER M5 ;
        RECT  238.32 0 238.344 0.084 ;
    END
  END tx[294]
  PIN tx[295]
    DIRECTION OUTPUT ;
    USE SIGNAL ;
    PORT
      LAYER M5 ;
        RECT  238.56 0 238.584 0.084 ;
    END
  END tx[295]
  PIN tx[296]
    DIRECTION OUTPUT ;
    USE SIGNAL ;
    PORT
      LAYER M5 ;
        RECT  238.8 0 238.824 0.084 ;
    END
  END tx[296]
  PIN tx[297]
    DIRECTION OUTPUT ;
    USE SIGNAL ;
    PORT
      LAYER M5 ;
        RECT  239.04 0 239.064 0.084 ;
    END
  END tx[297]
  PIN tx[298]
    DIRECTION OUTPUT ;
    USE SIGNAL ;
    PORT
      LAYER M5 ;
        RECT  239.28 0 239.304 0.084 ;
    END
  END tx[298]
  PIN tx[299]
    DIRECTION OUTPUT ;
    USE SIGNAL ;
    PORT
      LAYER M5 ;
        RECT  239.52 0 239.544 0.084 ;
    END
  END tx[299]
  PIN tx[29]
    DIRECTION OUTPUT ;
    USE SIGNAL ;
    PORT
      LAYER M5 ;
        RECT  174.72 0 174.744 0.084 ;
    END
  END tx[29]
  PIN tx[2]
    DIRECTION OUTPUT ;
    USE SIGNAL ;
    PORT
      LAYER M5 ;
        RECT  168.24 0 168.264 0.084 ;
    END
  END tx[2]
  PIN tx[300]
    DIRECTION OUTPUT ;
    USE SIGNAL ;
    PORT
      LAYER M5 ;
        RECT  239.76 0 239.784 0.084 ;
    END
  END tx[300]
  PIN tx[301]
    DIRECTION OUTPUT ;
    USE SIGNAL ;
    PORT
      LAYER M5 ;
        RECT  240 0 240.024 0.084 ;
    END
  END tx[301]
  PIN tx[302]
    DIRECTION OUTPUT ;
    USE SIGNAL ;
    PORT
      LAYER M5 ;
        RECT  240.24 0 240.264 0.084 ;
    END
  END tx[302]
  PIN tx[303]
    DIRECTION OUTPUT ;
    USE SIGNAL ;
    PORT
      LAYER M5 ;
        RECT  240.48 0 240.504 0.084 ;
    END
  END tx[303]
  PIN tx[304]
    DIRECTION OUTPUT ;
    USE SIGNAL ;
    PORT
      LAYER M5 ;
        RECT  240.72 0 240.744 0.084 ;
    END
  END tx[304]
  PIN tx[305]
    DIRECTION OUTPUT ;
    USE SIGNAL ;
    PORT
      LAYER M5 ;
        RECT  240.96 0 240.984 0.084 ;
    END
  END tx[305]
  PIN tx[306]
    DIRECTION OUTPUT ;
    USE SIGNAL ;
    PORT
      LAYER M5 ;
        RECT  241.2 0 241.224 0.084 ;
    END
  END tx[306]
  PIN tx[307]
    DIRECTION OUTPUT ;
    USE SIGNAL ;
    PORT
      LAYER M5 ;
        RECT  241.44 0 241.464 0.084 ;
    END
  END tx[307]
  PIN tx[308]
    DIRECTION OUTPUT ;
    USE SIGNAL ;
    PORT
      LAYER M5 ;
        RECT  241.68 0 241.704 0.084 ;
    END
  END tx[308]
  PIN tx[309]
    DIRECTION OUTPUT ;
    USE SIGNAL ;
    PORT
      LAYER M5 ;
        RECT  241.92 0 241.944 0.084 ;
    END
  END tx[309]
  PIN tx[30]
    DIRECTION OUTPUT ;
    USE SIGNAL ;
    PORT
      LAYER M5 ;
        RECT  174.96 0 174.984 0.084 ;
    END
  END tx[30]
  PIN tx[310]
    DIRECTION OUTPUT ;
    USE SIGNAL ;
    PORT
      LAYER M5 ;
        RECT  242.16 0 242.184 0.084 ;
    END
  END tx[310]
  PIN tx[311]
    DIRECTION OUTPUT ;
    USE SIGNAL ;
    PORT
      LAYER M5 ;
        RECT  242.4 0 242.424 0.084 ;
    END
  END tx[311]
  PIN tx[312]
    DIRECTION OUTPUT ;
    USE SIGNAL ;
    PORT
      LAYER M5 ;
        RECT  242.64 0 242.664 0.084 ;
    END
  END tx[312]
  PIN tx[313]
    DIRECTION OUTPUT ;
    USE SIGNAL ;
    PORT
      LAYER M5 ;
        RECT  242.88 0 242.904 0.084 ;
    END
  END tx[313]
  PIN tx[314]
    DIRECTION OUTPUT ;
    USE SIGNAL ;
    PORT
      LAYER M5 ;
        RECT  243.12 0 243.144 0.084 ;
    END
  END tx[314]
  PIN tx[315]
    DIRECTION OUTPUT ;
    USE SIGNAL ;
    PORT
      LAYER M5 ;
        RECT  243.36 0 243.384 0.084 ;
    END
  END tx[315]
  PIN tx[316]
    DIRECTION OUTPUT ;
    USE SIGNAL ;
    PORT
      LAYER M5 ;
        RECT  243.6 0 243.624 0.084 ;
    END
  END tx[316]
  PIN tx[317]
    DIRECTION OUTPUT ;
    USE SIGNAL ;
    PORT
      LAYER M5 ;
        RECT  243.84 0 243.864 0.084 ;
    END
  END tx[317]
  PIN tx[318]
    DIRECTION OUTPUT ;
    USE SIGNAL ;
    PORT
      LAYER M5 ;
        RECT  244.08 0 244.104 0.084 ;
    END
  END tx[318]
  PIN tx[319]
    DIRECTION OUTPUT ;
    USE SIGNAL ;
    PORT
      LAYER M5 ;
        RECT  244.32 0 244.344 0.084 ;
    END
  END tx[319]
  PIN tx[31]
    DIRECTION OUTPUT ;
    USE SIGNAL ;
    PORT
      LAYER M5 ;
        RECT  175.2 0 175.224 0.084 ;
    END
  END tx[31]
  PIN tx[320]
    DIRECTION OUTPUT ;
    USE SIGNAL ;
    PORT
      LAYER M5 ;
        RECT  244.56 0 244.584 0.084 ;
    END
  END tx[320]
  PIN tx[321]
    DIRECTION OUTPUT ;
    USE SIGNAL ;
    PORT
      LAYER M5 ;
        RECT  244.8 0 244.824 0.084 ;
    END
  END tx[321]
  PIN tx[322]
    DIRECTION OUTPUT ;
    USE SIGNAL ;
    PORT
      LAYER M5 ;
        RECT  245.04 0 245.064 0.084 ;
    END
  END tx[322]
  PIN tx[323]
    DIRECTION OUTPUT ;
    USE SIGNAL ;
    PORT
      LAYER M5 ;
        RECT  245.28 0 245.304 0.084 ;
    END
  END tx[323]
  PIN tx[324]
    DIRECTION OUTPUT ;
    USE SIGNAL ;
    PORT
      LAYER M5 ;
        RECT  245.52 0 245.544 0.084 ;
    END
  END tx[324]
  PIN tx[325]
    DIRECTION OUTPUT ;
    USE SIGNAL ;
    PORT
      LAYER M5 ;
        RECT  245.76 0 245.784 0.084 ;
    END
  END tx[325]
  PIN tx[326]
    DIRECTION OUTPUT ;
    USE SIGNAL ;
    PORT
      LAYER M5 ;
        RECT  246 0 246.024 0.084 ;
    END
  END tx[326]
  PIN tx[327]
    DIRECTION OUTPUT ;
    USE SIGNAL ;
    PORT
      LAYER M5 ;
        RECT  246.24 0 246.264 0.084 ;
    END
  END tx[327]
  PIN tx[328]
    DIRECTION OUTPUT ;
    USE SIGNAL ;
    PORT
      LAYER M5 ;
        RECT  246.48 0 246.504 0.084 ;
    END
  END tx[328]
  PIN tx[329]
    DIRECTION OUTPUT ;
    USE SIGNAL ;
    PORT
      LAYER M5 ;
        RECT  246.72 0 246.744 0.084 ;
    END
  END tx[329]
  PIN tx[32]
    DIRECTION OUTPUT ;
    USE SIGNAL ;
    PORT
      LAYER M5 ;
        RECT  175.44 0 175.464 0.084 ;
    END
  END tx[32]
  PIN tx[330]
    DIRECTION OUTPUT ;
    USE SIGNAL ;
    PORT
      LAYER M5 ;
        RECT  246.96 0 246.984 0.084 ;
    END
  END tx[330]
  PIN tx[331]
    DIRECTION OUTPUT ;
    USE SIGNAL ;
    PORT
      LAYER M5 ;
        RECT  247.2 0 247.224 0.084 ;
    END
  END tx[331]
  PIN tx[332]
    DIRECTION OUTPUT ;
    USE SIGNAL ;
    PORT
      LAYER M5 ;
        RECT  247.44 0 247.464 0.084 ;
    END
  END tx[332]
  PIN tx[333]
    DIRECTION OUTPUT ;
    USE SIGNAL ;
    PORT
      LAYER M5 ;
        RECT  247.68 0 247.704 0.084 ;
    END
  END tx[333]
  PIN tx[334]
    DIRECTION OUTPUT ;
    USE SIGNAL ;
    PORT
      LAYER M5 ;
        RECT  247.92 0 247.944 0.084 ;
    END
  END tx[334]
  PIN tx[335]
    DIRECTION OUTPUT ;
    USE SIGNAL ;
    PORT
      LAYER M5 ;
        RECT  248.16 0 248.184 0.084 ;
    END
  END tx[335]
  PIN tx[336]
    DIRECTION OUTPUT ;
    USE SIGNAL ;
    PORT
      LAYER M5 ;
        RECT  248.4 0 248.424 0.084 ;
    END
  END tx[336]
  PIN tx[337]
    DIRECTION OUTPUT ;
    USE SIGNAL ;
    PORT
      LAYER M5 ;
        RECT  248.64 0 248.664 0.084 ;
    END
  END tx[337]
  PIN tx[338]
    DIRECTION OUTPUT ;
    USE SIGNAL ;
    PORT
      LAYER M5 ;
        RECT  248.88 0 248.904 0.084 ;
    END
  END tx[338]
  PIN tx[339]
    DIRECTION OUTPUT ;
    USE SIGNAL ;
    PORT
      LAYER M5 ;
        RECT  249.12 0 249.144 0.084 ;
    END
  END tx[339]
  PIN tx[33]
    DIRECTION OUTPUT ;
    USE SIGNAL ;
    PORT
      LAYER M5 ;
        RECT  175.68 0 175.704 0.084 ;
    END
  END tx[33]
  PIN tx[340]
    DIRECTION OUTPUT ;
    USE SIGNAL ;
    PORT
      LAYER M5 ;
        RECT  249.36 0 249.384 0.084 ;
    END
  END tx[340]
  PIN tx[341]
    DIRECTION OUTPUT ;
    USE SIGNAL ;
    PORT
      LAYER M5 ;
        RECT  249.6 0 249.624 0.084 ;
    END
  END tx[341]
  PIN tx[342]
    DIRECTION OUTPUT ;
    USE SIGNAL ;
    PORT
      LAYER M5 ;
        RECT  249.84 0 249.864 0.084 ;
    END
  END tx[342]
  PIN tx[343]
    DIRECTION OUTPUT ;
    USE SIGNAL ;
    PORT
      LAYER M5 ;
        RECT  250.08 0 250.104 0.084 ;
    END
  END tx[343]
  PIN tx[344]
    DIRECTION OUTPUT ;
    USE SIGNAL ;
    PORT
      LAYER M5 ;
        RECT  250.32 0 250.344 0.084 ;
    END
  END tx[344]
  PIN tx[345]
    DIRECTION OUTPUT ;
    USE SIGNAL ;
    PORT
      LAYER M5 ;
        RECT  250.56 0 250.584 0.084 ;
    END
  END tx[345]
  PIN tx[346]
    DIRECTION OUTPUT ;
    USE SIGNAL ;
    PORT
      LAYER M5 ;
        RECT  250.8 0 250.824 0.084 ;
    END
  END tx[346]
  PIN tx[347]
    DIRECTION OUTPUT ;
    USE SIGNAL ;
    PORT
      LAYER M5 ;
        RECT  251.04 0 251.064 0.084 ;
    END
  END tx[347]
  PIN tx[348]
    DIRECTION OUTPUT ;
    USE SIGNAL ;
    PORT
      LAYER M5 ;
        RECT  251.28 0 251.304 0.084 ;
    END
  END tx[348]
  PIN tx[349]
    DIRECTION OUTPUT ;
    USE SIGNAL ;
    PORT
      LAYER M5 ;
        RECT  251.52 0 251.544 0.084 ;
    END
  END tx[349]
  PIN tx[34]
    DIRECTION OUTPUT ;
    USE SIGNAL ;
    PORT
      LAYER M5 ;
        RECT  175.92 0 175.944 0.084 ;
    END
  END tx[34]
  PIN tx[350]
    DIRECTION OUTPUT ;
    USE SIGNAL ;
    PORT
      LAYER M5 ;
        RECT  251.76 0 251.784 0.084 ;
    END
  END tx[350]
  PIN tx[351]
    DIRECTION OUTPUT ;
    USE SIGNAL ;
    PORT
      LAYER M5 ;
        RECT  252 0 252.024 0.084 ;
    END
  END tx[351]
  PIN tx[352]
    DIRECTION OUTPUT ;
    USE SIGNAL ;
    PORT
      LAYER M5 ;
        RECT  252.24 0 252.264 0.084 ;
    END
  END tx[352]
  PIN tx[353]
    DIRECTION OUTPUT ;
    USE SIGNAL ;
    PORT
      LAYER M5 ;
        RECT  252.48 0 252.504 0.084 ;
    END
  END tx[353]
  PIN tx[354]
    DIRECTION OUTPUT ;
    USE SIGNAL ;
    PORT
      LAYER M5 ;
        RECT  252.72 0 252.744 0.084 ;
    END
  END tx[354]
  PIN tx[355]
    DIRECTION OUTPUT ;
    USE SIGNAL ;
    PORT
      LAYER M5 ;
        RECT  252.96 0 252.984 0.084 ;
    END
  END tx[355]
  PIN tx[356]
    DIRECTION OUTPUT ;
    USE SIGNAL ;
    PORT
      LAYER M5 ;
        RECT  253.2 0 253.224 0.084 ;
    END
  END tx[356]
  PIN tx[357]
    DIRECTION OUTPUT ;
    USE SIGNAL ;
    PORT
      LAYER M5 ;
        RECT  253.44 0 253.464 0.084 ;
    END
  END tx[357]
  PIN tx[358]
    DIRECTION OUTPUT ;
    USE SIGNAL ;
    PORT
      LAYER M5 ;
        RECT  253.68 0 253.704 0.084 ;
    END
  END tx[358]
  PIN tx[359]
    DIRECTION OUTPUT ;
    USE SIGNAL ;
    PORT
      LAYER M5 ;
        RECT  253.92 0 253.944 0.084 ;
    END
  END tx[359]
  PIN tx[35]
    DIRECTION OUTPUT ;
    USE SIGNAL ;
    PORT
      LAYER M5 ;
        RECT  176.16 0 176.184 0.084 ;
    END
  END tx[35]
  PIN tx[360]
    DIRECTION OUTPUT ;
    USE SIGNAL ;
    PORT
      LAYER M5 ;
        RECT  254.16 0 254.184 0.084 ;
    END
  END tx[360]
  PIN tx[361]
    DIRECTION OUTPUT ;
    USE SIGNAL ;
    PORT
      LAYER M5 ;
        RECT  254.4 0 254.424 0.084 ;
    END
  END tx[361]
  PIN tx[362]
    DIRECTION OUTPUT ;
    USE SIGNAL ;
    PORT
      LAYER M5 ;
        RECT  254.64 0 254.664 0.084 ;
    END
  END tx[362]
  PIN tx[363]
    DIRECTION OUTPUT ;
    USE SIGNAL ;
    PORT
      LAYER M5 ;
        RECT  254.88 0 254.904 0.084 ;
    END
  END tx[363]
  PIN tx[364]
    DIRECTION OUTPUT ;
    USE SIGNAL ;
    PORT
      LAYER M5 ;
        RECT  255.12 0 255.144 0.084 ;
    END
  END tx[364]
  PIN tx[365]
    DIRECTION OUTPUT ;
    USE SIGNAL ;
    PORT
      LAYER M5 ;
        RECT  255.36 0 255.384 0.084 ;
    END
  END tx[365]
  PIN tx[366]
    DIRECTION OUTPUT ;
    USE SIGNAL ;
    PORT
      LAYER M5 ;
        RECT  255.6 0 255.624 0.084 ;
    END
  END tx[366]
  PIN tx[367]
    DIRECTION OUTPUT ;
    USE SIGNAL ;
    PORT
      LAYER M5 ;
        RECT  255.84 0 255.864 0.084 ;
    END
  END tx[367]
  PIN tx[368]
    DIRECTION OUTPUT ;
    USE SIGNAL ;
    PORT
      LAYER M5 ;
        RECT  256.08 0 256.104 0.084 ;
    END
  END tx[368]
  PIN tx[369]
    DIRECTION OUTPUT ;
    USE SIGNAL ;
    PORT
      LAYER M5 ;
        RECT  256.32 0 256.344 0.084 ;
    END
  END tx[369]
  PIN tx[36]
    DIRECTION OUTPUT ;
    USE SIGNAL ;
    PORT
      LAYER M5 ;
        RECT  176.4 0 176.424 0.084 ;
    END
  END tx[36]
  PIN tx[370]
    DIRECTION OUTPUT ;
    USE SIGNAL ;
    PORT
      LAYER M5 ;
        RECT  256.56 0 256.584 0.084 ;
    END
  END tx[370]
  PIN tx[371]
    DIRECTION OUTPUT ;
    USE SIGNAL ;
    PORT
      LAYER M5 ;
        RECT  256.8 0 256.824 0.084 ;
    END
  END tx[371]
  PIN tx[372]
    DIRECTION OUTPUT ;
    USE SIGNAL ;
    PORT
      LAYER M5 ;
        RECT  257.04 0 257.064 0.084 ;
    END
  END tx[372]
  PIN tx[373]
    DIRECTION OUTPUT ;
    USE SIGNAL ;
    PORT
      LAYER M5 ;
        RECT  257.28 0 257.304 0.084 ;
    END
  END tx[373]
  PIN tx[374]
    DIRECTION OUTPUT ;
    USE SIGNAL ;
    PORT
      LAYER M5 ;
        RECT  257.52 0 257.544 0.084 ;
    END
  END tx[374]
  PIN tx[375]
    DIRECTION OUTPUT ;
    USE SIGNAL ;
    PORT
      LAYER M5 ;
        RECT  257.76 0 257.784 0.084 ;
    END
  END tx[375]
  PIN tx[376]
    DIRECTION OUTPUT ;
    USE SIGNAL ;
    PORT
      LAYER M5 ;
        RECT  258 0 258.024 0.084 ;
    END
  END tx[376]
  PIN tx[377]
    DIRECTION OUTPUT ;
    USE SIGNAL ;
    PORT
      LAYER M5 ;
        RECT  258.24 0 258.264 0.084 ;
    END
  END tx[377]
  PIN tx[378]
    DIRECTION OUTPUT ;
    USE SIGNAL ;
    PORT
      LAYER M5 ;
        RECT  258.48 0 258.504 0.084 ;
    END
  END tx[378]
  PIN tx[379]
    DIRECTION OUTPUT ;
    USE SIGNAL ;
    PORT
      LAYER M5 ;
        RECT  258.72 0 258.744 0.084 ;
    END
  END tx[379]
  PIN tx[37]
    DIRECTION OUTPUT ;
    USE SIGNAL ;
    PORT
      LAYER M5 ;
        RECT  176.64 0 176.664 0.084 ;
    END
  END tx[37]
  PIN tx[380]
    DIRECTION OUTPUT ;
    USE SIGNAL ;
    PORT
      LAYER M5 ;
        RECT  258.96 0 258.984 0.084 ;
    END
  END tx[380]
  PIN tx[381]
    DIRECTION OUTPUT ;
    USE SIGNAL ;
    PORT
      LAYER M5 ;
        RECT  259.2 0 259.224 0.084 ;
    END
  END tx[381]
  PIN tx[382]
    DIRECTION OUTPUT ;
    USE SIGNAL ;
    PORT
      LAYER M5 ;
        RECT  259.44 0 259.464 0.084 ;
    END
  END tx[382]
  PIN tx[383]
    DIRECTION OUTPUT ;
    USE SIGNAL ;
    PORT
      LAYER M5 ;
        RECT  259.68 0 259.704 0.084 ;
    END
  END tx[383]
  PIN tx[384]
    DIRECTION OUTPUT ;
    USE SIGNAL ;
    PORT
      LAYER M5 ;
        RECT  259.92 0 259.944 0.084 ;
    END
  END tx[384]
  PIN tx[385]
    DIRECTION OUTPUT ;
    USE SIGNAL ;
    PORT
      LAYER M5 ;
        RECT  260.16 0 260.184 0.084 ;
    END
  END tx[385]
  PIN tx[386]
    DIRECTION OUTPUT ;
    USE SIGNAL ;
    PORT
      LAYER M5 ;
        RECT  260.4 0 260.424 0.084 ;
    END
  END tx[386]
  PIN tx[387]
    DIRECTION OUTPUT ;
    USE SIGNAL ;
    PORT
      LAYER M5 ;
        RECT  260.64 0 260.664 0.084 ;
    END
  END tx[387]
  PIN tx[388]
    DIRECTION OUTPUT ;
    USE SIGNAL ;
    PORT
      LAYER M5 ;
        RECT  260.88 0 260.904 0.084 ;
    END
  END tx[388]
  PIN tx[389]
    DIRECTION OUTPUT ;
    USE SIGNAL ;
    PORT
      LAYER M5 ;
        RECT  261.12 0 261.144 0.084 ;
    END
  END tx[389]
  PIN tx[38]
    DIRECTION OUTPUT ;
    USE SIGNAL ;
    PORT
      LAYER M5 ;
        RECT  176.88 0 176.904 0.084 ;
    END
  END tx[38]
  PIN tx[390]
    DIRECTION OUTPUT ;
    USE SIGNAL ;
    PORT
      LAYER M5 ;
        RECT  261.36 0 261.384 0.084 ;
    END
  END tx[390]
  PIN tx[391]
    DIRECTION OUTPUT ;
    USE SIGNAL ;
    PORT
      LAYER M5 ;
        RECT  261.6 0 261.624 0.084 ;
    END
  END tx[391]
  PIN tx[392]
    DIRECTION OUTPUT ;
    USE SIGNAL ;
    PORT
      LAYER M5 ;
        RECT  261.84 0 261.864 0.084 ;
    END
  END tx[392]
  PIN tx[393]
    DIRECTION OUTPUT ;
    USE SIGNAL ;
    PORT
      LAYER M5 ;
        RECT  262.08 0 262.104 0.084 ;
    END
  END tx[393]
  PIN tx[394]
    DIRECTION OUTPUT ;
    USE SIGNAL ;
    PORT
      LAYER M5 ;
        RECT  262.32 0 262.344 0.084 ;
    END
  END tx[394]
  PIN tx[395]
    DIRECTION OUTPUT ;
    USE SIGNAL ;
    PORT
      LAYER M5 ;
        RECT  262.56 0 262.584 0.084 ;
    END
  END tx[395]
  PIN tx[396]
    DIRECTION OUTPUT ;
    USE SIGNAL ;
    PORT
      LAYER M5 ;
        RECT  262.8 0 262.824 0.084 ;
    END
  END tx[396]
  PIN tx[397]
    DIRECTION OUTPUT ;
    USE SIGNAL ;
    PORT
      LAYER M5 ;
        RECT  263.04 0 263.064 0.084 ;
    END
  END tx[397]
  PIN tx[398]
    DIRECTION OUTPUT ;
    USE SIGNAL ;
    PORT
      LAYER M5 ;
        RECT  263.28 0 263.304 0.084 ;
    END
  END tx[398]
  PIN tx[399]
    DIRECTION OUTPUT ;
    USE SIGNAL ;
    PORT
      LAYER M5 ;
        RECT  263.52 0 263.544 0.084 ;
    END
  END tx[399]
  PIN tx[39]
    DIRECTION OUTPUT ;
    USE SIGNAL ;
    PORT
      LAYER M5 ;
        RECT  177.12 0 177.144 0.084 ;
    END
  END tx[39]
  PIN tx[3]
    DIRECTION OUTPUT ;
    USE SIGNAL ;
    PORT
      LAYER M5 ;
        RECT  168.48 0 168.504 0.084 ;
    END
  END tx[3]
  PIN tx[400]
    DIRECTION OUTPUT ;
    USE SIGNAL ;
    PORT
      LAYER M5 ;
        RECT  263.76 0 263.784 0.084 ;
    END
  END tx[400]
  PIN tx[401]
    DIRECTION OUTPUT ;
    USE SIGNAL ;
    PORT
      LAYER M5 ;
        RECT  264 0 264.024 0.084 ;
    END
  END tx[401]
  PIN tx[402]
    DIRECTION OUTPUT ;
    USE SIGNAL ;
    PORT
      LAYER M5 ;
        RECT  264.24 0 264.264 0.084 ;
    END
  END tx[402]
  PIN tx[403]
    DIRECTION OUTPUT ;
    USE SIGNAL ;
    PORT
      LAYER M5 ;
        RECT  264.48 0 264.504 0.084 ;
    END
  END tx[403]
  PIN tx[404]
    DIRECTION OUTPUT ;
    USE SIGNAL ;
    PORT
      LAYER M5 ;
        RECT  264.72 0 264.744 0.084 ;
    END
  END tx[404]
  PIN tx[405]
    DIRECTION OUTPUT ;
    USE SIGNAL ;
    PORT
      LAYER M5 ;
        RECT  264.96 0 264.984 0.084 ;
    END
  END tx[405]
  PIN tx[406]
    DIRECTION OUTPUT ;
    USE SIGNAL ;
    PORT
      LAYER M5 ;
        RECT  265.2 0 265.224 0.084 ;
    END
  END tx[406]
  PIN tx[407]
    DIRECTION OUTPUT ;
    USE SIGNAL ;
    PORT
      LAYER M5 ;
        RECT  265.44 0 265.464 0.084 ;
    END
  END tx[407]
  PIN tx[408]
    DIRECTION OUTPUT ;
    USE SIGNAL ;
    PORT
      LAYER M5 ;
        RECT  265.68 0 265.704 0.084 ;
    END
  END tx[408]
  PIN tx[409]
    DIRECTION OUTPUT ;
    USE SIGNAL ;
    PORT
      LAYER M5 ;
        RECT  265.92 0 265.944 0.084 ;
    END
  END tx[409]
  PIN tx[40]
    DIRECTION OUTPUT ;
    USE SIGNAL ;
    PORT
      LAYER M5 ;
        RECT  177.36 0 177.384 0.084 ;
    END
  END tx[40]
  PIN tx[410]
    DIRECTION OUTPUT ;
    USE SIGNAL ;
    PORT
      LAYER M5 ;
        RECT  266.16 0 266.184 0.084 ;
    END
  END tx[410]
  PIN tx[411]
    DIRECTION OUTPUT ;
    USE SIGNAL ;
    PORT
      LAYER M5 ;
        RECT  266.4 0 266.424 0.084 ;
    END
  END tx[411]
  PIN tx[412]
    DIRECTION OUTPUT ;
    USE SIGNAL ;
    PORT
      LAYER M5 ;
        RECT  266.64 0 266.664 0.084 ;
    END
  END tx[412]
  PIN tx[413]
    DIRECTION OUTPUT ;
    USE SIGNAL ;
    PORT
      LAYER M5 ;
        RECT  266.88 0 266.904 0.084 ;
    END
  END tx[413]
  PIN tx[414]
    DIRECTION OUTPUT ;
    USE SIGNAL ;
    PORT
      LAYER M5 ;
        RECT  267.12 0 267.144 0.084 ;
    END
  END tx[414]
  PIN tx[415]
    DIRECTION OUTPUT ;
    USE SIGNAL ;
    PORT
      LAYER M5 ;
        RECT  267.36 0 267.384 0.084 ;
    END
  END tx[415]
  PIN tx[416]
    DIRECTION OUTPUT ;
    USE SIGNAL ;
    PORT
      LAYER M5 ;
        RECT  267.6 0 267.624 0.084 ;
    END
  END tx[416]
  PIN tx[417]
    DIRECTION OUTPUT ;
    USE SIGNAL ;
    PORT
      LAYER M5 ;
        RECT  267.84 0 267.864 0.084 ;
    END
  END tx[417]
  PIN tx[418]
    DIRECTION OUTPUT ;
    USE SIGNAL ;
    PORT
      LAYER M5 ;
        RECT  268.08 0 268.104 0.084 ;
    END
  END tx[418]
  PIN tx[419]
    DIRECTION OUTPUT ;
    USE SIGNAL ;
    PORT
      LAYER M5 ;
        RECT  268.32 0 268.344 0.084 ;
    END
  END tx[419]
  PIN tx[41]
    DIRECTION OUTPUT ;
    USE SIGNAL ;
    PORT
      LAYER M5 ;
        RECT  177.6 0 177.624 0.084 ;
    END
  END tx[41]
  PIN tx[420]
    DIRECTION OUTPUT ;
    USE SIGNAL ;
    PORT
      LAYER M5 ;
        RECT  268.56 0 268.584 0.084 ;
    END
  END tx[420]
  PIN tx[421]
    DIRECTION OUTPUT ;
    USE SIGNAL ;
    PORT
      LAYER M5 ;
        RECT  268.8 0 268.824 0.084 ;
    END
  END tx[421]
  PIN tx[422]
    DIRECTION OUTPUT ;
    USE SIGNAL ;
    PORT
      LAYER M5 ;
        RECT  269.04 0 269.064 0.084 ;
    END
  END tx[422]
  PIN tx[423]
    DIRECTION OUTPUT ;
    USE SIGNAL ;
    PORT
      LAYER M5 ;
        RECT  269.28 0 269.304 0.084 ;
    END
  END tx[423]
  PIN tx[424]
    DIRECTION OUTPUT ;
    USE SIGNAL ;
    PORT
      LAYER M5 ;
        RECT  269.52 0 269.544 0.084 ;
    END
  END tx[424]
  PIN tx[425]
    DIRECTION OUTPUT ;
    USE SIGNAL ;
    PORT
      LAYER M5 ;
        RECT  269.76 0 269.784 0.084 ;
    END
  END tx[425]
  PIN tx[426]
    DIRECTION OUTPUT ;
    USE SIGNAL ;
    PORT
      LAYER M5 ;
        RECT  270 0 270.024 0.084 ;
    END
  END tx[426]
  PIN tx[427]
    DIRECTION OUTPUT ;
    USE SIGNAL ;
    PORT
      LAYER M5 ;
        RECT  270.24 0 270.264 0.084 ;
    END
  END tx[427]
  PIN tx[428]
    DIRECTION OUTPUT ;
    USE SIGNAL ;
    PORT
      LAYER M5 ;
        RECT  270.48 0 270.504 0.084 ;
    END
  END tx[428]
  PIN tx[429]
    DIRECTION OUTPUT ;
    USE SIGNAL ;
    PORT
      LAYER M5 ;
        RECT  270.72 0 270.744 0.084 ;
    END
  END tx[429]
  PIN tx[42]
    DIRECTION OUTPUT ;
    USE SIGNAL ;
    PORT
      LAYER M5 ;
        RECT  177.84 0 177.864 0.084 ;
    END
  END tx[42]
  PIN tx[430]
    DIRECTION OUTPUT ;
    USE SIGNAL ;
    PORT
      LAYER M5 ;
        RECT  270.96 0 270.984 0.084 ;
    END
  END tx[430]
  PIN tx[431]
    DIRECTION OUTPUT ;
    USE SIGNAL ;
    PORT
      LAYER M5 ;
        RECT  271.2 0 271.224 0.084 ;
    END
  END tx[431]
  PIN tx[432]
    DIRECTION OUTPUT ;
    USE SIGNAL ;
    PORT
      LAYER M5 ;
        RECT  271.44 0 271.464 0.084 ;
    END
  END tx[432]
  PIN tx[433]
    DIRECTION OUTPUT ;
    USE SIGNAL ;
    PORT
      LAYER M5 ;
        RECT  271.68 0 271.704 0.084 ;
    END
  END tx[433]
  PIN tx[434]
    DIRECTION OUTPUT ;
    USE SIGNAL ;
    PORT
      LAYER M5 ;
        RECT  271.92 0 271.944 0.084 ;
    END
  END tx[434]
  PIN tx[435]
    DIRECTION OUTPUT ;
    USE SIGNAL ;
    PORT
      LAYER M5 ;
        RECT  272.16 0 272.184 0.084 ;
    END
  END tx[435]
  PIN tx[436]
    DIRECTION OUTPUT ;
    USE SIGNAL ;
    PORT
      LAYER M5 ;
        RECT  272.4 0 272.424 0.084 ;
    END
  END tx[436]
  PIN tx[437]
    DIRECTION OUTPUT ;
    USE SIGNAL ;
    PORT
      LAYER M5 ;
        RECT  272.64 0 272.664 0.084 ;
    END
  END tx[437]
  PIN tx[438]
    DIRECTION OUTPUT ;
    USE SIGNAL ;
    PORT
      LAYER M5 ;
        RECT  272.88 0 272.904 0.084 ;
    END
  END tx[438]
  PIN tx[439]
    DIRECTION OUTPUT ;
    USE SIGNAL ;
    PORT
      LAYER M5 ;
        RECT  273.12 0 273.144 0.084 ;
    END
  END tx[439]
  PIN tx[43]
    DIRECTION OUTPUT ;
    USE SIGNAL ;
    PORT
      LAYER M5 ;
        RECT  178.08 0 178.104 0.084 ;
    END
  END tx[43]
  PIN tx[440]
    DIRECTION OUTPUT ;
    USE SIGNAL ;
    PORT
      LAYER M5 ;
        RECT  273.36 0 273.384 0.084 ;
    END
  END tx[440]
  PIN tx[441]
    DIRECTION OUTPUT ;
    USE SIGNAL ;
    PORT
      LAYER M5 ;
        RECT  273.6 0 273.624 0.084 ;
    END
  END tx[441]
  PIN tx[442]
    DIRECTION OUTPUT ;
    USE SIGNAL ;
    PORT
      LAYER M5 ;
        RECT  273.84 0 273.864 0.084 ;
    END
  END tx[442]
  PIN tx[443]
    DIRECTION OUTPUT ;
    USE SIGNAL ;
    PORT
      LAYER M5 ;
        RECT  274.08 0 274.104 0.084 ;
    END
  END tx[443]
  PIN tx[444]
    DIRECTION OUTPUT ;
    USE SIGNAL ;
    PORT
      LAYER M5 ;
        RECT  274.32 0 274.344 0.084 ;
    END
  END tx[444]
  PIN tx[445]
    DIRECTION OUTPUT ;
    USE SIGNAL ;
    PORT
      LAYER M5 ;
        RECT  274.56 0 274.584 0.084 ;
    END
  END tx[445]
  PIN tx[446]
    DIRECTION OUTPUT ;
    USE SIGNAL ;
    PORT
      LAYER M5 ;
        RECT  274.8 0 274.824 0.084 ;
    END
  END tx[446]
  PIN tx[447]
    DIRECTION OUTPUT ;
    USE SIGNAL ;
    PORT
      LAYER M5 ;
        RECT  275.04 0 275.064 0.084 ;
    END
  END tx[447]
  PIN tx[448]
    DIRECTION OUTPUT ;
    USE SIGNAL ;
    PORT
      LAYER M5 ;
        RECT  275.28 0 275.304 0.084 ;
    END
  END tx[448]
  PIN tx[449]
    DIRECTION OUTPUT ;
    USE SIGNAL ;
    PORT
      LAYER M5 ;
        RECT  275.52 0 275.544 0.084 ;
    END
  END tx[449]
  PIN tx[44]
    DIRECTION OUTPUT ;
    USE SIGNAL ;
    PORT
      LAYER M5 ;
        RECT  178.32 0 178.344 0.084 ;
    END
  END tx[44]
  PIN tx[450]
    DIRECTION OUTPUT ;
    USE SIGNAL ;
    PORT
      LAYER M5 ;
        RECT  275.76 0 275.784 0.084 ;
    END
  END tx[450]
  PIN tx[451]
    DIRECTION OUTPUT ;
    USE SIGNAL ;
    PORT
      LAYER M5 ;
        RECT  276 0 276.024 0.084 ;
    END
  END tx[451]
  PIN tx[452]
    DIRECTION OUTPUT ;
    USE SIGNAL ;
    PORT
      LAYER M5 ;
        RECT  276.24 0 276.264 0.084 ;
    END
  END tx[452]
  PIN tx[453]
    DIRECTION OUTPUT ;
    USE SIGNAL ;
    PORT
      LAYER M5 ;
        RECT  276.48 0 276.504 0.084 ;
    END
  END tx[453]
  PIN tx[454]
    DIRECTION OUTPUT ;
    USE SIGNAL ;
    PORT
      LAYER M5 ;
        RECT  276.72 0 276.744 0.084 ;
    END
  END tx[454]
  PIN tx[455]
    DIRECTION OUTPUT ;
    USE SIGNAL ;
    PORT
      LAYER M5 ;
        RECT  276.96 0 276.984 0.084 ;
    END
  END tx[455]
  PIN tx[456]
    DIRECTION OUTPUT ;
    USE SIGNAL ;
    PORT
      LAYER M5 ;
        RECT  277.2 0 277.224 0.084 ;
    END
  END tx[456]
  PIN tx[457]
    DIRECTION OUTPUT ;
    USE SIGNAL ;
    PORT
      LAYER M5 ;
        RECT  277.44 0 277.464 0.084 ;
    END
  END tx[457]
  PIN tx[458]
    DIRECTION OUTPUT ;
    USE SIGNAL ;
    PORT
      LAYER M5 ;
        RECT  277.68 0 277.704 0.084 ;
    END
  END tx[458]
  PIN tx[459]
    DIRECTION OUTPUT ;
    USE SIGNAL ;
    PORT
      LAYER M5 ;
        RECT  277.92 0 277.944 0.084 ;
    END
  END tx[459]
  PIN tx[45]
    DIRECTION OUTPUT ;
    USE SIGNAL ;
    PORT
      LAYER M5 ;
        RECT  178.56 0 178.584 0.084 ;
    END
  END tx[45]
  PIN tx[460]
    DIRECTION OUTPUT ;
    USE SIGNAL ;
    PORT
      LAYER M5 ;
        RECT  278.16 0 278.184 0.084 ;
    END
  END tx[460]
  PIN tx[461]
    DIRECTION OUTPUT ;
    USE SIGNAL ;
    PORT
      LAYER M5 ;
        RECT  278.4 0 278.424 0.084 ;
    END
  END tx[461]
  PIN tx[462]
    DIRECTION OUTPUT ;
    USE SIGNAL ;
    PORT
      LAYER M5 ;
        RECT  278.64 0 278.664 0.084 ;
    END
  END tx[462]
  PIN tx[463]
    DIRECTION OUTPUT ;
    USE SIGNAL ;
    PORT
      LAYER M5 ;
        RECT  278.88 0 278.904 0.084 ;
    END
  END tx[463]
  PIN tx[464]
    DIRECTION OUTPUT ;
    USE SIGNAL ;
    PORT
      LAYER M5 ;
        RECT  279.12 0 279.144 0.084 ;
    END
  END tx[464]
  PIN tx[465]
    DIRECTION OUTPUT ;
    USE SIGNAL ;
    PORT
      LAYER M5 ;
        RECT  279.36 0 279.384 0.084 ;
    END
  END tx[465]
  PIN tx[466]
    DIRECTION OUTPUT ;
    USE SIGNAL ;
    PORT
      LAYER M5 ;
        RECT  279.6 0 279.624 0.084 ;
    END
  END tx[466]
  PIN tx[467]
    DIRECTION OUTPUT ;
    USE SIGNAL ;
    PORT
      LAYER M5 ;
        RECT  279.84 0 279.864 0.084 ;
    END
  END tx[467]
  PIN tx[468]
    DIRECTION OUTPUT ;
    USE SIGNAL ;
    PORT
      LAYER M5 ;
        RECT  280.08 0 280.104 0.084 ;
    END
  END tx[468]
  PIN tx[469]
    DIRECTION OUTPUT ;
    USE SIGNAL ;
    PORT
      LAYER M5 ;
        RECT  280.32 0 280.344 0.084 ;
    END
  END tx[469]
  PIN tx[46]
    DIRECTION OUTPUT ;
    USE SIGNAL ;
    PORT
      LAYER M5 ;
        RECT  178.8 0 178.824 0.084 ;
    END
  END tx[46]
  PIN tx[470]
    DIRECTION OUTPUT ;
    USE SIGNAL ;
    PORT
      LAYER M5 ;
        RECT  280.56 0 280.584 0.084 ;
    END
  END tx[470]
  PIN tx[471]
    DIRECTION OUTPUT ;
    USE SIGNAL ;
    PORT
      LAYER M5 ;
        RECT  280.8 0 280.824 0.084 ;
    END
  END tx[471]
  PIN tx[472]
    DIRECTION OUTPUT ;
    USE SIGNAL ;
    PORT
      LAYER M5 ;
        RECT  281.04 0 281.064 0.084 ;
    END
  END tx[472]
  PIN tx[473]
    DIRECTION OUTPUT ;
    USE SIGNAL ;
    PORT
      LAYER M5 ;
        RECT  281.28 0 281.304 0.084 ;
    END
  END tx[473]
  PIN tx[474]
    DIRECTION OUTPUT ;
    USE SIGNAL ;
    PORT
      LAYER M5 ;
        RECT  281.52 0 281.544 0.084 ;
    END
  END tx[474]
  PIN tx[475]
    DIRECTION OUTPUT ;
    USE SIGNAL ;
    PORT
      LAYER M5 ;
        RECT  281.76 0 281.784 0.084 ;
    END
  END tx[475]
  PIN tx[476]
    DIRECTION OUTPUT ;
    USE SIGNAL ;
    PORT
      LAYER M5 ;
        RECT  282 0 282.024 0.084 ;
    END
  END tx[476]
  PIN tx[477]
    DIRECTION OUTPUT ;
    USE SIGNAL ;
    PORT
      LAYER M5 ;
        RECT  282.24 0 282.264 0.084 ;
    END
  END tx[477]
  PIN tx[478]
    DIRECTION OUTPUT ;
    USE SIGNAL ;
    PORT
      LAYER M5 ;
        RECT  282.48 0 282.504 0.084 ;
    END
  END tx[478]
  PIN tx[479]
    DIRECTION OUTPUT ;
    USE SIGNAL ;
    PORT
      LAYER M5 ;
        RECT  282.72 0 282.744 0.084 ;
    END
  END tx[479]
  PIN tx[47]
    DIRECTION OUTPUT ;
    USE SIGNAL ;
    PORT
      LAYER M5 ;
        RECT  179.04 0 179.064 0.084 ;
    END
  END tx[47]
  PIN tx[480]
    DIRECTION OUTPUT ;
    USE SIGNAL ;
    PORT
      LAYER M5 ;
        RECT  282.96 0 282.984 0.084 ;
    END
  END tx[480]
  PIN tx[481]
    DIRECTION OUTPUT ;
    USE SIGNAL ;
    PORT
      LAYER M5 ;
        RECT  283.2 0 283.224 0.084 ;
    END
  END tx[481]
  PIN tx[482]
    DIRECTION OUTPUT ;
    USE SIGNAL ;
    PORT
      LAYER M5 ;
        RECT  283.44 0 283.464 0.084 ;
    END
  END tx[482]
  PIN tx[483]
    DIRECTION OUTPUT ;
    USE SIGNAL ;
    PORT
      LAYER M5 ;
        RECT  283.68 0 283.704 0.084 ;
    END
  END tx[483]
  PIN tx[484]
    DIRECTION OUTPUT ;
    USE SIGNAL ;
    PORT
      LAYER M5 ;
        RECT  283.92 0 283.944 0.084 ;
    END
  END tx[484]
  PIN tx[485]
    DIRECTION OUTPUT ;
    USE SIGNAL ;
    PORT
      LAYER M5 ;
        RECT  284.16 0 284.184 0.084 ;
    END
  END tx[485]
  PIN tx[486]
    DIRECTION OUTPUT ;
    USE SIGNAL ;
    PORT
      LAYER M5 ;
        RECT  284.4 0 284.424 0.084 ;
    END
  END tx[486]
  PIN tx[487]
    DIRECTION OUTPUT ;
    USE SIGNAL ;
    PORT
      LAYER M5 ;
        RECT  284.64 0 284.664 0.084 ;
    END
  END tx[487]
  PIN tx[488]
    DIRECTION OUTPUT ;
    USE SIGNAL ;
    PORT
      LAYER M5 ;
        RECT  284.88 0 284.904 0.084 ;
    END
  END tx[488]
  PIN tx[489]
    DIRECTION OUTPUT ;
    USE SIGNAL ;
    PORT
      LAYER M5 ;
        RECT  285.12 0 285.144 0.084 ;
    END
  END tx[489]
  PIN tx[48]
    DIRECTION OUTPUT ;
    USE SIGNAL ;
    PORT
      LAYER M5 ;
        RECT  179.28 0 179.304 0.084 ;
    END
  END tx[48]
  PIN tx[490]
    DIRECTION OUTPUT ;
    USE SIGNAL ;
    PORT
      LAYER M5 ;
        RECT  285.36 0 285.384 0.084 ;
    END
  END tx[490]
  PIN tx[491]
    DIRECTION OUTPUT ;
    USE SIGNAL ;
    PORT
      LAYER M5 ;
        RECT  285.6 0 285.624 0.084 ;
    END
  END tx[491]
  PIN tx[492]
    DIRECTION OUTPUT ;
    USE SIGNAL ;
    PORT
      LAYER M5 ;
        RECT  285.84 0 285.864 0.084 ;
    END
  END tx[492]
  PIN tx[493]
    DIRECTION OUTPUT ;
    USE SIGNAL ;
    PORT
      LAYER M5 ;
        RECT  286.08 0 286.104 0.084 ;
    END
  END tx[493]
  PIN tx[494]
    DIRECTION OUTPUT ;
    USE SIGNAL ;
    PORT
      LAYER M5 ;
        RECT  286.32 0 286.344 0.084 ;
    END
  END tx[494]
  PIN tx[495]
    DIRECTION OUTPUT ;
    USE SIGNAL ;
    PORT
      LAYER M5 ;
        RECT  286.56 0 286.584 0.084 ;
    END
  END tx[495]
  PIN tx[496]
    DIRECTION OUTPUT ;
    USE SIGNAL ;
    PORT
      LAYER M5 ;
        RECT  286.8 0 286.824 0.084 ;
    END
  END tx[496]
  PIN tx[497]
    DIRECTION OUTPUT ;
    USE SIGNAL ;
    PORT
      LAYER M5 ;
        RECT  287.04 0 287.064 0.084 ;
    END
  END tx[497]
  PIN tx[498]
    DIRECTION OUTPUT ;
    USE SIGNAL ;
    PORT
      LAYER M5 ;
        RECT  287.28 0 287.304 0.084 ;
    END
  END tx[498]
  PIN tx[499]
    DIRECTION OUTPUT ;
    USE SIGNAL ;
    PORT
      LAYER M5 ;
        RECT  287.52 0 287.544 0.084 ;
    END
  END tx[499]
  PIN tx[49]
    DIRECTION OUTPUT ;
    USE SIGNAL ;
    PORT
      LAYER M5 ;
        RECT  179.52 0 179.544 0.084 ;
    END
  END tx[49]
  PIN tx[4]
    DIRECTION OUTPUT ;
    USE SIGNAL ;
    PORT
      LAYER M5 ;
        RECT  168.72 0 168.744 0.084 ;
    END
  END tx[4]
  PIN tx[500]
    DIRECTION OUTPUT ;
    USE SIGNAL ;
    PORT
      LAYER M5 ;
        RECT  287.76 0 287.784 0.084 ;
    END
  END tx[500]
  PIN tx[501]
    DIRECTION OUTPUT ;
    USE SIGNAL ;
    PORT
      LAYER M5 ;
        RECT  288 0 288.024 0.084 ;
    END
  END tx[501]
  PIN tx[502]
    DIRECTION OUTPUT ;
    USE SIGNAL ;
    PORT
      LAYER M5 ;
        RECT  288.24 0 288.264 0.084 ;
    END
  END tx[502]
  PIN tx[503]
    DIRECTION OUTPUT ;
    USE SIGNAL ;
    PORT
      LAYER M5 ;
        RECT  288.48 0 288.504 0.084 ;
    END
  END tx[503]
  PIN tx[504]
    DIRECTION OUTPUT ;
    USE SIGNAL ;
    PORT
      LAYER M5 ;
        RECT  288.72 0 288.744 0.084 ;
    END
  END tx[504]
  PIN tx[505]
    DIRECTION OUTPUT ;
    USE SIGNAL ;
    PORT
      LAYER M5 ;
        RECT  288.96 0 288.984 0.084 ;
    END
  END tx[505]
  PIN tx[506]
    DIRECTION OUTPUT ;
    USE SIGNAL ;
    PORT
      LAYER M5 ;
        RECT  289.2 0 289.224 0.084 ;
    END
  END tx[506]
  PIN tx[507]
    DIRECTION OUTPUT ;
    USE SIGNAL ;
    PORT
      LAYER M5 ;
        RECT  289.44 0 289.464 0.084 ;
    END
  END tx[507]
  PIN tx[508]
    DIRECTION OUTPUT ;
    USE SIGNAL ;
    PORT
      LAYER M5 ;
        RECT  289.68 0 289.704 0.084 ;
    END
  END tx[508]
  PIN tx[509]
    DIRECTION OUTPUT ;
    USE SIGNAL ;
    PORT
      LAYER M5 ;
        RECT  289.92 0 289.944 0.084 ;
    END
  END tx[509]
  PIN tx[50]
    DIRECTION OUTPUT ;
    USE SIGNAL ;
    PORT
      LAYER M5 ;
        RECT  179.76 0 179.784 0.084 ;
    END
  END tx[50]
  PIN tx[510]
    DIRECTION OUTPUT ;
    USE SIGNAL ;
    PORT
      LAYER M5 ;
        RECT  290.16 0 290.184 0.084 ;
    END
  END tx[510]
  PIN tx[511]
    DIRECTION OUTPUT ;
    USE SIGNAL ;
    PORT
      LAYER M5 ;
        RECT  290.4 0 290.424 0.084 ;
    END
  END tx[511]
  PIN tx[51]
    DIRECTION OUTPUT ;
    USE SIGNAL ;
    PORT
      LAYER M5 ;
        RECT  180 0 180.024 0.084 ;
    END
  END tx[51]
  PIN tx[52]
    DIRECTION OUTPUT ;
    USE SIGNAL ;
    PORT
      LAYER M5 ;
        RECT  180.24 0 180.264 0.084 ;
    END
  END tx[52]
  PIN tx[53]
    DIRECTION OUTPUT ;
    USE SIGNAL ;
    PORT
      LAYER M5 ;
        RECT  180.48 0 180.504 0.084 ;
    END
  END tx[53]
  PIN tx[54]
    DIRECTION OUTPUT ;
    USE SIGNAL ;
    PORT
      LAYER M5 ;
        RECT  180.72 0 180.744 0.084 ;
    END
  END tx[54]
  PIN tx[55]
    DIRECTION OUTPUT ;
    USE SIGNAL ;
    PORT
      LAYER M5 ;
        RECT  180.96 0 180.984 0.084 ;
    END
  END tx[55]
  PIN tx[56]
    DIRECTION OUTPUT ;
    USE SIGNAL ;
    PORT
      LAYER M5 ;
        RECT  181.2 0 181.224 0.084 ;
    END
  END tx[56]
  PIN tx[57]
    DIRECTION OUTPUT ;
    USE SIGNAL ;
    PORT
      LAYER M5 ;
        RECT  181.44 0 181.464 0.084 ;
    END
  END tx[57]
  PIN tx[58]
    DIRECTION OUTPUT ;
    USE SIGNAL ;
    PORT
      LAYER M5 ;
        RECT  181.68 0 181.704 0.084 ;
    END
  END tx[58]
  PIN tx[59]
    DIRECTION OUTPUT ;
    USE SIGNAL ;
    PORT
      LAYER M5 ;
        RECT  181.92 0 181.944 0.084 ;
    END
  END tx[59]
  PIN tx[5]
    DIRECTION OUTPUT ;
    USE SIGNAL ;
    PORT
      LAYER M5 ;
        RECT  168.96 0 168.984 0.084 ;
    END
  END tx[5]
  PIN tx[60]
    DIRECTION OUTPUT ;
    USE SIGNAL ;
    PORT
      LAYER M5 ;
        RECT  182.16 0 182.184 0.084 ;
    END
  END tx[60]
  PIN tx[61]
    DIRECTION OUTPUT ;
    USE SIGNAL ;
    PORT
      LAYER M5 ;
        RECT  182.4 0 182.424 0.084 ;
    END
  END tx[61]
  PIN tx[62]
    DIRECTION OUTPUT ;
    USE SIGNAL ;
    PORT
      LAYER M5 ;
        RECT  182.64 0 182.664 0.084 ;
    END
  END tx[62]
  PIN tx[63]
    DIRECTION OUTPUT ;
    USE SIGNAL ;
    PORT
      LAYER M5 ;
        RECT  182.88 0 182.904 0.084 ;
    END
  END tx[63]
  PIN tx[64]
    DIRECTION OUTPUT ;
    USE SIGNAL ;
    PORT
      LAYER M5 ;
        RECT  183.12 0 183.144 0.084 ;
    END
  END tx[64]
  PIN tx[65]
    DIRECTION OUTPUT ;
    USE SIGNAL ;
    PORT
      LAYER M5 ;
        RECT  183.36 0 183.384 0.084 ;
    END
  END tx[65]
  PIN tx[66]
    DIRECTION OUTPUT ;
    USE SIGNAL ;
    PORT
      LAYER M5 ;
        RECT  183.6 0 183.624 0.084 ;
    END
  END tx[66]
  PIN tx[67]
    DIRECTION OUTPUT ;
    USE SIGNAL ;
    PORT
      LAYER M5 ;
        RECT  183.84 0 183.864 0.084 ;
    END
  END tx[67]
  PIN tx[68]
    DIRECTION OUTPUT ;
    USE SIGNAL ;
    PORT
      LAYER M5 ;
        RECT  184.08 0 184.104 0.084 ;
    END
  END tx[68]
  PIN tx[69]
    DIRECTION OUTPUT ;
    USE SIGNAL ;
    PORT
      LAYER M5 ;
        RECT  184.32 0 184.344 0.084 ;
    END
  END tx[69]
  PIN tx[6]
    DIRECTION OUTPUT ;
    USE SIGNAL ;
    PORT
      LAYER M5 ;
        RECT  169.2 0 169.224 0.084 ;
    END
  END tx[6]
  PIN tx[70]
    DIRECTION OUTPUT ;
    USE SIGNAL ;
    PORT
      LAYER M5 ;
        RECT  184.56 0 184.584 0.084 ;
    END
  END tx[70]
  PIN tx[71]
    DIRECTION OUTPUT ;
    USE SIGNAL ;
    PORT
      LAYER M5 ;
        RECT  184.8 0 184.824 0.084 ;
    END
  END tx[71]
  PIN tx[72]
    DIRECTION OUTPUT ;
    USE SIGNAL ;
    PORT
      LAYER M5 ;
        RECT  185.04 0 185.064 0.084 ;
    END
  END tx[72]
  PIN tx[73]
    DIRECTION OUTPUT ;
    USE SIGNAL ;
    PORT
      LAYER M5 ;
        RECT  185.28 0 185.304 0.084 ;
    END
  END tx[73]
  PIN tx[74]
    DIRECTION OUTPUT ;
    USE SIGNAL ;
    PORT
      LAYER M5 ;
        RECT  185.52 0 185.544 0.084 ;
    END
  END tx[74]
  PIN tx[75]
    DIRECTION OUTPUT ;
    USE SIGNAL ;
    PORT
      LAYER M5 ;
        RECT  185.76 0 185.784 0.084 ;
    END
  END tx[75]
  PIN tx[76]
    DIRECTION OUTPUT ;
    USE SIGNAL ;
    PORT
      LAYER M5 ;
        RECT  186 0 186.024 0.084 ;
    END
  END tx[76]
  PIN tx[77]
    DIRECTION OUTPUT ;
    USE SIGNAL ;
    PORT
      LAYER M5 ;
        RECT  186.24 0 186.264 0.084 ;
    END
  END tx[77]
  PIN tx[78]
    DIRECTION OUTPUT ;
    USE SIGNAL ;
    PORT
      LAYER M5 ;
        RECT  186.48 0 186.504 0.084 ;
    END
  END tx[78]
  PIN tx[79]
    DIRECTION OUTPUT ;
    USE SIGNAL ;
    PORT
      LAYER M5 ;
        RECT  186.72 0 186.744 0.084 ;
    END
  END tx[79]
  PIN tx[7]
    DIRECTION OUTPUT ;
    USE SIGNAL ;
    PORT
      LAYER M5 ;
        RECT  169.44 0 169.464 0.084 ;
    END
  END tx[7]
  PIN tx[80]
    DIRECTION OUTPUT ;
    USE SIGNAL ;
    PORT
      LAYER M5 ;
        RECT  186.96 0 186.984 0.084 ;
    END
  END tx[80]
  PIN tx[81]
    DIRECTION OUTPUT ;
    USE SIGNAL ;
    PORT
      LAYER M5 ;
        RECT  187.2 0 187.224 0.084 ;
    END
  END tx[81]
  PIN tx[82]
    DIRECTION OUTPUT ;
    USE SIGNAL ;
    PORT
      LAYER M5 ;
        RECT  187.44 0 187.464 0.084 ;
    END
  END tx[82]
  PIN tx[83]
    DIRECTION OUTPUT ;
    USE SIGNAL ;
    PORT
      LAYER M5 ;
        RECT  187.68 0 187.704 0.084 ;
    END
  END tx[83]
  PIN tx[84]
    DIRECTION OUTPUT ;
    USE SIGNAL ;
    PORT
      LAYER M5 ;
        RECT  187.92 0 187.944 0.084 ;
    END
  END tx[84]
  PIN tx[85]
    DIRECTION OUTPUT ;
    USE SIGNAL ;
    PORT
      LAYER M5 ;
        RECT  188.16 0 188.184 0.084 ;
    END
  END tx[85]
  PIN tx[86]
    DIRECTION OUTPUT ;
    USE SIGNAL ;
    PORT
      LAYER M5 ;
        RECT  188.4 0 188.424 0.084 ;
    END
  END tx[86]
  PIN tx[87]
    DIRECTION OUTPUT ;
    USE SIGNAL ;
    PORT
      LAYER M5 ;
        RECT  188.64 0 188.664 0.084 ;
    END
  END tx[87]
  PIN tx[88]
    DIRECTION OUTPUT ;
    USE SIGNAL ;
    PORT
      LAYER M5 ;
        RECT  188.88 0 188.904 0.084 ;
    END
  END tx[88]
  PIN tx[89]
    DIRECTION OUTPUT ;
    USE SIGNAL ;
    PORT
      LAYER M5 ;
        RECT  189.12 0 189.144 0.084 ;
    END
  END tx[89]
  PIN tx[8]
    DIRECTION OUTPUT ;
    USE SIGNAL ;
    PORT
      LAYER M5 ;
        RECT  169.68 0 169.704 0.084 ;
    END
  END tx[8]
  PIN tx[90]
    DIRECTION OUTPUT ;
    USE SIGNAL ;
    PORT
      LAYER M5 ;
        RECT  189.36 0 189.384 0.084 ;
    END
  END tx[90]
  PIN tx[91]
    DIRECTION OUTPUT ;
    USE SIGNAL ;
    PORT
      LAYER M5 ;
        RECT  189.6 0 189.624 0.084 ;
    END
  END tx[91]
  PIN tx[92]
    DIRECTION OUTPUT ;
    USE SIGNAL ;
    PORT
      LAYER M5 ;
        RECT  189.84 0 189.864 0.084 ;
    END
  END tx[92]
  PIN tx[93]
    DIRECTION OUTPUT ;
    USE SIGNAL ;
    PORT
      LAYER M5 ;
        RECT  190.08 0 190.104 0.084 ;
    END
  END tx[93]
  PIN tx[94]
    DIRECTION OUTPUT ;
    USE SIGNAL ;
    PORT
      LAYER M5 ;
        RECT  190.32 0 190.344 0.084 ;
    END
  END tx[94]
  PIN tx[95]
    DIRECTION OUTPUT ;
    USE SIGNAL ;
    PORT
      LAYER M5 ;
        RECT  190.56 0 190.584 0.084 ;
    END
  END tx[95]
  PIN tx[96]
    DIRECTION OUTPUT ;
    USE SIGNAL ;
    PORT
      LAYER M5 ;
        RECT  190.8 0 190.824 0.084 ;
    END
  END tx[96]
  PIN tx[97]
    DIRECTION OUTPUT ;
    USE SIGNAL ;
    PORT
      LAYER M5 ;
        RECT  191.04 0 191.064 0.084 ;
    END
  END tx[97]
  PIN tx[98]
    DIRECTION OUTPUT ;
    USE SIGNAL ;
    PORT
      LAYER M5 ;
        RECT  191.28 0 191.304 0.084 ;
    END
  END tx[98]
  PIN tx[99]
    DIRECTION OUTPUT ;
    USE SIGNAL ;
    PORT
      LAYER M5 ;
        RECT  191.52 0 191.544 0.084 ;
    END
  END tx[99]
  PIN tx[9]
    DIRECTION OUTPUT ;
    USE SIGNAL ;
    PORT
      LAYER M5 ;
        RECT  169.92 0 169.944 0.084 ;
    END
  END tx[9]
  PIN VDD
    DIRECTION INOUT ;
    USE POWER ;
    PORT
      LAYER M6 ;
        RECT  4.32 438.528 291.6 438.816 ;
        RECT  4.32 434.208 291.6 434.496 ;
        RECT  4.32 429.888 291.6 430.176 ;
        RECT  4.32 425.568 291.6 425.856 ;
        RECT  4.32 421.248 291.6 421.536 ;
        RECT  4.32 416.928 291.6 417.216 ;
        RECT  4.32 412.608 291.6 412.896 ;
        RECT  4.32 408.288 291.6 408.576 ;
        RECT  4.32 403.968 291.6 404.256 ;
        RECT  4.32 399.648 291.6 399.936 ;
        RECT  4.32 395.328 291.6 395.616 ;
        RECT  4.32 391.008 291.6 391.296 ;
        RECT  4.32 386.688 291.6 386.976 ;
        RECT  4.32 382.368 291.6 382.656 ;
        RECT  4.32 378.048 291.6 378.336 ;
        RECT  4.32 373.728 291.6 374.016 ;
        RECT  4.32 369.408 291.6 369.696 ;
        RECT  4.32 365.088 291.6 365.376 ;
        RECT  4.32 360.768 291.6 361.056 ;
        RECT  4.32 356.448 291.6 356.736 ;
        RECT  4.32 352.128 291.6 352.416 ;
        RECT  4.32 347.808 291.6 348.096 ;
        RECT  4.32 343.488 291.6 343.776 ;
        RECT  4.32 339.168 291.6 339.456 ;
        RECT  4.32 334.848 291.6 335.136 ;
        RECT  4.32 330.528 291.6 330.816 ;
        RECT  4.32 326.208 291.6 326.496 ;
        RECT  4.32 321.888 291.6 322.176 ;
        RECT  4.32 317.568 291.6 317.856 ;
        RECT  4.32 313.248 291.6 313.536 ;
        RECT  4.32 308.928 291.6 309.216 ;
        RECT  4.32 304.608 291.6 304.896 ;
        RECT  4.32 300.288 291.6 300.576 ;
        RECT  4.32 295.968 291.6 296.256 ;
        RECT  4.32 291.648 291.6 291.936 ;
        RECT  4.32 287.328 291.6 287.616 ;
        RECT  4.32 283.008 291.6 283.296 ;
        RECT  4.32 278.688 291.6 278.976 ;
        RECT  4.32 274.368 291.6 274.656 ;
        RECT  4.32 270.048 291.6 270.336 ;
        RECT  4.32 265.728 291.6 266.016 ;
        RECT  4.32 261.408 291.6 261.696 ;
        RECT  4.32 257.088 291.6 257.376 ;
        RECT  4.32 252.768 291.6 253.056 ;
        RECT  4.32 248.448 291.6 248.736 ;
        RECT  4.32 244.128 291.6 244.416 ;
        RECT  4.32 239.808 291.6 240.096 ;
        RECT  4.32 235.488 291.6 235.776 ;
        RECT  4.32 231.168 291.6 231.456 ;
        RECT  4.32 226.848 291.6 227.136 ;
        RECT  4.32 222.528 291.6 222.816 ;
        RECT  4.32 218.208 291.6 218.496 ;
        RECT  4.32 213.888 291.6 214.176 ;
        RECT  4.32 209.568 291.6 209.856 ;
        RECT  4.32 205.248 291.6 205.536 ;
        RECT  4.32 200.928 291.6 201.216 ;
        RECT  4.32 196.608 291.6 196.896 ;
        RECT  4.32 192.288 291.6 192.576 ;
        RECT  4.32 187.968 291.6 188.256 ;
        RECT  4.32 183.648 291.6 183.936 ;
        RECT  4.32 179.328 291.6 179.616 ;
        RECT  4.32 175.008 291.6 175.296 ;
        RECT  4.32 170.688 291.6 170.976 ;
        RECT  4.32 166.368 291.6 166.656 ;
        RECT  4.32 162.048 291.6 162.336 ;
        RECT  4.32 157.728 291.6 158.016 ;
        RECT  4.32 153.408 291.6 153.696 ;
        RECT  4.32 149.088 291.6 149.376 ;
        RECT  4.32 144.768 291.6 145.056 ;
        RECT  4.32 140.448 291.6 140.736 ;
        RECT  4.32 136.128 291.6 136.416 ;
        RECT  4.32 131.808 291.6 132.096 ;
        RECT  4.32 127.488 291.6 127.776 ;
        RECT  4.32 123.168 291.6 123.456 ;
        RECT  4.32 118.848 291.6 119.136 ;
        RECT  4.32 114.528 291.6 114.816 ;
        RECT  4.32 110.208 291.6 110.496 ;
        RECT  4.32 105.888 291.6 106.176 ;
        RECT  4.32 101.568 291.6 101.856 ;
        RECT  4.32 97.248 291.6 97.536 ;
        RECT  4.32 92.928 291.6 93.216 ;
        RECT  4.32 88.608 291.6 88.896 ;
        RECT  4.32 84.288 291.6 84.576 ;
        RECT  4.32 79.968 291.6 80.256 ;
        RECT  4.32 75.648 291.6 75.936 ;
        RECT  4.32 71.328 291.6 71.616 ;
        RECT  4.32 67.008 291.6 67.296 ;
        RECT  4.32 62.688 291.6 62.976 ;
        RECT  4.32 58.368 291.6 58.656 ;
        RECT  4.32 54.048 291.6 54.336 ;
        RECT  4.32 49.728 291.6 50.016 ;
        RECT  4.32 45.408 291.6 45.696 ;
        RECT  4.32 41.088 291.6 41.376 ;
        RECT  4.32 36.768 291.6 37.056 ;
        RECT  4.32 32.448 291.6 32.736 ;
        RECT  4.32 28.128 291.6 28.416 ;
        RECT  4.32 23.808 291.6 24.096 ;
        RECT  4.32 19.488 291.6 19.776 ;
        RECT  4.32 15.168 291.6 15.456 ;
        RECT  4.32 10.848 291.6 11.136 ;
        RECT  4.32 6.528 291.6 6.816 ;
    END
  END VDD
  PIN VSS
    DIRECTION INOUT ;
    USE GROUND ;
    PORT
      LAYER M6 ;
        RECT  4.32 438.144 291.6 438.432 ;
        RECT  4.32 433.824 291.6 434.112 ;
        RECT  4.32 429.504 291.6 429.792 ;
        RECT  4.32 425.184 291.6 425.472 ;
        RECT  4.32 420.864 291.6 421.152 ;
        RECT  4.32 416.544 291.6 416.832 ;
        RECT  4.32 412.224 291.6 412.512 ;
        RECT  4.32 407.904 291.6 408.192 ;
        RECT  4.32 403.584 291.6 403.872 ;
        RECT  4.32 399.264 291.6 399.552 ;
        RECT  4.32 394.944 291.6 395.232 ;
        RECT  4.32 390.624 291.6 390.912 ;
        RECT  4.32 386.304 291.6 386.592 ;
        RECT  4.32 381.984 291.6 382.272 ;
        RECT  4.32 377.664 291.6 377.952 ;
        RECT  4.32 373.344 291.6 373.632 ;
        RECT  4.32 369.024 291.6 369.312 ;
        RECT  4.32 364.704 291.6 364.992 ;
        RECT  4.32 360.384 291.6 360.672 ;
        RECT  4.32 356.064 291.6 356.352 ;
        RECT  4.32 351.744 291.6 352.032 ;
        RECT  4.32 347.424 291.6 347.712 ;
        RECT  4.32 343.104 291.6 343.392 ;
        RECT  4.32 338.784 291.6 339.072 ;
        RECT  4.32 334.464 291.6 334.752 ;
        RECT  4.32 330.144 291.6 330.432 ;
        RECT  4.32 325.824 291.6 326.112 ;
        RECT  4.32 321.504 291.6 321.792 ;
        RECT  4.32 317.184 291.6 317.472 ;
        RECT  4.32 312.864 291.6 313.152 ;
        RECT  4.32 308.544 291.6 308.832 ;
        RECT  4.32 304.224 291.6 304.512 ;
        RECT  4.32 299.904 291.6 300.192 ;
        RECT  4.32 295.584 291.6 295.872 ;
        RECT  4.32 291.264 291.6 291.552 ;
        RECT  4.32 286.944 291.6 287.232 ;
        RECT  4.32 282.624 291.6 282.912 ;
        RECT  4.32 278.304 291.6 278.592 ;
        RECT  4.32 273.984 291.6 274.272 ;
        RECT  4.32 269.664 291.6 269.952 ;
        RECT  4.32 265.344 291.6 265.632 ;
        RECT  4.32 261.024 291.6 261.312 ;
        RECT  4.32 256.704 291.6 256.992 ;
        RECT  4.32 252.384 291.6 252.672 ;
        RECT  4.32 248.064 291.6 248.352 ;
        RECT  4.32 243.744 291.6 244.032 ;
        RECT  4.32 239.424 291.6 239.712 ;
        RECT  4.32 235.104 291.6 235.392 ;
        RECT  4.32 230.784 291.6 231.072 ;
        RECT  4.32 226.464 291.6 226.752 ;
        RECT  4.32 222.144 291.6 222.432 ;
        RECT  4.32 217.824 291.6 218.112 ;
        RECT  4.32 213.504 291.6 213.792 ;
        RECT  4.32 209.184 291.6 209.472 ;
        RECT  4.32 204.864 291.6 205.152 ;
        RECT  4.32 200.544 291.6 200.832 ;
        RECT  4.32 196.224 291.6 196.512 ;
        RECT  4.32 191.904 291.6 192.192 ;
        RECT  4.32 187.584 291.6 187.872 ;
        RECT  4.32 183.264 291.6 183.552 ;
        RECT  4.32 178.944 291.6 179.232 ;
        RECT  4.32 174.624 291.6 174.912 ;
        RECT  4.32 170.304 291.6 170.592 ;
        RECT  4.32 165.984 291.6 166.272 ;
        RECT  4.32 161.664 291.6 161.952 ;
        RECT  4.32 157.344 291.6 157.632 ;
        RECT  4.32 153.024 291.6 153.312 ;
        RECT  4.32 148.704 291.6 148.992 ;
        RECT  4.32 144.384 291.6 144.672 ;
        RECT  4.32 140.064 291.6 140.352 ;
        RECT  4.32 135.744 291.6 136.032 ;
        RECT  4.32 131.424 291.6 131.712 ;
        RECT  4.32 127.104 291.6 127.392 ;
        RECT  4.32 122.784 291.6 123.072 ;
        RECT  4.32 118.464 291.6 118.752 ;
        RECT  4.32 114.144 291.6 114.432 ;
        RECT  4.32 109.824 291.6 110.112 ;
        RECT  4.32 105.504 291.6 105.792 ;
        RECT  4.32 101.184 291.6 101.472 ;
        RECT  4.32 96.864 291.6 97.152 ;
        RECT  4.32 92.544 291.6 92.832 ;
        RECT  4.32 88.224 291.6 88.512 ;
        RECT  4.32 83.904 291.6 84.192 ;
        RECT  4.32 79.584 291.6 79.872 ;
        RECT  4.32 75.264 291.6 75.552 ;
        RECT  4.32 70.944 291.6 71.232 ;
        RECT  4.32 66.624 291.6 66.912 ;
        RECT  4.32 62.304 291.6 62.592 ;
        RECT  4.32 57.984 291.6 58.272 ;
        RECT  4.32 53.664 291.6 53.952 ;
        RECT  4.32 49.344 291.6 49.632 ;
        RECT  4.32 45.024 291.6 45.312 ;
        RECT  4.32 40.704 291.6 40.992 ;
        RECT  4.32 36.384 291.6 36.672 ;
        RECT  4.32 32.064 291.6 32.352 ;
        RECT  4.32 27.744 291.6 28.032 ;
        RECT  4.32 23.424 291.6 23.712 ;
        RECT  4.32 19.104 291.6 19.392 ;
        RECT  4.32 14.784 291.6 15.072 ;
        RECT  4.32 10.464 291.6 10.752 ;
        RECT  4.32 6.144 291.6 6.432 ;
    END
  END VSS
  OBS
    LAYER RVTN ;
     RECT  4.32 0 295.92 444.96 ;
    LAYER RVTP ;
     RECT  4.32 0 295.92 444.96 ;
    LAYER M1 ;
     RECT  4.32 0 295.92 444.96 ;
    LAYER M2 ;
     RECT  4.32 0 295.92 444.96 ;
    LAYER M3 ;
     RECT  4.32 0 295.92 444.96 ;
    LAYER M4 ;
     RECT  4.32 0 295.92 444.96 ;
    LAYER M5 ;
     RECT  4.32 0 295.92 444.96 ;
    LAYER M6 ;
     RECT  4.32 0 295.92 444.96 ;
  END
END dsfd_coll_lane_w_safe8_ntf
END LIBRARY
